VERSION 5.8 ;
BUSBITCHARS "[]" ;
DIVIDERCHAR "/" ;
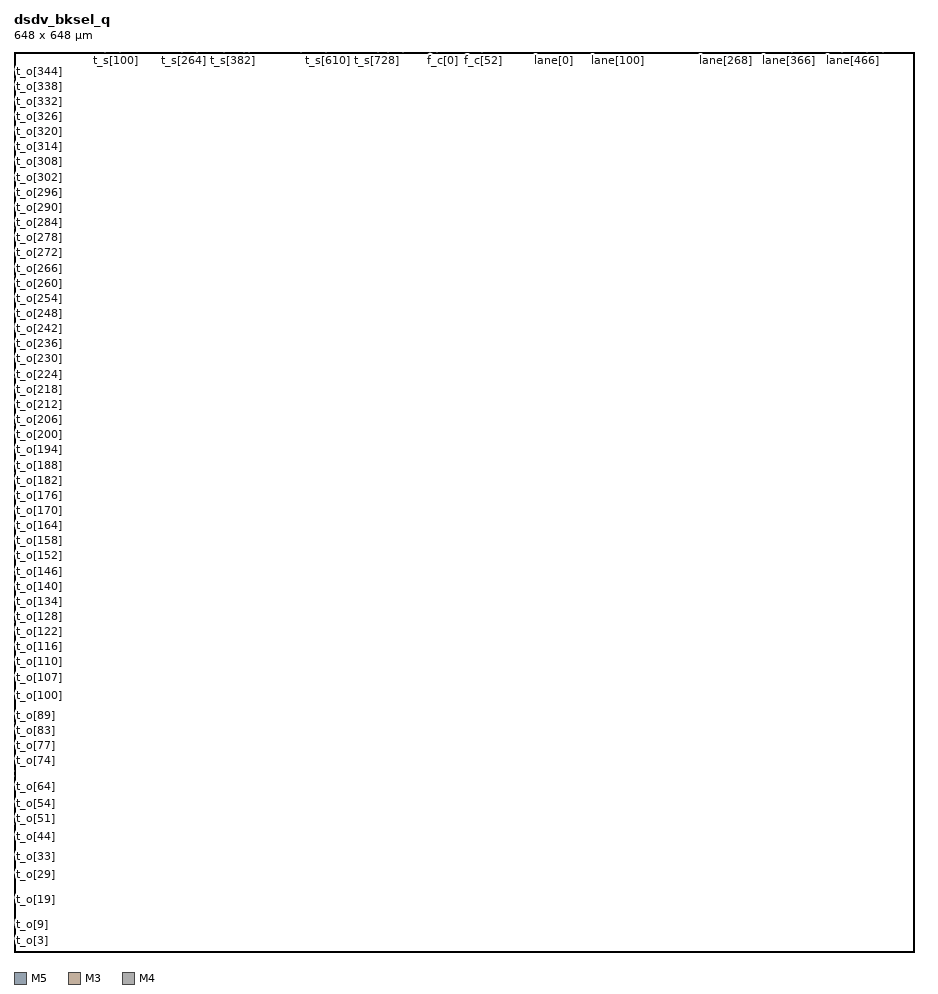
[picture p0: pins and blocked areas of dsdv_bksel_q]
MACRO dsdv_bksel_q
  CLASS BLOCK ;
  ORIGIN 0 0 ;
  FOREIGN dsdv_bksel_q 0 0 ;
  SIZE 648 BY 648 ;
  SYMMETRY X Y ;
  PIN ck
    DIRECTION INPUT ;
    USE SIGNAL ;
    PORT
      LAYER M5 ;
        RECT 304.5480 647.5200 304.5960 648.0000 ;
    END
  END ck
  PIN f_c[0]
    DIRECTION INPUT ;
    USE SIGNAL ;
    PORT
      LAYER M3 ;
        RECT 309.1320 647.9620 309.1500 648.0000 ;
    END
  END f_c[0]
  PIN f_c[10]
    DIRECTION INPUT ;
    USE SIGNAL ;
    PORT
      LAYER M3 ;
        RECT 314.7120 647.9620 314.7300 648.0000 ;
    END
  END f_c[10]
  PIN f_c[11]
    DIRECTION INPUT ;
    USE SIGNAL ;
    PORT
      LAYER M5 ;
        RECT 315.2640 647.9160 315.2880 648.0000 ;
    END
  END f_c[11]
  PIN f_c[12]
    DIRECTION INPUT ;
    USE SIGNAL ;
    PORT
      LAYER M3 ;
        RECT 315.8280 647.9620 315.8460 648.0000 ;
    END
  END f_c[12]
  PIN f_c[13]
    DIRECTION INPUT ;
    USE SIGNAL ;
    PORT
      LAYER M5 ;
        RECT 316.3680 647.9160 316.3920 648.0000 ;
    END
  END f_c[13]
  PIN f_c[14]
    DIRECTION INPUT ;
    USE SIGNAL ;
    PORT
      LAYER M3 ;
        RECT 316.9440 647.9620 316.9620 648.0000 ;
    END
  END f_c[14]
  PIN f_c[15]
    DIRECTION INPUT ;
    USE SIGNAL ;
    PORT
      LAYER M5 ;
        RECT 317.4720 647.9160 317.4960 648.0000 ;
    END
  END f_c[15]
  PIN f_c[16]
    DIRECTION INPUT ;
    USE SIGNAL ;
    PORT
      LAYER M3 ;
        RECT 318.0600 647.9620 318.0780 648.0000 ;
    END
  END f_c[16]
  PIN f_c[17]
    DIRECTION INPUT ;
    USE SIGNAL ;
    PORT
      LAYER M5 ;
        RECT 318.6240 647.9160 318.6480 648.0000 ;
    END
  END f_c[17]
  PIN f_c[18]
    DIRECTION INPUT ;
    USE SIGNAL ;
    PORT
      LAYER M3 ;
        RECT 319.1760 647.9620 319.1940 648.0000 ;
    END
  END f_c[18]
  PIN f_c[19]
    DIRECTION INPUT ;
    USE SIGNAL ;
    PORT
      LAYER M5 ;
        RECT 319.7280 647.9160 319.7520 648.0000 ;
    END
  END f_c[19]
  PIN f_c[1]
    DIRECTION INPUT ;
    USE SIGNAL ;
    PORT
      LAYER M5 ;
        RECT 309.6960 647.9160 309.7200 648.0000 ;
    END
  END f_c[1]
  PIN f_c[20]
    DIRECTION INPUT ;
    USE SIGNAL ;
    PORT
      LAYER M3 ;
        RECT 320.2920 647.9620 320.3100 648.0000 ;
    END
  END f_c[20]
  PIN f_c[21]
    DIRECTION INPUT ;
    USE SIGNAL ;
    PORT
      LAYER M5 ;
        RECT 320.8320 647.9160 320.8560 648.0000 ;
    END
  END f_c[21]
  PIN f_c[22]
    DIRECTION INPUT ;
    USE SIGNAL ;
    PORT
      LAYER M3 ;
        RECT 321.3720 647.9620 321.3900 648.0000 ;
    END
  END f_c[22]
  PIN f_c[23]
    DIRECTION INPUT ;
    USE SIGNAL ;
    PORT
      LAYER M5 ;
        RECT 321.9360 647.9160 321.9600 648.0000 ;
    END
  END f_c[23]
  PIN f_c[24]
    DIRECTION INPUT ;
    USE SIGNAL ;
    PORT
      LAYER M3 ;
        RECT 322.4880 647.9620 322.5060 648.0000 ;
    END
  END f_c[24]
  PIN f_c[25]
    DIRECTION INPUT ;
    USE SIGNAL ;
    PORT
      LAYER M5 ;
        RECT 323.0400 647.9160 323.0640 648.0000 ;
    END
  END f_c[25]
  PIN f_c[26]
    DIRECTION INPUT ;
    USE SIGNAL ;
    PORT
      LAYER M3 ;
        RECT 323.6040 647.9620 323.6220 648.0000 ;
    END
  END f_c[26]
  PIN f_c[27]
    DIRECTION INPUT ;
    USE SIGNAL ;
    PORT
      LAYER M5 ;
        RECT 324.1920 647.9160 324.2160 648.0000 ;
    END
  END f_c[27]
  PIN f_c[28]
    DIRECTION INPUT ;
    USE SIGNAL ;
    PORT
      LAYER M3 ;
        RECT 324.7200 647.9620 324.7380 648.0000 ;
    END
  END f_c[28]
  PIN f_c[29]
    DIRECTION INPUT ;
    USE SIGNAL ;
    PORT
      LAYER M5 ;
        RECT 325.2960 647.9160 325.3200 648.0000 ;
    END
  END f_c[29]
  PIN f_c[2]
    DIRECTION INPUT ;
    USE SIGNAL ;
    PORT
      LAYER M3 ;
        RECT 310.2480 647.9620 310.2660 648.0000 ;
    END
  END f_c[2]
  PIN f_c[30]
    DIRECTION INPUT ;
    USE SIGNAL ;
    PORT
      LAYER M3 ;
        RECT 325.8360 647.9620 325.8540 648.0000 ;
    END
  END f_c[30]
  PIN f_c[31]
    DIRECTION INPUT ;
    USE SIGNAL ;
    PORT
      LAYER M5 ;
        RECT 326.4000 647.9160 326.4240 648.0000 ;
    END
  END f_c[31]
  PIN f_c[32]
    DIRECTION INPUT ;
    USE SIGNAL ;
    PORT
      LAYER M3 ;
        RECT 326.9520 647.9620 326.9700 648.0000 ;
    END
  END f_c[32]
  PIN f_c[33]
    DIRECTION INPUT ;
    USE SIGNAL ;
    PORT
      LAYER M5 ;
        RECT 327.5040 647.9160 327.5280 648.0000 ;
    END
  END f_c[33]
  PIN f_c[34]
    DIRECTION INPUT ;
    USE SIGNAL ;
    PORT
      LAYER M3 ;
        RECT 328.0680 647.9620 328.0860 648.0000 ;
    END
  END f_c[34]
  PIN f_c[35]
    DIRECTION INPUT ;
    USE SIGNAL ;
    PORT
      LAYER M5 ;
        RECT 328.6080 647.9160 328.6320 648.0000 ;
    END
  END f_c[35]
  PIN f_c[36]
    DIRECTION INPUT ;
    USE SIGNAL ;
    PORT
      LAYER M3 ;
        RECT 329.1840 647.9620 329.2020 648.0000 ;
    END
  END f_c[36]
  PIN f_c[37]
    DIRECTION INPUT ;
    USE SIGNAL ;
    PORT
      LAYER M5 ;
        RECT 329.7120 647.9160 329.7360 648.0000 ;
    END
  END f_c[37]
  PIN f_c[38]
    DIRECTION INPUT ;
    USE SIGNAL ;
    PORT
      LAYER M3 ;
        RECT 330.3000 647.9620 330.3180 648.0000 ;
    END
  END f_c[38]
  PIN f_c[39]
    DIRECTION INPUT ;
    USE SIGNAL ;
    PORT
      LAYER M5 ;
        RECT 330.8640 647.9160 330.8880 648.0000 ;
    END
  END f_c[39]
  PIN f_c[3]
    DIRECTION INPUT ;
    USE SIGNAL ;
    PORT
      LAYER M5 ;
        RECT 310.8000 647.9160 310.8240 648.0000 ;
    END
  END f_c[3]
  PIN f_c[40]
    DIRECTION INPUT ;
    USE SIGNAL ;
    PORT
      LAYER M3 ;
        RECT 331.4160 647.9620 331.4340 648.0000 ;
    END
  END f_c[40]
  PIN f_c[41]
    DIRECTION INPUT ;
    USE SIGNAL ;
    PORT
      LAYER M5 ;
        RECT 331.9680 647.9160 331.9920 648.0000 ;
    END
  END f_c[41]
  PIN f_c[42]
    DIRECTION INPUT ;
    USE SIGNAL ;
    PORT
      LAYER M3 ;
        RECT 332.5320 647.9620 332.5500 648.0000 ;
    END
  END f_c[42]
  PIN f_c[43]
    DIRECTION INPUT ;
    USE SIGNAL ;
    PORT
      LAYER M5 ;
        RECT 333.0720 647.9160 333.0960 648.0000 ;
    END
  END f_c[43]
  PIN f_c[44]
    DIRECTION INPUT ;
    USE SIGNAL ;
    PORT
      LAYER M3 ;
        RECT 333.6120 647.9620 333.6300 648.0000 ;
    END
  END f_c[44]
  PIN f_c[45]
    DIRECTION INPUT ;
    USE SIGNAL ;
    PORT
      LAYER M5 ;
        RECT 334.1760 647.9160 334.2000 648.0000 ;
    END
  END f_c[45]
  PIN f_c[46]
    DIRECTION INPUT ;
    USE SIGNAL ;
    PORT
      LAYER M3 ;
        RECT 334.7280 647.9620 334.7460 648.0000 ;
    END
  END f_c[46]
  PIN f_c[47]
    DIRECTION INPUT ;
    USE SIGNAL ;
    PORT
      LAYER M5 ;
        RECT 335.2800 647.9160 335.3040 648.0000 ;
    END
  END f_c[47]
  PIN f_c[48]
    DIRECTION INPUT ;
    USE SIGNAL ;
    PORT
      LAYER M3 ;
        RECT 335.8440 647.9620 335.8620 648.0000 ;
    END
  END f_c[48]
  PIN f_c[49]
    DIRECTION INPUT ;
    USE SIGNAL ;
    PORT
      LAYER M5 ;
        RECT 336.4320 647.9160 336.4560 648.0000 ;
    END
  END f_c[49]
  PIN f_c[4]
    DIRECTION INPUT ;
    USE SIGNAL ;
    PORT
      LAYER M3 ;
        RECT 311.3640 647.9620 311.3820 648.0000 ;
    END
  END f_c[4]
  PIN f_c[50]
    DIRECTION INPUT ;
    USE SIGNAL ;
    PORT
      LAYER M3 ;
        RECT 336.9600 647.9620 336.9780 648.0000 ;
    END
  END f_c[50]
  PIN f_c[51]
    DIRECTION INPUT ;
    USE SIGNAL ;
    PORT
      LAYER M5 ;
        RECT 337.5360 647.9160 337.5600 648.0000 ;
    END
  END f_c[51]
  PIN f_c[52]
    DIRECTION INPUT ;
    USE SIGNAL ;
    PORT
      LAYER M3 ;
        RECT 338.0760 647.9620 338.0940 648.0000 ;
    END
  END f_c[52]
  PIN f_c[53]
    DIRECTION INPUT ;
    USE SIGNAL ;
    PORT
      LAYER M5 ;
        RECT 338.6400 647.9160 338.6640 648.0000 ;
    END
  END f_c[53]
  PIN f_c[54]
    DIRECTION INPUT ;
    USE SIGNAL ;
    PORT
      LAYER M3 ;
        RECT 339.1920 647.9620 339.2100 648.0000 ;
    END
  END f_c[54]
  PIN f_c[55]
    DIRECTION INPUT ;
    USE SIGNAL ;
    PORT
      LAYER M5 ;
        RECT 339.7440 647.9160 339.7680 648.0000 ;
    END
  END f_c[55]
  PIN f_c[56]
    DIRECTION INPUT ;
    USE SIGNAL ;
    PORT
      LAYER M3 ;
        RECT 340.3080 647.9620 340.3260 648.0000 ;
    END
  END f_c[56]
  PIN f_c[57]
    DIRECTION INPUT ;
    USE SIGNAL ;
    PORT
      LAYER M5 ;
        RECT 340.8480 647.9160 340.8720 648.0000 ;
    END
  END f_c[57]
  PIN f_c[58]
    DIRECTION INPUT ;
    USE SIGNAL ;
    PORT
      LAYER M3 ;
        RECT 341.4240 647.9620 341.4420 648.0000 ;
    END
  END f_c[58]
  PIN f_c[59]
    DIRECTION INPUT ;
    USE SIGNAL ;
    PORT
      LAYER M5 ;
        RECT 341.9520 647.9160 341.9760 648.0000 ;
    END
  END f_c[59]
  PIN f_c[5]
    DIRECTION INPUT ;
    USE SIGNAL ;
    PORT
      LAYER M5 ;
        RECT 311.9520 647.9160 311.9760 648.0000 ;
    END
  END f_c[5]
  PIN f_c[60]
    DIRECTION INPUT ;
    USE SIGNAL ;
    PORT
      LAYER M3 ;
        RECT 342.5400 647.9620 342.5580 648.0000 ;
    END
  END f_c[60]
  PIN f_c[61]
    DIRECTION INPUT ;
    USE SIGNAL ;
    PORT
      LAYER M5 ;
        RECT 343.1040 647.9160 343.1280 648.0000 ;
    END
  END f_c[61]
  PIN f_c[62]
    DIRECTION INPUT ;
    USE SIGNAL ;
    PORT
      LAYER M3 ;
        RECT 343.6560 647.9620 343.6740 648.0000 ;
    END
  END f_c[62]
  PIN f_c[63]
    DIRECTION INPUT ;
    USE SIGNAL ;
    PORT
      LAYER M5 ;
        RECT 344.2080 647.9160 344.2320 648.0000 ;
    END
  END f_c[63]
  PIN f_c[64]
    DIRECTION INPUT ;
    USE SIGNAL ;
    PORT
      LAYER M3 ;
        RECT 344.7720 647.9620 344.7900 648.0000 ;
    END
  END f_c[64]
  PIN f_c[65]
    DIRECTION INPUT ;
    USE SIGNAL ;
    PORT
      LAYER M5 ;
        RECT 345.3120 647.9160 345.3360 648.0000 ;
    END
  END f_c[65]
  PIN f_c[6]
    DIRECTION INPUT ;
    USE SIGNAL ;
    PORT
      LAYER M3 ;
        RECT 312.4800 647.9620 312.4980 648.0000 ;
    END
  END f_c[6]
  PIN f_c[7]
    DIRECTION INPUT ;
    USE SIGNAL ;
    PORT
      LAYER M5 ;
        RECT 313.0560 647.9160 313.0800 648.0000 ;
    END
  END f_c[7]
  PIN f_c[8]
    DIRECTION INPUT ;
    USE SIGNAL ;
    PORT
      LAYER M3 ;
        RECT 313.5960 647.9620 313.6140 648.0000 ;
    END
  END f_c[8]
  PIN f_c[9]
    DIRECTION INPUT ;
    USE SIGNAL ;
    PORT
      LAYER M5 ;
        RECT 314.1600 647.9160 314.1840 648.0000 ;
    END
  END f_c[9]
  PIN f_cr
    DIRECTION INPUT ;
    USE SIGNAL ;
    PORT
      LAYER M3 ;
        RECT 346.6800 647.9620 346.6980 648.0000 ;
    END
  END f_cr
  PIN lane[0]
    DIRECTION INPUT ;
    USE SIGNAL ;
    PORT
      LAYER M3 ;
        RECT 389.0160 647.9620 389.0340 648.0000 ;
    END
  END lane[0]
  PIN lane[100]
    DIRECTION INPUT ;
    USE SIGNAL ;
    PORT
      LAYER M3 ;
        RECT 435.1680 647.9620 435.1860 648.0000 ;
    END
  END lane[100]
  PIN lane[101]
    DIRECTION INPUT ;
    USE SIGNAL ;
    PORT
      LAYER M5 ;
        RECT 435.6000 647.9160 435.6240 648.0000 ;
    END
  END lane[101]
  PIN lane[102]
    DIRECTION INPUT ;
    USE SIGNAL ;
    PORT
      LAYER M3 ;
        RECT 436.0680 647.9620 436.0860 648.0000 ;
    END
  END lane[102]
  PIN lane[103]
    DIRECTION INPUT ;
    USE SIGNAL ;
    PORT
      LAYER M5 ;
        RECT 436.5600 647.9160 436.5840 648.0000 ;
    END
  END lane[103]
  PIN lane[104]
    DIRECTION INPUT ;
    USE SIGNAL ;
    PORT
      LAYER M3 ;
        RECT 437.0040 647.9620 437.0220 648.0000 ;
    END
  END lane[104]
  PIN lane[105]
    DIRECTION INPUT ;
    USE SIGNAL ;
    PORT
      LAYER M5 ;
        RECT 437.4720 647.9160 437.4960 648.0000 ;
    END
  END lane[105]
  PIN lane[106]
    DIRECTION INPUT ;
    USE SIGNAL ;
    PORT
      LAYER M3 ;
        RECT 437.9400 647.9620 437.9580 648.0000 ;
    END
  END lane[106]
  PIN lane[107]
    DIRECTION INPUT ;
    USE SIGNAL ;
    PORT
      LAYER M5 ;
        RECT 438.3840 647.9160 438.4080 648.0000 ;
    END
  END lane[107]
  PIN lane[108]
    DIRECTION INPUT ;
    USE SIGNAL ;
    PORT
      LAYER M3 ;
        RECT 438.8400 647.9620 438.8580 648.0000 ;
    END
  END lane[108]
  PIN lane[109]
    DIRECTION INPUT ;
    USE SIGNAL ;
    PORT
      LAYER M5 ;
        RECT 439.2960 647.9160 439.3200 648.0000 ;
    END
  END lane[109]
  PIN lane[10]
    DIRECTION INPUT ;
    USE SIGNAL ;
    PORT
      LAYER M3 ;
        RECT 393.6240 647.9620 393.6420 648.0000 ;
    END
  END lane[10]
  PIN lane[110]
    DIRECTION INPUT ;
    USE SIGNAL ;
    PORT
      LAYER M3 ;
        RECT 439.7760 647.9620 439.7940 648.0000 ;
    END
  END lane[110]
  PIN lane[111]
    DIRECTION INPUT ;
    USE SIGNAL ;
    PORT
      LAYER M5 ;
        RECT 440.2080 647.9160 440.2320 648.0000 ;
    END
  END lane[111]
  PIN lane[112]
    DIRECTION INPUT ;
    USE SIGNAL ;
    PORT
      LAYER M3 ;
        RECT 440.7120 647.9620 440.7300 648.0000 ;
    END
  END lane[112]
  PIN lane[113]
    DIRECTION INPUT ;
    USE SIGNAL ;
    PORT
      LAYER M5 ;
        RECT 441.1680 647.9160 441.1920 648.0000 ;
    END
  END lane[113]
  PIN lane[114]
    DIRECTION INPUT ;
    USE SIGNAL ;
    PORT
      LAYER M3 ;
        RECT 441.6120 647.9620 441.6300 648.0000 ;
    END
  END lane[114]
  PIN lane[115]
    DIRECTION INPUT ;
    USE SIGNAL ;
    PORT
      LAYER M5 ;
        RECT 442.0800 647.9160 442.1040 648.0000 ;
    END
  END lane[115]
  PIN lane[116]
    DIRECTION INPUT ;
    USE SIGNAL ;
    PORT
      LAYER M3 ;
        RECT 442.5480 647.9620 442.5660 648.0000 ;
    END
  END lane[116]
  PIN lane[117]
    DIRECTION INPUT ;
    USE SIGNAL ;
    PORT
      LAYER M5 ;
        RECT 442.9920 647.9160 443.0160 648.0000 ;
    END
  END lane[117]
  PIN lane[118]
    DIRECTION INPUT ;
    USE SIGNAL ;
    PORT
      LAYER M3 ;
        RECT 443.4480 647.9620 443.4660 648.0000 ;
    END
  END lane[118]
  PIN lane[119]
    DIRECTION INPUT ;
    USE SIGNAL ;
    PORT
      LAYER M5 ;
        RECT 443.9040 647.9160 443.9280 648.0000 ;
    END
  END lane[119]
  PIN lane[11]
    DIRECTION INPUT ;
    USE SIGNAL ;
    PORT
      LAYER M5 ;
        RECT 394.0800 647.9160 394.1040 648.0000 ;
    END
  END lane[11]
  PIN lane[120]
    DIRECTION INPUT ;
    USE SIGNAL ;
    PORT
      LAYER M3 ;
        RECT 444.3840 647.9620 444.4020 648.0000 ;
    END
  END lane[120]
  PIN lane[121]
    DIRECTION INPUT ;
    USE SIGNAL ;
    PORT
      LAYER M5 ;
        RECT 444.8640 647.9160 444.8880 648.0000 ;
    END
  END lane[121]
  PIN lane[122]
    DIRECTION INPUT ;
    USE SIGNAL ;
    PORT
      LAYER M3 ;
        RECT 445.3560 647.9620 445.3740 648.0000 ;
    END
  END lane[122]
  PIN lane[123]
    DIRECTION INPUT ;
    USE SIGNAL ;
    PORT
      LAYER M5 ;
        RECT 445.7760 647.9160 445.8000 648.0000 ;
    END
  END lane[123]
  PIN lane[124]
    DIRECTION INPUT ;
    USE SIGNAL ;
    PORT
      LAYER M3 ;
        RECT 446.2200 647.9620 446.2380 648.0000 ;
    END
  END lane[124]
  PIN lane[125]
    DIRECTION INPUT ;
    USE SIGNAL ;
    PORT
      LAYER M5 ;
        RECT 446.6880 647.9160 446.7120 648.0000 ;
    END
  END lane[125]
  PIN lane[126]
    DIRECTION INPUT ;
    USE SIGNAL ;
    PORT
      LAYER M3 ;
        RECT 447.1560 647.9620 447.1740 648.0000 ;
    END
  END lane[126]
  PIN lane[127]
    DIRECTION INPUT ;
    USE SIGNAL ;
    PORT
      LAYER M5 ;
        RECT 447.6000 647.9160 447.6240 648.0000 ;
    END
  END lane[127]
  PIN lane[128]
    DIRECTION INPUT ;
    USE SIGNAL ;
    PORT
      LAYER M3 ;
        RECT 448.0920 647.9620 448.1100 648.0000 ;
    END
  END lane[128]
  PIN lane[129]
    DIRECTION INPUT ;
    USE SIGNAL ;
    PORT
      LAYER M5 ;
        RECT 448.5120 647.9160 448.5360 648.0000 ;
    END
  END lane[129]
  PIN lane[12]
    DIRECTION INPUT ;
    USE SIGNAL ;
    PORT
      LAYER M3 ;
        RECT 394.5600 647.9620 394.5780 648.0000 ;
    END
  END lane[12]
  PIN lane[130]
    DIRECTION INPUT ;
    USE SIGNAL ;
    PORT
      LAYER M3 ;
        RECT 448.9920 647.9620 449.0100 648.0000 ;
    END
  END lane[130]
  PIN lane[131]
    DIRECTION INPUT ;
    USE SIGNAL ;
    PORT
      LAYER M5 ;
        RECT 449.4720 647.9160 449.4960 648.0000 ;
    END
  END lane[131]
  PIN lane[132]
    DIRECTION INPUT ;
    USE SIGNAL ;
    PORT
      LAYER M3 ;
        RECT 449.9280 647.9620 449.9460 648.0000 ;
    END
  END lane[132]
  PIN lane[133]
    DIRECTION INPUT ;
    USE SIGNAL ;
    PORT
      LAYER M5 ;
        RECT 450.3840 647.9160 450.4080 648.0000 ;
    END
  END lane[133]
  PIN lane[134]
    DIRECTION INPUT ;
    USE SIGNAL ;
    PORT
      LAYER M3 ;
        RECT 450.8280 647.9620 450.8460 648.0000 ;
    END
  END lane[134]
  PIN lane[135]
    DIRECTION INPUT ;
    USE SIGNAL ;
    PORT
      LAYER M5 ;
        RECT 451.2960 647.9160 451.3200 648.0000 ;
    END
  END lane[135]
  PIN lane[136]
    DIRECTION INPUT ;
    USE SIGNAL ;
    PORT
      LAYER M3 ;
        RECT 451.7640 647.9620 451.7820 648.0000 ;
    END
  END lane[136]
  PIN lane[137]
    DIRECTION INPUT ;
    USE SIGNAL ;
    PORT
      LAYER M5 ;
        RECT 452.2080 647.9160 452.2320 648.0000 ;
    END
  END lane[137]
  PIN lane[138]
    DIRECTION INPUT ;
    USE SIGNAL ;
    PORT
      LAYER M3 ;
        RECT 452.7000 647.9620 452.7180 648.0000 ;
    END
  END lane[138]
  PIN lane[139]
    DIRECTION INPUT ;
    USE SIGNAL ;
    PORT
      LAYER M5 ;
        RECT 453.1680 647.9160 453.1920 648.0000 ;
    END
  END lane[139]
  PIN lane[13]
    DIRECTION INPUT ;
    USE SIGNAL ;
    PORT
      LAYER M5 ;
        RECT 395.0400 647.9160 395.0640 648.0000 ;
    END
  END lane[13]
  PIN lane[140]
    DIRECTION INPUT ;
    USE SIGNAL ;
    PORT
      LAYER M3 ;
        RECT 453.6000 647.9620 453.6180 648.0000 ;
    END
  END lane[140]
  PIN lane[141]
    DIRECTION INPUT ;
    USE SIGNAL ;
    PORT
      LAYER M5 ;
        RECT 454.0800 647.9160 454.1040 648.0000 ;
    END
  END lane[141]
  PIN lane[142]
    DIRECTION INPUT ;
    USE SIGNAL ;
    PORT
      LAYER M3 ;
        RECT 454.5360 647.9620 454.5540 648.0000 ;
    END
  END lane[142]
  PIN lane[143]
    DIRECTION INPUT ;
    USE SIGNAL ;
    PORT
      LAYER M5 ;
        RECT 454.9920 647.9160 455.0160 648.0000 ;
    END
  END lane[143]
  PIN lane[144]
    DIRECTION INPUT ;
    USE SIGNAL ;
    PORT
      LAYER M3 ;
        RECT 455.4720 647.9620 455.4900 648.0000 ;
    END
  END lane[144]
  PIN lane[145]
    DIRECTION INPUT ;
    USE SIGNAL ;
    PORT
      LAYER M5 ;
        RECT 455.9040 647.9160 455.9280 648.0000 ;
    END
  END lane[145]
  PIN lane[146]
    DIRECTION INPUT ;
    USE SIGNAL ;
    PORT
      LAYER M3 ;
        RECT 456.3720 647.9620 456.3900 648.0000 ;
    END
  END lane[146]
  PIN lane[147]
    DIRECTION INPUT ;
    USE SIGNAL ;
    PORT
      LAYER M5 ;
        RECT 456.8160 647.9160 456.8400 648.0000 ;
    END
  END lane[147]
  PIN lane[148]
    DIRECTION INPUT ;
    USE SIGNAL ;
    PORT
      LAYER M3 ;
        RECT 457.3080 647.9620 457.3260 648.0000 ;
    END
  END lane[148]
  PIN lane[149]
    DIRECTION INPUT ;
    USE SIGNAL ;
    PORT
      LAYER M5 ;
        RECT 457.7760 647.9160 457.8000 648.0000 ;
    END
  END lane[149]
  PIN lane[14]
    DIRECTION INPUT ;
    USE SIGNAL ;
    PORT
      LAYER M3 ;
        RECT 395.4960 647.9620 395.5140 648.0000 ;
    END
  END lane[14]
  PIN lane[150]
    DIRECTION INPUT ;
    USE SIGNAL ;
    PORT
      LAYER M3 ;
        RECT 458.2440 647.9620 458.2620 648.0000 ;
    END
  END lane[150]
  PIN lane[151]
    DIRECTION INPUT ;
    USE SIGNAL ;
    PORT
      LAYER M5 ;
        RECT 458.6880 647.9160 458.7120 648.0000 ;
    END
  END lane[151]
  PIN lane[152]
    DIRECTION INPUT ;
    USE SIGNAL ;
    PORT
      LAYER M3 ;
        RECT 459.1440 647.9620 459.1620 648.0000 ;
    END
  END lane[152]
  PIN lane[153]
    DIRECTION INPUT ;
    USE SIGNAL ;
    PORT
      LAYER M5 ;
        RECT 459.6000 647.9160 459.6240 648.0000 ;
    END
  END lane[153]
  PIN lane[154]
    DIRECTION INPUT ;
    USE SIGNAL ;
    PORT
      LAYER M3 ;
        RECT 460.0800 647.9620 460.0980 648.0000 ;
    END
  END lane[154]
  PIN lane[155]
    DIRECTION INPUT ;
    USE SIGNAL ;
    PORT
      LAYER M5 ;
        RECT 460.5120 647.9160 460.5360 648.0000 ;
    END
  END lane[155]
  PIN lane[156]
    DIRECTION INPUT ;
    USE SIGNAL ;
    PORT
      LAYER M3 ;
        RECT 460.9800 647.9620 460.9980 648.0000 ;
    END
  END lane[156]
  PIN lane[157]
    DIRECTION INPUT ;
    USE SIGNAL ;
    PORT
      LAYER M5 ;
        RECT 461.4720 647.9160 461.4960 648.0000 ;
    END
  END lane[157]
  PIN lane[158]
    DIRECTION INPUT ;
    USE SIGNAL ;
    PORT
      LAYER M3 ;
        RECT 461.9160 647.9620 461.9340 648.0000 ;
    END
  END lane[158]
  PIN lane[159]
    DIRECTION INPUT ;
    USE SIGNAL ;
    PORT
      LAYER M5 ;
        RECT 462.3840 647.9160 462.4080 648.0000 ;
    END
  END lane[159]
  PIN lane[15]
    DIRECTION INPUT ;
    USE SIGNAL ;
    PORT
      LAYER M5 ;
        RECT 395.9520 647.9160 395.9760 648.0000 ;
    END
  END lane[15]
  PIN lane[160]
    DIRECTION INPUT ;
    USE SIGNAL ;
    PORT
      LAYER M3 ;
        RECT 462.8520 647.9620 462.8700 648.0000 ;
    END
  END lane[160]
  PIN lane[161]
    DIRECTION INPUT ;
    USE SIGNAL ;
    PORT
      LAYER M5 ;
        RECT 463.2960 647.9160 463.3200 648.0000 ;
    END
  END lane[161]
  PIN lane[162]
    DIRECTION INPUT ;
    USE SIGNAL ;
    PORT
      LAYER M3 ;
        RECT 463.7520 647.9620 463.7700 648.0000 ;
    END
  END lane[162]
  PIN lane[163]
    DIRECTION INPUT ;
    USE SIGNAL ;
    PORT
      LAYER M5 ;
        RECT 464.2080 647.9160 464.2320 648.0000 ;
    END
  END lane[163]
  PIN lane[164]
    DIRECTION INPUT ;
    USE SIGNAL ;
    PORT
      LAYER M3 ;
        RECT 464.6880 647.9620 464.7060 648.0000 ;
    END
  END lane[164]
  PIN lane[165]
    DIRECTION INPUT ;
    USE SIGNAL ;
    PORT
      LAYER M5 ;
        RECT 465.1200 647.9160 465.1440 648.0000 ;
    END
  END lane[165]
  PIN lane[166]
    DIRECTION INPUT ;
    USE SIGNAL ;
    PORT
      LAYER M3 ;
        RECT 465.6240 647.9620 465.6420 648.0000 ;
    END
  END lane[166]
  PIN lane[167]
    DIRECTION INPUT ;
    USE SIGNAL ;
    PORT
      LAYER M5 ;
        RECT 466.0800 647.9160 466.1040 648.0000 ;
    END
  END lane[167]
  PIN lane[168]
    DIRECTION INPUT ;
    USE SIGNAL ;
    PORT
      LAYER M3 ;
        RECT 466.5240 647.9620 466.5420 648.0000 ;
    END
  END lane[168]
  PIN lane[169]
    DIRECTION INPUT ;
    USE SIGNAL ;
    PORT
      LAYER M5 ;
        RECT 466.9920 647.9160 467.0160 648.0000 ;
    END
  END lane[169]
  PIN lane[16]
    DIRECTION INPUT ;
    USE SIGNAL ;
    PORT
      LAYER M3 ;
        RECT 396.3960 647.9620 396.4140 648.0000 ;
    END
  END lane[16]
  PIN lane[170]
    DIRECTION INPUT ;
    USE SIGNAL ;
    PORT
      LAYER M3 ;
        RECT 467.4600 647.9620 467.4780 648.0000 ;
    END
  END lane[170]
  PIN lane[171]
    DIRECTION INPUT ;
    USE SIGNAL ;
    PORT
      LAYER M5 ;
        RECT 467.9040 647.9160 467.9280 648.0000 ;
    END
  END lane[171]
  PIN lane[172]
    DIRECTION INPUT ;
    USE SIGNAL ;
    PORT
      LAYER M3 ;
        RECT 468.3600 647.9620 468.3780 648.0000 ;
    END
  END lane[172]
  PIN lane[173]
    DIRECTION INPUT ;
    USE SIGNAL ;
    PORT
      LAYER M5 ;
        RECT 468.8160 647.9160 468.8400 648.0000 ;
    END
  END lane[173]
  PIN lane[174]
    DIRECTION INPUT ;
    USE SIGNAL ;
    PORT
      LAYER M3 ;
        RECT 469.2960 647.9620 469.3140 648.0000 ;
    END
  END lane[174]
  PIN lane[175]
    DIRECTION INPUT ;
    USE SIGNAL ;
    PORT
      LAYER M5 ;
        RECT 469.7760 647.9160 469.8000 648.0000 ;
    END
  END lane[175]
  PIN lane[176]
    DIRECTION INPUT ;
    USE SIGNAL ;
    PORT
      LAYER M3 ;
        RECT 470.2320 647.9620 470.2500 648.0000 ;
    END
  END lane[176]
  PIN lane[177]
    DIRECTION INPUT ;
    USE SIGNAL ;
    PORT
      LAYER M5 ;
        RECT 470.6880 647.9160 470.7120 648.0000 ;
    END
  END lane[177]
  PIN lane[178]
    DIRECTION INPUT ;
    USE SIGNAL ;
    PORT
      LAYER M3 ;
        RECT 471.1320 647.9620 471.1500 648.0000 ;
    END
  END lane[178]
  PIN lane[179]
    DIRECTION INPUT ;
    USE SIGNAL ;
    PORT
      LAYER M5 ;
        RECT 471.6000 647.9160 471.6240 648.0000 ;
    END
  END lane[179]
  PIN lane[17]
    DIRECTION INPUT ;
    USE SIGNAL ;
    PORT
      LAYER M5 ;
        RECT 396.8640 647.9160 396.8880 648.0000 ;
    END
  END lane[17]
  PIN lane[180]
    DIRECTION INPUT ;
    USE SIGNAL ;
    PORT
      LAYER M3 ;
        RECT 472.0680 647.9620 472.0860 648.0000 ;
    END
  END lane[180]
  PIN lane[181]
    DIRECTION INPUT ;
    USE SIGNAL ;
    PORT
      LAYER M5 ;
        RECT 472.5120 647.9160 472.5360 648.0000 ;
    END
  END lane[181]
  PIN lane[182]
    DIRECTION INPUT ;
    USE SIGNAL ;
    PORT
      LAYER M3 ;
        RECT 473.0040 647.9620 473.0220 648.0000 ;
    END
  END lane[182]
  PIN lane[183]
    DIRECTION INPUT ;
    USE SIGNAL ;
    PORT
      LAYER M5 ;
        RECT 473.4240 647.9160 473.4480 648.0000 ;
    END
  END lane[183]
  PIN lane[184]
    DIRECTION INPUT ;
    USE SIGNAL ;
    PORT
      LAYER M3 ;
        RECT 473.9040 647.9620 473.9220 648.0000 ;
    END
  END lane[184]
  PIN lane[185]
    DIRECTION INPUT ;
    USE SIGNAL ;
    PORT
      LAYER M5 ;
        RECT 474.3840 647.9160 474.4080 648.0000 ;
    END
  END lane[185]
  PIN lane[186]
    DIRECTION INPUT ;
    USE SIGNAL ;
    PORT
      LAYER M3 ;
        RECT 474.8400 647.9620 474.8580 648.0000 ;
    END
  END lane[186]
  PIN lane[187]
    DIRECTION INPUT ;
    USE SIGNAL ;
    PORT
      LAYER M5 ;
        RECT 475.2960 647.9160 475.3200 648.0000 ;
    END
  END lane[187]
  PIN lane[188]
    DIRECTION INPUT ;
    USE SIGNAL ;
    PORT
      LAYER M3 ;
        RECT 475.7400 647.9620 475.7580 648.0000 ;
    END
  END lane[188]
  PIN lane[189]
    DIRECTION INPUT ;
    USE SIGNAL ;
    PORT
      LAYER M5 ;
        RECT 476.2080 647.9160 476.2320 648.0000 ;
    END
  END lane[189]
  PIN lane[18]
    DIRECTION INPUT ;
    USE SIGNAL ;
    PORT
      LAYER M3 ;
        RECT 397.3320 647.9620 397.3500 648.0000 ;
    END
  END lane[18]
  PIN lane[190]
    DIRECTION INPUT ;
    USE SIGNAL ;
    PORT
      LAYER M3 ;
        RECT 476.6760 647.9620 476.6940 648.0000 ;
    END
  END lane[190]
  PIN lane[191]
    DIRECTION INPUT ;
    USE SIGNAL ;
    PORT
      LAYER M5 ;
        RECT 477.1200 647.9160 477.1440 648.0000 ;
    END
  END lane[191]
  PIN lane[192]
    DIRECTION INPUT ;
    USE SIGNAL ;
    PORT
      LAYER M3 ;
        RECT 477.5760 647.9620 477.5940 648.0000 ;
    END
  END lane[192]
  PIN lane[193]
    DIRECTION INPUT ;
    USE SIGNAL ;
    PORT
      LAYER M5 ;
        RECT 478.0800 647.9160 478.1040 648.0000 ;
    END
  END lane[193]
  PIN lane[194]
    DIRECTION INPUT ;
    USE SIGNAL ;
    PORT
      LAYER M3 ;
        RECT 478.5120 647.9620 478.5300 648.0000 ;
    END
  END lane[194]
  PIN lane[195]
    DIRECTION INPUT ;
    USE SIGNAL ;
    PORT
      LAYER M5 ;
        RECT 478.9920 647.9160 479.0160 648.0000 ;
    END
  END lane[195]
  PIN lane[196]
    DIRECTION INPUT ;
    USE SIGNAL ;
    PORT
      LAYER M3 ;
        RECT 479.4480 647.9620 479.4660 648.0000 ;
    END
  END lane[196]
  PIN lane[197]
    DIRECTION INPUT ;
    USE SIGNAL ;
    PORT
      LAYER M5 ;
        RECT 479.9040 647.9160 479.9280 648.0000 ;
    END
  END lane[197]
  PIN lane[198]
    DIRECTION INPUT ;
    USE SIGNAL ;
    PORT
      LAYER M3 ;
        RECT 480.3840 647.9620 480.4020 648.0000 ;
    END
  END lane[198]
  PIN lane[199]
    DIRECTION INPUT ;
    USE SIGNAL ;
    PORT
      LAYER M5 ;
        RECT 480.8160 647.9160 480.8400 648.0000 ;
    END
  END lane[199]
  PIN lane[19]
    DIRECTION INPUT ;
    USE SIGNAL ;
    PORT
      LAYER M5 ;
        RECT 397.7760 647.9160 397.8000 648.0000 ;
    END
  END lane[19]
  PIN lane[1]
    DIRECTION INPUT ;
    USE SIGNAL ;
    PORT
      LAYER M5 ;
        RECT 389.4720 647.9160 389.4960 648.0000 ;
    END
  END lane[1]
  PIN lane[200]
    DIRECTION INPUT ;
    USE SIGNAL ;
    PORT
      LAYER M3 ;
        RECT 481.2840 647.9620 481.3020 648.0000 ;
    END
  END lane[200]
  PIN lane[201]
    DIRECTION INPUT ;
    USE SIGNAL ;
    PORT
      LAYER M5 ;
        RECT 481.7760 647.9160 481.8000 648.0000 ;
    END
  END lane[201]
  PIN lane[202]
    DIRECTION INPUT ;
    USE SIGNAL ;
    PORT
      LAYER M3 ;
        RECT 482.2200 647.9620 482.2380 648.0000 ;
    END
  END lane[202]
  PIN lane[203]
    DIRECTION INPUT ;
    USE SIGNAL ;
    PORT
      LAYER M5 ;
        RECT 482.6880 647.9160 482.7120 648.0000 ;
    END
  END lane[203]
  PIN lane[204]
    DIRECTION INPUT ;
    USE SIGNAL ;
    PORT
      LAYER M3 ;
        RECT 483.1560 647.9620 483.1740 648.0000 ;
    END
  END lane[204]
  PIN lane[205]
    DIRECTION INPUT ;
    USE SIGNAL ;
    PORT
      LAYER M5 ;
        RECT 483.6000 647.9160 483.6240 648.0000 ;
    END
  END lane[205]
  PIN lane[206]
    DIRECTION INPUT ;
    USE SIGNAL ;
    PORT
      LAYER M3 ;
        RECT 484.0560 647.9620 484.0740 648.0000 ;
    END
  END lane[206]
  PIN lane[207]
    DIRECTION INPUT ;
    USE SIGNAL ;
    PORT
      LAYER M5 ;
        RECT 484.5120 647.9160 484.5360 648.0000 ;
    END
  END lane[207]
  PIN lane[208]
    DIRECTION INPUT ;
    USE SIGNAL ;
    PORT
      LAYER M3 ;
        RECT 484.9920 647.9620 485.0100 648.0000 ;
    END
  END lane[208]
  PIN lane[209]
    DIRECTION INPUT ;
    USE SIGNAL ;
    PORT
      LAYER M5 ;
        RECT 485.4240 647.9160 485.4480 648.0000 ;
    END
  END lane[209]
  PIN lane[20]
    DIRECTION INPUT ;
    USE SIGNAL ;
    PORT
      LAYER M3 ;
        RECT 398.2320 647.9620 398.2500 648.0000 ;
    END
  END lane[20]
  PIN lane[210]
    DIRECTION INPUT ;
    USE SIGNAL ;
    PORT
      LAYER M3 ;
        RECT 485.8920 647.9620 485.9100 648.0000 ;
    END
  END lane[210]
  PIN lane[211]
    DIRECTION INPUT ;
    USE SIGNAL ;
    PORT
      LAYER M5 ;
        RECT 486.3840 647.9160 486.4080 648.0000 ;
    END
  END lane[211]
  PIN lane[212]
    DIRECTION INPUT ;
    USE SIGNAL ;
    PORT
      LAYER M3 ;
        RECT 486.8280 647.9620 486.8460 648.0000 ;
    END
  END lane[212]
  PIN lane[213]
    DIRECTION INPUT ;
    USE SIGNAL ;
    PORT
      LAYER M5 ;
        RECT 487.2960 647.9160 487.3200 648.0000 ;
    END
  END lane[213]
  PIN lane[214]
    DIRECTION INPUT ;
    USE SIGNAL ;
    PORT
      LAYER M3 ;
        RECT 487.7640 647.9620 487.7820 648.0000 ;
    END
  END lane[214]
  PIN lane[215]
    DIRECTION INPUT ;
    USE SIGNAL ;
    PORT
      LAYER M5 ;
        RECT 488.2080 647.9160 488.2320 648.0000 ;
    END
  END lane[215]
  PIN lane[216]
    DIRECTION INPUT ;
    USE SIGNAL ;
    PORT
      LAYER M3 ;
        RECT 488.6640 647.9620 488.6820 648.0000 ;
    END
  END lane[216]
  PIN lane[217]
    DIRECTION INPUT ;
    USE SIGNAL ;
    PORT
      LAYER M5 ;
        RECT 489.1200 647.9160 489.1440 648.0000 ;
    END
  END lane[217]
  PIN lane[218]
    DIRECTION INPUT ;
    USE SIGNAL ;
    PORT
      LAYER M3 ;
        RECT 489.6000 647.9620 489.6180 648.0000 ;
    END
  END lane[218]
  PIN lane[219]
    DIRECTION INPUT ;
    USE SIGNAL ;
    PORT
      LAYER M5 ;
        RECT 490.0800 647.9160 490.1040 648.0000 ;
    END
  END lane[219]
  PIN lane[21]
    DIRECTION INPUT ;
    USE SIGNAL ;
    PORT
      LAYER M5 ;
        RECT 398.6880 647.9160 398.7120 648.0000 ;
    END
  END lane[21]
  PIN lane[220]
    DIRECTION INPUT ;
    USE SIGNAL ;
    PORT
      LAYER M3 ;
        RECT 490.5360 647.9620 490.5540 648.0000 ;
    END
  END lane[220]
  PIN lane[221]
    DIRECTION INPUT ;
    USE SIGNAL ;
    PORT
      LAYER M5 ;
        RECT 490.9920 647.9160 491.0160 648.0000 ;
    END
  END lane[221]
  PIN lane[222]
    DIRECTION INPUT ;
    USE SIGNAL ;
    PORT
      LAYER M3 ;
        RECT 491.4360 647.9620 491.4540 648.0000 ;
    END
  END lane[222]
  PIN lane[223]
    DIRECTION INPUT ;
    USE SIGNAL ;
    PORT
      LAYER M5 ;
        RECT 491.9040 647.9160 491.9280 648.0000 ;
    END
  END lane[223]
  PIN lane[224]
    DIRECTION INPUT ;
    USE SIGNAL ;
    PORT
      LAYER M3 ;
        RECT 492.3720 647.9620 492.3900 648.0000 ;
    END
  END lane[224]
  PIN lane[225]
    DIRECTION INPUT ;
    USE SIGNAL ;
    PORT
      LAYER M5 ;
        RECT 492.8160 647.9160 492.8400 648.0000 ;
    END
  END lane[225]
  PIN lane[226]
    DIRECTION INPUT ;
    USE SIGNAL ;
    PORT
      LAYER M3 ;
        RECT 493.2720 647.9620 493.2900 648.0000 ;
    END
  END lane[226]
  PIN lane[227]
    DIRECTION INPUT ;
    USE SIGNAL ;
    PORT
      LAYER M5 ;
        RECT 493.7280 647.9160 493.7520 648.0000 ;
    END
  END lane[227]
  PIN lane[228]
    DIRECTION INPUT ;
    USE SIGNAL ;
    PORT
      LAYER M3 ;
        RECT 494.2080 647.9620 494.2260 648.0000 ;
    END
  END lane[228]
  PIN lane[229]
    DIRECTION INPUT ;
    USE SIGNAL ;
    PORT
      LAYER M5 ;
        RECT 494.6880 647.9160 494.7120 648.0000 ;
    END
  END lane[229]
  PIN lane[22]
    DIRECTION INPUT ;
    USE SIGNAL ;
    PORT
      LAYER M3 ;
        RECT 399.1680 647.9620 399.1860 648.0000 ;
    END
  END lane[22]
  PIN lane[230]
    DIRECTION INPUT ;
    USE SIGNAL ;
    PORT
      LAYER M3 ;
        RECT 495.1440 647.9620 495.1620 648.0000 ;
    END
  END lane[230]
  PIN lane[231]
    DIRECTION INPUT ;
    USE SIGNAL ;
    PORT
      LAYER M5 ;
        RECT 495.6000 647.9160 495.6240 648.0000 ;
    END
  END lane[231]
  PIN lane[232]
    DIRECTION INPUT ;
    USE SIGNAL ;
    PORT
      LAYER M3 ;
        RECT 496.0440 647.9620 496.0620 648.0000 ;
    END
  END lane[232]
  PIN lane[233]
    DIRECTION INPUT ;
    USE SIGNAL ;
    PORT
      LAYER M5 ;
        RECT 496.5120 647.9160 496.5360 648.0000 ;
    END
  END lane[233]
  PIN lane[234]
    DIRECTION INPUT ;
    USE SIGNAL ;
    PORT
      LAYER M3 ;
        RECT 496.9800 647.9620 496.9980 648.0000 ;
    END
  END lane[234]
  PIN lane[235]
    DIRECTION INPUT ;
    USE SIGNAL ;
    PORT
      LAYER M5 ;
        RECT 497.4240 647.9160 497.4480 648.0000 ;
    END
  END lane[235]
  PIN lane[236]
    DIRECTION INPUT ;
    USE SIGNAL ;
    PORT
      LAYER M3 ;
        RECT 497.9160 647.9620 497.9340 648.0000 ;
    END
  END lane[236]
  PIN lane[237]
    DIRECTION INPUT ;
    USE SIGNAL ;
    PORT
      LAYER M5 ;
        RECT 498.3840 647.9160 498.4080 648.0000 ;
    END
  END lane[237]
  PIN lane[238]
    DIRECTION INPUT ;
    USE SIGNAL ;
    PORT
      LAYER M3 ;
        RECT 498.8160 647.9620 498.8340 648.0000 ;
    END
  END lane[238]
  PIN lane[239]
    DIRECTION INPUT ;
    USE SIGNAL ;
    PORT
      LAYER M5 ;
        RECT 499.2960 647.9160 499.3200 648.0000 ;
    END
  END lane[239]
  PIN lane[23]
    DIRECTION INPUT ;
    USE SIGNAL ;
    PORT
      LAYER M5 ;
        RECT 399.6480 647.9160 399.6720 648.0000 ;
    END
  END lane[23]
  PIN lane[240]
    DIRECTION INPUT ;
    USE SIGNAL ;
    PORT
      LAYER M3 ;
        RECT 499.7520 647.9620 499.7700 648.0000 ;
    END
  END lane[240]
  PIN lane[241]
    DIRECTION INPUT ;
    USE SIGNAL ;
    PORT
      LAYER M5 ;
        RECT 500.2080 647.9160 500.2320 648.0000 ;
    END
  END lane[241]
  PIN lane[242]
    DIRECTION INPUT ;
    USE SIGNAL ;
    PORT
      LAYER M3 ;
        RECT 500.6880 647.9620 500.7060 648.0000 ;
    END
  END lane[242]
  PIN lane[243]
    DIRECTION INPUT ;
    USE SIGNAL ;
    PORT
      LAYER M5 ;
        RECT 501.1200 647.9160 501.1440 648.0000 ;
    END
  END lane[243]
  PIN lane[244]
    DIRECTION INPUT ;
    USE SIGNAL ;
    PORT
      LAYER M3 ;
        RECT 501.5880 647.9620 501.6060 648.0000 ;
    END
  END lane[244]
  PIN lane[245]
    DIRECTION INPUT ;
    USE SIGNAL ;
    PORT
      LAYER M5 ;
        RECT 502.0320 647.9160 502.0560 648.0000 ;
    END
  END lane[245]
  PIN lane[246]
    DIRECTION INPUT ;
    USE SIGNAL ;
    PORT
      LAYER M3 ;
        RECT 502.5240 647.9620 502.5420 648.0000 ;
    END
  END lane[246]
  PIN lane[247]
    DIRECTION INPUT ;
    USE SIGNAL ;
    PORT
      LAYER M5 ;
        RECT 502.9920 647.9160 503.0160 648.0000 ;
    END
  END lane[247]
  PIN lane[248]
    DIRECTION INPUT ;
    USE SIGNAL ;
    PORT
      LAYER M3 ;
        RECT 503.4240 647.9620 503.4420 648.0000 ;
    END
  END lane[248]
  PIN lane[249]
    DIRECTION INPUT ;
    USE SIGNAL ;
    PORT
      LAYER M5 ;
        RECT 503.9040 647.9160 503.9280 648.0000 ;
    END
  END lane[249]
  PIN lane[24]
    DIRECTION INPUT ;
    USE SIGNAL ;
    PORT
      LAYER M3 ;
        RECT 400.1040 647.9620 400.1220 648.0000 ;
    END
  END lane[24]
  PIN lane[250]
    DIRECTION INPUT ;
    USE SIGNAL ;
    PORT
      LAYER M3 ;
        RECT 504.3600 647.9620 504.3780 648.0000 ;
    END
  END lane[250]
  PIN lane[251]
    DIRECTION INPUT ;
    USE SIGNAL ;
    PORT
      LAYER M5 ;
        RECT 504.8160 647.9160 504.8400 648.0000 ;
    END
  END lane[251]
  PIN lane[252]
    DIRECTION INPUT ;
    USE SIGNAL ;
    PORT
      LAYER M3 ;
        RECT 505.2960 647.9620 505.3140 648.0000 ;
    END
  END lane[252]
  PIN lane[253]
    DIRECTION INPUT ;
    USE SIGNAL ;
    PORT
      LAYER M5 ;
        RECT 505.7280 647.9160 505.7520 648.0000 ;
    END
  END lane[253]
  PIN lane[254]
    DIRECTION INPUT ;
    USE SIGNAL ;
    PORT
      LAYER M3 ;
        RECT 506.1960 647.9620 506.2140 648.0000 ;
    END
  END lane[254]
  PIN lane[255]
    DIRECTION INPUT ;
    USE SIGNAL ;
    PORT
      LAYER M5 ;
        RECT 506.6880 647.9160 506.7120 648.0000 ;
    END
  END lane[255]
  PIN lane[256]
    DIRECTION INPUT ;
    USE SIGNAL ;
    PORT
      LAYER M3 ;
        RECT 507.1320 647.9620 507.1500 648.0000 ;
    END
  END lane[256]
  PIN lane[257]
    DIRECTION INPUT ;
    USE SIGNAL ;
    PORT
      LAYER M5 ;
        RECT 507.6000 647.9160 507.6240 648.0000 ;
    END
  END lane[257]
  PIN lane[258]
    DIRECTION INPUT ;
    USE SIGNAL ;
    PORT
      LAYER M3 ;
        RECT 508.0680 647.9620 508.0860 648.0000 ;
    END
  END lane[258]
  PIN lane[259]
    DIRECTION INPUT ;
    USE SIGNAL ;
    PORT
      LAYER M5 ;
        RECT 508.5120 647.9160 508.5360 648.0000 ;
    END
  END lane[259]
  PIN lane[25]
    DIRECTION INPUT ;
    USE SIGNAL ;
    PORT
      LAYER M5 ;
        RECT 400.5600 647.9160 400.5840 648.0000 ;
    END
  END lane[25]
  PIN lane[260]
    DIRECTION INPUT ;
    USE SIGNAL ;
    PORT
      LAYER M3 ;
        RECT 508.9680 647.9620 508.9860 648.0000 ;
    END
  END lane[260]
  PIN lane[261]
    DIRECTION INPUT ;
    USE SIGNAL ;
    PORT
      LAYER M5 ;
        RECT 509.4240 647.9160 509.4480 648.0000 ;
    END
  END lane[261]
  PIN lane[262]
    DIRECTION INPUT ;
    USE SIGNAL ;
    PORT
      LAYER M3 ;
        RECT 509.9040 647.9620 509.9220 648.0000 ;
    END
  END lane[262]
  PIN lane[263]
    DIRECTION INPUT ;
    USE SIGNAL ;
    PORT
      LAYER M5 ;
        RECT 510.3360 647.9160 510.3600 648.0000 ;
    END
  END lane[263]
  PIN lane[264]
    DIRECTION INPUT ;
    USE SIGNAL ;
    PORT
      LAYER M3 ;
        RECT 510.8040 647.9620 510.8220 648.0000 ;
    END
  END lane[264]
  PIN lane[265]
    DIRECTION INPUT ;
    USE SIGNAL ;
    PORT
      LAYER M5 ;
        RECT 511.2960 647.9160 511.3200 648.0000 ;
    END
  END lane[265]
  PIN lane[266]
    DIRECTION INPUT ;
    USE SIGNAL ;
    PORT
      LAYER M3 ;
        RECT 511.7400 647.9620 511.7580 648.0000 ;
    END
  END lane[266]
  PIN lane[267]
    DIRECTION INPUT ;
    USE SIGNAL ;
    PORT
      LAYER M5 ;
        RECT 512.2080 647.9160 512.2320 648.0000 ;
    END
  END lane[267]
  PIN lane[268]
    DIRECTION INPUT ;
    USE SIGNAL ;
    PORT
      LAYER M3 ;
        RECT 512.6760 647.9620 512.6940 648.0000 ;
    END
  END lane[268]
  PIN lane[269]
    DIRECTION INPUT ;
    USE SIGNAL ;
    PORT
      LAYER M5 ;
        RECT 513.1200 647.9160 513.1440 648.0000 ;
    END
  END lane[269]
  PIN lane[26]
    DIRECTION INPUT ;
    USE SIGNAL ;
    PORT
      LAYER M3 ;
        RECT 401.0040 647.9620 401.0220 648.0000 ;
    END
  END lane[26]
  PIN lane[270]
    DIRECTION INPUT ;
    USE SIGNAL ;
    PORT
      LAYER M3 ;
        RECT 513.5760 647.9620 513.5940 648.0000 ;
    END
  END lane[270]
  PIN lane[271]
    DIRECTION INPUT ;
    USE SIGNAL ;
    PORT
      LAYER M5 ;
        RECT 514.0320 647.9160 514.0560 648.0000 ;
    END
  END lane[271]
  PIN lane[272]
    DIRECTION INPUT ;
    USE SIGNAL ;
    PORT
      LAYER M3 ;
        RECT 514.5120 647.9620 514.5300 648.0000 ;
    END
  END lane[272]
  PIN lane[273]
    DIRECTION INPUT ;
    USE SIGNAL ;
    PORT
      LAYER M5 ;
        RECT 514.9920 647.9160 515.0160 648.0000 ;
    END
  END lane[273]
  PIN lane[274]
    DIRECTION INPUT ;
    USE SIGNAL ;
    PORT
      LAYER M3 ;
        RECT 515.4480 647.9620 515.4660 648.0000 ;
    END
  END lane[274]
  PIN lane[275]
    DIRECTION INPUT ;
    USE SIGNAL ;
    PORT
      LAYER M5 ;
        RECT 515.9040 647.9160 515.9280 648.0000 ;
    END
  END lane[275]
  PIN lane[276]
    DIRECTION INPUT ;
    USE SIGNAL ;
    PORT
      LAYER M3 ;
        RECT 516.3480 647.9620 516.3660 648.0000 ;
    END
  END lane[276]
  PIN lane[277]
    DIRECTION INPUT ;
    USE SIGNAL ;
    PORT
      LAYER M5 ;
        RECT 516.8160 647.9160 516.8400 648.0000 ;
    END
  END lane[277]
  PIN lane[278]
    DIRECTION INPUT ;
    USE SIGNAL ;
    PORT
      LAYER M3 ;
        RECT 517.2840 647.9620 517.3020 648.0000 ;
    END
  END lane[278]
  PIN lane[279]
    DIRECTION INPUT ;
    USE SIGNAL ;
    PORT
      LAYER M5 ;
        RECT 517.7280 647.9160 517.7520 648.0000 ;
    END
  END lane[279]
  PIN lane[27]
    DIRECTION INPUT ;
    USE SIGNAL ;
    PORT
      LAYER M5 ;
        RECT 401.4720 647.9160 401.4960 648.0000 ;
    END
  END lane[27]
  PIN lane[280]
    DIRECTION INPUT ;
    USE SIGNAL ;
    PORT
      LAYER M3 ;
        RECT 518.2200 647.9620 518.2380 648.0000 ;
    END
  END lane[280]
  PIN lane[281]
    DIRECTION INPUT ;
    USE SIGNAL ;
    PORT
      LAYER M5 ;
        RECT 518.6400 647.9160 518.6640 648.0000 ;
    END
  END lane[281]
  PIN lane[282]
    DIRECTION INPUT ;
    USE SIGNAL ;
    PORT
      LAYER M3 ;
        RECT 519.1200 647.9620 519.1380 648.0000 ;
    END
  END lane[282]
  PIN lane[283]
    DIRECTION INPUT ;
    USE SIGNAL ;
    PORT
      LAYER M5 ;
        RECT 519.6000 647.9160 519.6240 648.0000 ;
    END
  END lane[283]
  PIN lane[284]
    DIRECTION INPUT ;
    USE SIGNAL ;
    PORT
      LAYER M3 ;
        RECT 520.0560 647.9620 520.0740 648.0000 ;
    END
  END lane[284]
  PIN lane[285]
    DIRECTION INPUT ;
    USE SIGNAL ;
    PORT
      LAYER M5 ;
        RECT 520.5120 647.9160 520.5360 648.0000 ;
    END
  END lane[285]
  PIN lane[286]
    DIRECTION INPUT ;
    USE SIGNAL ;
    PORT
      LAYER M3 ;
        RECT 520.9560 647.9620 520.9740 648.0000 ;
    END
  END lane[286]
  PIN lane[287]
    DIRECTION INPUT ;
    USE SIGNAL ;
    PORT
      LAYER M5 ;
        RECT 521.4240 647.9160 521.4480 648.0000 ;
    END
  END lane[287]
  PIN lane[288]
    DIRECTION INPUT ;
    USE SIGNAL ;
    PORT
      LAYER M3 ;
        RECT 521.8920 647.9620 521.9100 648.0000 ;
    END
  END lane[288]
  PIN lane[289]
    DIRECTION INPUT ;
    USE SIGNAL ;
    PORT
      LAYER M5 ;
        RECT 522.3360 647.9160 522.3600 648.0000 ;
    END
  END lane[289]
  PIN lane[28]
    DIRECTION INPUT ;
    USE SIGNAL ;
    PORT
      LAYER M3 ;
        RECT 401.9400 647.9620 401.9580 648.0000 ;
    END
  END lane[28]
  PIN lane[290]
    DIRECTION INPUT ;
    USE SIGNAL ;
    PORT
      LAYER M3 ;
        RECT 522.8280 647.9620 522.8460 648.0000 ;
    END
  END lane[290]
  PIN lane[291]
    DIRECTION INPUT ;
    USE SIGNAL ;
    PORT
      LAYER M5 ;
        RECT 523.2960 647.9160 523.3200 648.0000 ;
    END
  END lane[291]
  PIN lane[292]
    DIRECTION INPUT ;
    USE SIGNAL ;
    PORT
      LAYER M3 ;
        RECT 523.7280 647.9620 523.7460 648.0000 ;
    END
  END lane[292]
  PIN lane[293]
    DIRECTION INPUT ;
    USE SIGNAL ;
    PORT
      LAYER M5 ;
        RECT 524.2080 647.9160 524.2320 648.0000 ;
    END
  END lane[293]
  PIN lane[294]
    DIRECTION INPUT ;
    USE SIGNAL ;
    PORT
      LAYER M3 ;
        RECT 524.6640 647.9620 524.6820 648.0000 ;
    END
  END lane[294]
  PIN lane[295]
    DIRECTION INPUT ;
    USE SIGNAL ;
    PORT
      LAYER M5 ;
        RECT 525.1200 647.9160 525.1440 648.0000 ;
    END
  END lane[295]
  PIN lane[296]
    DIRECTION INPUT ;
    USE SIGNAL ;
    PORT
      LAYER M3 ;
        RECT 525.6000 647.9620 525.6180 648.0000 ;
    END
  END lane[296]
  PIN lane[297]
    DIRECTION INPUT ;
    USE SIGNAL ;
    PORT
      LAYER M5 ;
        RECT 526.0320 647.9160 526.0560 648.0000 ;
    END
  END lane[297]
  PIN lane[298]
    DIRECTION INPUT ;
    USE SIGNAL ;
    PORT
      LAYER M3 ;
        RECT 526.5000 647.9620 526.5180 648.0000 ;
    END
  END lane[298]
  PIN lane[299]
    DIRECTION INPUT ;
    USE SIGNAL ;
    PORT
      LAYER M5 ;
        RECT 526.9440 647.9160 526.9680 648.0000 ;
    END
  END lane[299]
  PIN lane[29]
    DIRECTION INPUT ;
    USE SIGNAL ;
    PORT
      LAYER M5 ;
        RECT 402.3840 647.9160 402.4080 648.0000 ;
    END
  END lane[29]
  PIN lane[2]
    DIRECTION INPUT ;
    USE SIGNAL ;
    PORT
      LAYER M3 ;
        RECT 389.9520 647.9620 389.9700 648.0000 ;
    END
  END lane[2]
  PIN lane[300]
    DIRECTION INPUT ;
    USE SIGNAL ;
    PORT
      LAYER M3 ;
        RECT 527.4360 647.9620 527.4540 648.0000 ;
    END
  END lane[300]
  PIN lane[301]
    DIRECTION INPUT ;
    USE SIGNAL ;
    PORT
      LAYER M5 ;
        RECT 527.9040 647.9160 527.9280 648.0000 ;
    END
  END lane[301]
  PIN lane[302]
    DIRECTION INPUT ;
    USE SIGNAL ;
    PORT
      LAYER M3 ;
        RECT 528.3360 647.9620 528.3540 648.0000 ;
    END
  END lane[302]
  PIN lane[303]
    DIRECTION INPUT ;
    USE SIGNAL ;
    PORT
      LAYER M5 ;
        RECT 528.8160 647.9160 528.8400 648.0000 ;
    END
  END lane[303]
  PIN lane[304]
    DIRECTION INPUT ;
    USE SIGNAL ;
    PORT
      LAYER M3 ;
        RECT 529.2720 647.9620 529.2900 648.0000 ;
    END
  END lane[304]
  PIN lane[305]
    DIRECTION INPUT ;
    USE SIGNAL ;
    PORT
      LAYER M5 ;
        RECT 529.7280 647.9160 529.7520 648.0000 ;
    END
  END lane[305]
  PIN lane[306]
    DIRECTION INPUT ;
    USE SIGNAL ;
    PORT
      LAYER M3 ;
        RECT 530.2080 647.9620 530.2260 648.0000 ;
    END
  END lane[306]
  PIN lane[307]
    DIRECTION INPUT ;
    USE SIGNAL ;
    PORT
      LAYER M5 ;
        RECT 530.6400 647.9160 530.6640 648.0000 ;
    END
  END lane[307]
  PIN lane[308]
    DIRECTION INPUT ;
    USE SIGNAL ;
    PORT
      LAYER M3 ;
        RECT 531.1080 647.9620 531.1260 648.0000 ;
    END
  END lane[308]
  PIN lane[309]
    DIRECTION INPUT ;
    USE SIGNAL ;
    PORT
      LAYER M5 ;
        RECT 531.6000 647.9160 531.6240 648.0000 ;
    END
  END lane[309]
  PIN lane[30]
    DIRECTION INPUT ;
    USE SIGNAL ;
    PORT
      LAYER M3 ;
        RECT 402.8760 647.9620 402.8940 648.0000 ;
    END
  END lane[30]
  PIN lane[310]
    DIRECTION INPUT ;
    USE SIGNAL ;
    PORT
      LAYER M3 ;
        RECT 532.0440 647.9620 532.0620 648.0000 ;
    END
  END lane[310]
  PIN lane[311]
    DIRECTION INPUT ;
    USE SIGNAL ;
    PORT
      LAYER M5 ;
        RECT 532.5120 647.9160 532.5360 648.0000 ;
    END
  END lane[311]
  PIN lane[312]
    DIRECTION INPUT ;
    USE SIGNAL ;
    PORT
      LAYER M3 ;
        RECT 532.9800 647.9620 532.9980 648.0000 ;
    END
  END lane[312]
  PIN lane[313]
    DIRECTION INPUT ;
    USE SIGNAL ;
    PORT
      LAYER M5 ;
        RECT 533.4240 647.9160 533.4480 648.0000 ;
    END
  END lane[313]
  PIN lane[314]
    DIRECTION INPUT ;
    USE SIGNAL ;
    PORT
      LAYER M3 ;
        RECT 533.8800 647.9620 533.8980 648.0000 ;
    END
  END lane[314]
  PIN lane[315]
    DIRECTION INPUT ;
    USE SIGNAL ;
    PORT
      LAYER M5 ;
        RECT 534.3360 647.9160 534.3600 648.0000 ;
    END
  END lane[315]
  PIN lane[316]
    DIRECTION INPUT ;
    USE SIGNAL ;
    PORT
      LAYER M3 ;
        RECT 534.8160 647.9620 534.8340 648.0000 ;
    END
  END lane[316]
  PIN lane[317]
    DIRECTION INPUT ;
    USE SIGNAL ;
    PORT
      LAYER M5 ;
        RECT 535.2480 647.9160 535.2720 648.0000 ;
    END
  END lane[317]
  PIN lane[318]
    DIRECTION INPUT ;
    USE SIGNAL ;
    PORT
      LAYER M3 ;
        RECT 535.7520 647.9620 535.7700 648.0000 ;
    END
  END lane[318]
  PIN lane[319]
    DIRECTION INPUT ;
    USE SIGNAL ;
    PORT
      LAYER M5 ;
        RECT 536.2080 647.9160 536.2320 648.0000 ;
    END
  END lane[319]
  PIN lane[31]
    DIRECTION INPUT ;
    USE SIGNAL ;
    PORT
      LAYER M5 ;
        RECT 403.3440 647.9160 403.3680 648.0000 ;
    END
  END lane[31]
  PIN lane[320]
    DIRECTION INPUT ;
    USE SIGNAL ;
    PORT
      LAYER M3 ;
        RECT 536.6520 647.9620 536.6700 648.0000 ;
    END
  END lane[320]
  PIN lane[321]
    DIRECTION INPUT ;
    USE SIGNAL ;
    PORT
      LAYER M5 ;
        RECT 537.1200 647.9160 537.1440 648.0000 ;
    END
  END lane[321]
  PIN lane[322]
    DIRECTION INPUT ;
    USE SIGNAL ;
    PORT
      LAYER M3 ;
        RECT 537.5880 647.9620 537.6060 648.0000 ;
    END
  END lane[322]
  PIN lane[323]
    DIRECTION INPUT ;
    USE SIGNAL ;
    PORT
      LAYER M5 ;
        RECT 538.0320 647.9160 538.0560 648.0000 ;
    END
  END lane[323]
  PIN lane[324]
    DIRECTION INPUT ;
    USE SIGNAL ;
    PORT
      LAYER M3 ;
        RECT 538.4880 647.9620 538.5060 648.0000 ;
    END
  END lane[324]
  PIN lane[325]
    DIRECTION INPUT ;
    USE SIGNAL ;
    PORT
      LAYER M5 ;
        RECT 538.9440 647.9160 538.9680 648.0000 ;
    END
  END lane[325]
  PIN lane[326]
    DIRECTION INPUT ;
    USE SIGNAL ;
    PORT
      LAYER M3 ;
        RECT 539.4240 647.9620 539.4420 648.0000 ;
    END
  END lane[326]
  PIN lane[327]
    DIRECTION INPUT ;
    USE SIGNAL ;
    PORT
      LAYER M5 ;
        RECT 539.9040 647.9160 539.9280 648.0000 ;
    END
  END lane[327]
  PIN lane[328]
    DIRECTION INPUT ;
    USE SIGNAL ;
    PORT
      LAYER M3 ;
        RECT 540.3600 647.9620 540.3780 648.0000 ;
    END
  END lane[328]
  PIN lane[329]
    DIRECTION INPUT ;
    USE SIGNAL ;
    PORT
      LAYER M5 ;
        RECT 540.8160 647.9160 540.8400 648.0000 ;
    END
  END lane[329]
  PIN lane[32]
    DIRECTION INPUT ;
    USE SIGNAL ;
    PORT
      LAYER M3 ;
        RECT 403.7760 647.9620 403.7940 648.0000 ;
    END
  END lane[32]
  PIN lane[330]
    DIRECTION INPUT ;
    USE SIGNAL ;
    PORT
      LAYER M3 ;
        RECT 541.2600 647.9620 541.2780 648.0000 ;
    END
  END lane[330]
  PIN lane[331]
    DIRECTION INPUT ;
    USE SIGNAL ;
    PORT
      LAYER M5 ;
        RECT 541.7280 647.9160 541.7520 648.0000 ;
    END
  END lane[331]
  PIN lane[332]
    DIRECTION INPUT ;
    USE SIGNAL ;
    PORT
      LAYER M3 ;
        RECT 542.1960 647.9620 542.2140 648.0000 ;
    END
  END lane[332]
  PIN lane[333]
    DIRECTION INPUT ;
    USE SIGNAL ;
    PORT
      LAYER M5 ;
        RECT 542.6400 647.9160 542.6640 648.0000 ;
    END
  END lane[333]
  PIN lane[334]
    DIRECTION INPUT ;
    USE SIGNAL ;
    PORT
      LAYER M3 ;
        RECT 543.1320 647.9620 543.1500 648.0000 ;
    END
  END lane[334]
  PIN lane[335]
    DIRECTION INPUT ;
    USE SIGNAL ;
    PORT
      LAYER M5 ;
        RECT 543.5520 647.9160 543.5760 648.0000 ;
    END
  END lane[335]
  PIN lane[336]
    DIRECTION INPUT ;
    USE SIGNAL ;
    PORT
      LAYER M3 ;
        RECT 544.0320 647.9620 544.0500 648.0000 ;
    END
  END lane[336]
  PIN lane[337]
    DIRECTION INPUT ;
    USE SIGNAL ;
    PORT
      LAYER M5 ;
        RECT 544.5120 647.9160 544.5360 648.0000 ;
    END
  END lane[337]
  PIN lane[338]
    DIRECTION INPUT ;
    USE SIGNAL ;
    PORT
      LAYER M3 ;
        RECT 544.9680 647.9620 544.9860 648.0000 ;
    END
  END lane[338]
  PIN lane[339]
    DIRECTION INPUT ;
    USE SIGNAL ;
    PORT
      LAYER M5 ;
        RECT 545.4240 647.9160 545.4480 648.0000 ;
    END
  END lane[339]
  PIN lane[33]
    DIRECTION INPUT ;
    USE SIGNAL ;
    PORT
      LAYER M5 ;
        RECT 404.2560 647.9160 404.2800 648.0000 ;
    END
  END lane[33]
  PIN lane[340]
    DIRECTION INPUT ;
    USE SIGNAL ;
    PORT
      LAYER M3 ;
        RECT 545.8680 647.9620 545.8860 648.0000 ;
    END
  END lane[340]
  PIN lane[341]
    DIRECTION INPUT ;
    USE SIGNAL ;
    PORT
      LAYER M5 ;
        RECT 546.3360 647.9160 546.3600 648.0000 ;
    END
  END lane[341]
  PIN lane[342]
    DIRECTION INPUT ;
    USE SIGNAL ;
    PORT
      LAYER M3 ;
        RECT 546.8040 647.9620 546.8220 648.0000 ;
    END
  END lane[342]
  PIN lane[343]
    DIRECTION INPUT ;
    USE SIGNAL ;
    PORT
      LAYER M5 ;
        RECT 547.2480 647.9160 547.2720 648.0000 ;
    END
  END lane[343]
  PIN lane[344]
    DIRECTION INPUT ;
    USE SIGNAL ;
    PORT
      LAYER M3 ;
        RECT 547.7400 647.9620 547.7580 648.0000 ;
    END
  END lane[344]
  PIN lane[345]
    DIRECTION INPUT ;
    USE SIGNAL ;
    PORT
      LAYER M5 ;
        RECT 548.2080 647.9160 548.2320 648.0000 ;
    END
  END lane[345]
  PIN lane[346]
    DIRECTION INPUT ;
    USE SIGNAL ;
    PORT
      LAYER M3 ;
        RECT 548.6400 647.9620 548.6580 648.0000 ;
    END
  END lane[346]
  PIN lane[347]
    DIRECTION INPUT ;
    USE SIGNAL ;
    PORT
      LAYER M5 ;
        RECT 549.1200 647.9160 549.1440 648.0000 ;
    END
  END lane[347]
  PIN lane[348]
    DIRECTION INPUT ;
    USE SIGNAL ;
    PORT
      LAYER M3 ;
        RECT 549.5760 647.9620 549.5940 648.0000 ;
    END
  END lane[348]
  PIN lane[349]
    DIRECTION INPUT ;
    USE SIGNAL ;
    PORT
      LAYER M5 ;
        RECT 550.0320 647.9160 550.0560 648.0000 ;
    END
  END lane[349]
  PIN lane[34]
    DIRECTION INPUT ;
    USE SIGNAL ;
    PORT
      LAYER M3 ;
        RECT 404.7120 647.9620 404.7300 648.0000 ;
    END
  END lane[34]
  PIN lane[350]
    DIRECTION INPUT ;
    USE SIGNAL ;
    PORT
      LAYER M3 ;
        RECT 550.5120 647.9620 550.5300 648.0000 ;
    END
  END lane[350]
  PIN lane[351]
    DIRECTION INPUT ;
    USE SIGNAL ;
    PORT
      LAYER M5 ;
        RECT 550.9440 647.9160 550.9680 648.0000 ;
    END
  END lane[351]
  PIN lane[352]
    DIRECTION INPUT ;
    USE SIGNAL ;
    PORT
      LAYER M3 ;
        RECT 551.4120 647.9620 551.4300 648.0000 ;
    END
  END lane[352]
  PIN lane[353]
    DIRECTION INPUT ;
    USE SIGNAL ;
    PORT
      LAYER M5 ;
        RECT 551.8560 647.9160 551.8800 648.0000 ;
    END
  END lane[353]
  PIN lane[354]
    DIRECTION INPUT ;
    USE SIGNAL ;
    PORT
      LAYER M3 ;
        RECT 552.3480 647.9620 552.3660 648.0000 ;
    END
  END lane[354]
  PIN lane[355]
    DIRECTION INPUT ;
    USE SIGNAL ;
    PORT
      LAYER M5 ;
        RECT 552.8160 647.9160 552.8400 648.0000 ;
    END
  END lane[355]
  PIN lane[356]
    DIRECTION INPUT ;
    USE SIGNAL ;
    PORT
      LAYER M3 ;
        RECT 553.2840 647.9620 553.3020 648.0000 ;
    END
  END lane[356]
  PIN lane[357]
    DIRECTION INPUT ;
    USE SIGNAL ;
    PORT
      LAYER M5 ;
        RECT 553.7280 647.9160 553.7520 648.0000 ;
    END
  END lane[357]
  PIN lane[358]
    DIRECTION INPUT ;
    USE SIGNAL ;
    PORT
      LAYER M3 ;
        RECT 554.1840 647.9620 554.2020 648.0000 ;
    END
  END lane[358]
  PIN lane[359]
    DIRECTION INPUT ;
    USE SIGNAL ;
    PORT
      LAYER M5 ;
        RECT 554.6400 647.9160 554.6640 648.0000 ;
    END
  END lane[359]
  PIN lane[35]
    DIRECTION INPUT ;
    USE SIGNAL ;
    PORT
      LAYER M5 ;
        RECT 405.1680 647.9160 405.1920 648.0000 ;
    END
  END lane[35]
  PIN lane[360]
    DIRECTION INPUT ;
    USE SIGNAL ;
    PORT
      LAYER M3 ;
        RECT 555.1200 647.9620 555.1380 648.0000 ;
    END
  END lane[360]
  PIN lane[361]
    DIRECTION INPUT ;
    USE SIGNAL ;
    PORT
      LAYER M5 ;
        RECT 555.5520 647.9160 555.5760 648.0000 ;
    END
  END lane[361]
  PIN lane[362]
    DIRECTION INPUT ;
    USE SIGNAL ;
    PORT
      LAYER M3 ;
        RECT 556.0200 647.9620 556.0380 648.0000 ;
    END
  END lane[362]
  PIN lane[363]
    DIRECTION INPUT ;
    USE SIGNAL ;
    PORT
      LAYER M5 ;
        RECT 556.5120 647.9160 556.5360 648.0000 ;
    END
  END lane[363]
  PIN lane[364]
    DIRECTION INPUT ;
    USE SIGNAL ;
    PORT
      LAYER M3 ;
        RECT 556.9560 647.9620 556.9740 648.0000 ;
    END
  END lane[364]
  PIN lane[365]
    DIRECTION INPUT ;
    USE SIGNAL ;
    PORT
      LAYER M5 ;
        RECT 557.4240 647.9160 557.4480 648.0000 ;
    END
  END lane[365]
  PIN lane[366]
    DIRECTION INPUT ;
    USE SIGNAL ;
    PORT
      LAYER M3 ;
        RECT 557.8920 647.9620 557.9100 648.0000 ;
    END
  END lane[366]
  PIN lane[367]
    DIRECTION INPUT ;
    USE SIGNAL ;
    PORT
      LAYER M5 ;
        RECT 558.3360 647.9160 558.3600 648.0000 ;
    END
  END lane[367]
  PIN lane[368]
    DIRECTION INPUT ;
    USE SIGNAL ;
    PORT
      LAYER M3 ;
        RECT 558.7920 647.9620 558.8100 648.0000 ;
    END
  END lane[368]
  PIN lane[369]
    DIRECTION INPUT ;
    USE SIGNAL ;
    PORT
      LAYER M5 ;
        RECT 559.2480 647.9160 559.2720 648.0000 ;
    END
  END lane[369]
  PIN lane[36]
    DIRECTION INPUT ;
    USE SIGNAL ;
    PORT
      LAYER M3 ;
        RECT 405.6480 647.9620 405.6660 648.0000 ;
    END
  END lane[36]
  PIN lane[370]
    DIRECTION INPUT ;
    USE SIGNAL ;
    PORT
      LAYER M3 ;
        RECT 559.7280 647.9620 559.7460 648.0000 ;
    END
  END lane[370]
  PIN lane[371]
    DIRECTION INPUT ;
    USE SIGNAL ;
    PORT
      LAYER M5 ;
        RECT 560.1600 647.9160 560.1840 648.0000 ;
    END
  END lane[371]
  PIN lane[372]
    DIRECTION INPUT ;
    USE SIGNAL ;
    PORT
      LAYER M3 ;
        RECT 560.6640 647.9620 560.6820 648.0000 ;
    END
  END lane[372]
  PIN lane[373]
    DIRECTION INPUT ;
    USE SIGNAL ;
    PORT
      LAYER M5 ;
        RECT 561.1200 647.9160 561.1440 648.0000 ;
    END
  END lane[373]
  PIN lane[374]
    DIRECTION INPUT ;
    USE SIGNAL ;
    PORT
      LAYER M3 ;
        RECT 561.5640 647.9620 561.5820 648.0000 ;
    END
  END lane[374]
  PIN lane[375]
    DIRECTION INPUT ;
    USE SIGNAL ;
    PORT
      LAYER M5 ;
        RECT 562.0320 647.9160 562.0560 648.0000 ;
    END
  END lane[375]
  PIN lane[376]
    DIRECTION INPUT ;
    USE SIGNAL ;
    PORT
      LAYER M3 ;
        RECT 562.5000 647.9620 562.5180 648.0000 ;
    END
  END lane[376]
  PIN lane[377]
    DIRECTION INPUT ;
    USE SIGNAL ;
    PORT
      LAYER M5 ;
        RECT 562.9440 647.9160 562.9680 648.0000 ;
    END
  END lane[377]
  PIN lane[378]
    DIRECTION INPUT ;
    USE SIGNAL ;
    PORT
      LAYER M3 ;
        RECT 563.4000 647.9620 563.4180 648.0000 ;
    END
  END lane[378]
  PIN lane[379]
    DIRECTION INPUT ;
    USE SIGNAL ;
    PORT
      LAYER M5 ;
        RECT 563.8560 647.9160 563.8800 648.0000 ;
    END
  END lane[379]
  PIN lane[37]
    DIRECTION INPUT ;
    USE SIGNAL ;
    PORT
      LAYER M5 ;
        RECT 406.0800 647.9160 406.1040 648.0000 ;
    END
  END lane[37]
  PIN lane[380]
    DIRECTION INPUT ;
    USE SIGNAL ;
    PORT
      LAYER M3 ;
        RECT 564.3360 647.9620 564.3540 648.0000 ;
    END
  END lane[380]
  PIN lane[381]
    DIRECTION INPUT ;
    USE SIGNAL ;
    PORT
      LAYER M5 ;
        RECT 564.8160 647.9160 564.8400 648.0000 ;
    END
  END lane[381]
  PIN lane[382]
    DIRECTION INPUT ;
    USE SIGNAL ;
    PORT
      LAYER M3 ;
        RECT 565.2720 647.9620 565.2900 648.0000 ;
    END
  END lane[382]
  PIN lane[383]
    DIRECTION INPUT ;
    USE SIGNAL ;
    PORT
      LAYER M5 ;
        RECT 565.7280 647.9160 565.7520 648.0000 ;
    END
  END lane[383]
  PIN lane[384]
    DIRECTION INPUT ;
    USE SIGNAL ;
    PORT
      LAYER M3 ;
        RECT 566.1720 647.9620 566.1900 648.0000 ;
    END
  END lane[384]
  PIN lane[385]
    DIRECTION INPUT ;
    USE SIGNAL ;
    PORT
      LAYER M5 ;
        RECT 566.6400 647.9160 566.6640 648.0000 ;
    END
  END lane[385]
  PIN lane[386]
    DIRECTION INPUT ;
    USE SIGNAL ;
    PORT
      LAYER M3 ;
        RECT 567.1080 647.9620 567.1260 648.0000 ;
    END
  END lane[386]
  PIN lane[387]
    DIRECTION INPUT ;
    USE SIGNAL ;
    PORT
      LAYER M5 ;
        RECT 567.5520 647.9160 567.5760 648.0000 ;
    END
  END lane[387]
  PIN lane[388]
    DIRECTION INPUT ;
    USE SIGNAL ;
    PORT
      LAYER M3 ;
        RECT 568.0440 647.9620 568.0620 648.0000 ;
    END
  END lane[388]
  PIN lane[389]
    DIRECTION INPUT ;
    USE SIGNAL ;
    PORT
      LAYER M5 ;
        RECT 568.4640 647.9160 568.4880 648.0000 ;
    END
  END lane[389]
  PIN lane[38]
    DIRECTION INPUT ;
    USE SIGNAL ;
    PORT
      LAYER M3 ;
        RECT 406.5480 647.9620 406.5660 648.0000 ;
    END
  END lane[38]
  PIN lane[390]
    DIRECTION INPUT ;
    USE SIGNAL ;
    PORT
      LAYER M3 ;
        RECT 568.9440 647.9620 568.9620 648.0000 ;
    END
  END lane[390]
  PIN lane[391]
    DIRECTION INPUT ;
    USE SIGNAL ;
    PORT
      LAYER M5 ;
        RECT 569.4240 647.9160 569.4480 648.0000 ;
    END
  END lane[391]
  PIN lane[392]
    DIRECTION INPUT ;
    USE SIGNAL ;
    PORT
      LAYER M3 ;
        RECT 569.8800 647.9620 569.8980 648.0000 ;
    END
  END lane[392]
  PIN lane[393]
    DIRECTION INPUT ;
    USE SIGNAL ;
    PORT
      LAYER M5 ;
        RECT 570.3360 647.9160 570.3600 648.0000 ;
    END
  END lane[393]
  PIN lane[394]
    DIRECTION INPUT ;
    USE SIGNAL ;
    PORT
      LAYER M3 ;
        RECT 570.7800 647.9620 570.7980 648.0000 ;
    END
  END lane[394]
  PIN lane[395]
    DIRECTION INPUT ;
    USE SIGNAL ;
    PORT
      LAYER M5 ;
        RECT 571.2480 647.9160 571.2720 648.0000 ;
    END
  END lane[395]
  PIN lane[396]
    DIRECTION INPUT ;
    USE SIGNAL ;
    PORT
      LAYER M3 ;
        RECT 571.7160 647.9620 571.7340 648.0000 ;
    END
  END lane[396]
  PIN lane[397]
    DIRECTION INPUT ;
    USE SIGNAL ;
    PORT
      LAYER M5 ;
        RECT 572.1600 647.9160 572.1840 648.0000 ;
    END
  END lane[397]
  PIN lane[398]
    DIRECTION INPUT ;
    USE SIGNAL ;
    PORT
      LAYER M3 ;
        RECT 572.6520 647.9620 572.6700 648.0000 ;
    END
  END lane[398]
  PIN lane[399]
    DIRECTION INPUT ;
    USE SIGNAL ;
    PORT
      LAYER M5 ;
        RECT 573.1200 647.9160 573.1440 648.0000 ;
    END
  END lane[399]
  PIN lane[39]
    DIRECTION INPUT ;
    USE SIGNAL ;
    PORT
      LAYER M5 ;
        RECT 406.9920 647.9160 407.0160 648.0000 ;
    END
  END lane[39]
  PIN lane[3]
    DIRECTION INPUT ;
    USE SIGNAL ;
    PORT
      LAYER M5 ;
        RECT 390.3840 647.9160 390.4080 648.0000 ;
    END
  END lane[3]
  PIN lane[400]
    DIRECTION INPUT ;
    USE SIGNAL ;
    PORT
      LAYER M3 ;
        RECT 573.5520 647.9620 573.5700 648.0000 ;
    END
  END lane[400]
  PIN lane[401]
    DIRECTION INPUT ;
    USE SIGNAL ;
    PORT
      LAYER M5 ;
        RECT 574.0320 647.9160 574.0560 648.0000 ;
    END
  END lane[401]
  PIN lane[402]
    DIRECTION INPUT ;
    USE SIGNAL ;
    PORT
      LAYER M3 ;
        RECT 574.4880 647.9620 574.5060 648.0000 ;
    END
  END lane[402]
  PIN lane[403]
    DIRECTION INPUT ;
    USE SIGNAL ;
    PORT
      LAYER M5 ;
        RECT 574.9440 647.9160 574.9680 648.0000 ;
    END
  END lane[403]
  PIN lane[404]
    DIRECTION INPUT ;
    USE SIGNAL ;
    PORT
      LAYER M3 ;
        RECT 575.4240 647.9620 575.4420 648.0000 ;
    END
  END lane[404]
  PIN lane[405]
    DIRECTION INPUT ;
    USE SIGNAL ;
    PORT
      LAYER M5 ;
        RECT 575.8560 647.9160 575.8800 648.0000 ;
    END
  END lane[405]
  PIN lane[406]
    DIRECTION INPUT ;
    USE SIGNAL ;
    PORT
      LAYER M3 ;
        RECT 576.3240 647.9620 576.3420 648.0000 ;
    END
  END lane[406]
  PIN lane[407]
    DIRECTION INPUT ;
    USE SIGNAL ;
    PORT
      LAYER M5 ;
        RECT 576.8160 647.9160 576.8400 648.0000 ;
    END
  END lane[407]
  PIN lane[408]
    DIRECTION INPUT ;
    USE SIGNAL ;
    PORT
      LAYER M3 ;
        RECT 577.2600 647.9620 577.2780 648.0000 ;
    END
  END lane[408]
  PIN lane[409]
    DIRECTION INPUT ;
    USE SIGNAL ;
    PORT
      LAYER M5 ;
        RECT 577.7280 647.9160 577.7520 648.0000 ;
    END
  END lane[409]
  PIN lane[40]
    DIRECTION INPUT ;
    USE SIGNAL ;
    PORT
      LAYER M3 ;
        RECT 407.4840 647.9620 407.5020 648.0000 ;
    END
  END lane[40]
  PIN lane[410]
    DIRECTION INPUT ;
    USE SIGNAL ;
    PORT
      LAYER M3 ;
        RECT 578.1960 647.9620 578.2140 648.0000 ;
    END
  END lane[410]
  PIN lane[411]
    DIRECTION INPUT ;
    USE SIGNAL ;
    PORT
      LAYER M5 ;
        RECT 578.6400 647.9160 578.6640 648.0000 ;
    END
  END lane[411]
  PIN lane[412]
    DIRECTION INPUT ;
    USE SIGNAL ;
    PORT
      LAYER M3 ;
        RECT 579.0960 647.9620 579.1140 648.0000 ;
    END
  END lane[412]
  PIN lane[413]
    DIRECTION INPUT ;
    USE SIGNAL ;
    PORT
      LAYER M5 ;
        RECT 579.5520 647.9160 579.5760 648.0000 ;
    END
  END lane[413]
  PIN lane[414]
    DIRECTION INPUT ;
    USE SIGNAL ;
    PORT
      LAYER M3 ;
        RECT 580.0320 647.9620 580.0500 648.0000 ;
    END
  END lane[414]
  PIN lane[415]
    DIRECTION INPUT ;
    USE SIGNAL ;
    PORT
      LAYER M5 ;
        RECT 580.4640 647.9160 580.4880 648.0000 ;
    END
  END lane[415]
  PIN lane[416]
    DIRECTION INPUT ;
    USE SIGNAL ;
    PORT
      LAYER M3 ;
        RECT 580.9320 647.9620 580.9500 648.0000 ;
    END
  END lane[416]
  PIN lane[417]
    DIRECTION INPUT ;
    USE SIGNAL ;
    PORT
      LAYER M5 ;
        RECT 581.4240 647.9160 581.4480 648.0000 ;
    END
  END lane[417]
  PIN lane[418]
    DIRECTION INPUT ;
    USE SIGNAL ;
    PORT
      LAYER M3 ;
        RECT 581.8680 647.9620 581.8860 648.0000 ;
    END
  END lane[418]
  PIN lane[419]
    DIRECTION INPUT ;
    USE SIGNAL ;
    PORT
      LAYER M5 ;
        RECT 582.3360 647.9160 582.3600 648.0000 ;
    END
  END lane[419]
  PIN lane[41]
    DIRECTION INPUT ;
    USE SIGNAL ;
    PORT
      LAYER M5 ;
        RECT 407.9520 647.9160 407.9760 648.0000 ;
    END
  END lane[41]
  PIN lane[420]
    DIRECTION INPUT ;
    USE SIGNAL ;
    PORT
      LAYER M3 ;
        RECT 582.8040 647.9620 582.8220 648.0000 ;
    END
  END lane[420]
  PIN lane[421]
    DIRECTION INPUT ;
    USE SIGNAL ;
    PORT
      LAYER M5 ;
        RECT 583.2480 647.9160 583.2720 648.0000 ;
    END
  END lane[421]
  PIN lane[422]
    DIRECTION INPUT ;
    USE SIGNAL ;
    PORT
      LAYER M3 ;
        RECT 583.7040 647.9620 583.7220 648.0000 ;
    END
  END lane[422]
  PIN lane[423]
    DIRECTION INPUT ;
    USE SIGNAL ;
    PORT
      LAYER M5 ;
        RECT 584.1600 647.9160 584.1840 648.0000 ;
    END
  END lane[423]
  PIN lane[424]
    DIRECTION INPUT ;
    USE SIGNAL ;
    PORT
      LAYER M3 ;
        RECT 584.6400 647.9620 584.6580 648.0000 ;
    END
  END lane[424]
  PIN lane[425]
    DIRECTION INPUT ;
    USE SIGNAL ;
    PORT
      LAYER M5 ;
        RECT 585.1200 647.9160 585.1440 648.0000 ;
    END
  END lane[425]
  PIN lane[426]
    DIRECTION INPUT ;
    USE SIGNAL ;
    PORT
      LAYER M3 ;
        RECT 585.5760 647.9620 585.5940 648.0000 ;
    END
  END lane[426]
  PIN lane[427]
    DIRECTION INPUT ;
    USE SIGNAL ;
    PORT
      LAYER M5 ;
        RECT 586.0320 647.9160 586.0560 648.0000 ;
    END
  END lane[427]
  PIN lane[428]
    DIRECTION INPUT ;
    USE SIGNAL ;
    PORT
      LAYER M3 ;
        RECT 586.4760 647.9620 586.4940 648.0000 ;
    END
  END lane[428]
  PIN lane[429]
    DIRECTION INPUT ;
    USE SIGNAL ;
    PORT
      LAYER M5 ;
        RECT 586.9440 647.9160 586.9680 648.0000 ;
    END
  END lane[429]
  PIN lane[42]
    DIRECTION INPUT ;
    USE SIGNAL ;
    PORT
      LAYER M3 ;
        RECT 408.3840 647.9620 408.4020 648.0000 ;
    END
  END lane[42]
  PIN lane[430]
    DIRECTION INPUT ;
    USE SIGNAL ;
    PORT
      LAYER M3 ;
        RECT 587.4120 647.9620 587.4300 648.0000 ;
    END
  END lane[430]
  PIN lane[431]
    DIRECTION INPUT ;
    USE SIGNAL ;
    PORT
      LAYER M5 ;
        RECT 587.8560 647.9160 587.8800 648.0000 ;
    END
  END lane[431]
  PIN lane[432]
    DIRECTION INPUT ;
    USE SIGNAL ;
    PORT
      LAYER M3 ;
        RECT 588.3120 647.9620 588.3300 648.0000 ;
    END
  END lane[432]
  PIN lane[433]
    DIRECTION INPUT ;
    USE SIGNAL ;
    PORT
      LAYER M5 ;
        RECT 588.7680 647.9160 588.7920 648.0000 ;
    END
  END lane[433]
  PIN lane[434]
    DIRECTION INPUT ;
    USE SIGNAL ;
    PORT
      LAYER M3 ;
        RECT 589.2480 647.9620 589.2660 648.0000 ;
    END
  END lane[434]
  PIN lane[435]
    DIRECTION INPUT ;
    USE SIGNAL ;
    PORT
      LAYER M5 ;
        RECT 589.7280 647.9160 589.7520 648.0000 ;
    END
  END lane[435]
  PIN lane[436]
    DIRECTION INPUT ;
    USE SIGNAL ;
    PORT
      LAYER M3 ;
        RECT 590.1840 647.9620 590.2020 648.0000 ;
    END
  END lane[436]
  PIN lane[437]
    DIRECTION INPUT ;
    USE SIGNAL ;
    PORT
      LAYER M5 ;
        RECT 590.6400 647.9160 590.6640 648.0000 ;
    END
  END lane[437]
  PIN lane[438]
    DIRECTION INPUT ;
    USE SIGNAL ;
    PORT
      LAYER M3 ;
        RECT 591.1200 647.9620 591.1380 648.0000 ;
    END
  END lane[438]
  PIN lane[439]
    DIRECTION INPUT ;
    USE SIGNAL ;
    PORT
      LAYER M5 ;
        RECT 591.5520 647.9160 591.5760 648.0000 ;
    END
  END lane[439]
  PIN lane[43]
    DIRECTION INPUT ;
    USE SIGNAL ;
    PORT
      LAYER M5 ;
        RECT 408.8640 647.9160 408.8880 648.0000 ;
    END
  END lane[43]
  PIN lane[440]
    DIRECTION INPUT ;
    USE SIGNAL ;
    PORT
      LAYER M3 ;
        RECT 592.0200 647.9620 592.0380 648.0000 ;
    END
  END lane[440]
  PIN lane[441]
    DIRECTION INPUT ;
    USE SIGNAL ;
    PORT
      LAYER M5 ;
        RECT 592.4640 647.9160 592.4880 648.0000 ;
    END
  END lane[441]
  PIN lane[442]
    DIRECTION INPUT ;
    USE SIGNAL ;
    PORT
      LAYER M3 ;
        RECT 592.9560 647.9620 592.9740 648.0000 ;
    END
  END lane[442]
  PIN lane[443]
    DIRECTION INPUT ;
    USE SIGNAL ;
    PORT
      LAYER M5 ;
        RECT 593.4240 647.9160 593.4480 648.0000 ;
    END
  END lane[443]
  PIN lane[444]
    DIRECTION INPUT ;
    USE SIGNAL ;
    PORT
      LAYER M3 ;
        RECT 593.8560 647.9620 593.8740 648.0000 ;
    END
  END lane[444]
  PIN lane[445]
    DIRECTION INPUT ;
    USE SIGNAL ;
    PORT
      LAYER M5 ;
        RECT 594.3360 647.9160 594.3600 648.0000 ;
    END
  END lane[445]
  PIN lane[446]
    DIRECTION INPUT ;
    USE SIGNAL ;
    PORT
      LAYER M3 ;
        RECT 594.7920 647.9620 594.8100 648.0000 ;
    END
  END lane[446]
  PIN lane[447]
    DIRECTION INPUT ;
    USE SIGNAL ;
    PORT
      LAYER M5 ;
        RECT 595.2480 647.9160 595.2720 648.0000 ;
    END
  END lane[447]
  PIN lane[448]
    DIRECTION INPUT ;
    USE SIGNAL ;
    PORT
      LAYER M3 ;
        RECT 595.7280 647.9620 595.7460 648.0000 ;
    END
  END lane[448]
  PIN lane[449]
    DIRECTION INPUT ;
    USE SIGNAL ;
    PORT
      LAYER M5 ;
        RECT 596.1600 647.9160 596.1840 648.0000 ;
    END
  END lane[449]
  PIN lane[44]
    DIRECTION INPUT ;
    USE SIGNAL ;
    PORT
      LAYER M3 ;
        RECT 409.3200 647.9620 409.3380 648.0000 ;
    END
  END lane[44]
  PIN lane[450]
    DIRECTION INPUT ;
    USE SIGNAL ;
    PORT
      LAYER M3 ;
        RECT 596.6280 647.9620 596.6460 648.0000 ;
    END
  END lane[450]
  PIN lane[451]
    DIRECTION INPUT ;
    USE SIGNAL ;
    PORT
      LAYER M5 ;
        RECT 597.0720 647.9160 597.0960 648.0000 ;
    END
  END lane[451]
  PIN lane[452]
    DIRECTION INPUT ;
    USE SIGNAL ;
    PORT
      LAYER M3 ;
        RECT 597.5640 647.9620 597.5820 648.0000 ;
    END
  END lane[452]
  PIN lane[453]
    DIRECTION INPUT ;
    USE SIGNAL ;
    PORT
      LAYER M5 ;
        RECT 598.0320 647.9160 598.0560 648.0000 ;
    END
  END lane[453]
  PIN lane[454]
    DIRECTION INPUT ;
    USE SIGNAL ;
    PORT
      LAYER M3 ;
        RECT 598.4640 647.9620 598.4820 648.0000 ;
    END
  END lane[454]
  PIN lane[455]
    DIRECTION INPUT ;
    USE SIGNAL ;
    PORT
      LAYER M5 ;
        RECT 598.9440 647.9160 598.9680 648.0000 ;
    END
  END lane[455]
  PIN lane[456]
    DIRECTION INPUT ;
    USE SIGNAL ;
    PORT
      LAYER M3 ;
        RECT 599.4000 647.9620 599.4180 648.0000 ;
    END
  END lane[456]
  PIN lane[457]
    DIRECTION INPUT ;
    USE SIGNAL ;
    PORT
      LAYER M5 ;
        RECT 599.8560 647.9160 599.8800 648.0000 ;
    END
  END lane[457]
  PIN lane[458]
    DIRECTION INPUT ;
    USE SIGNAL ;
    PORT
      LAYER M3 ;
        RECT 600.3360 647.9620 600.3540 648.0000 ;
    END
  END lane[458]
  PIN lane[459]
    DIRECTION INPUT ;
    USE SIGNAL ;
    PORT
      LAYER M5 ;
        RECT 600.7680 647.9160 600.7920 648.0000 ;
    END
  END lane[459]
  PIN lane[45]
    DIRECTION INPUT ;
    USE SIGNAL ;
    PORT
      LAYER M5 ;
        RECT 409.7760 647.9160 409.8000 648.0000 ;
    END
  END lane[45]
  PIN lane[460]
    DIRECTION INPUT ;
    USE SIGNAL ;
    PORT
      LAYER M3 ;
        RECT 601.2360 647.9620 601.2540 648.0000 ;
    END
  END lane[460]
  PIN lane[461]
    DIRECTION INPUT ;
    USE SIGNAL ;
    PORT
      LAYER M5 ;
        RECT 601.7280 647.9160 601.7520 648.0000 ;
    END
  END lane[461]
  PIN lane[462]
    DIRECTION INPUT ;
    USE SIGNAL ;
    PORT
      LAYER M3 ;
        RECT 602.1720 647.9620 602.1900 648.0000 ;
    END
  END lane[462]
  PIN lane[463]
    DIRECTION INPUT ;
    USE SIGNAL ;
    PORT
      LAYER M5 ;
        RECT 602.6400 647.9160 602.6640 648.0000 ;
    END
  END lane[463]
  PIN lane[464]
    DIRECTION INPUT ;
    USE SIGNAL ;
    PORT
      LAYER M3 ;
        RECT 603.1080 647.9620 603.1260 648.0000 ;
    END
  END lane[464]
  PIN lane[465]
    DIRECTION INPUT ;
    USE SIGNAL ;
    PORT
      LAYER M5 ;
        RECT 603.5520 647.9160 603.5760 648.0000 ;
    END
  END lane[465]
  PIN lane[466]
    DIRECTION INPUT ;
    USE SIGNAL ;
    PORT
      LAYER M3 ;
        RECT 604.0080 647.9620 604.0260 648.0000 ;
    END
  END lane[466]
  PIN lane[467]
    DIRECTION INPUT ;
    USE SIGNAL ;
    PORT
      LAYER M5 ;
        RECT 604.4640 647.9160 604.4880 648.0000 ;
    END
  END lane[467]
  PIN lane[468]
    DIRECTION INPUT ;
    USE SIGNAL ;
    PORT
      LAYER M3 ;
        RECT 604.9440 647.9620 604.9620 648.0000 ;
    END
  END lane[468]
  PIN lane[469]
    DIRECTION INPUT ;
    USE SIGNAL ;
    PORT
      LAYER M5 ;
        RECT 605.3760 647.9160 605.4000 648.0000 ;
    END
  END lane[469]
  PIN lane[46]
    DIRECTION INPUT ;
    USE SIGNAL ;
    PORT
      LAYER M3 ;
        RECT 410.2560 647.9620 410.2740 648.0000 ;
    END
  END lane[46]
  PIN lane[470]
    DIRECTION INPUT ;
    USE SIGNAL ;
    PORT
      LAYER M3 ;
        RECT 605.8440 647.9620 605.8620 648.0000 ;
    END
  END lane[470]
  PIN lane[471]
    DIRECTION INPUT ;
    USE SIGNAL ;
    PORT
      LAYER M5 ;
        RECT 606.3360 647.9160 606.3600 648.0000 ;
    END
  END lane[471]
  PIN lane[472]
    DIRECTION INPUT ;
    USE SIGNAL ;
    PORT
      LAYER M3 ;
        RECT 606.7800 647.9620 606.7980 648.0000 ;
    END
  END lane[472]
  PIN lane[473]
    DIRECTION INPUT ;
    USE SIGNAL ;
    PORT
      LAYER M5 ;
        RECT 607.2480 647.9160 607.2720 648.0000 ;
    END
  END lane[473]
  PIN lane[474]
    DIRECTION INPUT ;
    USE SIGNAL ;
    PORT
      LAYER M3 ;
        RECT 607.7160 647.9620 607.7340 648.0000 ;
    END
  END lane[474]
  PIN lane[475]
    DIRECTION INPUT ;
    USE SIGNAL ;
    PORT
      LAYER M5 ;
        RECT 608.1600 647.9160 608.1840 648.0000 ;
    END
  END lane[475]
  PIN lane[476]
    DIRECTION INPUT ;
    USE SIGNAL ;
    PORT
      LAYER M3 ;
        RECT 608.6160 647.9620 608.6340 648.0000 ;
    END
  END lane[476]
  PIN lane[477]
    DIRECTION INPUT ;
    USE SIGNAL ;
    PORT
      LAYER M5 ;
        RECT 609.0720 647.9160 609.0960 648.0000 ;
    END
  END lane[477]
  PIN lane[478]
    DIRECTION INPUT ;
    USE SIGNAL ;
    PORT
      LAYER M3 ;
        RECT 609.5520 647.9620 609.5700 648.0000 ;
    END
  END lane[478]
  PIN lane[479]
    DIRECTION INPUT ;
    USE SIGNAL ;
    PORT
      LAYER M5 ;
        RECT 610.0320 647.9160 610.0560 648.0000 ;
    END
  END lane[479]
  PIN lane[47]
    DIRECTION INPUT ;
    USE SIGNAL ;
    PORT
      LAYER M5 ;
        RECT 410.6880 647.9160 410.7120 648.0000 ;
    END
  END lane[47]
  PIN lane[480]
    DIRECTION INPUT ;
    USE SIGNAL ;
    PORT
      LAYER M3 ;
        RECT 610.4880 647.9620 610.5060 648.0000 ;
    END
  END lane[480]
  PIN lane[481]
    DIRECTION INPUT ;
    USE SIGNAL ;
    PORT
      LAYER M5 ;
        RECT 610.9440 647.9160 610.9680 648.0000 ;
    END
  END lane[481]
  PIN lane[482]
    DIRECTION INPUT ;
    USE SIGNAL ;
    PORT
      LAYER M3 ;
        RECT 611.3880 647.9620 611.4060 648.0000 ;
    END
  END lane[482]
  PIN lane[483]
    DIRECTION INPUT ;
    USE SIGNAL ;
    PORT
      LAYER M5 ;
        RECT 611.8560 647.9160 611.8800 648.0000 ;
    END
  END lane[483]
  PIN lane[484]
    DIRECTION INPUT ;
    USE SIGNAL ;
    PORT
      LAYER M3 ;
        RECT 612.3240 647.9620 612.3420 648.0000 ;
    END
  END lane[484]
  PIN lane[485]
    DIRECTION INPUT ;
    USE SIGNAL ;
    PORT
      LAYER M5 ;
        RECT 612.7680 647.9160 612.7920 648.0000 ;
    END
  END lane[485]
  PIN lane[486]
    DIRECTION INPUT ;
    USE SIGNAL ;
    PORT
      LAYER M3 ;
        RECT 613.2600 647.9620 613.2780 648.0000 ;
    END
  END lane[486]
  PIN lane[487]
    DIRECTION INPUT ;
    USE SIGNAL ;
    PORT
      LAYER M5 ;
        RECT 613.6800 647.9160 613.7040 648.0000 ;
    END
  END lane[487]
  PIN lane[488]
    DIRECTION INPUT ;
    USE SIGNAL ;
    PORT
      LAYER M3 ;
        RECT 614.1600 647.9620 614.1780 648.0000 ;
    END
  END lane[488]
  PIN lane[489]
    DIRECTION INPUT ;
    USE SIGNAL ;
    PORT
      LAYER M5 ;
        RECT 614.6400 647.9160 614.6640 648.0000 ;
    END
  END lane[489]
  PIN lane[48]
    DIRECTION INPUT ;
    USE SIGNAL ;
    PORT
      LAYER M3 ;
        RECT 411.1560 647.9620 411.1740 648.0000 ;
    END
  END lane[48]
  PIN lane[490]
    DIRECTION INPUT ;
    USE SIGNAL ;
    PORT
      LAYER M3 ;
        RECT 615.0960 647.9620 615.1140 648.0000 ;
    END
  END lane[490]
  PIN lane[491]
    DIRECTION INPUT ;
    USE SIGNAL ;
    PORT
      LAYER M5 ;
        RECT 615.5520 647.9160 615.5760 648.0000 ;
    END
  END lane[491]
  PIN lane[492]
    DIRECTION INPUT ;
    USE SIGNAL ;
    PORT
      LAYER M3 ;
        RECT 615.9960 647.9620 616.0140 648.0000 ;
    END
  END lane[492]
  PIN lane[493]
    DIRECTION INPUT ;
    USE SIGNAL ;
    PORT
      LAYER M5 ;
        RECT 616.4640 647.9160 616.4880 648.0000 ;
    END
  END lane[493]
  PIN lane[494]
    DIRECTION INPUT ;
    USE SIGNAL ;
    PORT
      LAYER M3 ;
        RECT 616.9320 647.9620 616.9500 648.0000 ;
    END
  END lane[494]
  PIN lane[495]
    DIRECTION INPUT ;
    USE SIGNAL ;
    PORT
      LAYER M5 ;
        RECT 617.3760 647.9160 617.4000 648.0000 ;
    END
  END lane[495]
  PIN lane[496]
    DIRECTION INPUT ;
    USE SIGNAL ;
    PORT
      LAYER M3 ;
        RECT 617.8680 647.9620 617.8860 648.0000 ;
    END
  END lane[496]
  PIN lane[497]
    DIRECTION INPUT ;
    USE SIGNAL ;
    PORT
      LAYER M5 ;
        RECT 618.3360 647.9160 618.3600 648.0000 ;
    END
  END lane[497]
  PIN lane[498]
    DIRECTION INPUT ;
    USE SIGNAL ;
    PORT
      LAYER M3 ;
        RECT 618.7680 647.9620 618.7860 648.0000 ;
    END
  END lane[498]
  PIN lane[499]
    DIRECTION INPUT ;
    USE SIGNAL ;
    PORT
      LAYER M5 ;
        RECT 619.2480 647.9160 619.2720 648.0000 ;
    END
  END lane[499]
  PIN lane[49]
    DIRECTION INPUT ;
    USE SIGNAL ;
    PORT
      LAYER M5 ;
        RECT 411.6480 647.9160 411.6720 648.0000 ;
    END
  END lane[49]
  PIN lane[4]
    DIRECTION INPUT ;
    USE SIGNAL ;
    PORT
      LAYER M3 ;
        RECT 390.8520 647.9620 390.8700 648.0000 ;
    END
  END lane[4]
  PIN lane[500]
    DIRECTION INPUT ;
    USE SIGNAL ;
    PORT
      LAYER M3 ;
        RECT 619.7040 647.9620 619.7220 648.0000 ;
    END
  END lane[500]
  PIN lane[501]
    DIRECTION INPUT ;
    USE SIGNAL ;
    PORT
      LAYER M5 ;
        RECT 620.1600 647.9160 620.1840 648.0000 ;
    END
  END lane[501]
  PIN lane[502]
    DIRECTION INPUT ;
    USE SIGNAL ;
    PORT
      LAYER M3 ;
        RECT 620.6400 647.9620 620.6580 648.0000 ;
    END
  END lane[502]
  PIN lane[503]
    DIRECTION INPUT ;
    USE SIGNAL ;
    PORT
      LAYER M5 ;
        RECT 621.0720 647.9160 621.0960 648.0000 ;
    END
  END lane[503]
  PIN lane[504]
    DIRECTION INPUT ;
    USE SIGNAL ;
    PORT
      LAYER M3 ;
        RECT 621.5400 647.9620 621.5580 648.0000 ;
    END
  END lane[504]
  PIN lane[505]
    DIRECTION INPUT ;
    USE SIGNAL ;
    PORT
      LAYER M5 ;
        RECT 621.9840 647.9160 622.0080 648.0000 ;
    END
  END lane[505]
  PIN lane[506]
    DIRECTION INPUT ;
    USE SIGNAL ;
    PORT
      LAYER M3 ;
        RECT 622.4760 647.9620 622.4940 648.0000 ;
    END
  END lane[506]
  PIN lane[507]
    DIRECTION INPUT ;
    USE SIGNAL ;
    PORT
      LAYER M5 ;
        RECT 622.9440 647.9160 622.9680 648.0000 ;
    END
  END lane[507]
  PIN lane[508]
    DIRECTION INPUT ;
    USE SIGNAL ;
    PORT
      LAYER M3 ;
        RECT 623.3760 647.9620 623.3940 648.0000 ;
    END
  END lane[508]
  PIN lane[509]
    DIRECTION INPUT ;
    USE SIGNAL ;
    PORT
      LAYER M5 ;
        RECT 623.8560 647.9160 623.8800 648.0000 ;
    END
  END lane[509]
  PIN lane[50]
    DIRECTION INPUT ;
    USE SIGNAL ;
    PORT
      LAYER M3 ;
        RECT 412.0920 647.9620 412.1100 648.0000 ;
    END
  END lane[50]
  PIN lane[510]
    DIRECTION INPUT ;
    USE SIGNAL ;
    PORT
      LAYER M3 ;
        RECT 624.3120 647.9620 624.3300 648.0000 ;
    END
  END lane[510]
  PIN lane[511]
    DIRECTION INPUT ;
    USE SIGNAL ;
    PORT
      LAYER M5 ;
        RECT 624.7680 647.9160 624.7920 648.0000 ;
    END
  END lane[511]
  PIN lane[512]
    DIRECTION INPUT ;
    USE SIGNAL ;
    PORT
      LAYER M3 ;
        RECT 625.2480 647.9620 625.2660 648.0000 ;
    END
  END lane[512]
  PIN lane[513]
    DIRECTION INPUT ;
    USE SIGNAL ;
    PORT
      LAYER M5 ;
        RECT 625.6800 647.9160 625.7040 648.0000 ;
    END
  END lane[513]
  PIN lane[514]
    DIRECTION INPUT ;
    USE SIGNAL ;
    PORT
      LAYER M3 ;
        RECT 626.1480 647.9620 626.1660 648.0000 ;
    END
  END lane[514]
  PIN lane[51]
    DIRECTION INPUT ;
    USE SIGNAL ;
    PORT
      LAYER M5 ;
        RECT 412.5600 647.9160 412.5840 648.0000 ;
    END
  END lane[51]
  PIN lane[52]
    DIRECTION INPUT ;
    USE SIGNAL ;
    PORT
      LAYER M3 ;
        RECT 413.0280 647.9620 413.0460 648.0000 ;
    END
  END lane[52]
  PIN lane[53]
    DIRECTION INPUT ;
    USE SIGNAL ;
    PORT
      LAYER M5 ;
        RECT 413.4720 647.9160 413.4960 648.0000 ;
    END
  END lane[53]
  PIN lane[54]
    DIRECTION INPUT ;
    USE SIGNAL ;
    PORT
      LAYER M3 ;
        RECT 413.9280 647.9620 413.9460 648.0000 ;
    END
  END lane[54]
  PIN lane[55]
    DIRECTION INPUT ;
    USE SIGNAL ;
    PORT
      LAYER M5 ;
        RECT 414.3840 647.9160 414.4080 648.0000 ;
    END
  END lane[55]
  PIN lane[56]
    DIRECTION INPUT ;
    USE SIGNAL ;
    PORT
      LAYER M3 ;
        RECT 414.8640 647.9620 414.8820 648.0000 ;
    END
  END lane[56]
  PIN lane[57]
    DIRECTION INPUT ;
    USE SIGNAL ;
    PORT
      LAYER M5 ;
        RECT 415.2960 647.9160 415.3200 648.0000 ;
    END
  END lane[57]
  PIN lane[58]
    DIRECTION INPUT ;
    USE SIGNAL ;
    PORT
      LAYER M3 ;
        RECT 415.7640 647.9620 415.7820 648.0000 ;
    END
  END lane[58]
  PIN lane[59]
    DIRECTION INPUT ;
    USE SIGNAL ;
    PORT
      LAYER M5 ;
        RECT 416.2560 647.9160 416.2800 648.0000 ;
    END
  END lane[59]
  PIN lane[5]
    DIRECTION INPUT ;
    USE SIGNAL ;
    PORT
      LAYER M5 ;
        RECT 391.3440 647.9160 391.3680 648.0000 ;
    END
  END lane[5]
  PIN lane[60]
    DIRECTION INPUT ;
    USE SIGNAL ;
    PORT
      LAYER M3 ;
        RECT 416.7000 647.9620 416.7180 648.0000 ;
    END
  END lane[60]
  PIN lane[61]
    DIRECTION INPUT ;
    USE SIGNAL ;
    PORT
      LAYER M5 ;
        RECT 417.1680 647.9160 417.1920 648.0000 ;
    END
  END lane[61]
  PIN lane[62]
    DIRECTION INPUT ;
    USE SIGNAL ;
    PORT
      LAYER M3 ;
        RECT 417.6360 647.9620 417.6540 648.0000 ;
    END
  END lane[62]
  PIN lane[63]
    DIRECTION INPUT ;
    USE SIGNAL ;
    PORT
      LAYER M5 ;
        RECT 418.0800 647.9160 418.1040 648.0000 ;
    END
  END lane[63]
  PIN lane[64]
    DIRECTION INPUT ;
    USE SIGNAL ;
    PORT
      LAYER M3 ;
        RECT 418.5360 647.9620 418.5540 648.0000 ;
    END
  END lane[64]
  PIN lane[65]
    DIRECTION INPUT ;
    USE SIGNAL ;
    PORT
      LAYER M5 ;
        RECT 418.9920 647.9160 419.0160 648.0000 ;
    END
  END lane[65]
  PIN lane[66]
    DIRECTION INPUT ;
    USE SIGNAL ;
    PORT
      LAYER M3 ;
        RECT 419.4720 647.9620 419.4900 648.0000 ;
    END
  END lane[66]
  PIN lane[67]
    DIRECTION INPUT ;
    USE SIGNAL ;
    PORT
      LAYER M5 ;
        RECT 419.9520 647.9160 419.9760 648.0000 ;
    END
  END lane[67]
  PIN lane[68]
    DIRECTION INPUT ;
    USE SIGNAL ;
    PORT
      LAYER M3 ;
        RECT 420.4080 647.9620 420.4260 648.0000 ;
    END
  END lane[68]
  PIN lane[69]
    DIRECTION INPUT ;
    USE SIGNAL ;
    PORT
      LAYER M5 ;
        RECT 420.8640 647.9160 420.8880 648.0000 ;
    END
  END lane[69]
  PIN lane[6]
    DIRECTION INPUT ;
    USE SIGNAL ;
    PORT
      LAYER M3 ;
        RECT 391.7880 647.9620 391.8060 648.0000 ;
    END
  END lane[6]
  PIN lane[70]
    DIRECTION INPUT ;
    USE SIGNAL ;
    PORT
      LAYER M3 ;
        RECT 421.3080 647.9620 421.3260 648.0000 ;
    END
  END lane[70]
  PIN lane[71]
    DIRECTION INPUT ;
    USE SIGNAL ;
    PORT
      LAYER M5 ;
        RECT 421.7760 647.9160 421.8000 648.0000 ;
    END
  END lane[71]
  PIN lane[72]
    DIRECTION INPUT ;
    USE SIGNAL ;
    PORT
      LAYER M3 ;
        RECT 422.2440 647.9620 422.2620 648.0000 ;
    END
  END lane[72]
  PIN lane[73]
    DIRECTION INPUT ;
    USE SIGNAL ;
    PORT
      LAYER M5 ;
        RECT 422.6880 647.9160 422.7120 648.0000 ;
    END
  END lane[73]
  PIN lane[74]
    DIRECTION INPUT ;
    USE SIGNAL ;
    PORT
      LAYER M3 ;
        RECT 423.1800 647.9620 423.1980 648.0000 ;
    END
  END lane[74]
  PIN lane[75]
    DIRECTION INPUT ;
    USE SIGNAL ;
    PORT
      LAYER M5 ;
        RECT 423.6000 647.9160 423.6240 648.0000 ;
    END
  END lane[75]
  PIN lane[76]
    DIRECTION INPUT ;
    USE SIGNAL ;
    PORT
      LAYER M3 ;
        RECT 424.0800 647.9620 424.0980 648.0000 ;
    END
  END lane[76]
  PIN lane[77]
    DIRECTION INPUT ;
    USE SIGNAL ;
    PORT
      LAYER M5 ;
        RECT 424.5600 647.9160 424.5840 648.0000 ;
    END
  END lane[77]
  PIN lane[78]
    DIRECTION INPUT ;
    USE SIGNAL ;
    PORT
      LAYER M3 ;
        RECT 425.0160 647.9620 425.0340 648.0000 ;
    END
  END lane[78]
  PIN lane[79]
    DIRECTION INPUT ;
    USE SIGNAL ;
    PORT
      LAYER M5 ;
        RECT 425.4720 647.9160 425.4960 648.0000 ;
    END
  END lane[79]
  PIN lane[7]
    DIRECTION INPUT ;
    USE SIGNAL ;
    PORT
      LAYER M5 ;
        RECT 392.2560 647.9160 392.2800 648.0000 ;
    END
  END lane[7]
  PIN lane[80]
    DIRECTION INPUT ;
    USE SIGNAL ;
    PORT
      LAYER M3 ;
        RECT 425.9160 647.9620 425.9340 648.0000 ;
    END
  END lane[80]
  PIN lane[81]
    DIRECTION INPUT ;
    USE SIGNAL ;
    PORT
      LAYER M5 ;
        RECT 426.3840 647.9160 426.4080 648.0000 ;
    END
  END lane[81]
  PIN lane[82]
    DIRECTION INPUT ;
    USE SIGNAL ;
    PORT
      LAYER M3 ;
        RECT 426.8520 647.9620 426.8700 648.0000 ;
    END
  END lane[82]
  PIN lane[83]
    DIRECTION INPUT ;
    USE SIGNAL ;
    PORT
      LAYER M5 ;
        RECT 427.2960 647.9160 427.3200 648.0000 ;
    END
  END lane[83]
  PIN lane[84]
    DIRECTION INPUT ;
    USE SIGNAL ;
    PORT
      LAYER M3 ;
        RECT 427.7880 647.9620 427.8060 648.0000 ;
    END
  END lane[84]
  PIN lane[85]
    DIRECTION INPUT ;
    USE SIGNAL ;
    PORT
      LAYER M5 ;
        RECT 428.2560 647.9160 428.2800 648.0000 ;
    END
  END lane[85]
  PIN lane[86]
    DIRECTION INPUT ;
    USE SIGNAL ;
    PORT
      LAYER M3 ;
        RECT 428.6880 647.9620 428.7060 648.0000 ;
    END
  END lane[86]
  PIN lane[87]
    DIRECTION INPUT ;
    USE SIGNAL ;
    PORT
      LAYER M5 ;
        RECT 429.1680 647.9160 429.1920 648.0000 ;
    END
  END lane[87]
  PIN lane[88]
    DIRECTION INPUT ;
    USE SIGNAL ;
    PORT
      LAYER M3 ;
        RECT 429.6240 647.9620 429.6420 648.0000 ;
    END
  END lane[88]
  PIN lane[89]
    DIRECTION INPUT ;
    USE SIGNAL ;
    PORT
      LAYER M5 ;
        RECT 430.0800 647.9160 430.1040 648.0000 ;
    END
  END lane[89]
  PIN lane[8]
    DIRECTION INPUT ;
    USE SIGNAL ;
    PORT
      LAYER M3 ;
        RECT 392.7240 647.9620 392.7420 648.0000 ;
    END
  END lane[8]
  PIN lane[90]
    DIRECTION INPUT ;
    USE SIGNAL ;
    PORT
      LAYER M3 ;
        RECT 430.5600 647.9620 430.5780 648.0000 ;
    END
  END lane[90]
  PIN lane[91]
    DIRECTION INPUT ;
    USE SIGNAL ;
    PORT
      LAYER M5 ;
        RECT 430.9920 647.9160 431.0160 648.0000 ;
    END
  END lane[91]
  PIN lane[92]
    DIRECTION INPUT ;
    USE SIGNAL ;
    PORT
      LAYER M3 ;
        RECT 431.4600 647.9620 431.4780 648.0000 ;
    END
  END lane[92]
  PIN lane[93]
    DIRECTION INPUT ;
    USE SIGNAL ;
    PORT
      LAYER M5 ;
        RECT 431.9040 647.9160 431.9280 648.0000 ;
    END
  END lane[93]
  PIN lane[94]
    DIRECTION INPUT ;
    USE SIGNAL ;
    PORT
      LAYER M3 ;
        RECT 432.3960 647.9620 432.4140 648.0000 ;
    END
  END lane[94]
  PIN lane[95]
    DIRECTION INPUT ;
    USE SIGNAL ;
    PORT
      LAYER M5 ;
        RECT 432.8640 647.9160 432.8880 648.0000 ;
    END
  END lane[95]
  PIN lane[96]
    DIRECTION INPUT ;
    USE SIGNAL ;
    PORT
      LAYER M3 ;
        RECT 433.2960 647.9620 433.3140 648.0000 ;
    END
  END lane[96]
  PIN lane[97]
    DIRECTION INPUT ;
    USE SIGNAL ;
    PORT
      LAYER M5 ;
        RECT 433.7760 647.9160 433.8000 648.0000 ;
    END
  END lane[97]
  PIN lane[98]
    DIRECTION INPUT ;
    USE SIGNAL ;
    PORT
      LAYER M3 ;
        RECT 434.2320 647.9620 434.2500 648.0000 ;
    END
  END lane[98]
  PIN lane[99]
    DIRECTION INPUT ;
    USE SIGNAL ;
    PORT
      LAYER M5 ;
        RECT 434.6880 647.9160 434.7120 648.0000 ;
    END
  END lane[99]
  PIN lane[9]
    DIRECTION INPUT ;
    USE SIGNAL ;
    PORT
      LAYER M5 ;
        RECT 393.1680 647.9160 393.1920 648.0000 ;
    END
  END lane[9]
  PIN rst
    DIRECTION INPUT ;
    USE SIGNAL ;
    PORT
      LAYER M3 ;
        RECT 307.8360 647.9620 307.8540 648.0000 ;
    END
  END rst
  PIN t_o[0]
    DIRECTION OUTPUT ;
    USE SIGNAL ;
    PORT
      LAYER M4 ;
        RECT 0.0000 3.0720 0.0840 3.0960 ;
    END
  END t_o[0]
  PIN t_o[100]
    DIRECTION OUTPUT ;
    USE SIGNAL ;
    PORT
      LAYER M4 ;
        RECT 0.0000 184.8960 0.0840 184.9200 ;
    END
  END t_o[100]
  PIN t_o[101]
    DIRECTION OUTPUT ;
    USE SIGNAL ;
    PORT
      LAYER M4 ;
        RECT 0.0000 186.7200 0.0840 186.7440 ;
    END
  END t_o[101]
  PIN t_o[102]
    DIRECTION OUTPUT ;
    USE SIGNAL ;
    PORT
      LAYER M4 ;
        RECT 0.0000 188.5440 0.0840 188.5680 ;
    END
  END t_o[102]
  PIN t_o[103]
    DIRECTION OUTPUT ;
    USE SIGNAL ;
    PORT
      LAYER M4 ;
        RECT 0.0000 190.3200 0.0840 190.3440 ;
    END
  END t_o[103]
  PIN t_o[104]
    DIRECTION OUTPUT ;
    USE SIGNAL ;
    PORT
      LAYER M4 ;
        RECT 0.0000 192.1440 0.0840 192.1680 ;
    END
  END t_o[104]
  PIN t_o[105]
    DIRECTION OUTPUT ;
    USE SIGNAL ;
    PORT
      LAYER M4 ;
        RECT 0.0000 193.9680 0.0840 193.9920 ;
    END
  END t_o[105]
  PIN t_o[106]
    DIRECTION OUTPUT ;
    USE SIGNAL ;
    PORT
      LAYER M4 ;
        RECT 0.0000 195.7920 0.0840 195.8160 ;
    END
  END t_o[106]
  PIN t_o[107]
    DIRECTION OUTPUT ;
    USE SIGNAL ;
    PORT
      LAYER M4 ;
        RECT 0.0000 197.6160 0.0840 197.6400 ;
    END
  END t_o[107]
  PIN t_o[108]
    DIRECTION OUTPUT ;
    USE SIGNAL ;
    PORT
      LAYER M4 ;
        RECT 0.0000 199.4400 0.0840 199.4640 ;
    END
  END t_o[108]
  PIN t_o[109]
    DIRECTION OUTPUT ;
    USE SIGNAL ;
    PORT
      LAYER M4 ;
        RECT 0.0000 201.2640 0.0840 201.2880 ;
    END
  END t_o[109]
  PIN t_o[10]
    DIRECTION OUTPUT ;
    USE SIGNAL ;
    PORT
      LAYER M4 ;
        RECT 0.0000 21.2640 0.0840 21.2880 ;
    END
  END t_o[10]
  PIN t_o[110]
    DIRECTION OUTPUT ;
    USE SIGNAL ;
    PORT
      LAYER M4 ;
        RECT 0.0000 203.0880 0.0840 203.1120 ;
    END
  END t_o[110]
  PIN t_o[111]
    DIRECTION OUTPUT ;
    USE SIGNAL ;
    PORT
      LAYER M4 ;
        RECT 0.0000 204.9120 0.0840 204.9360 ;
    END
  END t_o[111]
  PIN t_o[112]
    DIRECTION OUTPUT ;
    USE SIGNAL ;
    PORT
      LAYER M4 ;
        RECT 0.0000 206.6880 0.0840 206.7120 ;
    END
  END t_o[112]
  PIN t_o[113]
    DIRECTION OUTPUT ;
    USE SIGNAL ;
    PORT
      LAYER M4 ;
        RECT 0.0000 208.5120 0.0840 208.5360 ;
    END
  END t_o[113]
  PIN t_o[114]
    DIRECTION OUTPUT ;
    USE SIGNAL ;
    PORT
      LAYER M4 ;
        RECT 0.0000 210.3360 0.0840 210.3600 ;
    END
  END t_o[114]
  PIN t_o[115]
    DIRECTION OUTPUT ;
    USE SIGNAL ;
    PORT
      LAYER M4 ;
        RECT 0.0000 212.1600 0.0840 212.1840 ;
    END
  END t_o[115]
  PIN t_o[116]
    DIRECTION OUTPUT ;
    USE SIGNAL ;
    PORT
      LAYER M4 ;
        RECT 0.0000 213.9840 0.0840 214.0080 ;
    END
  END t_o[116]
  PIN t_o[117]
    DIRECTION OUTPUT ;
    USE SIGNAL ;
    PORT
      LAYER M4 ;
        RECT 0.0000 215.8080 0.0840 215.8320 ;
    END
  END t_o[117]
  PIN t_o[118]
    DIRECTION OUTPUT ;
    USE SIGNAL ;
    PORT
      LAYER M4 ;
        RECT 0.0000 217.6320 0.0840 217.6560 ;
    END
  END t_o[118]
  PIN t_o[119]
    DIRECTION OUTPUT ;
    USE SIGNAL ;
    PORT
      LAYER M4 ;
        RECT 0.0000 219.4560 0.0840 219.4800 ;
    END
  END t_o[119]
  PIN t_o[11]
    DIRECTION OUTPUT ;
    USE SIGNAL ;
    PORT
      LAYER M4 ;
        RECT 0.0000 23.0400 0.0840 23.0640 ;
    END
  END t_o[11]
  PIN t_o[120]
    DIRECTION OUTPUT ;
    USE SIGNAL ;
    PORT
      LAYER M4 ;
        RECT 0.0000 221.2320 0.0840 221.2560 ;
    END
  END t_o[120]
  PIN t_o[121]
    DIRECTION OUTPUT ;
    USE SIGNAL ;
    PORT
      LAYER M4 ;
        RECT 0.0000 223.0560 0.0840 223.0800 ;
    END
  END t_o[121]
  PIN t_o[122]
    DIRECTION OUTPUT ;
    USE SIGNAL ;
    PORT
      LAYER M4 ;
        RECT 0.0000 224.8800 0.0840 224.9040 ;
    END
  END t_o[122]
  PIN t_o[123]
    DIRECTION OUTPUT ;
    USE SIGNAL ;
    PORT
      LAYER M4 ;
        RECT 0.0000 226.7040 0.0840 226.7280 ;
    END
  END t_o[123]
  PIN t_o[124]
    DIRECTION OUTPUT ;
    USE SIGNAL ;
    PORT
      LAYER M4 ;
        RECT 0.0000 228.5280 0.0840 228.5520 ;
    END
  END t_o[124]
  PIN t_o[125]
    DIRECTION OUTPUT ;
    USE SIGNAL ;
    PORT
      LAYER M4 ;
        RECT 0.0000 230.3520 0.0840 230.3760 ;
    END
  END t_o[125]
  PIN t_o[126]
    DIRECTION OUTPUT ;
    USE SIGNAL ;
    PORT
      LAYER M4 ;
        RECT 0.0000 232.1760 0.0840 232.2000 ;
    END
  END t_o[126]
  PIN t_o[127]
    DIRECTION OUTPUT ;
    USE SIGNAL ;
    PORT
      LAYER M4 ;
        RECT 0.0000 234.0000 0.0840 234.0240 ;
    END
  END t_o[127]
  PIN t_o[128]
    DIRECTION OUTPUT ;
    USE SIGNAL ;
    PORT
      LAYER M4 ;
        RECT 0.0000 235.8240 0.0840 235.8480 ;
    END
  END t_o[128]
  PIN t_o[129]
    DIRECTION OUTPUT ;
    USE SIGNAL ;
    PORT
      LAYER M4 ;
        RECT 0.0000 237.6000 0.0840 237.6240 ;
    END
  END t_o[129]
  PIN t_o[12]
    DIRECTION OUTPUT ;
    USE SIGNAL ;
    PORT
      LAYER M4 ;
        RECT 0.0000 24.8640 0.0840 24.8880 ;
    END
  END t_o[12]
  PIN t_o[130]
    DIRECTION OUTPUT ;
    USE SIGNAL ;
    PORT
      LAYER M4 ;
        RECT 0.0000 239.4240 0.0840 239.4480 ;
    END
  END t_o[130]
  PIN t_o[131]
    DIRECTION OUTPUT ;
    USE SIGNAL ;
    PORT
      LAYER M4 ;
        RECT 0.0000 241.2480 0.0840 241.2720 ;
    END
  END t_o[131]
  PIN t_o[132]
    DIRECTION OUTPUT ;
    USE SIGNAL ;
    PORT
      LAYER M4 ;
        RECT 0.0000 243.0720 0.0840 243.0960 ;
    END
  END t_o[132]
  PIN t_o[133]
    DIRECTION OUTPUT ;
    USE SIGNAL ;
    PORT
      LAYER M4 ;
        RECT 0.0000 244.8960 0.0840 244.9200 ;
    END
  END t_o[133]
  PIN t_o[134]
    DIRECTION OUTPUT ;
    USE SIGNAL ;
    PORT
      LAYER M4 ;
        RECT 0.0000 246.7200 0.0840 246.7440 ;
    END
  END t_o[134]
  PIN t_o[135]
    DIRECTION OUTPUT ;
    USE SIGNAL ;
    PORT
      LAYER M4 ;
        RECT 0.0000 248.5440 0.0840 248.5680 ;
    END
  END t_o[135]
  PIN t_o[136]
    DIRECTION OUTPUT ;
    USE SIGNAL ;
    PORT
      LAYER M4 ;
        RECT 0.0000 250.3680 0.0840 250.3920 ;
    END
  END t_o[136]
  PIN t_o[137]
    DIRECTION OUTPUT ;
    USE SIGNAL ;
    PORT
      LAYER M4 ;
        RECT 0.0000 252.1440 0.0840 252.1680 ;
    END
  END t_o[137]
  PIN t_o[138]
    DIRECTION OUTPUT ;
    USE SIGNAL ;
    PORT
      LAYER M4 ;
        RECT 0.0000 253.9680 0.0840 253.9920 ;
    END
  END t_o[138]
  PIN t_o[139]
    DIRECTION OUTPUT ;
    USE SIGNAL ;
    PORT
      LAYER M4 ;
        RECT 0.0000 255.7920 0.0840 255.8160 ;
    END
  END t_o[139]
  PIN t_o[13]
    DIRECTION OUTPUT ;
    USE SIGNAL ;
    PORT
      LAYER M4 ;
        RECT 0.0000 26.6880 0.0840 26.7120 ;
    END
  END t_o[13]
  PIN t_o[140]
    DIRECTION OUTPUT ;
    USE SIGNAL ;
    PORT
      LAYER M4 ;
        RECT 0.0000 257.6160 0.0840 257.6400 ;
    END
  END t_o[140]
  PIN t_o[141]
    DIRECTION OUTPUT ;
    USE SIGNAL ;
    PORT
      LAYER M4 ;
        RECT 0.0000 259.4400 0.0840 259.4640 ;
    END
  END t_o[141]
  PIN t_o[142]
    DIRECTION OUTPUT ;
    USE SIGNAL ;
    PORT
      LAYER M4 ;
        RECT 0.0000 261.2640 0.0840 261.2880 ;
    END
  END t_o[142]
  PIN t_o[143]
    DIRECTION OUTPUT ;
    USE SIGNAL ;
    PORT
      LAYER M4 ;
        RECT 0.0000 263.0880 0.0840 263.1120 ;
    END
  END t_o[143]
  PIN t_o[144]
    DIRECTION OUTPUT ;
    USE SIGNAL ;
    PORT
      LAYER M4 ;
        RECT 0.0000 264.9120 0.0840 264.9360 ;
    END
  END t_o[144]
  PIN t_o[145]
    DIRECTION OUTPUT ;
    USE SIGNAL ;
    PORT
      LAYER M4 ;
        RECT 0.0000 266.6880 0.0840 266.7120 ;
    END
  END t_o[145]
  PIN t_o[146]
    DIRECTION OUTPUT ;
    USE SIGNAL ;
    PORT
      LAYER M4 ;
        RECT 0.0000 268.5120 0.0840 268.5360 ;
    END
  END t_o[146]
  PIN t_o[147]
    DIRECTION OUTPUT ;
    USE SIGNAL ;
    PORT
      LAYER M4 ;
        RECT 0.0000 270.3360 0.0840 270.3600 ;
    END
  END t_o[147]
  PIN t_o[148]
    DIRECTION OUTPUT ;
    USE SIGNAL ;
    PORT
      LAYER M4 ;
        RECT 0.0000 272.1600 0.0840 272.1840 ;
    END
  END t_o[148]
  PIN t_o[149]
    DIRECTION OUTPUT ;
    USE SIGNAL ;
    PORT
      LAYER M4 ;
        RECT 0.0000 273.9840 0.0840 274.0080 ;
    END
  END t_o[149]
  PIN t_o[14]
    DIRECTION OUTPUT ;
    USE SIGNAL ;
    PORT
      LAYER M4 ;
        RECT 0.0000 28.5120 0.0840 28.5360 ;
    END
  END t_o[14]
  PIN t_o[150]
    DIRECTION OUTPUT ;
    USE SIGNAL ;
    PORT
      LAYER M4 ;
        RECT 0.0000 275.8080 0.0840 275.8320 ;
    END
  END t_o[150]
  PIN t_o[151]
    DIRECTION OUTPUT ;
    USE SIGNAL ;
    PORT
      LAYER M4 ;
        RECT 0.0000 277.6320 0.0840 277.6560 ;
    END
  END t_o[151]
  PIN t_o[152]
    DIRECTION OUTPUT ;
    USE SIGNAL ;
    PORT
      LAYER M4 ;
        RECT 0.0000 279.4560 0.0840 279.4800 ;
    END
  END t_o[152]
  PIN t_o[153]
    DIRECTION OUTPUT ;
    USE SIGNAL ;
    PORT
      LAYER M4 ;
        RECT 0.0000 281.2800 0.0840 281.3040 ;
    END
  END t_o[153]
  PIN t_o[154]
    DIRECTION OUTPUT ;
    USE SIGNAL ;
    PORT
      LAYER M4 ;
        RECT 0.0000 283.0560 0.0840 283.0800 ;
    END
  END t_o[154]
  PIN t_o[155]
    DIRECTION OUTPUT ;
    USE SIGNAL ;
    PORT
      LAYER M4 ;
        RECT 0.0000 284.8800 0.0840 284.9040 ;
    END
  END t_o[155]
  PIN t_o[156]
    DIRECTION OUTPUT ;
    USE SIGNAL ;
    PORT
      LAYER M4 ;
        RECT 0.0000 286.7040 0.0840 286.7280 ;
    END
  END t_o[156]
  PIN t_o[157]
    DIRECTION OUTPUT ;
    USE SIGNAL ;
    PORT
      LAYER M4 ;
        RECT 0.0000 288.5280 0.0840 288.5520 ;
    END
  END t_o[157]
  PIN t_o[158]
    DIRECTION OUTPUT ;
    USE SIGNAL ;
    PORT
      LAYER M4 ;
        RECT 0.0000 290.3520 0.0840 290.3760 ;
    END
  END t_o[158]
  PIN t_o[159]
    DIRECTION OUTPUT ;
    USE SIGNAL ;
    PORT
      LAYER M4 ;
        RECT 0.0000 292.1760 0.0840 292.2000 ;
    END
  END t_o[159]
  PIN t_o[15]
    DIRECTION OUTPUT ;
    USE SIGNAL ;
    PORT
      LAYER M4 ;
        RECT 0.0000 30.3360 0.0840 30.3600 ;
    END
  END t_o[15]
  PIN t_o[160]
    DIRECTION OUTPUT ;
    USE SIGNAL ;
    PORT
      LAYER M4 ;
        RECT 0.0000 294.0000 0.0840 294.0240 ;
    END
  END t_o[160]
  PIN t_o[161]
    DIRECTION OUTPUT ;
    USE SIGNAL ;
    PORT
      LAYER M4 ;
        RECT 0.0000 295.8240 0.0840 295.8480 ;
    END
  END t_o[161]
  PIN t_o[162]
    DIRECTION OUTPUT ;
    USE SIGNAL ;
    PORT
      LAYER M4 ;
        RECT 0.0000 297.6000 0.0840 297.6240 ;
    END
  END t_o[162]
  PIN t_o[163]
    DIRECTION OUTPUT ;
    USE SIGNAL ;
    PORT
      LAYER M4 ;
        RECT 0.0000 299.4240 0.0840 299.4480 ;
    END
  END t_o[163]
  PIN t_o[164]
    DIRECTION OUTPUT ;
    USE SIGNAL ;
    PORT
      LAYER M4 ;
        RECT 0.0000 301.2480 0.0840 301.2720 ;
    END
  END t_o[164]
  PIN t_o[165]
    DIRECTION OUTPUT ;
    USE SIGNAL ;
    PORT
      LAYER M4 ;
        RECT 0.0000 303.0720 0.0840 303.0960 ;
    END
  END t_o[165]
  PIN t_o[166]
    DIRECTION OUTPUT ;
    USE SIGNAL ;
    PORT
      LAYER M4 ;
        RECT 0.0000 304.8960 0.0840 304.9200 ;
    END
  END t_o[166]
  PIN t_o[167]
    DIRECTION OUTPUT ;
    USE SIGNAL ;
    PORT
      LAYER M4 ;
        RECT 0.0000 306.7200 0.0840 306.7440 ;
    END
  END t_o[167]
  PIN t_o[168]
    DIRECTION OUTPUT ;
    USE SIGNAL ;
    PORT
      LAYER M4 ;
        RECT 0.0000 308.5440 0.0840 308.5680 ;
    END
  END t_o[168]
  PIN t_o[169]
    DIRECTION OUTPUT ;
    USE SIGNAL ;
    PORT
      LAYER M4 ;
        RECT 0.0000 310.3680 0.0840 310.3920 ;
    END
  END t_o[169]
  PIN t_o[16]
    DIRECTION OUTPUT ;
    USE SIGNAL ;
    PORT
      LAYER M4 ;
        RECT 0.0000 32.1600 0.0840 32.1840 ;
    END
  END t_o[16]
  PIN t_o[170]
    DIRECTION OUTPUT ;
    USE SIGNAL ;
    PORT
      LAYER M4 ;
        RECT 0.0000 312.1920 0.0840 312.2160 ;
    END
  END t_o[170]
  PIN t_o[171]
    DIRECTION OUTPUT ;
    USE SIGNAL ;
    PORT
      LAYER M4 ;
        RECT 0.0000 313.9680 0.0840 313.9920 ;
    END
  END t_o[171]
  PIN t_o[172]
    DIRECTION OUTPUT ;
    USE SIGNAL ;
    PORT
      LAYER M4 ;
        RECT 0.0000 315.7920 0.0840 315.8160 ;
    END
  END t_o[172]
  PIN t_o[173]
    DIRECTION OUTPUT ;
    USE SIGNAL ;
    PORT
      LAYER M4 ;
        RECT 0.0000 317.6160 0.0840 317.6400 ;
    END
  END t_o[173]
  PIN t_o[174]
    DIRECTION OUTPUT ;
    USE SIGNAL ;
    PORT
      LAYER M4 ;
        RECT 0.0000 319.4400 0.0840 319.4640 ;
    END
  END t_o[174]
  PIN t_o[175]
    DIRECTION OUTPUT ;
    USE SIGNAL ;
    PORT
      LAYER M4 ;
        RECT 0.0000 321.2640 0.0840 321.2880 ;
    END
  END t_o[175]
  PIN t_o[176]
    DIRECTION OUTPUT ;
    USE SIGNAL ;
    PORT
      LAYER M4 ;
        RECT 0.0000 323.0880 0.0840 323.1120 ;
    END
  END t_o[176]
  PIN t_o[177]
    DIRECTION OUTPUT ;
    USE SIGNAL ;
    PORT
      LAYER M4 ;
        RECT 0.0000 324.9120 0.0840 324.9360 ;
    END
  END t_o[177]
  PIN t_o[178]
    DIRECTION OUTPUT ;
    USE SIGNAL ;
    PORT
      LAYER M4 ;
        RECT 0.0000 326.7360 0.0840 326.7600 ;
    END
  END t_o[178]
  PIN t_o[179]
    DIRECTION OUTPUT ;
    USE SIGNAL ;
    PORT
      LAYER M4 ;
        RECT 0.0000 328.5120 0.0840 328.5360 ;
    END
  END t_o[179]
  PIN t_o[17]
    DIRECTION OUTPUT ;
    USE SIGNAL ;
    PORT
      LAYER M4 ;
        RECT 0.0000 33.9840 0.0840 34.0080 ;
    END
  END t_o[17]
  PIN t_o[180]
    DIRECTION OUTPUT ;
    USE SIGNAL ;
    PORT
      LAYER M4 ;
        RECT 0.0000 330.3360 0.0840 330.3600 ;
    END
  END t_o[180]
  PIN t_o[181]
    DIRECTION OUTPUT ;
    USE SIGNAL ;
    PORT
      LAYER M4 ;
        RECT 0.0000 332.1600 0.0840 332.1840 ;
    END
  END t_o[181]
  PIN t_o[182]
    DIRECTION OUTPUT ;
    USE SIGNAL ;
    PORT
      LAYER M4 ;
        RECT 0.0000 333.9840 0.0840 334.0080 ;
    END
  END t_o[182]
  PIN t_o[183]
    DIRECTION OUTPUT ;
    USE SIGNAL ;
    PORT
      LAYER M4 ;
        RECT 0.0000 335.8080 0.0840 335.8320 ;
    END
  END t_o[183]
  PIN t_o[184]
    DIRECTION OUTPUT ;
    USE SIGNAL ;
    PORT
      LAYER M4 ;
        RECT 0.0000 337.6320 0.0840 337.6560 ;
    END
  END t_o[184]
  PIN t_o[185]
    DIRECTION OUTPUT ;
    USE SIGNAL ;
    PORT
      LAYER M4 ;
        RECT 0.0000 339.4560 0.0840 339.4800 ;
    END
  END t_o[185]
  PIN t_o[186]
    DIRECTION OUTPUT ;
    USE SIGNAL ;
    PORT
      LAYER M4 ;
        RECT 0.0000 341.2800 0.0840 341.3040 ;
    END
  END t_o[186]
  PIN t_o[187]
    DIRECTION OUTPUT ;
    USE SIGNAL ;
    PORT
      LAYER M4 ;
        RECT 0.0000 343.1040 0.0840 343.1280 ;
    END
  END t_o[187]
  PIN t_o[188]
    DIRECTION OUTPUT ;
    USE SIGNAL ;
    PORT
      LAYER M4 ;
        RECT 0.0000 344.8800 0.0840 344.9040 ;
    END
  END t_o[188]
  PIN t_o[189]
    DIRECTION OUTPUT ;
    USE SIGNAL ;
    PORT
      LAYER M4 ;
        RECT 0.0000 346.7040 0.0840 346.7280 ;
    END
  END t_o[189]
  PIN t_o[18]
    DIRECTION OUTPUT ;
    USE SIGNAL ;
    PORT
      LAYER M4 ;
        RECT 0.0000 35.8080 0.0840 35.8320 ;
    END
  END t_o[18]
  PIN t_o[190]
    DIRECTION OUTPUT ;
    USE SIGNAL ;
    PORT
      LAYER M4 ;
        RECT 0.0000 348.5280 0.0840 348.5520 ;
    END
  END t_o[190]
  PIN t_o[191]
    DIRECTION OUTPUT ;
    USE SIGNAL ;
    PORT
      LAYER M4 ;
        RECT 0.0000 350.3520 0.0840 350.3760 ;
    END
  END t_o[191]
  PIN t_o[192]
    DIRECTION OUTPUT ;
    USE SIGNAL ;
    PORT
      LAYER M4 ;
        RECT 0.0000 352.1760 0.0840 352.2000 ;
    END
  END t_o[192]
  PIN t_o[193]
    DIRECTION OUTPUT ;
    USE SIGNAL ;
    PORT
      LAYER M4 ;
        RECT 0.0000 354.0000 0.0840 354.0240 ;
    END
  END t_o[193]
  PIN t_o[194]
    DIRECTION OUTPUT ;
    USE SIGNAL ;
    PORT
      LAYER M4 ;
        RECT 0.0000 355.8240 0.0840 355.8480 ;
    END
  END t_o[194]
  PIN t_o[195]
    DIRECTION OUTPUT ;
    USE SIGNAL ;
    PORT
      LAYER M4 ;
        RECT 0.0000 357.6480 0.0840 357.6720 ;
    END
  END t_o[195]
  PIN t_o[196]
    DIRECTION OUTPUT ;
    USE SIGNAL ;
    PORT
      LAYER M4 ;
        RECT 0.0000 359.4240 0.0840 359.4480 ;
    END
  END t_o[196]
  PIN t_o[197]
    DIRECTION OUTPUT ;
    USE SIGNAL ;
    PORT
      LAYER M4 ;
        RECT 0.0000 361.2480 0.0840 361.2720 ;
    END
  END t_o[197]
  PIN t_o[198]
    DIRECTION OUTPUT ;
    USE SIGNAL ;
    PORT
      LAYER M4 ;
        RECT 0.0000 363.0720 0.0840 363.0960 ;
    END
  END t_o[198]
  PIN t_o[199]
    DIRECTION OUTPUT ;
    USE SIGNAL ;
    PORT
      LAYER M4 ;
        RECT 0.0000 364.8960 0.0840 364.9200 ;
    END
  END t_o[199]
  PIN t_o[19]
    DIRECTION OUTPUT ;
    USE SIGNAL ;
    PORT
      LAYER M4 ;
        RECT 0.0000 37.5840 0.0840 37.6080 ;
    END
  END t_o[19]
  PIN t_o[1]
    DIRECTION OUTPUT ;
    USE SIGNAL ;
    PORT
      LAYER M4 ;
        RECT 0.0000 4.8960 0.0840 4.9200 ;
    END
  END t_o[1]
  PIN t_o[200]
    DIRECTION OUTPUT ;
    USE SIGNAL ;
    PORT
      LAYER M4 ;
        RECT 0.0000 366.7200 0.0840 366.7440 ;
    END
  END t_o[200]
  PIN t_o[201]
    DIRECTION OUTPUT ;
    USE SIGNAL ;
    PORT
      LAYER M4 ;
        RECT 0.0000 368.5440 0.0840 368.5680 ;
    END
  END t_o[201]
  PIN t_o[202]
    DIRECTION OUTPUT ;
    USE SIGNAL ;
    PORT
      LAYER M4 ;
        RECT 0.0000 370.3680 0.0840 370.3920 ;
    END
  END t_o[202]
  PIN t_o[203]
    DIRECTION OUTPUT ;
    USE SIGNAL ;
    PORT
      LAYER M4 ;
        RECT 0.0000 372.1920 0.0840 372.2160 ;
    END
  END t_o[203]
  PIN t_o[204]
    DIRECTION OUTPUT ;
    USE SIGNAL ;
    PORT
      LAYER M4 ;
        RECT 0.0000 373.9680 0.0840 373.9920 ;
    END
  END t_o[204]
  PIN t_o[205]
    DIRECTION OUTPUT ;
    USE SIGNAL ;
    PORT
      LAYER M4 ;
        RECT 0.0000 375.7920 0.0840 375.8160 ;
    END
  END t_o[205]
  PIN t_o[206]
    DIRECTION OUTPUT ;
    USE SIGNAL ;
    PORT
      LAYER M4 ;
        RECT 0.0000 377.6160 0.0840 377.6400 ;
    END
  END t_o[206]
  PIN t_o[207]
    DIRECTION OUTPUT ;
    USE SIGNAL ;
    PORT
      LAYER M4 ;
        RECT 0.0000 379.4400 0.0840 379.4640 ;
    END
  END t_o[207]
  PIN t_o[208]
    DIRECTION OUTPUT ;
    USE SIGNAL ;
    PORT
      LAYER M4 ;
        RECT 0.0000 381.2640 0.0840 381.2880 ;
    END
  END t_o[208]
  PIN t_o[209]
    DIRECTION OUTPUT ;
    USE SIGNAL ;
    PORT
      LAYER M4 ;
        RECT 0.0000 383.0880 0.0840 383.1120 ;
    END
  END t_o[209]
  PIN t_o[20]
    DIRECTION OUTPUT ;
    USE SIGNAL ;
    PORT
      LAYER M4 ;
        RECT 0.0000 39.4080 0.0840 39.4320 ;
    END
  END t_o[20]
  PIN t_o[210]
    DIRECTION OUTPUT ;
    USE SIGNAL ;
    PORT
      LAYER M4 ;
        RECT 0.0000 384.9120 0.0840 384.9360 ;
    END
  END t_o[210]
  PIN t_o[211]
    DIRECTION OUTPUT ;
    USE SIGNAL ;
    PORT
      LAYER M4 ;
        RECT 0.0000 386.7360 0.0840 386.7600 ;
    END
  END t_o[211]
  PIN t_o[212]
    DIRECTION OUTPUT ;
    USE SIGNAL ;
    PORT
      LAYER M4 ;
        RECT 0.0000 388.5600 0.0840 388.5840 ;
    END
  END t_o[212]
  PIN t_o[213]
    DIRECTION OUTPUT ;
    USE SIGNAL ;
    PORT
      LAYER M4 ;
        RECT 0.0000 390.3360 0.0840 390.3600 ;
    END
  END t_o[213]
  PIN t_o[214]
    DIRECTION OUTPUT ;
    USE SIGNAL ;
    PORT
      LAYER M4 ;
        RECT 0.0000 392.1600 0.0840 392.1840 ;
    END
  END t_o[214]
  PIN t_o[215]
    DIRECTION OUTPUT ;
    USE SIGNAL ;
    PORT
      LAYER M4 ;
        RECT 0.0000 393.9840 0.0840 394.0080 ;
    END
  END t_o[215]
  PIN t_o[216]
    DIRECTION OUTPUT ;
    USE SIGNAL ;
    PORT
      LAYER M4 ;
        RECT 0.0000 395.8080 0.0840 395.8320 ;
    END
  END t_o[216]
  PIN t_o[217]
    DIRECTION OUTPUT ;
    USE SIGNAL ;
    PORT
      LAYER M4 ;
        RECT 0.0000 397.6320 0.0840 397.6560 ;
    END
  END t_o[217]
  PIN t_o[218]
    DIRECTION OUTPUT ;
    USE SIGNAL ;
    PORT
      LAYER M4 ;
        RECT 0.0000 399.4560 0.0840 399.4800 ;
    END
  END t_o[218]
  PIN t_o[219]
    DIRECTION OUTPUT ;
    USE SIGNAL ;
    PORT
      LAYER M4 ;
        RECT 0.0000 401.2800 0.0840 401.3040 ;
    END
  END t_o[219]
  PIN t_o[21]
    DIRECTION OUTPUT ;
    USE SIGNAL ;
    PORT
      LAYER M4 ;
        RECT 0.0000 41.2320 0.0840 41.2560 ;
    END
  END t_o[21]
  PIN t_o[220]
    DIRECTION OUTPUT ;
    USE SIGNAL ;
    PORT
      LAYER M4 ;
        RECT 0.0000 403.1040 0.0840 403.1280 ;
    END
  END t_o[220]
  PIN t_o[221]
    DIRECTION OUTPUT ;
    USE SIGNAL ;
    PORT
      LAYER M4 ;
        RECT 0.0000 404.8800 0.0840 404.9040 ;
    END
  END t_o[221]
  PIN t_o[222]
    DIRECTION OUTPUT ;
    USE SIGNAL ;
    PORT
      LAYER M4 ;
        RECT 0.0000 406.7040 0.0840 406.7280 ;
    END
  END t_o[222]
  PIN t_o[223]
    DIRECTION OUTPUT ;
    USE SIGNAL ;
    PORT
      LAYER M4 ;
        RECT 0.0000 408.5280 0.0840 408.5520 ;
    END
  END t_o[223]
  PIN t_o[224]
    DIRECTION OUTPUT ;
    USE SIGNAL ;
    PORT
      LAYER M4 ;
        RECT 0.0000 410.3520 0.0840 410.3760 ;
    END
  END t_o[224]
  PIN t_o[225]
    DIRECTION OUTPUT ;
    USE SIGNAL ;
    PORT
      LAYER M4 ;
        RECT 0.0000 412.1760 0.0840 412.2000 ;
    END
  END t_o[225]
  PIN t_o[226]
    DIRECTION OUTPUT ;
    USE SIGNAL ;
    PORT
      LAYER M4 ;
        RECT 0.0000 414.0000 0.0840 414.0240 ;
    END
  END t_o[226]
  PIN t_o[227]
    DIRECTION OUTPUT ;
    USE SIGNAL ;
    PORT
      LAYER M4 ;
        RECT 0.0000 415.8240 0.0840 415.8480 ;
    END
  END t_o[227]
  PIN t_o[228]
    DIRECTION OUTPUT ;
    USE SIGNAL ;
    PORT
      LAYER M4 ;
        RECT 0.0000 417.6480 0.0840 417.6720 ;
    END
  END t_o[228]
  PIN t_o[229]
    DIRECTION OUTPUT ;
    USE SIGNAL ;
    PORT
      LAYER M4 ;
        RECT 0.0000 419.4720 0.0840 419.4960 ;
    END
  END t_o[229]
  PIN t_o[22]
    DIRECTION OUTPUT ;
    USE SIGNAL ;
    PORT
      LAYER M4 ;
        RECT 0.0000 43.0560 0.0840 43.0800 ;
    END
  END t_o[22]
  PIN t_o[230]
    DIRECTION OUTPUT ;
    USE SIGNAL ;
    PORT
      LAYER M4 ;
        RECT 0.0000 421.2480 0.0840 421.2720 ;
    END
  END t_o[230]
  PIN t_o[231]
    DIRECTION OUTPUT ;
    USE SIGNAL ;
    PORT
      LAYER M4 ;
        RECT 0.0000 423.0720 0.0840 423.0960 ;
    END
  END t_o[231]
  PIN t_o[232]
    DIRECTION OUTPUT ;
    USE SIGNAL ;
    PORT
      LAYER M4 ;
        RECT 0.0000 424.8960 0.0840 424.9200 ;
    END
  END t_o[232]
  PIN t_o[233]
    DIRECTION OUTPUT ;
    USE SIGNAL ;
    PORT
      LAYER M4 ;
        RECT 0.0000 426.7200 0.0840 426.7440 ;
    END
  END t_o[233]
  PIN t_o[234]
    DIRECTION OUTPUT ;
    USE SIGNAL ;
    PORT
      LAYER M4 ;
        RECT 0.0000 428.5440 0.0840 428.5680 ;
    END
  END t_o[234]
  PIN t_o[235]
    DIRECTION OUTPUT ;
    USE SIGNAL ;
    PORT
      LAYER M4 ;
        RECT 0.0000 430.3680 0.0840 430.3920 ;
    END
  END t_o[235]
  PIN t_o[236]
    DIRECTION OUTPUT ;
    USE SIGNAL ;
    PORT
      LAYER M4 ;
        RECT 0.0000 432.1920 0.0840 432.2160 ;
    END
  END t_o[236]
  PIN t_o[237]
    DIRECTION OUTPUT ;
    USE SIGNAL ;
    PORT
      LAYER M4 ;
        RECT 0.0000 434.0160 0.0840 434.0400 ;
    END
  END t_o[237]
  PIN t_o[238]
    DIRECTION OUTPUT ;
    USE SIGNAL ;
    PORT
      LAYER M4 ;
        RECT 0.0000 435.7920 0.0840 435.8160 ;
    END
  END t_o[238]
  PIN t_o[239]
    DIRECTION OUTPUT ;
    USE SIGNAL ;
    PORT
      LAYER M4 ;
        RECT 0.0000 437.6160 0.0840 437.6400 ;
    END
  END t_o[239]
  PIN t_o[23]
    DIRECTION OUTPUT ;
    USE SIGNAL ;
    PORT
      LAYER M4 ;
        RECT 0.0000 44.8800 0.0840 44.9040 ;
    END
  END t_o[23]
  PIN t_o[240]
    DIRECTION OUTPUT ;
    USE SIGNAL ;
    PORT
      LAYER M4 ;
        RECT 0.0000 439.4400 0.0840 439.4640 ;
    END
  END t_o[240]
  PIN t_o[241]
    DIRECTION OUTPUT ;
    USE SIGNAL ;
    PORT
      LAYER M4 ;
        RECT 0.0000 441.2640 0.0840 441.2880 ;
    END
  END t_o[241]
  PIN t_o[242]
    DIRECTION OUTPUT ;
    USE SIGNAL ;
    PORT
      LAYER M4 ;
        RECT 0.0000 443.0880 0.0840 443.1120 ;
    END
  END t_o[242]
  PIN t_o[243]
    DIRECTION OUTPUT ;
    USE SIGNAL ;
    PORT
      LAYER M4 ;
        RECT 0.0000 444.9120 0.0840 444.9360 ;
    END
  END t_o[243]
  PIN t_o[244]
    DIRECTION OUTPUT ;
    USE SIGNAL ;
    PORT
      LAYER M4 ;
        RECT 0.0000 446.7360 0.0840 446.7600 ;
    END
  END t_o[244]
  PIN t_o[245]
    DIRECTION OUTPUT ;
    USE SIGNAL ;
    PORT
      LAYER M4 ;
        RECT 0.0000 448.5600 0.0840 448.5840 ;
    END
  END t_o[245]
  PIN t_o[246]
    DIRECTION OUTPUT ;
    USE SIGNAL ;
    PORT
      LAYER M4 ;
        RECT 0.0000 450.3840 0.0840 450.4080 ;
    END
  END t_o[246]
  PIN t_o[247]
    DIRECTION OUTPUT ;
    USE SIGNAL ;
    PORT
      LAYER M4 ;
        RECT 0.0000 452.1600 0.0840 452.1840 ;
    END
  END t_o[247]
  PIN t_o[248]
    DIRECTION OUTPUT ;
    USE SIGNAL ;
    PORT
      LAYER M4 ;
        RECT 0.0000 453.9840 0.0840 454.0080 ;
    END
  END t_o[248]
  PIN t_o[249]
    DIRECTION OUTPUT ;
    USE SIGNAL ;
    PORT
      LAYER M4 ;
        RECT 0.0000 455.8080 0.0840 455.8320 ;
    END
  END t_o[249]
  PIN t_o[24]
    DIRECTION OUTPUT ;
    USE SIGNAL ;
    PORT
      LAYER M4 ;
        RECT 0.0000 46.7040 0.0840 46.7280 ;
    END
  END t_o[24]
  PIN t_o[250]
    DIRECTION OUTPUT ;
    USE SIGNAL ;
    PORT
      LAYER M4 ;
        RECT 0.0000 457.6320 0.0840 457.6560 ;
    END
  END t_o[250]
  PIN t_o[251]
    DIRECTION OUTPUT ;
    USE SIGNAL ;
    PORT
      LAYER M4 ;
        RECT 0.0000 459.4560 0.0840 459.4800 ;
    END
  END t_o[251]
  PIN t_o[252]
    DIRECTION OUTPUT ;
    USE SIGNAL ;
    PORT
      LAYER M4 ;
        RECT 0.0000 461.2800 0.0840 461.3040 ;
    END
  END t_o[252]
  PIN t_o[253]
    DIRECTION OUTPUT ;
    USE SIGNAL ;
    PORT
      LAYER M4 ;
        RECT 0.0000 463.1040 0.0840 463.1280 ;
    END
  END t_o[253]
  PIN t_o[254]
    DIRECTION OUTPUT ;
    USE SIGNAL ;
    PORT
      LAYER M4 ;
        RECT 0.0000 464.9280 0.0840 464.9520 ;
    END
  END t_o[254]
  PIN t_o[255]
    DIRECTION OUTPUT ;
    USE SIGNAL ;
    PORT
      LAYER M4 ;
        RECT 0.0000 466.7040 0.0840 466.7280 ;
    END
  END t_o[255]
  PIN t_o[256]
    DIRECTION OUTPUT ;
    USE SIGNAL ;
    PORT
      LAYER M4 ;
        RECT 0.0000 468.5280 0.0840 468.5520 ;
    END
  END t_o[256]
  PIN t_o[257]
    DIRECTION OUTPUT ;
    USE SIGNAL ;
    PORT
      LAYER M4 ;
        RECT 0.0000 470.3520 0.0840 470.3760 ;
    END
  END t_o[257]
  PIN t_o[258]
    DIRECTION OUTPUT ;
    USE SIGNAL ;
    PORT
      LAYER M4 ;
        RECT 0.0000 472.1760 0.0840 472.2000 ;
    END
  END t_o[258]
  PIN t_o[259]
    DIRECTION OUTPUT ;
    USE SIGNAL ;
    PORT
      LAYER M4 ;
        RECT 0.0000 474.0000 0.0840 474.0240 ;
    END
  END t_o[259]
  PIN t_o[25]
    DIRECTION OUTPUT ;
    USE SIGNAL ;
    PORT
      LAYER M4 ;
        RECT 0.0000 48.5280 0.0840 48.5520 ;
    END
  END t_o[25]
  PIN t_o[260]
    DIRECTION OUTPUT ;
    USE SIGNAL ;
    PORT
      LAYER M4 ;
        RECT 0.0000 475.8240 0.0840 475.8480 ;
    END
  END t_o[260]
  PIN t_o[261]
    DIRECTION OUTPUT ;
    USE SIGNAL ;
    PORT
      LAYER M4 ;
        RECT 0.0000 477.6480 0.0840 477.6720 ;
    END
  END t_o[261]
  PIN t_o[262]
    DIRECTION OUTPUT ;
    USE SIGNAL ;
    PORT
      LAYER M4 ;
        RECT 0.0000 479.4720 0.0840 479.4960 ;
    END
  END t_o[262]
  PIN t_o[263]
    DIRECTION OUTPUT ;
    USE SIGNAL ;
    PORT
      LAYER M4 ;
        RECT 0.0000 481.2480 0.0840 481.2720 ;
    END
  END t_o[263]
  PIN t_o[264]
    DIRECTION OUTPUT ;
    USE SIGNAL ;
    PORT
      LAYER M4 ;
        RECT 0.0000 483.0720 0.0840 483.0960 ;
    END
  END t_o[264]
  PIN t_o[265]
    DIRECTION OUTPUT ;
    USE SIGNAL ;
    PORT
      LAYER M4 ;
        RECT 0.0000 484.8960 0.0840 484.9200 ;
    END
  END t_o[265]
  PIN t_o[266]
    DIRECTION OUTPUT ;
    USE SIGNAL ;
    PORT
      LAYER M4 ;
        RECT 0.0000 486.7200 0.0840 486.7440 ;
    END
  END t_o[266]
  PIN t_o[267]
    DIRECTION OUTPUT ;
    USE SIGNAL ;
    PORT
      LAYER M4 ;
        RECT 0.0000 488.5440 0.0840 488.5680 ;
    END
  END t_o[267]
  PIN t_o[268]
    DIRECTION OUTPUT ;
    USE SIGNAL ;
    PORT
      LAYER M4 ;
        RECT 0.0000 490.3680 0.0840 490.3920 ;
    END
  END t_o[268]
  PIN t_o[269]
    DIRECTION OUTPUT ;
    USE SIGNAL ;
    PORT
      LAYER M4 ;
        RECT 0.0000 492.1920 0.0840 492.2160 ;
    END
  END t_o[269]
  PIN t_o[26]
    DIRECTION OUTPUT ;
    USE SIGNAL ;
    PORT
      LAYER M4 ;
        RECT 0.0000 50.3520 0.0840 50.3760 ;
    END
  END t_o[26]
  PIN t_o[270]
    DIRECTION OUTPUT ;
    USE SIGNAL ;
    PORT
      LAYER M4 ;
        RECT 0.0000 494.0160 0.0840 494.0400 ;
    END
  END t_o[270]
  PIN t_o[271]
    DIRECTION OUTPUT ;
    USE SIGNAL ;
    PORT
      LAYER M4 ;
        RECT 0.0000 495.8400 0.0840 495.8640 ;
    END
  END t_o[271]
  PIN t_o[272]
    DIRECTION OUTPUT ;
    USE SIGNAL ;
    PORT
      LAYER M4 ;
        RECT 0.0000 497.6160 0.0840 497.6400 ;
    END
  END t_o[272]
  PIN t_o[273]
    DIRECTION OUTPUT ;
    USE SIGNAL ;
    PORT
      LAYER M4 ;
        RECT 0.0000 499.4400 0.0840 499.4640 ;
    END
  END t_o[273]
  PIN t_o[274]
    DIRECTION OUTPUT ;
    USE SIGNAL ;
    PORT
      LAYER M4 ;
        RECT 0.0000 501.2640 0.0840 501.2880 ;
    END
  END t_o[274]
  PIN t_o[275]
    DIRECTION OUTPUT ;
    USE SIGNAL ;
    PORT
      LAYER M4 ;
        RECT 0.0000 503.0880 0.0840 503.1120 ;
    END
  END t_o[275]
  PIN t_o[276]
    DIRECTION OUTPUT ;
    USE SIGNAL ;
    PORT
      LAYER M4 ;
        RECT 0.0000 504.9120 0.0840 504.9360 ;
    END
  END t_o[276]
  PIN t_o[277]
    DIRECTION OUTPUT ;
    USE SIGNAL ;
    PORT
      LAYER M4 ;
        RECT 0.0000 506.7360 0.0840 506.7600 ;
    END
  END t_o[277]
  PIN t_o[278]
    DIRECTION OUTPUT ;
    USE SIGNAL ;
    PORT
      LAYER M4 ;
        RECT 0.0000 508.5600 0.0840 508.5840 ;
    END
  END t_o[278]
  PIN t_o[279]
    DIRECTION OUTPUT ;
    USE SIGNAL ;
    PORT
      LAYER M4 ;
        RECT 0.0000 510.3840 0.0840 510.4080 ;
    END
  END t_o[279]
  PIN t_o[27]
    DIRECTION OUTPUT ;
    USE SIGNAL ;
    PORT
      LAYER M4 ;
        RECT 0.0000 52.1280 0.0840 52.1520 ;
    END
  END t_o[27]
  PIN t_o[280]
    DIRECTION OUTPUT ;
    USE SIGNAL ;
    PORT
      LAYER M4 ;
        RECT 0.0000 512.1600 0.0840 512.1840 ;
    END
  END t_o[280]
  PIN t_o[281]
    DIRECTION OUTPUT ;
    USE SIGNAL ;
    PORT
      LAYER M4 ;
        RECT 0.0000 513.9840 0.0840 514.0080 ;
    END
  END t_o[281]
  PIN t_o[282]
    DIRECTION OUTPUT ;
    USE SIGNAL ;
    PORT
      LAYER M4 ;
        RECT 0.0000 515.8080 0.0840 515.8320 ;
    END
  END t_o[282]
  PIN t_o[283]
    DIRECTION OUTPUT ;
    USE SIGNAL ;
    PORT
      LAYER M4 ;
        RECT 0.0000 517.6320 0.0840 517.6560 ;
    END
  END t_o[283]
  PIN t_o[284]
    DIRECTION OUTPUT ;
    USE SIGNAL ;
    PORT
      LAYER M4 ;
        RECT 0.0000 519.4560 0.0840 519.4800 ;
    END
  END t_o[284]
  PIN t_o[285]
    DIRECTION OUTPUT ;
    USE SIGNAL ;
    PORT
      LAYER M4 ;
        RECT 0.0000 521.2800 0.0840 521.3040 ;
    END
  END t_o[285]
  PIN t_o[286]
    DIRECTION OUTPUT ;
    USE SIGNAL ;
    PORT
      LAYER M4 ;
        RECT 0.0000 523.1040 0.0840 523.1280 ;
    END
  END t_o[286]
  PIN t_o[287]
    DIRECTION OUTPUT ;
    USE SIGNAL ;
    PORT
      LAYER M4 ;
        RECT 0.0000 524.9280 0.0840 524.9520 ;
    END
  END t_o[287]
  PIN t_o[288]
    DIRECTION OUTPUT ;
    USE SIGNAL ;
    PORT
      LAYER M4 ;
        RECT 0.0000 526.7520 0.0840 526.7760 ;
    END
  END t_o[288]
  PIN t_o[289]
    DIRECTION OUTPUT ;
    USE SIGNAL ;
    PORT
      LAYER M4 ;
        RECT 0.0000 528.5280 0.0840 528.5520 ;
    END
  END t_o[289]
  PIN t_o[28]
    DIRECTION OUTPUT ;
    USE SIGNAL ;
    PORT
      LAYER M4 ;
        RECT 0.0000 53.9520 0.0840 53.9760 ;
    END
  END t_o[28]
  PIN t_o[290]
    DIRECTION OUTPUT ;
    USE SIGNAL ;
    PORT
      LAYER M4 ;
        RECT 0.0000 530.3520 0.0840 530.3760 ;
    END
  END t_o[290]
  PIN t_o[291]
    DIRECTION OUTPUT ;
    USE SIGNAL ;
    PORT
      LAYER M4 ;
        RECT 0.0000 532.1760 0.0840 532.2000 ;
    END
  END t_o[291]
  PIN t_o[292]
    DIRECTION OUTPUT ;
    USE SIGNAL ;
    PORT
      LAYER M4 ;
        RECT 0.0000 534.0000 0.0840 534.0240 ;
    END
  END t_o[292]
  PIN t_o[293]
    DIRECTION OUTPUT ;
    USE SIGNAL ;
    PORT
      LAYER M4 ;
        RECT 0.0000 535.8240 0.0840 535.8480 ;
    END
  END t_o[293]
  PIN t_o[294]
    DIRECTION OUTPUT ;
    USE SIGNAL ;
    PORT
      LAYER M4 ;
        RECT 0.0000 537.6480 0.0840 537.6720 ;
    END
  END t_o[294]
  PIN t_o[295]
    DIRECTION OUTPUT ;
    USE SIGNAL ;
    PORT
      LAYER M4 ;
        RECT 0.0000 539.4720 0.0840 539.4960 ;
    END
  END t_o[295]
  PIN t_o[296]
    DIRECTION OUTPUT ;
    USE SIGNAL ;
    PORT
      LAYER M4 ;
        RECT 0.0000 541.2960 0.0840 541.3200 ;
    END
  END t_o[296]
  PIN t_o[297]
    DIRECTION OUTPUT ;
    USE SIGNAL ;
    PORT
      LAYER M4 ;
        RECT 0.0000 543.0720 0.0840 543.0960 ;
    END
  END t_o[297]
  PIN t_o[298]
    DIRECTION OUTPUT ;
    USE SIGNAL ;
    PORT
      LAYER M4 ;
        RECT 0.0000 544.8960 0.0840 544.9200 ;
    END
  END t_o[298]
  PIN t_o[299]
    DIRECTION OUTPUT ;
    USE SIGNAL ;
    PORT
      LAYER M4 ;
        RECT 0.0000 546.7200 0.0840 546.7440 ;
    END
  END t_o[299]
  PIN t_o[29]
    DIRECTION OUTPUT ;
    USE SIGNAL ;
    PORT
      LAYER M4 ;
        RECT 0.0000 55.7760 0.0840 55.8000 ;
    END
  END t_o[29]
  PIN t_o[2]
    DIRECTION OUTPUT ;
    USE SIGNAL ;
    PORT
      LAYER M4 ;
        RECT 0.0000 6.6720 0.0840 6.6960 ;
    END
  END t_o[2]
  PIN t_o[300]
    DIRECTION OUTPUT ;
    USE SIGNAL ;
    PORT
      LAYER M4 ;
        RECT 0.0000 548.5440 0.0840 548.5680 ;
    END
  END t_o[300]
  PIN t_o[301]
    DIRECTION OUTPUT ;
    USE SIGNAL ;
    PORT
      LAYER M4 ;
        RECT 0.0000 550.3680 0.0840 550.3920 ;
    END
  END t_o[301]
  PIN t_o[302]
    DIRECTION OUTPUT ;
    USE SIGNAL ;
    PORT
      LAYER M4 ;
        RECT 0.0000 552.1920 0.0840 552.2160 ;
    END
  END t_o[302]
  PIN t_o[303]
    DIRECTION OUTPUT ;
    USE SIGNAL ;
    PORT
      LAYER M4 ;
        RECT 0.0000 554.0160 0.0840 554.0400 ;
    END
  END t_o[303]
  PIN t_o[304]
    DIRECTION OUTPUT ;
    USE SIGNAL ;
    PORT
      LAYER M4 ;
        RECT 0.0000 555.8400 0.0840 555.8640 ;
    END
  END t_o[304]
  PIN t_o[305]
    DIRECTION OUTPUT ;
    USE SIGNAL ;
    PORT
      LAYER M4 ;
        RECT 0.0000 557.6640 0.0840 557.6880 ;
    END
  END t_o[305]
  PIN t_o[306]
    DIRECTION OUTPUT ;
    USE SIGNAL ;
    PORT
      LAYER M4 ;
        RECT 0.0000 559.4400 0.0840 559.4640 ;
    END
  END t_o[306]
  PIN t_o[307]
    DIRECTION OUTPUT ;
    USE SIGNAL ;
    PORT
      LAYER M4 ;
        RECT 0.0000 561.2640 0.0840 561.2880 ;
    END
  END t_o[307]
  PIN t_o[308]
    DIRECTION OUTPUT ;
    USE SIGNAL ;
    PORT
      LAYER M4 ;
        RECT 0.0000 563.0880 0.0840 563.1120 ;
    END
  END t_o[308]
  PIN t_o[309]
    DIRECTION OUTPUT ;
    USE SIGNAL ;
    PORT
      LAYER M4 ;
        RECT 0.0000 564.9120 0.0840 564.9360 ;
    END
  END t_o[309]
  PIN t_o[30]
    DIRECTION OUTPUT ;
    USE SIGNAL ;
    PORT
      LAYER M4 ;
        RECT 0.0000 57.6000 0.0840 57.6240 ;
    END
  END t_o[30]
  PIN t_o[310]
    DIRECTION OUTPUT ;
    USE SIGNAL ;
    PORT
      LAYER M4 ;
        RECT 0.0000 566.7360 0.0840 566.7600 ;
    END
  END t_o[310]
  PIN t_o[311]
    DIRECTION OUTPUT ;
    USE SIGNAL ;
    PORT
      LAYER M4 ;
        RECT 0.0000 568.5600 0.0840 568.5840 ;
    END
  END t_o[311]
  PIN t_o[312]
    DIRECTION OUTPUT ;
    USE SIGNAL ;
    PORT
      LAYER M4 ;
        RECT 0.0000 570.3840 0.0840 570.4080 ;
    END
  END t_o[312]
  PIN t_o[313]
    DIRECTION OUTPUT ;
    USE SIGNAL ;
    PORT
      LAYER M4 ;
        RECT 0.0000 572.2080 0.0840 572.2320 ;
    END
  END t_o[313]
  PIN t_o[314]
    DIRECTION OUTPUT ;
    USE SIGNAL ;
    PORT
      LAYER M4 ;
        RECT 0.0000 573.9840 0.0840 574.0080 ;
    END
  END t_o[314]
  PIN t_o[315]
    DIRECTION OUTPUT ;
    USE SIGNAL ;
    PORT
      LAYER M4 ;
        RECT 0.0000 575.8080 0.0840 575.8320 ;
    END
  END t_o[315]
  PIN t_o[316]
    DIRECTION OUTPUT ;
    USE SIGNAL ;
    PORT
      LAYER M4 ;
        RECT 0.0000 577.6320 0.0840 577.6560 ;
    END
  END t_o[316]
  PIN t_o[317]
    DIRECTION OUTPUT ;
    USE SIGNAL ;
    PORT
      LAYER M4 ;
        RECT 0.0000 579.4560 0.0840 579.4800 ;
    END
  END t_o[317]
  PIN t_o[318]
    DIRECTION OUTPUT ;
    USE SIGNAL ;
    PORT
      LAYER M4 ;
        RECT 0.0000 581.2800 0.0840 581.3040 ;
    END
  END t_o[318]
  PIN t_o[319]
    DIRECTION OUTPUT ;
    USE SIGNAL ;
    PORT
      LAYER M4 ;
        RECT 0.0000 583.1040 0.0840 583.1280 ;
    END
  END t_o[319]
  PIN t_o[31]
    DIRECTION OUTPUT ;
    USE SIGNAL ;
    PORT
      LAYER M4 ;
        RECT 0.0000 59.4240 0.0840 59.4480 ;
    END
  END t_o[31]
  PIN t_o[320]
    DIRECTION OUTPUT ;
    USE SIGNAL ;
    PORT
      LAYER M4 ;
        RECT 0.0000 584.9280 0.0840 584.9520 ;
    END
  END t_o[320]
  PIN t_o[321]
    DIRECTION OUTPUT ;
    USE SIGNAL ;
    PORT
      LAYER M4 ;
        RECT 0.0000 586.7520 0.0840 586.7760 ;
    END
  END t_o[321]
  PIN t_o[322]
    DIRECTION OUTPUT ;
    USE SIGNAL ;
    PORT
      LAYER M4 ;
        RECT 0.0000 588.5280 0.0840 588.5520 ;
    END
  END t_o[322]
  PIN t_o[323]
    DIRECTION OUTPUT ;
    USE SIGNAL ;
    PORT
      LAYER M4 ;
        RECT 0.0000 590.3520 0.0840 590.3760 ;
    END
  END t_o[323]
  PIN t_o[324]
    DIRECTION OUTPUT ;
    USE SIGNAL ;
    PORT
      LAYER M4 ;
        RECT 0.0000 592.1760 0.0840 592.2000 ;
    END
  END t_o[324]
  PIN t_o[325]
    DIRECTION OUTPUT ;
    USE SIGNAL ;
    PORT
      LAYER M4 ;
        RECT 0.0000 594.0000 0.0840 594.0240 ;
    END
  END t_o[325]
  PIN t_o[326]
    DIRECTION OUTPUT ;
    USE SIGNAL ;
    PORT
      LAYER M4 ;
        RECT 0.0000 595.8240 0.0840 595.8480 ;
    END
  END t_o[326]
  PIN t_o[327]
    DIRECTION OUTPUT ;
    USE SIGNAL ;
    PORT
      LAYER M4 ;
        RECT 0.0000 597.6480 0.0840 597.6720 ;
    END
  END t_o[327]
  PIN t_o[328]
    DIRECTION OUTPUT ;
    USE SIGNAL ;
    PORT
      LAYER M4 ;
        RECT 0.0000 599.4720 0.0840 599.4960 ;
    END
  END t_o[328]
  PIN t_o[329]
    DIRECTION OUTPUT ;
    USE SIGNAL ;
    PORT
      LAYER M4 ;
        RECT 0.0000 601.2960 0.0840 601.3200 ;
    END
  END t_o[329]
  PIN t_o[32]
    DIRECTION OUTPUT ;
    USE SIGNAL ;
    PORT
      LAYER M4 ;
        RECT 0.0000 61.2480 0.0840 61.2720 ;
    END
  END t_o[32]
  PIN t_o[330]
    DIRECTION OUTPUT ;
    USE SIGNAL ;
    PORT
      LAYER M4 ;
        RECT 0.0000 603.1200 0.0840 603.1440 ;
    END
  END t_o[330]
  PIN t_o[331]
    DIRECTION OUTPUT ;
    USE SIGNAL ;
    PORT
      LAYER M4 ;
        RECT 0.0000 604.8960 0.0840 604.9200 ;
    END
  END t_o[331]
  PIN t_o[332]
    DIRECTION OUTPUT ;
    USE SIGNAL ;
    PORT
      LAYER M4 ;
        RECT 0.0000 606.7200 0.0840 606.7440 ;
    END
  END t_o[332]
  PIN t_o[333]
    DIRECTION OUTPUT ;
    USE SIGNAL ;
    PORT
      LAYER M4 ;
        RECT 0.0000 608.5440 0.0840 608.5680 ;
    END
  END t_o[333]
  PIN t_o[334]
    DIRECTION OUTPUT ;
    USE SIGNAL ;
    PORT
      LAYER M4 ;
        RECT 0.0000 610.3680 0.0840 610.3920 ;
    END
  END t_o[334]
  PIN t_o[335]
    DIRECTION OUTPUT ;
    USE SIGNAL ;
    PORT
      LAYER M4 ;
        RECT 0.0000 612.1920 0.0840 612.2160 ;
    END
  END t_o[335]
  PIN t_o[336]
    DIRECTION OUTPUT ;
    USE SIGNAL ;
    PORT
      LAYER M4 ;
        RECT 0.0000 614.0160 0.0840 614.0400 ;
    END
  END t_o[336]
  PIN t_o[337]
    DIRECTION OUTPUT ;
    USE SIGNAL ;
    PORT
      LAYER M4 ;
        RECT 0.0000 615.8400 0.0840 615.8640 ;
    END
  END t_o[337]
  PIN t_o[338]
    DIRECTION OUTPUT ;
    USE SIGNAL ;
    PORT
      LAYER M4 ;
        RECT 0.0000 617.6640 0.0840 617.6880 ;
    END
  END t_o[338]
  PIN t_o[339]
    DIRECTION OUTPUT ;
    USE SIGNAL ;
    PORT
      LAYER M4 ;
        RECT 0.0000 619.4400 0.0840 619.4640 ;
    END
  END t_o[339]
  PIN t_o[33]
    DIRECTION OUTPUT ;
    USE SIGNAL ;
    PORT
      LAYER M4 ;
        RECT 0.0000 63.0720 0.0840 63.0960 ;
    END
  END t_o[33]
  PIN t_o[340]
    DIRECTION OUTPUT ;
    USE SIGNAL ;
    PORT
      LAYER M4 ;
        RECT 0.0000 621.2640 0.0840 621.2880 ;
    END
  END t_o[340]
  PIN t_o[341]
    DIRECTION OUTPUT ;
    USE SIGNAL ;
    PORT
      LAYER M4 ;
        RECT 0.0000 623.0880 0.0840 623.1120 ;
    END
  END t_o[341]
  PIN t_o[342]
    DIRECTION OUTPUT ;
    USE SIGNAL ;
    PORT
      LAYER M4 ;
        RECT 0.0000 624.9120 0.0840 624.9360 ;
    END
  END t_o[342]
  PIN t_o[343]
    DIRECTION OUTPUT ;
    USE SIGNAL ;
    PORT
      LAYER M4 ;
        RECT 0.0000 626.7360 0.0840 626.7600 ;
    END
  END t_o[343]
  PIN t_o[344]
    DIRECTION OUTPUT ;
    USE SIGNAL ;
    PORT
      LAYER M4 ;
        RECT 0.0000 628.5600 0.0840 628.5840 ;
    END
  END t_o[344]
  PIN t_o[345]
    DIRECTION OUTPUT ;
    USE SIGNAL ;
    PORT
      LAYER M4 ;
        RECT 0.0000 630.3840 0.0840 630.4080 ;
    END
  END t_o[345]
  PIN t_o[346]
    DIRECTION OUTPUT ;
    USE SIGNAL ;
    PORT
      LAYER M4 ;
        RECT 0.0000 632.2080 0.0840 632.2320 ;
    END
  END t_o[346]
  PIN t_o[347]
    DIRECTION OUTPUT ;
    USE SIGNAL ;
    PORT
      LAYER M4 ;
        RECT 0.0000 634.0320 0.0840 634.0560 ;
    END
  END t_o[347]
  PIN t_o[348]
    DIRECTION OUTPUT ;
    USE SIGNAL ;
    PORT
      LAYER M4 ;
        RECT 0.0000 635.8080 0.0840 635.8320 ;
    END
  END t_o[348]
  PIN t_o[349]
    DIRECTION OUTPUT ;
    USE SIGNAL ;
    PORT
      LAYER M4 ;
        RECT 0.0000 637.6320 0.0840 637.6560 ;
    END
  END t_o[349]
  PIN t_o[34]
    DIRECTION OUTPUT ;
    USE SIGNAL ;
    PORT
      LAYER M4 ;
        RECT 0.0000 64.8960 0.0840 64.9200 ;
    END
  END t_o[34]
  PIN t_o[350]
    DIRECTION OUTPUT ;
    USE SIGNAL ;
    PORT
      LAYER M4 ;
        RECT 0.0000 639.4560 0.0840 639.4800 ;
    END
  END t_o[350]
  PIN t_o[351]
    DIRECTION OUTPUT ;
    USE SIGNAL ;
    PORT
      LAYER M4 ;
        RECT 0.0000 641.2800 0.0840 641.3040 ;
    END
  END t_o[351]
  PIN t_o[352]
    DIRECTION OUTPUT ;
    USE SIGNAL ;
    PORT
      LAYER M4 ;
        RECT 0.0000 643.1040 0.0840 643.1280 ;
    END
  END t_o[352]
  PIN t_o[353]
    DIRECTION OUTPUT ;
    USE SIGNAL ;
    PORT
      LAYER M4 ;
        RECT 0.0000 644.9280 0.0840 644.9520 ;
    END
  END t_o[353]
  PIN t_o[35]
    DIRECTION OUTPUT ;
    USE SIGNAL ;
    PORT
      LAYER M4 ;
        RECT 0.0000 66.7200 0.0840 66.7440 ;
    END
  END t_o[35]
  PIN t_o[36]
    DIRECTION OUTPUT ;
    USE SIGNAL ;
    PORT
      LAYER M4 ;
        RECT 0.0000 68.4960 0.0840 68.5200 ;
    END
  END t_o[36]
  PIN t_o[37]
    DIRECTION OUTPUT ;
    USE SIGNAL ;
    PORT
      LAYER M4 ;
        RECT 0.0000 70.3200 0.0840 70.3440 ;
    END
  END t_o[37]
  PIN t_o[38]
    DIRECTION OUTPUT ;
    USE SIGNAL ;
    PORT
      LAYER M4 ;
        RECT 0.0000 72.1440 0.0840 72.1680 ;
    END
  END t_o[38]
  PIN t_o[39]
    DIRECTION OUTPUT ;
    USE SIGNAL ;
    PORT
      LAYER M4 ;
        RECT 0.0000 73.9680 0.0840 73.9920 ;
    END
  END t_o[39]
  PIN t_o[3]
    DIRECTION OUTPUT ;
    USE SIGNAL ;
    PORT
      LAYER M4 ;
        RECT 0.0000 8.4960 0.0840 8.5200 ;
    END
  END t_o[3]
  PIN t_o[40]
    DIRECTION OUTPUT ;
    USE SIGNAL ;
    PORT
      LAYER M4 ;
        RECT 0.0000 75.7920 0.0840 75.8160 ;
    END
  END t_o[40]
  PIN t_o[41]
    DIRECTION OUTPUT ;
    USE SIGNAL ;
    PORT
      LAYER M4 ;
        RECT 0.0000 77.6160 0.0840 77.6400 ;
    END
  END t_o[41]
  PIN t_o[42]
    DIRECTION OUTPUT ;
    USE SIGNAL ;
    PORT
      LAYER M4 ;
        RECT 0.0000 79.4400 0.0840 79.4640 ;
    END
  END t_o[42]
  PIN t_o[43]
    DIRECTION OUTPUT ;
    USE SIGNAL ;
    PORT
      LAYER M4 ;
        RECT 0.0000 81.2640 0.0840 81.2880 ;
    END
  END t_o[43]
  PIN t_o[44]
    DIRECTION OUTPUT ;
    USE SIGNAL ;
    PORT
      LAYER M4 ;
        RECT 0.0000 83.0400 0.0840 83.0640 ;
    END
  END t_o[44]
  PIN t_o[45]
    DIRECTION OUTPUT ;
    USE SIGNAL ;
    PORT
      LAYER M4 ;
        RECT 0.0000 84.8640 0.0840 84.8880 ;
    END
  END t_o[45]
  PIN t_o[46]
    DIRECTION OUTPUT ;
    USE SIGNAL ;
    PORT
      LAYER M4 ;
        RECT 0.0000 86.6880 0.0840 86.7120 ;
    END
  END t_o[46]
  PIN t_o[47]
    DIRECTION OUTPUT ;
    USE SIGNAL ;
    PORT
      LAYER M4 ;
        RECT 0.0000 88.5120 0.0840 88.5360 ;
    END
  END t_o[47]
  PIN t_o[48]
    DIRECTION OUTPUT ;
    USE SIGNAL ;
    PORT
      LAYER M4 ;
        RECT 0.0000 90.3360 0.0840 90.3600 ;
    END
  END t_o[48]
  PIN t_o[49]
    DIRECTION OUTPUT ;
    USE SIGNAL ;
    PORT
      LAYER M4 ;
        RECT 0.0000 92.1600 0.0840 92.1840 ;
    END
  END t_o[49]
  PIN t_o[4]
    DIRECTION OUTPUT ;
    USE SIGNAL ;
    PORT
      LAYER M4 ;
        RECT 0.0000 10.3200 0.0840 10.3440 ;
    END
  END t_o[4]
  PIN t_o[50]
    DIRECTION OUTPUT ;
    USE SIGNAL ;
    PORT
      LAYER M4 ;
        RECT 0.0000 93.9840 0.0840 94.0080 ;
    END
  END t_o[50]
  PIN t_o[51]
    DIRECTION OUTPUT ;
    USE SIGNAL ;
    PORT
      LAYER M4 ;
        RECT 0.0000 95.8080 0.0840 95.8320 ;
    END
  END t_o[51]
  PIN t_o[52]
    DIRECTION OUTPUT ;
    USE SIGNAL ;
    PORT
      LAYER M4 ;
        RECT 0.0000 97.6320 0.0840 97.6560 ;
    END
  END t_o[52]
  PIN t_o[53]
    DIRECTION OUTPUT ;
    USE SIGNAL ;
    PORT
      LAYER M4 ;
        RECT 0.0000 99.4080 0.0840 99.4320 ;
    END
  END t_o[53]
  PIN t_o[54]
    DIRECTION OUTPUT ;
    USE SIGNAL ;
    PORT
      LAYER M4 ;
        RECT 0.0000 101.2320 0.0840 101.2560 ;
    END
  END t_o[54]
  PIN t_o[55]
    DIRECTION OUTPUT ;
    USE SIGNAL ;
    PORT
      LAYER M4 ;
        RECT 0.0000 103.0560 0.0840 103.0800 ;
    END
  END t_o[55]
  PIN t_o[56]
    DIRECTION OUTPUT ;
    USE SIGNAL ;
    PORT
      LAYER M4 ;
        RECT 0.0000 104.8800 0.0840 104.9040 ;
    END
  END t_o[56]
  PIN t_o[57]
    DIRECTION OUTPUT ;
    USE SIGNAL ;
    PORT
      LAYER M4 ;
        RECT 0.0000 106.7040 0.0840 106.7280 ;
    END
  END t_o[57]
  PIN t_o[58]
    DIRECTION OUTPUT ;
    USE SIGNAL ;
    PORT
      LAYER M4 ;
        RECT 0.0000 108.5280 0.0840 108.5520 ;
    END
  END t_o[58]
  PIN t_o[59]
    DIRECTION OUTPUT ;
    USE SIGNAL ;
    PORT
      LAYER M4 ;
        RECT 0.0000 110.3520 0.0840 110.3760 ;
    END
  END t_o[59]
  PIN t_o[5]
    DIRECTION OUTPUT ;
    USE SIGNAL ;
    PORT
      LAYER M4 ;
        RECT 0.0000 12.1440 0.0840 12.1680 ;
    END
  END t_o[5]
  PIN t_o[60]
    DIRECTION OUTPUT ;
    USE SIGNAL ;
    PORT
      LAYER M4 ;
        RECT 0.0000 112.1760 0.0840 112.2000 ;
    END
  END t_o[60]
  PIN t_o[61]
    DIRECTION OUTPUT ;
    USE SIGNAL ;
    PORT
      LAYER M4 ;
        RECT 0.0000 113.9520 0.0840 113.9760 ;
    END
  END t_o[61]
  PIN t_o[62]
    DIRECTION OUTPUT ;
    USE SIGNAL ;
    PORT
      LAYER M4 ;
        RECT 0.0000 115.7760 0.0840 115.8000 ;
    END
  END t_o[62]
  PIN t_o[63]
    DIRECTION OUTPUT ;
    USE SIGNAL ;
    PORT
      LAYER M4 ;
        RECT 0.0000 117.6000 0.0840 117.6240 ;
    END
  END t_o[63]
  PIN t_o[64]
    DIRECTION OUTPUT ;
    USE SIGNAL ;
    PORT
      LAYER M4 ;
        RECT 0.0000 119.4240 0.0840 119.4480 ;
    END
  END t_o[64]
  PIN t_o[65]
    DIRECTION OUTPUT ;
    USE SIGNAL ;
    PORT
      LAYER M4 ;
        RECT 0.0000 121.2480 0.0840 121.2720 ;
    END
  END t_o[65]
  PIN t_o[66]
    DIRECTION OUTPUT ;
    USE SIGNAL ;
    PORT
      LAYER M4 ;
        RECT 0.0000 123.0720 0.0840 123.0960 ;
    END
  END t_o[66]
  PIN t_o[67]
    DIRECTION OUTPUT ;
    USE SIGNAL ;
    PORT
      LAYER M4 ;
        RECT 0.0000 124.8960 0.0840 124.9200 ;
    END
  END t_o[67]
  PIN t_o[68]
    DIRECTION OUTPUT ;
    USE SIGNAL ;
    PORT
      LAYER M4 ;
        RECT 0.0000 126.7200 0.0840 126.7440 ;
    END
  END t_o[68]
  PIN t_o[69]
    DIRECTION OUTPUT ;
    USE SIGNAL ;
    PORT
      LAYER M4 ;
        RECT 0.0000 128.5440 0.0840 128.5680 ;
    END
  END t_o[69]
  PIN t_o[6]
    DIRECTION OUTPUT ;
    USE SIGNAL ;
    PORT
      LAYER M4 ;
        RECT 0.0000 13.9680 0.0840 13.9920 ;
    END
  END t_o[6]
  PIN t_o[70]
    DIRECTION OUTPUT ;
    USE SIGNAL ;
    PORT
      LAYER M4 ;
        RECT 0.0000 130.3200 0.0840 130.3440 ;
    END
  END t_o[70]
  PIN t_o[71]
    DIRECTION OUTPUT ;
    USE SIGNAL ;
    PORT
      LAYER M4 ;
        RECT 0.0000 132.1440 0.0840 132.1680 ;
    END
  END t_o[71]
  PIN t_o[72]
    DIRECTION OUTPUT ;
    USE SIGNAL ;
    PORT
      LAYER M4 ;
        RECT 0.0000 133.9680 0.0840 133.9920 ;
    END
  END t_o[72]
  PIN t_o[73]
    DIRECTION OUTPUT ;
    USE SIGNAL ;
    PORT
      LAYER M4 ;
        RECT 0.0000 135.7920 0.0840 135.8160 ;
    END
  END t_o[73]
  PIN t_o[74]
    DIRECTION OUTPUT ;
    USE SIGNAL ;
    PORT
      LAYER M4 ;
        RECT 0.0000 137.6160 0.0840 137.6400 ;
    END
  END t_o[74]
  PIN t_o[75]
    DIRECTION OUTPUT ;
    USE SIGNAL ;
    PORT
      LAYER M4 ;
        RECT 0.0000 139.4400 0.0840 139.4640 ;
    END
  END t_o[75]
  PIN t_o[76]
    DIRECTION OUTPUT ;
    USE SIGNAL ;
    PORT
      LAYER M4 ;
        RECT 0.0000 141.2640 0.0840 141.2880 ;
    END
  END t_o[76]
  PIN t_o[77]
    DIRECTION OUTPUT ;
    USE SIGNAL ;
    PORT
      LAYER M4 ;
        RECT 0.0000 143.0880 0.0840 143.1120 ;
    END
  END t_o[77]
  PIN t_o[78]
    DIRECTION OUTPUT ;
    USE SIGNAL ;
    PORT
      LAYER M4 ;
        RECT 0.0000 144.8640 0.0840 144.8880 ;
    END
  END t_o[78]
  PIN t_o[79]
    DIRECTION OUTPUT ;
    USE SIGNAL ;
    PORT
      LAYER M4 ;
        RECT 0.0000 146.6880 0.0840 146.7120 ;
    END
  END t_o[79]
  PIN t_o[7]
    DIRECTION OUTPUT ;
    USE SIGNAL ;
    PORT
      LAYER M4 ;
        RECT 0.0000 15.7920 0.0840 15.8160 ;
    END
  END t_o[7]
  PIN t_o[80]
    DIRECTION OUTPUT ;
    USE SIGNAL ;
    PORT
      LAYER M4 ;
        RECT 0.0000 148.5120 0.0840 148.5360 ;
    END
  END t_o[80]
  PIN t_o[81]
    DIRECTION OUTPUT ;
    USE SIGNAL ;
    PORT
      LAYER M4 ;
        RECT 0.0000 150.3360 0.0840 150.3600 ;
    END
  END t_o[81]
  PIN t_o[82]
    DIRECTION OUTPUT ;
    USE SIGNAL ;
    PORT
      LAYER M4 ;
        RECT 0.0000 152.1600 0.0840 152.1840 ;
    END
  END t_o[82]
  PIN t_o[83]
    DIRECTION OUTPUT ;
    USE SIGNAL ;
    PORT
      LAYER M4 ;
        RECT 0.0000 153.9840 0.0840 154.0080 ;
    END
  END t_o[83]
  PIN t_o[84]
    DIRECTION OUTPUT ;
    USE SIGNAL ;
    PORT
      LAYER M4 ;
        RECT 0.0000 155.8080 0.0840 155.8320 ;
    END
  END t_o[84]
  PIN t_o[85]
    DIRECTION OUTPUT ;
    USE SIGNAL ;
    PORT
      LAYER M4 ;
        RECT 0.0000 157.6320 0.0840 157.6560 ;
    END
  END t_o[85]
  PIN t_o[86]
    DIRECTION OUTPUT ;
    USE SIGNAL ;
    PORT
      LAYER M4 ;
        RECT 0.0000 159.4080 0.0840 159.4320 ;
    END
  END t_o[86]
  PIN t_o[87]
    DIRECTION OUTPUT ;
    USE SIGNAL ;
    PORT
      LAYER M4 ;
        RECT 0.0000 161.2320 0.0840 161.2560 ;
    END
  END t_o[87]
  PIN t_o[88]
    DIRECTION OUTPUT ;
    USE SIGNAL ;
    PORT
      LAYER M4 ;
        RECT 0.0000 163.0560 0.0840 163.0800 ;
    END
  END t_o[88]
  PIN t_o[89]
    DIRECTION OUTPUT ;
    USE SIGNAL ;
    PORT
      LAYER M4 ;
        RECT 0.0000 164.8800 0.0840 164.9040 ;
    END
  END t_o[89]
  PIN t_o[8]
    DIRECTION OUTPUT ;
    USE SIGNAL ;
    PORT
      LAYER M4 ;
        RECT 0.0000 17.6160 0.0840 17.6400 ;
    END
  END t_o[8]
  PIN t_o[90]
    DIRECTION OUTPUT ;
    USE SIGNAL ;
    PORT
      LAYER M4 ;
        RECT 0.0000 166.7040 0.0840 166.7280 ;
    END
  END t_o[90]
  PIN t_o[91]
    DIRECTION OUTPUT ;
    USE SIGNAL ;
    PORT
      LAYER M4 ;
        RECT 0.0000 168.5280 0.0840 168.5520 ;
    END
  END t_o[91]
  PIN t_o[92]
    DIRECTION OUTPUT ;
    USE SIGNAL ;
    PORT
      LAYER M4 ;
        RECT 0.0000 170.3520 0.0840 170.3760 ;
    END
  END t_o[92]
  PIN t_o[93]
    DIRECTION OUTPUT ;
    USE SIGNAL ;
    PORT
      LAYER M4 ;
        RECT 0.0000 172.1760 0.0840 172.2000 ;
    END
  END t_o[93]
  PIN t_o[94]
    DIRECTION OUTPUT ;
    USE SIGNAL ;
    PORT
      LAYER M4 ;
        RECT 0.0000 174.0000 0.0840 174.0240 ;
    END
  END t_o[94]
  PIN t_o[95]
    DIRECTION OUTPUT ;
    USE SIGNAL ;
    PORT
      LAYER M4 ;
        RECT 0.0000 175.7760 0.0840 175.8000 ;
    END
  END t_o[95]
  PIN t_o[96]
    DIRECTION OUTPUT ;
    USE SIGNAL ;
    PORT
      LAYER M4 ;
        RECT 0.0000 177.6000 0.0840 177.6240 ;
    END
  END t_o[96]
  PIN t_o[97]
    DIRECTION OUTPUT ;
    USE SIGNAL ;
    PORT
      LAYER M4 ;
        RECT 0.0000 179.4240 0.0840 179.4480 ;
    END
  END t_o[97]
  PIN t_o[98]
    DIRECTION OUTPUT ;
    USE SIGNAL ;
    PORT
      LAYER M4 ;
        RECT 0.0000 181.2480 0.0840 181.2720 ;
    END
  END t_o[98]
  PIN t_o[99]
    DIRECTION OUTPUT ;
    USE SIGNAL ;
    PORT
      LAYER M4 ;
        RECT 0.0000 183.0720 0.0840 183.0960 ;
    END
  END t_o[99]
  PIN t_o[9]
    DIRECTION OUTPUT ;
    USE SIGNAL ;
    PORT
      LAYER M4 ;
        RECT 0.0000 19.4400 0.0840 19.4640 ;
    END
  END t_o[9]
  PIN t_s[0]
    DIRECTION OUTPUT ;
    USE SIGNAL ;
    PORT
      LAYER M3 ;
        RECT 43.3440 647.9620 43.3620 648.0000 ;
    END
  END t_s[0]
  PIN t_s[100]
    DIRECTION OUTPUT ;
    USE SIGNAL ;
    PORT
      LAYER M3 ;
        RECT 73.2960 647.9620 73.3140 648.0000 ;
    END
  END t_s[100]
  PIN t_s[101]
    DIRECTION OUTPUT ;
    USE SIGNAL ;
    PORT
      LAYER M5 ;
        RECT 73.5840 647.9160 73.6080 648.0000 ;
    END
  END t_s[101]
  PIN t_s[102]
    DIRECTION OUTPUT ;
    USE SIGNAL ;
    PORT
      LAYER M3 ;
        RECT 73.9080 647.9620 73.9260 648.0000 ;
    END
  END t_s[102]
  PIN t_s[103]
    DIRECTION OUTPUT ;
    USE SIGNAL ;
    PORT
      LAYER M5 ;
        RECT 74.2080 647.9160 74.2320 648.0000 ;
    END
  END t_s[103]
  PIN t_s[104]
    DIRECTION OUTPUT ;
    USE SIGNAL ;
    PORT
      LAYER M3 ;
        RECT 74.5200 647.9620 74.5380 648.0000 ;
    END
  END t_s[104]
  PIN t_s[105]
    DIRECTION OUTPUT ;
    USE SIGNAL ;
    PORT
      LAYER M5 ;
        RECT 74.7840 647.9160 74.8080 648.0000 ;
    END
  END t_s[105]
  PIN t_s[106]
    DIRECTION OUTPUT ;
    USE SIGNAL ;
    PORT
      LAYER M3 ;
        RECT 75.0960 647.9620 75.1140 648.0000 ;
    END
  END t_s[106]
  PIN t_s[107]
    DIRECTION OUTPUT ;
    USE SIGNAL ;
    PORT
      LAYER M5 ;
        RECT 75.4080 647.9160 75.4320 648.0000 ;
    END
  END t_s[107]
  PIN t_s[108]
    DIRECTION OUTPUT ;
    USE SIGNAL ;
    PORT
      LAYER M3 ;
        RECT 75.7080 647.9620 75.7260 648.0000 ;
    END
  END t_s[108]
  PIN t_s[109]
    DIRECTION OUTPUT ;
    USE SIGNAL ;
    PORT
      LAYER M5 ;
        RECT 75.9840 647.9160 76.0080 648.0000 ;
    END
  END t_s[109]
  PIN t_s[10]
    DIRECTION OUTPUT ;
    USE SIGNAL ;
    PORT
      LAYER M3 ;
        RECT 46.3320 647.9620 46.3500 648.0000 ;
    END
  END t_s[10]
  PIN t_s[110]
    DIRECTION OUTPUT ;
    USE SIGNAL ;
    PORT
      LAYER M3 ;
        RECT 76.3200 647.9620 76.3380 648.0000 ;
    END
  END t_s[110]
  PIN t_s[111]
    DIRECTION OUTPUT ;
    USE SIGNAL ;
    PORT
      LAYER M5 ;
        RECT 76.6080 647.9160 76.6320 648.0000 ;
    END
  END t_s[111]
  PIN t_s[112]
    DIRECTION OUTPUT ;
    USE SIGNAL ;
    PORT
      LAYER M3 ;
        RECT 76.8960 647.9620 76.9140 648.0000 ;
    END
  END t_s[112]
  PIN t_s[113]
    DIRECTION OUTPUT ;
    USE SIGNAL ;
    PORT
      LAYER M5 ;
        RECT 77.1840 647.9160 77.2080 648.0000 ;
    END
  END t_s[113]
  PIN t_s[114]
    DIRECTION OUTPUT ;
    USE SIGNAL ;
    PORT
      LAYER M3 ;
        RECT 77.5080 647.9620 77.5260 648.0000 ;
    END
  END t_s[114]
  PIN t_s[115]
    DIRECTION OUTPUT ;
    USE SIGNAL ;
    PORT
      LAYER M5 ;
        RECT 77.8080 647.9160 77.8320 648.0000 ;
    END
  END t_s[115]
  PIN t_s[116]
    DIRECTION OUTPUT ;
    USE SIGNAL ;
    PORT
      LAYER M3 ;
        RECT 78.0840 647.9620 78.1020 648.0000 ;
    END
  END t_s[116]
  PIN t_s[117]
    DIRECTION OUTPUT ;
    USE SIGNAL ;
    PORT
      LAYER M5 ;
        RECT 78.3840 647.9160 78.4080 648.0000 ;
    END
  END t_s[117]
  PIN t_s[118]
    DIRECTION OUTPUT ;
    USE SIGNAL ;
    PORT
      LAYER M3 ;
        RECT 78.6960 647.9620 78.7140 648.0000 ;
    END
  END t_s[118]
  PIN t_s[119]
    DIRECTION OUTPUT ;
    USE SIGNAL ;
    PORT
      LAYER M5 ;
        RECT 79.0080 647.9160 79.0320 648.0000 ;
    END
  END t_s[119]
  PIN t_s[11]
    DIRECTION OUTPUT ;
    USE SIGNAL ;
    PORT
      LAYER M5 ;
        RECT 46.6560 647.9160 46.6800 648.0000 ;
    END
  END t_s[11]
  PIN t_s[120]
    DIRECTION OUTPUT ;
    USE SIGNAL ;
    PORT
      LAYER M3 ;
        RECT 79.3080 647.9620 79.3260 648.0000 ;
    END
  END t_s[120]
  PIN t_s[121]
    DIRECTION OUTPUT ;
    USE SIGNAL ;
    PORT
      LAYER M5 ;
        RECT 79.5840 647.9160 79.6080 648.0000 ;
    END
  END t_s[121]
  PIN t_s[122]
    DIRECTION OUTPUT ;
    USE SIGNAL ;
    PORT
      LAYER M3 ;
        RECT 79.8840 647.9620 79.9020 648.0000 ;
    END
  END t_s[122]
  PIN t_s[123]
    DIRECTION OUTPUT ;
    USE SIGNAL ;
    PORT
      LAYER M5 ;
        RECT 80.2080 647.9160 80.2320 648.0000 ;
    END
  END t_s[123]
  PIN t_s[124]
    DIRECTION OUTPUT ;
    USE SIGNAL ;
    PORT
      LAYER M3 ;
        RECT 80.4960 647.9620 80.5140 648.0000 ;
    END
  END t_s[124]
  PIN t_s[125]
    DIRECTION OUTPUT ;
    USE SIGNAL ;
    PORT
      LAYER M5 ;
        RECT 80.7840 647.9160 80.8080 648.0000 ;
    END
  END t_s[125]
  PIN t_s[126]
    DIRECTION OUTPUT ;
    USE SIGNAL ;
    PORT
      LAYER M3 ;
        RECT 81.1080 647.9620 81.1260 648.0000 ;
    END
  END t_s[126]
  PIN t_s[127]
    DIRECTION OUTPUT ;
    USE SIGNAL ;
    PORT
      LAYER M5 ;
        RECT 81.4080 647.9160 81.4320 648.0000 ;
    END
  END t_s[127]
  PIN t_s[128]
    DIRECTION OUTPUT ;
    USE SIGNAL ;
    PORT
      LAYER M3 ;
        RECT 81.6840 647.9620 81.7020 648.0000 ;
    END
  END t_s[128]
  PIN t_s[129]
    DIRECTION OUTPUT ;
    USE SIGNAL ;
    PORT
      LAYER M5 ;
        RECT 81.9840 647.9160 82.0080 648.0000 ;
    END
  END t_s[129]
  PIN t_s[12]
    DIRECTION OUTPUT ;
    USE SIGNAL ;
    PORT
      LAYER M3 ;
        RECT 46.9440 647.9620 46.9620 648.0000 ;
    END
  END t_s[12]
  PIN t_s[130]
    DIRECTION OUTPUT ;
    USE SIGNAL ;
    PORT
      LAYER M3 ;
        RECT 82.2960 647.9620 82.3140 648.0000 ;
    END
  END t_s[130]
  PIN t_s[131]
    DIRECTION OUTPUT ;
    USE SIGNAL ;
    PORT
      LAYER M5 ;
        RECT 82.6080 647.9160 82.6320 648.0000 ;
    END
  END t_s[131]
  PIN t_s[132]
    DIRECTION OUTPUT ;
    USE SIGNAL ;
    PORT
      LAYER M3 ;
        RECT 82.9080 647.9620 82.9260 648.0000 ;
    END
  END t_s[132]
  PIN t_s[133]
    DIRECTION OUTPUT ;
    USE SIGNAL ;
    PORT
      LAYER M5 ;
        RECT 83.1840 647.9160 83.2080 648.0000 ;
    END
  END t_s[133]
  PIN t_s[134]
    DIRECTION OUTPUT ;
    USE SIGNAL ;
    PORT
      LAYER M3 ;
        RECT 83.4840 647.9620 83.5020 648.0000 ;
    END
  END t_s[134]
  PIN t_s[135]
    DIRECTION OUTPUT ;
    USE SIGNAL ;
    PORT
      LAYER M5 ;
        RECT 83.8080 647.9160 83.8320 648.0000 ;
    END
  END t_s[135]
  PIN t_s[136]
    DIRECTION OUTPUT ;
    USE SIGNAL ;
    PORT
      LAYER M3 ;
        RECT 84.0960 647.9620 84.1140 648.0000 ;
    END
  END t_s[136]
  PIN t_s[137]
    DIRECTION OUTPUT ;
    USE SIGNAL ;
    PORT
      LAYER M5 ;
        RECT 84.3840 647.9160 84.4080 648.0000 ;
    END
  END t_s[137]
  PIN t_s[138]
    DIRECTION OUTPUT ;
    USE SIGNAL ;
    PORT
      LAYER M3 ;
        RECT 84.7080 647.9620 84.7260 648.0000 ;
    END
  END t_s[138]
  PIN t_s[139]
    DIRECTION OUTPUT ;
    USE SIGNAL ;
    PORT
      LAYER M5 ;
        RECT 85.0080 647.9160 85.0320 648.0000 ;
    END
  END t_s[139]
  PIN t_s[13]
    DIRECTION OUTPUT ;
    USE SIGNAL ;
    PORT
      LAYER M5 ;
        RECT 47.2320 647.9160 47.2560 648.0000 ;
    END
  END t_s[13]
  PIN t_s[140]
    DIRECTION OUTPUT ;
    USE SIGNAL ;
    PORT
      LAYER M3 ;
        RECT 85.2840 647.9620 85.3020 648.0000 ;
    END
  END t_s[140]
  PIN t_s[141]
    DIRECTION OUTPUT ;
    USE SIGNAL ;
    PORT
      LAYER M5 ;
        RECT 85.5840 647.9160 85.6080 648.0000 ;
    END
  END t_s[141]
  PIN t_s[142]
    DIRECTION OUTPUT ;
    USE SIGNAL ;
    PORT
      LAYER M3 ;
        RECT 85.8960 647.9620 85.9140 648.0000 ;
    END
  END t_s[142]
  PIN t_s[143]
    DIRECTION OUTPUT ;
    USE SIGNAL ;
    PORT
      LAYER M5 ;
        RECT 86.2080 647.9160 86.2320 648.0000 ;
    END
  END t_s[143]
  PIN t_s[144]
    DIRECTION OUTPUT ;
    USE SIGNAL ;
    PORT
      LAYER M3 ;
        RECT 86.5080 647.9620 86.5260 648.0000 ;
    END
  END t_s[144]
  PIN t_s[145]
    DIRECTION OUTPUT ;
    USE SIGNAL ;
    PORT
      LAYER M5 ;
        RECT 86.7840 647.9160 86.8080 648.0000 ;
    END
  END t_s[145]
  PIN t_s[146]
    DIRECTION OUTPUT ;
    USE SIGNAL ;
    PORT
      LAYER M3 ;
        RECT 87.0840 647.9620 87.1020 648.0000 ;
    END
  END t_s[146]
  PIN t_s[147]
    DIRECTION OUTPUT ;
    USE SIGNAL ;
    PORT
      LAYER M5 ;
        RECT 87.4080 647.9160 87.4320 648.0000 ;
    END
  END t_s[147]
  PIN t_s[148]
    DIRECTION OUTPUT ;
    USE SIGNAL ;
    PORT
      LAYER M3 ;
        RECT 87.6960 647.9620 87.7140 648.0000 ;
    END
  END t_s[148]
  PIN t_s[149]
    DIRECTION OUTPUT ;
    USE SIGNAL ;
    PORT
      LAYER M5 ;
        RECT 87.9840 647.9160 88.0080 648.0000 ;
    END
  END t_s[149]
  PIN t_s[14]
    DIRECTION OUTPUT ;
    USE SIGNAL ;
    PORT
      LAYER M3 ;
        RECT 47.5200 647.9620 47.5380 648.0000 ;
    END
  END t_s[14]
  PIN t_s[150]
    DIRECTION OUTPUT ;
    USE SIGNAL ;
    PORT
      LAYER M3 ;
        RECT 88.2720 647.9620 88.2900 648.0000 ;
    END
  END t_s[150]
  PIN t_s[151]
    DIRECTION OUTPUT ;
    USE SIGNAL ;
    PORT
      LAYER M5 ;
        RECT 88.6080 647.9160 88.6320 648.0000 ;
    END
  END t_s[151]
  PIN t_s[152]
    DIRECTION OUTPUT ;
    USE SIGNAL ;
    PORT
      LAYER M3 ;
        RECT 88.8840 647.9620 88.9020 648.0000 ;
    END
  END t_s[152]
  PIN t_s[153]
    DIRECTION OUTPUT ;
    USE SIGNAL ;
    PORT
      LAYER M5 ;
        RECT 89.1840 647.9160 89.2080 648.0000 ;
    END
  END t_s[153]
  PIN t_s[154]
    DIRECTION OUTPUT ;
    USE SIGNAL ;
    PORT
      LAYER M3 ;
        RECT 89.4960 647.9620 89.5140 648.0000 ;
    END
  END t_s[154]
  PIN t_s[155]
    DIRECTION OUTPUT ;
    USE SIGNAL ;
    PORT
      LAYER M5 ;
        RECT 89.8080 647.9160 89.8320 648.0000 ;
    END
  END t_s[155]
  PIN t_s[156]
    DIRECTION OUTPUT ;
    USE SIGNAL ;
    PORT
      LAYER M3 ;
        RECT 90.0720 647.9620 90.0900 648.0000 ;
    END
  END t_s[156]
  PIN t_s[157]
    DIRECTION OUTPUT ;
    USE SIGNAL ;
    PORT
      LAYER M5 ;
        RECT 90.3840 647.9160 90.4080 648.0000 ;
    END
  END t_s[157]
  PIN t_s[158]
    DIRECTION OUTPUT ;
    USE SIGNAL ;
    PORT
      LAYER M3 ;
        RECT 90.6840 647.9620 90.7020 648.0000 ;
    END
  END t_s[158]
  PIN t_s[159]
    DIRECTION OUTPUT ;
    USE SIGNAL ;
    PORT
      LAYER M5 ;
        RECT 90.9600 647.9160 90.9840 648.0000 ;
    END
  END t_s[159]
  PIN t_s[15]
    DIRECTION OUTPUT ;
    USE SIGNAL ;
    PORT
      LAYER M5 ;
        RECT 47.8560 647.9160 47.8800 648.0000 ;
    END
  END t_s[15]
  PIN t_s[160]
    DIRECTION OUTPUT ;
    USE SIGNAL ;
    PORT
      LAYER M3 ;
        RECT 91.2960 647.9620 91.3140 648.0000 ;
    END
  END t_s[160]
  PIN t_s[161]
    DIRECTION OUTPUT ;
    USE SIGNAL ;
    PORT
      LAYER M5 ;
        RECT 91.5840 647.9160 91.6080 648.0000 ;
    END
  END t_s[161]
  PIN t_s[162]
    DIRECTION OUTPUT ;
    USE SIGNAL ;
    PORT
      LAYER M3 ;
        RECT 91.8720 647.9620 91.8900 648.0000 ;
    END
  END t_s[162]
  PIN t_s[163]
    DIRECTION OUTPUT ;
    USE SIGNAL ;
    PORT
      LAYER M5 ;
        RECT 92.1600 647.9160 92.1840 648.0000 ;
    END
  END t_s[163]
  PIN t_s[164]
    DIRECTION OUTPUT ;
    USE SIGNAL ;
    PORT
      LAYER M3 ;
        RECT 92.4840 647.9620 92.5020 648.0000 ;
    END
  END t_s[164]
  PIN t_s[165]
    DIRECTION OUTPUT ;
    USE SIGNAL ;
    PORT
      LAYER M5 ;
        RECT 92.7840 647.9160 92.8080 648.0000 ;
    END
  END t_s[165]
  PIN t_s[166]
    DIRECTION OUTPUT ;
    USE SIGNAL ;
    PORT
      LAYER M3 ;
        RECT 93.0960 647.9620 93.1140 648.0000 ;
    END
  END t_s[166]
  PIN t_s[167]
    DIRECTION OUTPUT ;
    USE SIGNAL ;
    PORT
      LAYER M5 ;
        RECT 93.3600 647.9160 93.3840 648.0000 ;
    END
  END t_s[167]
  PIN t_s[168]
    DIRECTION OUTPUT ;
    USE SIGNAL ;
    PORT
      LAYER M3 ;
        RECT 93.6720 647.9620 93.6900 648.0000 ;
    END
  END t_s[168]
  PIN t_s[169]
    DIRECTION OUTPUT ;
    USE SIGNAL ;
    PORT
      LAYER M5 ;
        RECT 93.9840 647.9160 94.0080 648.0000 ;
    END
  END t_s[169]
  PIN t_s[16]
    DIRECTION OUTPUT ;
    USE SIGNAL ;
    PORT
      LAYER M3 ;
        RECT 48.1320 647.9620 48.1500 648.0000 ;
    END
  END t_s[16]
  PIN t_s[170]
    DIRECTION OUTPUT ;
    USE SIGNAL ;
    PORT
      LAYER M3 ;
        RECT 94.2840 647.9620 94.3020 648.0000 ;
    END
  END t_s[170]
  PIN t_s[171]
    DIRECTION OUTPUT ;
    USE SIGNAL ;
    PORT
      LAYER M5 ;
        RECT 94.5600 647.9160 94.5840 648.0000 ;
    END
  END t_s[171]
  PIN t_s[172]
    DIRECTION OUTPUT ;
    USE SIGNAL ;
    PORT
      LAYER M3 ;
        RECT 94.8960 647.9620 94.9140 648.0000 ;
    END
  END t_s[172]
  PIN t_s[173]
    DIRECTION OUTPUT ;
    USE SIGNAL ;
    PORT
      LAYER M5 ;
        RECT 95.1840 647.9160 95.2080 648.0000 ;
    END
  END t_s[173]
  PIN t_s[174]
    DIRECTION OUTPUT ;
    USE SIGNAL ;
    PORT
      LAYER M3 ;
        RECT 95.4720 647.9620 95.4900 648.0000 ;
    END
  END t_s[174]
  PIN t_s[175]
    DIRECTION OUTPUT ;
    USE SIGNAL ;
    PORT
      LAYER M5 ;
        RECT 95.7600 647.9160 95.7840 648.0000 ;
    END
  END t_s[175]
  PIN t_s[176]
    DIRECTION OUTPUT ;
    USE SIGNAL ;
    PORT
      LAYER M3 ;
        RECT 96.0840 647.9620 96.1020 648.0000 ;
    END
  END t_s[176]
  PIN t_s[177]
    DIRECTION OUTPUT ;
    USE SIGNAL ;
    PORT
      LAYER M5 ;
        RECT 96.3840 647.9160 96.4080 648.0000 ;
    END
  END t_s[177]
  PIN t_s[178]
    DIRECTION OUTPUT ;
    USE SIGNAL ;
    PORT
      LAYER M3 ;
        RECT 96.6960 647.9620 96.7140 648.0000 ;
    END
  END t_s[178]
  PIN t_s[179]
    DIRECTION OUTPUT ;
    USE SIGNAL ;
    PORT
      LAYER M5 ;
        RECT 96.9600 647.9160 96.9840 648.0000 ;
    END
  END t_s[179]
  PIN t_s[17]
    DIRECTION OUTPUT ;
    USE SIGNAL ;
    PORT
      LAYER M5 ;
        RECT 48.4320 647.9160 48.4560 648.0000 ;
    END
  END t_s[17]
  PIN t_s[180]
    DIRECTION OUTPUT ;
    USE SIGNAL ;
    PORT
      LAYER M3 ;
        RECT 97.2720 647.9620 97.2900 648.0000 ;
    END
  END t_s[180]
  PIN t_s[181]
    DIRECTION OUTPUT ;
    USE SIGNAL ;
    PORT
      LAYER M5 ;
        RECT 97.5840 647.9160 97.6080 648.0000 ;
    END
  END t_s[181]
  PIN t_s[182]
    DIRECTION OUTPUT ;
    USE SIGNAL ;
    PORT
      LAYER M3 ;
        RECT 97.8840 647.9620 97.9020 648.0000 ;
    END
  END t_s[182]
  PIN t_s[183]
    DIRECTION OUTPUT ;
    USE SIGNAL ;
    PORT
      LAYER M5 ;
        RECT 98.1600 647.9160 98.1840 648.0000 ;
    END
  END t_s[183]
  PIN t_s[184]
    DIRECTION OUTPUT ;
    USE SIGNAL ;
    PORT
      LAYER M3 ;
        RECT 98.4600 647.9620 98.4780 648.0000 ;
    END
  END t_s[184]
  PIN t_s[185]
    DIRECTION OUTPUT ;
    USE SIGNAL ;
    PORT
      LAYER M5 ;
        RECT 98.7840 647.9160 98.8080 648.0000 ;
    END
  END t_s[185]
  PIN t_s[186]
    DIRECTION OUTPUT ;
    USE SIGNAL ;
    PORT
      LAYER M3 ;
        RECT 99.0720 647.9620 99.0900 648.0000 ;
    END
  END t_s[186]
  PIN t_s[187]
    DIRECTION OUTPUT ;
    USE SIGNAL ;
    PORT
      LAYER M5 ;
        RECT 99.3600 647.9160 99.3840 648.0000 ;
    END
  END t_s[187]
  PIN t_s[188]
    DIRECTION OUTPUT ;
    USE SIGNAL ;
    PORT
      LAYER M3 ;
        RECT 99.6840 647.9620 99.7020 648.0000 ;
    END
  END t_s[188]
  PIN t_s[189]
    DIRECTION OUTPUT ;
    USE SIGNAL ;
    PORT
      LAYER M5 ;
        RECT 99.9840 647.9160 100.0080 648.0000 ;
    END
  END t_s[189]
  PIN t_s[18]
    DIRECTION OUTPUT ;
    USE SIGNAL ;
    PORT
      LAYER M3 ;
        RECT 48.7440 647.9620 48.7620 648.0000 ;
    END
  END t_s[18]
  PIN t_s[190]
    DIRECTION OUTPUT ;
    USE SIGNAL ;
    PORT
      LAYER M3 ;
        RECT 100.2600 647.9620 100.2780 648.0000 ;
    END
  END t_s[190]
  PIN t_s[191]
    DIRECTION OUTPUT ;
    USE SIGNAL ;
    PORT
      LAYER M5 ;
        RECT 100.5600 647.9160 100.5840 648.0000 ;
    END
  END t_s[191]
  PIN t_s[192]
    DIRECTION OUTPUT ;
    USE SIGNAL ;
    PORT
      LAYER M3 ;
        RECT 100.8720 647.9620 100.8900 648.0000 ;
    END
  END t_s[192]
  PIN t_s[193]
    DIRECTION OUTPUT ;
    USE SIGNAL ;
    PORT
      LAYER M5 ;
        RECT 101.1840 647.9160 101.2080 648.0000 ;
    END
  END t_s[193]
  PIN t_s[194]
    DIRECTION OUTPUT ;
    USE SIGNAL ;
    PORT
      LAYER M3 ;
        RECT 101.4840 647.9620 101.5020 648.0000 ;
    END
  END t_s[194]
  PIN t_s[195]
    DIRECTION OUTPUT ;
    USE SIGNAL ;
    PORT
      LAYER M5 ;
        RECT 101.7600 647.9160 101.7840 648.0000 ;
    END
  END t_s[195]
  PIN t_s[196]
    DIRECTION OUTPUT ;
    USE SIGNAL ;
    PORT
      LAYER M3 ;
        RECT 102.0600 647.9620 102.0780 648.0000 ;
    END
  END t_s[196]
  PIN t_s[197]
    DIRECTION OUTPUT ;
    USE SIGNAL ;
    PORT
      LAYER M5 ;
        RECT 102.3840 647.9160 102.4080 648.0000 ;
    END
  END t_s[197]
  PIN t_s[198]
    DIRECTION OUTPUT ;
    USE SIGNAL ;
    PORT
      LAYER M3 ;
        RECT 102.6720 647.9620 102.6900 648.0000 ;
    END
  END t_s[198]
  PIN t_s[199]
    DIRECTION OUTPUT ;
    USE SIGNAL ;
    PORT
      LAYER M5 ;
        RECT 102.9600 647.9160 102.9840 648.0000 ;
    END
  END t_s[199]
  PIN t_s[19]
    DIRECTION OUTPUT ;
    USE SIGNAL ;
    PORT
      LAYER M5 ;
        RECT 49.0080 647.9160 49.0320 648.0000 ;
    END
  END t_s[19]
  PIN t_s[1]
    DIRECTION OUTPUT ;
    USE SIGNAL ;
    PORT
      LAYER M5 ;
        RECT 43.6320 647.9160 43.6560 648.0000 ;
    END
  END t_s[1]
  PIN t_s[200]
    DIRECTION OUTPUT ;
    USE SIGNAL ;
    PORT
      LAYER M3 ;
        RECT 103.2840 647.9620 103.3020 648.0000 ;
    END
  END t_s[200]
  PIN t_s[201]
    DIRECTION OUTPUT ;
    USE SIGNAL ;
    PORT
      LAYER M5 ;
        RECT 103.5840 647.9160 103.6080 648.0000 ;
    END
  END t_s[201]
  PIN t_s[202]
    DIRECTION OUTPUT ;
    USE SIGNAL ;
    PORT
      LAYER M3 ;
        RECT 103.8600 647.9620 103.8780 648.0000 ;
    END
  END t_s[202]
  PIN t_s[203]
    DIRECTION OUTPUT ;
    USE SIGNAL ;
    PORT
      LAYER M5 ;
        RECT 104.1600 647.9160 104.1840 648.0000 ;
    END
  END t_s[203]
  PIN t_s[204]
    DIRECTION OUTPUT ;
    USE SIGNAL ;
    PORT
      LAYER M3 ;
        RECT 104.4720 647.9620 104.4900 648.0000 ;
    END
  END t_s[204]
  PIN t_s[205]
    DIRECTION OUTPUT ;
    USE SIGNAL ;
    PORT
      LAYER M5 ;
        RECT 104.7840 647.9160 104.8080 648.0000 ;
    END
  END t_s[205]
  PIN t_s[206]
    DIRECTION OUTPUT ;
    USE SIGNAL ;
    PORT
      LAYER M3 ;
        RECT 105.0840 647.9620 105.1020 648.0000 ;
    END
  END t_s[206]
  PIN t_s[207]
    DIRECTION OUTPUT ;
    USE SIGNAL ;
    PORT
      LAYER M5 ;
        RECT 105.3600 647.9160 105.3840 648.0000 ;
    END
  END t_s[207]
  PIN t_s[208]
    DIRECTION OUTPUT ;
    USE SIGNAL ;
    PORT
      LAYER M3 ;
        RECT 105.6600 647.9620 105.6780 648.0000 ;
    END
  END t_s[208]
  PIN t_s[209]
    DIRECTION OUTPUT ;
    USE SIGNAL ;
    PORT
      LAYER M5 ;
        RECT 105.9840 647.9160 106.0080 648.0000 ;
    END
  END t_s[209]
  PIN t_s[20]
    DIRECTION OUTPUT ;
    USE SIGNAL ;
    PORT
      LAYER M3 ;
        RECT 49.3200 647.9620 49.3380 648.0000 ;
    END
  END t_s[20]
  PIN t_s[210]
    DIRECTION OUTPUT ;
    USE SIGNAL ;
    PORT
      LAYER M3 ;
        RECT 106.2720 647.9620 106.2900 648.0000 ;
    END
  END t_s[210]
  PIN t_s[211]
    DIRECTION OUTPUT ;
    USE SIGNAL ;
    PORT
      LAYER M5 ;
        RECT 106.5600 647.9160 106.5840 648.0000 ;
    END
  END t_s[211]
  PIN t_s[212]
    DIRECTION OUTPUT ;
    USE SIGNAL ;
    PORT
      LAYER M3 ;
        RECT 106.8840 647.9620 106.9020 648.0000 ;
    END
  END t_s[212]
  PIN t_s[213]
    DIRECTION OUTPUT ;
    USE SIGNAL ;
    PORT
      LAYER M5 ;
        RECT 107.1840 647.9160 107.2080 648.0000 ;
    END
  END t_s[213]
  PIN t_s[214]
    DIRECTION OUTPUT ;
    USE SIGNAL ;
    PORT
      LAYER M3 ;
        RECT 107.4600 647.9620 107.4780 648.0000 ;
    END
  END t_s[214]
  PIN t_s[215]
    DIRECTION OUTPUT ;
    USE SIGNAL ;
    PORT
      LAYER M5 ;
        RECT 107.7600 647.9160 107.7840 648.0000 ;
    END
  END t_s[215]
  PIN t_s[216]
    DIRECTION OUTPUT ;
    USE SIGNAL ;
    PORT
      LAYER M3 ;
        RECT 108.0720 647.9620 108.0900 648.0000 ;
    END
  END t_s[216]
  PIN t_s[217]
    DIRECTION OUTPUT ;
    USE SIGNAL ;
    PORT
      LAYER M5 ;
        RECT 108.3840 647.9160 108.4080 648.0000 ;
    END
  END t_s[217]
  PIN t_s[218]
    DIRECTION OUTPUT ;
    USE SIGNAL ;
    PORT
      LAYER M3 ;
        RECT 108.6480 647.9620 108.6660 648.0000 ;
    END
  END t_s[218]
  PIN t_s[219]
    DIRECTION OUTPUT ;
    USE SIGNAL ;
    PORT
      LAYER M5 ;
        RECT 108.9600 647.9160 108.9840 648.0000 ;
    END
  END t_s[219]
  PIN t_s[21]
    DIRECTION OUTPUT ;
    USE SIGNAL ;
    PORT
      LAYER M5 ;
        RECT 49.6320 647.9160 49.6560 648.0000 ;
    END
  END t_s[21]
  PIN t_s[220]
    DIRECTION OUTPUT ;
    USE SIGNAL ;
    PORT
      LAYER M3 ;
        RECT 109.2600 647.9620 109.2780 648.0000 ;
    END
  END t_s[220]
  PIN t_s[221]
    DIRECTION OUTPUT ;
    USE SIGNAL ;
    PORT
      LAYER M5 ;
        RECT 109.5840 647.9160 109.6080 648.0000 ;
    END
  END t_s[221]
  PIN t_s[222]
    DIRECTION OUTPUT ;
    USE SIGNAL ;
    PORT
      LAYER M3 ;
        RECT 109.8720 647.9620 109.8900 648.0000 ;
    END
  END t_s[222]
  PIN t_s[223]
    DIRECTION OUTPUT ;
    USE SIGNAL ;
    PORT
      LAYER M5 ;
        RECT 110.1600 647.9160 110.1840 648.0000 ;
    END
  END t_s[223]
  PIN t_s[224]
    DIRECTION OUTPUT ;
    USE SIGNAL ;
    PORT
      LAYER M3 ;
        RECT 110.4480 647.9620 110.4660 648.0000 ;
    END
  END t_s[224]
  PIN t_s[225]
    DIRECTION OUTPUT ;
    USE SIGNAL ;
    PORT
      LAYER M5 ;
        RECT 110.7840 647.9160 110.8080 648.0000 ;
    END
  END t_s[225]
  PIN t_s[226]
    DIRECTION OUTPUT ;
    USE SIGNAL ;
    PORT
      LAYER M3 ;
        RECT 111.0600 647.9620 111.0780 648.0000 ;
    END
  END t_s[226]
  PIN t_s[227]
    DIRECTION OUTPUT ;
    USE SIGNAL ;
    PORT
      LAYER M5 ;
        RECT 111.3600 647.9160 111.3840 648.0000 ;
    END
  END t_s[227]
  PIN t_s[228]
    DIRECTION OUTPUT ;
    USE SIGNAL ;
    PORT
      LAYER M3 ;
        RECT 111.6720 647.9620 111.6900 648.0000 ;
    END
  END t_s[228]
  PIN t_s[229]
    DIRECTION OUTPUT ;
    USE SIGNAL ;
    PORT
      LAYER M5 ;
        RECT 111.9360 647.9160 111.9600 648.0000 ;
    END
  END t_s[229]
  PIN t_s[22]
    DIRECTION OUTPUT ;
    USE SIGNAL ;
    PORT
      LAYER M3 ;
        RECT 49.9320 647.9620 49.9500 648.0000 ;
    END
  END t_s[22]
  PIN t_s[230]
    DIRECTION OUTPUT ;
    USE SIGNAL ;
    PORT
      LAYER M3 ;
        RECT 112.2480 647.9620 112.2660 648.0000 ;
    END
  END t_s[230]
  PIN t_s[231]
    DIRECTION OUTPUT ;
    USE SIGNAL ;
    PORT
      LAYER M5 ;
        RECT 112.5600 647.9160 112.5840 648.0000 ;
    END
  END t_s[231]
  PIN t_s[232]
    DIRECTION OUTPUT ;
    USE SIGNAL ;
    PORT
      LAYER M3 ;
        RECT 112.8600 647.9620 112.8780 648.0000 ;
    END
  END t_s[232]
  PIN t_s[233]
    DIRECTION OUTPUT ;
    USE SIGNAL ;
    PORT
      LAYER M5 ;
        RECT 113.1360 647.9160 113.1600 648.0000 ;
    END
  END t_s[233]
  PIN t_s[234]
    DIRECTION OUTPUT ;
    USE SIGNAL ;
    PORT
      LAYER M3 ;
        RECT 113.4720 647.9620 113.4900 648.0000 ;
    END
  END t_s[234]
  PIN t_s[235]
    DIRECTION OUTPUT ;
    USE SIGNAL ;
    PORT
      LAYER M5 ;
        RECT 113.7600 647.9160 113.7840 648.0000 ;
    END
  END t_s[235]
  PIN t_s[236]
    DIRECTION OUTPUT ;
    USE SIGNAL ;
    PORT
      LAYER M3 ;
        RECT 114.0480 647.9620 114.0660 648.0000 ;
    END
  END t_s[236]
  PIN t_s[237]
    DIRECTION OUTPUT ;
    USE SIGNAL ;
    PORT
      LAYER M5 ;
        RECT 114.3360 647.9160 114.3600 648.0000 ;
    END
  END t_s[237]
  PIN t_s[238]
    DIRECTION OUTPUT ;
    USE SIGNAL ;
    PORT
      LAYER M3 ;
        RECT 114.6600 647.9620 114.6780 648.0000 ;
    END
  END t_s[238]
  PIN t_s[239]
    DIRECTION OUTPUT ;
    USE SIGNAL ;
    PORT
      LAYER M5 ;
        RECT 114.9600 647.9160 114.9840 648.0000 ;
    END
  END t_s[239]
  PIN t_s[23]
    DIRECTION OUTPUT ;
    USE SIGNAL ;
    PORT
      LAYER M5 ;
        RECT 50.2080 647.9160 50.2320 648.0000 ;
    END
  END t_s[23]
  PIN t_s[240]
    DIRECTION OUTPUT ;
    USE SIGNAL ;
    PORT
      LAYER M3 ;
        RECT 115.2720 647.9620 115.2900 648.0000 ;
    END
  END t_s[240]
  PIN t_s[241]
    DIRECTION OUTPUT ;
    USE SIGNAL ;
    PORT
      LAYER M5 ;
        RECT 115.5360 647.9160 115.5600 648.0000 ;
    END
  END t_s[241]
  PIN t_s[242]
    DIRECTION OUTPUT ;
    USE SIGNAL ;
    PORT
      LAYER M3 ;
        RECT 115.8480 647.9620 115.8660 648.0000 ;
    END
  END t_s[242]
  PIN t_s[243]
    DIRECTION OUTPUT ;
    USE SIGNAL ;
    PORT
      LAYER M5 ;
        RECT 116.1600 647.9160 116.1840 648.0000 ;
    END
  END t_s[243]
  PIN t_s[244]
    DIRECTION OUTPUT ;
    USE SIGNAL ;
    PORT
      LAYER M3 ;
        RECT 116.4600 647.9620 116.4780 648.0000 ;
    END
  END t_s[244]
  PIN t_s[245]
    DIRECTION OUTPUT ;
    USE SIGNAL ;
    PORT
      LAYER M5 ;
        RECT 116.7360 647.9160 116.7600 648.0000 ;
    END
  END t_s[245]
  PIN t_s[246]
    DIRECTION OUTPUT ;
    USE SIGNAL ;
    PORT
      LAYER M3 ;
        RECT 117.0720 647.9620 117.0900 648.0000 ;
    END
  END t_s[246]
  PIN t_s[247]
    DIRECTION OUTPUT ;
    USE SIGNAL ;
    PORT
      LAYER M5 ;
        RECT 117.3600 647.9160 117.3840 648.0000 ;
    END
  END t_s[247]
  PIN t_s[248]
    DIRECTION OUTPUT ;
    USE SIGNAL ;
    PORT
      LAYER M3 ;
        RECT 117.6480 647.9620 117.6660 648.0000 ;
    END
  END t_s[248]
  PIN t_s[249]
    DIRECTION OUTPUT ;
    USE SIGNAL ;
    PORT
      LAYER M5 ;
        RECT 117.9360 647.9160 117.9600 648.0000 ;
    END
  END t_s[249]
  PIN t_s[24]
    DIRECTION OUTPUT ;
    USE SIGNAL ;
    PORT
      LAYER M3 ;
        RECT 50.5440 647.9620 50.5620 648.0000 ;
    END
  END t_s[24]
  PIN t_s[250]
    DIRECTION OUTPUT ;
    USE SIGNAL ;
    PORT
      LAYER M3 ;
        RECT 118.2600 647.9620 118.2780 648.0000 ;
    END
  END t_s[250]
  PIN t_s[251]
    DIRECTION OUTPUT ;
    USE SIGNAL ;
    PORT
      LAYER M5 ;
        RECT 118.5600 647.9160 118.5840 648.0000 ;
    END
  END t_s[251]
  PIN t_s[252]
    DIRECTION OUTPUT ;
    USE SIGNAL ;
    PORT
      LAYER M3 ;
        RECT 118.8360 647.9620 118.8540 648.0000 ;
    END
  END t_s[252]
  PIN t_s[253]
    DIRECTION OUTPUT ;
    USE SIGNAL ;
    PORT
      LAYER M5 ;
        RECT 119.1360 647.9160 119.1600 648.0000 ;
    END
  END t_s[253]
  PIN t_s[254]
    DIRECTION OUTPUT ;
    USE SIGNAL ;
    PORT
      LAYER M3 ;
        RECT 119.4480 647.9620 119.4660 648.0000 ;
    END
  END t_s[254]
  PIN t_s[255]
    DIRECTION OUTPUT ;
    USE SIGNAL ;
    PORT
      LAYER M5 ;
        RECT 119.7600 647.9160 119.7840 648.0000 ;
    END
  END t_s[255]
  PIN t_s[256]
    DIRECTION OUTPUT ;
    USE SIGNAL ;
    PORT
      LAYER M3 ;
        RECT 120.0600 647.9620 120.0780 648.0000 ;
    END
  END t_s[256]
  PIN t_s[257]
    DIRECTION OUTPUT ;
    USE SIGNAL ;
    PORT
      LAYER M5 ;
        RECT 120.3360 647.9160 120.3600 648.0000 ;
    END
  END t_s[257]
  PIN t_s[258]
    DIRECTION OUTPUT ;
    USE SIGNAL ;
    PORT
      LAYER M3 ;
        RECT 120.6360 647.9620 120.6540 648.0000 ;
    END
  END t_s[258]
  PIN t_s[259]
    DIRECTION OUTPUT ;
    USE SIGNAL ;
    PORT
      LAYER M5 ;
        RECT 120.9600 647.9160 120.9840 648.0000 ;
    END
  END t_s[259]
  PIN t_s[25]
    DIRECTION OUTPUT ;
    USE SIGNAL ;
    PORT
      LAYER M5 ;
        RECT 50.8320 647.9160 50.8560 648.0000 ;
    END
  END t_s[25]
  PIN t_s[260]
    DIRECTION OUTPUT ;
    USE SIGNAL ;
    PORT
      LAYER M3 ;
        RECT 121.2480 647.9620 121.2660 648.0000 ;
    END
  END t_s[260]
  PIN t_s[261]
    DIRECTION OUTPUT ;
    USE SIGNAL ;
    PORT
      LAYER M5 ;
        RECT 121.5360 647.9160 121.5600 648.0000 ;
    END
  END t_s[261]
  PIN t_s[262]
    DIRECTION OUTPUT ;
    USE SIGNAL ;
    PORT
      LAYER M3 ;
        RECT 121.8600 647.9620 121.8780 648.0000 ;
    END
  END t_s[262]
  PIN t_s[263]
    DIRECTION OUTPUT ;
    USE SIGNAL ;
    PORT
      LAYER M5 ;
        RECT 122.1600 647.9160 122.1840 648.0000 ;
    END
  END t_s[263]
  PIN t_s[264]
    DIRECTION OUTPUT ;
    USE SIGNAL ;
    PORT
      LAYER M3 ;
        RECT 122.4360 647.9620 122.4540 648.0000 ;
    END
  END t_s[264]
  PIN t_s[265]
    DIRECTION OUTPUT ;
    USE SIGNAL ;
    PORT
      LAYER M5 ;
        RECT 122.7360 647.9160 122.7600 648.0000 ;
    END
  END t_s[265]
  PIN t_s[266]
    DIRECTION OUTPUT ;
    USE SIGNAL ;
    PORT
      LAYER M3 ;
        RECT 123.0480 647.9620 123.0660 648.0000 ;
    END
  END t_s[266]
  PIN t_s[267]
    DIRECTION OUTPUT ;
    USE SIGNAL ;
    PORT
      LAYER M5 ;
        RECT 123.3600 647.9160 123.3840 648.0000 ;
    END
  END t_s[267]
  PIN t_s[268]
    DIRECTION OUTPUT ;
    USE SIGNAL ;
    PORT
      LAYER M3 ;
        RECT 123.6600 647.9620 123.6780 648.0000 ;
    END
  END t_s[268]
  PIN t_s[269]
    DIRECTION OUTPUT ;
    USE SIGNAL ;
    PORT
      LAYER M5 ;
        RECT 123.9360 647.9160 123.9600 648.0000 ;
    END
  END t_s[269]
  PIN t_s[26]
    DIRECTION OUTPUT ;
    USE SIGNAL ;
    PORT
      LAYER M3 ;
        RECT 51.1200 647.9620 51.1380 648.0000 ;
    END
  END t_s[26]
  PIN t_s[270]
    DIRECTION OUTPUT ;
    USE SIGNAL ;
    PORT
      LAYER M3 ;
        RECT 124.2360 647.9620 124.2540 648.0000 ;
    END
  END t_s[270]
  PIN t_s[271]
    DIRECTION OUTPUT ;
    USE SIGNAL ;
    PORT
      LAYER M5 ;
        RECT 124.5600 647.9160 124.5840 648.0000 ;
    END
  END t_s[271]
  PIN t_s[272]
    DIRECTION OUTPUT ;
    USE SIGNAL ;
    PORT
      LAYER M3 ;
        RECT 124.8480 647.9620 124.8660 648.0000 ;
    END
  END t_s[272]
  PIN t_s[273]
    DIRECTION OUTPUT ;
    USE SIGNAL ;
    PORT
      LAYER M5 ;
        RECT 125.1360 647.9160 125.1600 648.0000 ;
    END
  END t_s[273]
  PIN t_s[274]
    DIRECTION OUTPUT ;
    USE SIGNAL ;
    PORT
      LAYER M3 ;
        RECT 125.4600 647.9620 125.4780 648.0000 ;
    END
  END t_s[274]
  PIN t_s[275]
    DIRECTION OUTPUT ;
    USE SIGNAL ;
    PORT
      LAYER M5 ;
        RECT 125.7600 647.9160 125.7840 648.0000 ;
    END
  END t_s[275]
  PIN t_s[276]
    DIRECTION OUTPUT ;
    USE SIGNAL ;
    PORT
      LAYER M3 ;
        RECT 126.0360 647.9620 126.0540 648.0000 ;
    END
  END t_s[276]
  PIN t_s[277]
    DIRECTION OUTPUT ;
    USE SIGNAL ;
    PORT
      LAYER M5 ;
        RECT 126.3360 647.9160 126.3600 648.0000 ;
    END
  END t_s[277]
  PIN t_s[278]
    DIRECTION OUTPUT ;
    USE SIGNAL ;
    PORT
      LAYER M3 ;
        RECT 126.6480 647.9620 126.6660 648.0000 ;
    END
  END t_s[278]
  PIN t_s[279]
    DIRECTION OUTPUT ;
    USE SIGNAL ;
    PORT
      LAYER M5 ;
        RECT 126.9600 647.9160 126.9840 648.0000 ;
    END
  END t_s[279]
  PIN t_s[27]
    DIRECTION OUTPUT ;
    USE SIGNAL ;
    PORT
      LAYER M5 ;
        RECT 51.4080 647.9160 51.4320 648.0000 ;
    END
  END t_s[27]
  PIN t_s[280]
    DIRECTION OUTPUT ;
    USE SIGNAL ;
    PORT
      LAYER M3 ;
        RECT 127.2600 647.9620 127.2780 648.0000 ;
    END
  END t_s[280]
  PIN t_s[281]
    DIRECTION OUTPUT ;
    USE SIGNAL ;
    PORT
      LAYER M5 ;
        RECT 127.5360 647.9160 127.5600 648.0000 ;
    END
  END t_s[281]
  PIN t_s[282]
    DIRECTION OUTPUT ;
    USE SIGNAL ;
    PORT
      LAYER M3 ;
        RECT 127.8360 647.9620 127.8540 648.0000 ;
    END
  END t_s[282]
  PIN t_s[283]
    DIRECTION OUTPUT ;
    USE SIGNAL ;
    PORT
      LAYER M5 ;
        RECT 128.1600 647.9160 128.1840 648.0000 ;
    END
  END t_s[283]
  PIN t_s[284]
    DIRECTION OUTPUT ;
    USE SIGNAL ;
    PORT
      LAYER M3 ;
        RECT 128.4480 647.9620 128.4660 648.0000 ;
    END
  END t_s[284]
  PIN t_s[285]
    DIRECTION OUTPUT ;
    USE SIGNAL ;
    PORT
      LAYER M5 ;
        RECT 128.7360 647.9160 128.7600 648.0000 ;
    END
  END t_s[285]
  PIN t_s[286]
    DIRECTION OUTPUT ;
    USE SIGNAL ;
    PORT
      LAYER M3 ;
        RECT 129.0600 647.9620 129.0780 648.0000 ;
    END
  END t_s[286]
  PIN t_s[287]
    DIRECTION OUTPUT ;
    USE SIGNAL ;
    PORT
      LAYER M5 ;
        RECT 129.3600 647.9160 129.3840 648.0000 ;
    END
  END t_s[287]
  PIN t_s[288]
    DIRECTION OUTPUT ;
    USE SIGNAL ;
    PORT
      LAYER M3 ;
        RECT 129.6360 647.9620 129.6540 648.0000 ;
    END
  END t_s[288]
  PIN t_s[289]
    DIRECTION OUTPUT ;
    USE SIGNAL ;
    PORT
      LAYER M5 ;
        RECT 129.9360 647.9160 129.9600 648.0000 ;
    END
  END t_s[289]
  PIN t_s[28]
    DIRECTION OUTPUT ;
    USE SIGNAL ;
    PORT
      LAYER M3 ;
        RECT 51.7320 647.9620 51.7500 648.0000 ;
    END
  END t_s[28]
  PIN t_s[290]
    DIRECTION OUTPUT ;
    USE SIGNAL ;
    PORT
      LAYER M3 ;
        RECT 130.2480 647.9620 130.2660 648.0000 ;
    END
  END t_s[290]
  PIN t_s[291]
    DIRECTION OUTPUT ;
    USE SIGNAL ;
    PORT
      LAYER M5 ;
        RECT 130.5600 647.9160 130.5840 648.0000 ;
    END
  END t_s[291]
  PIN t_s[292]
    DIRECTION OUTPUT ;
    USE SIGNAL ;
    PORT
      LAYER M3 ;
        RECT 130.8240 647.9620 130.8420 648.0000 ;
    END
  END t_s[292]
  PIN t_s[293]
    DIRECTION OUTPUT ;
    USE SIGNAL ;
    PORT
      LAYER M5 ;
        RECT 131.1360 647.9160 131.1600 648.0000 ;
    END
  END t_s[293]
  PIN t_s[294]
    DIRECTION OUTPUT ;
    USE SIGNAL ;
    PORT
      LAYER M3 ;
        RECT 131.4360 647.9620 131.4540 648.0000 ;
    END
  END t_s[294]
  PIN t_s[295]
    DIRECTION OUTPUT ;
    USE SIGNAL ;
    PORT
      LAYER M5 ;
        RECT 131.7600 647.9160 131.7840 648.0000 ;
    END
  END t_s[295]
  PIN t_s[296]
    DIRECTION OUTPUT ;
    USE SIGNAL ;
    PORT
      LAYER M3 ;
        RECT 132.0480 647.9620 132.0660 648.0000 ;
    END
  END t_s[296]
  PIN t_s[297]
    DIRECTION OUTPUT ;
    USE SIGNAL ;
    PORT
      LAYER M5 ;
        RECT 132.3360 647.9160 132.3600 648.0000 ;
    END
  END t_s[297]
  PIN t_s[298]
    DIRECTION OUTPUT ;
    USE SIGNAL ;
    PORT
      LAYER M3 ;
        RECT 132.6240 647.9620 132.6420 648.0000 ;
    END
  END t_s[298]
  PIN t_s[299]
    DIRECTION OUTPUT ;
    USE SIGNAL ;
    PORT
      LAYER M5 ;
        RECT 132.9120 647.9160 132.9360 648.0000 ;
    END
  END t_s[299]
  PIN t_s[29]
    DIRECTION OUTPUT ;
    USE SIGNAL ;
    PORT
      LAYER M5 ;
        RECT 52.0320 647.9160 52.0560 648.0000 ;
    END
  END t_s[29]
  PIN t_s[2]
    DIRECTION OUTPUT ;
    USE SIGNAL ;
    PORT
      LAYER M3 ;
        RECT 43.9560 647.9620 43.9740 648.0000 ;
    END
  END t_s[2]
  PIN t_s[300]
    DIRECTION OUTPUT ;
    USE SIGNAL ;
    PORT
      LAYER M3 ;
        RECT 133.2360 647.9620 133.2540 648.0000 ;
    END
  END t_s[300]
  PIN t_s[301]
    DIRECTION OUTPUT ;
    USE SIGNAL ;
    PORT
      LAYER M5 ;
        RECT 133.5360 647.9160 133.5600 648.0000 ;
    END
  END t_s[301]
  PIN t_s[302]
    DIRECTION OUTPUT ;
    USE SIGNAL ;
    PORT
      LAYER M3 ;
        RECT 133.8480 647.9620 133.8660 648.0000 ;
    END
  END t_s[302]
  PIN t_s[303]
    DIRECTION OUTPUT ;
    USE SIGNAL ;
    PORT
      LAYER M5 ;
        RECT 134.1120 647.9160 134.1360 648.0000 ;
    END
  END t_s[303]
  PIN t_s[304]
    DIRECTION OUTPUT ;
    USE SIGNAL ;
    PORT
      LAYER M3 ;
        RECT 134.4240 647.9620 134.4420 648.0000 ;
    END
  END t_s[304]
  PIN t_s[305]
    DIRECTION OUTPUT ;
    USE SIGNAL ;
    PORT
      LAYER M5 ;
        RECT 134.7360 647.9160 134.7600 648.0000 ;
    END
  END t_s[305]
  PIN t_s[306]
    DIRECTION OUTPUT ;
    USE SIGNAL ;
    PORT
      LAYER M3 ;
        RECT 135.0360 647.9620 135.0540 648.0000 ;
    END
  END t_s[306]
  PIN t_s[307]
    DIRECTION OUTPUT ;
    USE SIGNAL ;
    PORT
      LAYER M5 ;
        RECT 135.3120 647.9160 135.3360 648.0000 ;
    END
  END t_s[307]
  PIN t_s[308]
    DIRECTION OUTPUT ;
    USE SIGNAL ;
    PORT
      LAYER M3 ;
        RECT 135.6480 647.9620 135.6660 648.0000 ;
    END
  END t_s[308]
  PIN t_s[309]
    DIRECTION OUTPUT ;
    USE SIGNAL ;
    PORT
      LAYER M5 ;
        RECT 135.9360 647.9160 135.9600 648.0000 ;
    END
  END t_s[309]
  PIN t_s[30]
    DIRECTION OUTPUT ;
    USE SIGNAL ;
    PORT
      LAYER M3 ;
        RECT 52.3440 647.9620 52.3620 648.0000 ;
    END
  END t_s[30]
  PIN t_s[310]
    DIRECTION OUTPUT ;
    USE SIGNAL ;
    PORT
      LAYER M3 ;
        RECT 136.2240 647.9620 136.2420 648.0000 ;
    END
  END t_s[310]
  PIN t_s[311]
    DIRECTION OUTPUT ;
    USE SIGNAL ;
    PORT
      LAYER M5 ;
        RECT 136.5120 647.9160 136.5360 648.0000 ;
    END
  END t_s[311]
  PIN t_s[312]
    DIRECTION OUTPUT ;
    USE SIGNAL ;
    PORT
      LAYER M3 ;
        RECT 136.8360 647.9620 136.8540 648.0000 ;
    END
  END t_s[312]
  PIN t_s[313]
    DIRECTION OUTPUT ;
    USE SIGNAL ;
    PORT
      LAYER M5 ;
        RECT 137.1360 647.9160 137.1600 648.0000 ;
    END
  END t_s[313]
  PIN t_s[314]
    DIRECTION OUTPUT ;
    USE SIGNAL ;
    PORT
      LAYER M3 ;
        RECT 137.4480 647.9620 137.4660 648.0000 ;
    END
  END t_s[314]
  PIN t_s[315]
    DIRECTION OUTPUT ;
    USE SIGNAL ;
    PORT
      LAYER M5 ;
        RECT 137.7120 647.9160 137.7360 648.0000 ;
    END
  END t_s[315]
  PIN t_s[316]
    DIRECTION OUTPUT ;
    USE SIGNAL ;
    PORT
      LAYER M3 ;
        RECT 138.0240 647.9620 138.0420 648.0000 ;
    END
  END t_s[316]
  PIN t_s[317]
    DIRECTION OUTPUT ;
    USE SIGNAL ;
    PORT
      LAYER M5 ;
        RECT 138.3360 647.9160 138.3600 648.0000 ;
    END
  END t_s[317]
  PIN t_s[318]
    DIRECTION OUTPUT ;
    USE SIGNAL ;
    PORT
      LAYER M3 ;
        RECT 138.6360 647.9620 138.6540 648.0000 ;
    END
  END t_s[318]
  PIN t_s[319]
    DIRECTION OUTPUT ;
    USE SIGNAL ;
    PORT
      LAYER M5 ;
        RECT 138.9120 647.9160 138.9360 648.0000 ;
    END
  END t_s[319]
  PIN t_s[31]
    DIRECTION OUTPUT ;
    USE SIGNAL ;
    PORT
      LAYER M5 ;
        RECT 52.6080 647.9160 52.6320 648.0000 ;
    END
  END t_s[31]
  PIN t_s[320]
    DIRECTION OUTPUT ;
    USE SIGNAL ;
    PORT
      LAYER M3 ;
        RECT 139.2480 647.9620 139.2660 648.0000 ;
    END
  END t_s[320]
  PIN t_s[321]
    DIRECTION OUTPUT ;
    USE SIGNAL ;
    PORT
      LAYER M5 ;
        RECT 139.5360 647.9160 139.5600 648.0000 ;
    END
  END t_s[321]
  PIN t_s[322]
    DIRECTION OUTPUT ;
    USE SIGNAL ;
    PORT
      LAYER M3 ;
        RECT 139.8240 647.9620 139.8420 648.0000 ;
    END
  END t_s[322]
  PIN t_s[323]
    DIRECTION OUTPUT ;
    USE SIGNAL ;
    PORT
      LAYER M5 ;
        RECT 140.1120 647.9160 140.1360 648.0000 ;
    END
  END t_s[323]
  PIN t_s[324]
    DIRECTION OUTPUT ;
    USE SIGNAL ;
    PORT
      LAYER M3 ;
        RECT 140.4360 647.9620 140.4540 648.0000 ;
    END
  END t_s[324]
  PIN t_s[325]
    DIRECTION OUTPUT ;
    USE SIGNAL ;
    PORT
      LAYER M5 ;
        RECT 140.7360 647.9160 140.7600 648.0000 ;
    END
  END t_s[325]
  PIN t_s[326]
    DIRECTION OUTPUT ;
    USE SIGNAL ;
    PORT
      LAYER M3 ;
        RECT 141.0120 647.9620 141.0300 648.0000 ;
    END
  END t_s[326]
  PIN t_s[327]
    DIRECTION OUTPUT ;
    USE SIGNAL ;
    PORT
      LAYER M5 ;
        RECT 141.3120 647.9160 141.3360 648.0000 ;
    END
  END t_s[327]
  PIN t_s[328]
    DIRECTION OUTPUT ;
    USE SIGNAL ;
    PORT
      LAYER M3 ;
        RECT 141.6240 647.9620 141.6420 648.0000 ;
    END
  END t_s[328]
  PIN t_s[329]
    DIRECTION OUTPUT ;
    USE SIGNAL ;
    PORT
      LAYER M5 ;
        RECT 141.9360 647.9160 141.9600 648.0000 ;
    END
  END t_s[329]
  PIN t_s[32]
    DIRECTION OUTPUT ;
    USE SIGNAL ;
    PORT
      LAYER M3 ;
        RECT 52.9200 647.9620 52.9380 648.0000 ;
    END
  END t_s[32]
  PIN t_s[330]
    DIRECTION OUTPUT ;
    USE SIGNAL ;
    PORT
      LAYER M3 ;
        RECT 142.2360 647.9620 142.2540 648.0000 ;
    END
  END t_s[330]
  PIN t_s[331]
    DIRECTION OUTPUT ;
    USE SIGNAL ;
    PORT
      LAYER M5 ;
        RECT 142.5120 647.9160 142.5360 648.0000 ;
    END
  END t_s[331]
  PIN t_s[332]
    DIRECTION OUTPUT ;
    USE SIGNAL ;
    PORT
      LAYER M3 ;
        RECT 142.8120 647.9620 142.8300 648.0000 ;
    END
  END t_s[332]
  PIN t_s[333]
    DIRECTION OUTPUT ;
    USE SIGNAL ;
    PORT
      LAYER M5 ;
        RECT 143.1360 647.9160 143.1600 648.0000 ;
    END
  END t_s[333]
  PIN t_s[334]
    DIRECTION OUTPUT ;
    USE SIGNAL ;
    PORT
      LAYER M3 ;
        RECT 143.4240 647.9620 143.4420 648.0000 ;
    END
  END t_s[334]
  PIN t_s[335]
    DIRECTION OUTPUT ;
    USE SIGNAL ;
    PORT
      LAYER M5 ;
        RECT 143.7120 647.9160 143.7360 648.0000 ;
    END
  END t_s[335]
  PIN t_s[336]
    DIRECTION OUTPUT ;
    USE SIGNAL ;
    PORT
      LAYER M3 ;
        RECT 144.0360 647.9620 144.0540 648.0000 ;
    END
  END t_s[336]
  PIN t_s[337]
    DIRECTION OUTPUT ;
    USE SIGNAL ;
    PORT
      LAYER M5 ;
        RECT 144.3360 647.9160 144.3600 648.0000 ;
    END
  END t_s[337]
  PIN t_s[338]
    DIRECTION OUTPUT ;
    USE SIGNAL ;
    PORT
      LAYER M3 ;
        RECT 144.6120 647.9620 144.6300 648.0000 ;
    END
  END t_s[338]
  PIN t_s[339]
    DIRECTION OUTPUT ;
    USE SIGNAL ;
    PORT
      LAYER M5 ;
        RECT 144.9120 647.9160 144.9360 648.0000 ;
    END
  END t_s[339]
  PIN t_s[33]
    DIRECTION OUTPUT ;
    USE SIGNAL ;
    PORT
      LAYER M5 ;
        RECT 53.2320 647.9160 53.2560 648.0000 ;
    END
  END t_s[33]
  PIN t_s[340]
    DIRECTION OUTPUT ;
    USE SIGNAL ;
    PORT
      LAYER M3 ;
        RECT 145.2240 647.9620 145.2420 648.0000 ;
    END
  END t_s[340]
  PIN t_s[341]
    DIRECTION OUTPUT ;
    USE SIGNAL ;
    PORT
      LAYER M5 ;
        RECT 145.5360 647.9160 145.5600 648.0000 ;
    END
  END t_s[341]
  PIN t_s[342]
    DIRECTION OUTPUT ;
    USE SIGNAL ;
    PORT
      LAYER M3 ;
        RECT 145.8360 647.9620 145.8540 648.0000 ;
    END
  END t_s[342]
  PIN t_s[343]
    DIRECTION OUTPUT ;
    USE SIGNAL ;
    PORT
      LAYER M5 ;
        RECT 146.1120 647.9160 146.1360 648.0000 ;
    END
  END t_s[343]
  PIN t_s[344]
    DIRECTION OUTPUT ;
    USE SIGNAL ;
    PORT
      LAYER M3 ;
        RECT 146.4120 647.9620 146.4300 648.0000 ;
    END
  END t_s[344]
  PIN t_s[345]
    DIRECTION OUTPUT ;
    USE SIGNAL ;
    PORT
      LAYER M5 ;
        RECT 146.7360 647.9160 146.7600 648.0000 ;
    END
  END t_s[345]
  PIN t_s[346]
    DIRECTION OUTPUT ;
    USE SIGNAL ;
    PORT
      LAYER M3 ;
        RECT 147.0240 647.9620 147.0420 648.0000 ;
    END
  END t_s[346]
  PIN t_s[347]
    DIRECTION OUTPUT ;
    USE SIGNAL ;
    PORT
      LAYER M5 ;
        RECT 147.3120 647.9160 147.3360 648.0000 ;
    END
  END t_s[347]
  PIN t_s[348]
    DIRECTION OUTPUT ;
    USE SIGNAL ;
    PORT
      LAYER M3 ;
        RECT 147.6360 647.9620 147.6540 648.0000 ;
    END
  END t_s[348]
  PIN t_s[349]
    DIRECTION OUTPUT ;
    USE SIGNAL ;
    PORT
      LAYER M5 ;
        RECT 147.9360 647.9160 147.9600 648.0000 ;
    END
  END t_s[349]
  PIN t_s[34]
    DIRECTION OUTPUT ;
    USE SIGNAL ;
    PORT
      LAYER M3 ;
        RECT 53.5320 647.9620 53.5500 648.0000 ;
    END
  END t_s[34]
  PIN t_s[350]
    DIRECTION OUTPUT ;
    USE SIGNAL ;
    PORT
      LAYER M3 ;
        RECT 148.2120 647.9620 148.2300 648.0000 ;
    END
  END t_s[350]
  PIN t_s[351]
    DIRECTION OUTPUT ;
    USE SIGNAL ;
    PORT
      LAYER M5 ;
        RECT 148.5120 647.9160 148.5360 648.0000 ;
    END
  END t_s[351]
  PIN t_s[352]
    DIRECTION OUTPUT ;
    USE SIGNAL ;
    PORT
      LAYER M3 ;
        RECT 148.8240 647.9620 148.8420 648.0000 ;
    END
  END t_s[352]
  PIN t_s[353]
    DIRECTION OUTPUT ;
    USE SIGNAL ;
    PORT
      LAYER M5 ;
        RECT 149.1360 647.9160 149.1600 648.0000 ;
    END
  END t_s[353]
  PIN t_s[354]
    DIRECTION OUTPUT ;
    USE SIGNAL ;
    PORT
      LAYER M3 ;
        RECT 149.4360 647.9620 149.4540 648.0000 ;
    END
  END t_s[354]
  PIN t_s[355]
    DIRECTION OUTPUT ;
    USE SIGNAL ;
    PORT
      LAYER M5 ;
        RECT 149.7120 647.9160 149.7360 648.0000 ;
    END
  END t_s[355]
  PIN t_s[356]
    DIRECTION OUTPUT ;
    USE SIGNAL ;
    PORT
      LAYER M3 ;
        RECT 150.0120 647.9620 150.0300 648.0000 ;
    END
  END t_s[356]
  PIN t_s[357]
    DIRECTION OUTPUT ;
    USE SIGNAL ;
    PORT
      LAYER M5 ;
        RECT 150.3360 647.9160 150.3600 648.0000 ;
    END
  END t_s[357]
  PIN t_s[358]
    DIRECTION OUTPUT ;
    USE SIGNAL ;
    PORT
      LAYER M3 ;
        RECT 150.6240 647.9620 150.6420 648.0000 ;
    END
  END t_s[358]
  PIN t_s[359]
    DIRECTION OUTPUT ;
    USE SIGNAL ;
    PORT
      LAYER M5 ;
        RECT 150.9120 647.9160 150.9360 648.0000 ;
    END
  END t_s[359]
  PIN t_s[35]
    DIRECTION OUTPUT ;
    USE SIGNAL ;
    PORT
      LAYER M5 ;
        RECT 53.8080 647.9160 53.8320 648.0000 ;
    END
  END t_s[35]
  PIN t_s[360]
    DIRECTION OUTPUT ;
    USE SIGNAL ;
    PORT
      LAYER M3 ;
        RECT 151.2000 647.9620 151.2180 648.0000 ;
    END
  END t_s[360]
  PIN t_s[361]
    DIRECTION OUTPUT ;
    USE SIGNAL ;
    PORT
      LAYER M5 ;
        RECT 151.5360 647.9160 151.5600 648.0000 ;
    END
  END t_s[361]
  PIN t_s[362]
    DIRECTION OUTPUT ;
    USE SIGNAL ;
    PORT
      LAYER M3 ;
        RECT 151.8120 647.9620 151.8300 648.0000 ;
    END
  END t_s[362]
  PIN t_s[363]
    DIRECTION OUTPUT ;
    USE SIGNAL ;
    PORT
      LAYER M5 ;
        RECT 152.1120 647.9160 152.1360 648.0000 ;
    END
  END t_s[363]
  PIN t_s[364]
    DIRECTION OUTPUT ;
    USE SIGNAL ;
    PORT
      LAYER M3 ;
        RECT 152.4240 647.9620 152.4420 648.0000 ;
    END
  END t_s[364]
  PIN t_s[365]
    DIRECTION OUTPUT ;
    USE SIGNAL ;
    PORT
      LAYER M5 ;
        RECT 152.6880 647.9160 152.7120 648.0000 ;
    END
  END t_s[365]
  PIN t_s[366]
    DIRECTION OUTPUT ;
    USE SIGNAL ;
    PORT
      LAYER M3 ;
        RECT 153.0000 647.9620 153.0180 648.0000 ;
    END
  END t_s[366]
  PIN t_s[367]
    DIRECTION OUTPUT ;
    USE SIGNAL ;
    PORT
      LAYER M5 ;
        RECT 153.3120 647.9160 153.3360 648.0000 ;
    END
  END t_s[367]
  PIN t_s[368]
    DIRECTION OUTPUT ;
    USE SIGNAL ;
    PORT
      LAYER M3 ;
        RECT 153.6120 647.9620 153.6300 648.0000 ;
    END
  END t_s[368]
  PIN t_s[369]
    DIRECTION OUTPUT ;
    USE SIGNAL ;
    PORT
      LAYER M5 ;
        RECT 153.8880 647.9160 153.9120 648.0000 ;
    END
  END t_s[369]
  PIN t_s[36]
    DIRECTION OUTPUT ;
    USE SIGNAL ;
    PORT
      LAYER M3 ;
        RECT 54.1440 647.9620 54.1620 648.0000 ;
    END
  END t_s[36]
  PIN t_s[370]
    DIRECTION OUTPUT ;
    USE SIGNAL ;
    PORT
      LAYER M3 ;
        RECT 154.2240 647.9620 154.2420 648.0000 ;
    END
  END t_s[370]
  PIN t_s[371]
    DIRECTION OUTPUT ;
    USE SIGNAL ;
    PORT
      LAYER M5 ;
        RECT 154.5120 647.9160 154.5360 648.0000 ;
    END
  END t_s[371]
  PIN t_s[372]
    DIRECTION OUTPUT ;
    USE SIGNAL ;
    PORT
      LAYER M3 ;
        RECT 154.8000 647.9620 154.8180 648.0000 ;
    END
  END t_s[372]
  PIN t_s[373]
    DIRECTION OUTPUT ;
    USE SIGNAL ;
    PORT
      LAYER M5 ;
        RECT 155.0880 647.9160 155.1120 648.0000 ;
    END
  END t_s[373]
  PIN t_s[374]
    DIRECTION OUTPUT ;
    USE SIGNAL ;
    PORT
      LAYER M3 ;
        RECT 155.4120 647.9620 155.4300 648.0000 ;
    END
  END t_s[374]
  PIN t_s[375]
    DIRECTION OUTPUT ;
    USE SIGNAL ;
    PORT
      LAYER M5 ;
        RECT 155.7120 647.9160 155.7360 648.0000 ;
    END
  END t_s[375]
  PIN t_s[376]
    DIRECTION OUTPUT ;
    USE SIGNAL ;
    PORT
      LAYER M3 ;
        RECT 156.0240 647.9620 156.0420 648.0000 ;
    END
  END t_s[376]
  PIN t_s[377]
    DIRECTION OUTPUT ;
    USE SIGNAL ;
    PORT
      LAYER M5 ;
        RECT 156.2880 647.9160 156.3120 648.0000 ;
    END
  END t_s[377]
  PIN t_s[378]
    DIRECTION OUTPUT ;
    USE SIGNAL ;
    PORT
      LAYER M3 ;
        RECT 156.6000 647.9620 156.6180 648.0000 ;
    END
  END t_s[378]
  PIN t_s[379]
    DIRECTION OUTPUT ;
    USE SIGNAL ;
    PORT
      LAYER M5 ;
        RECT 156.9120 647.9160 156.9360 648.0000 ;
    END
  END t_s[379]
  PIN t_s[37]
    DIRECTION OUTPUT ;
    USE SIGNAL ;
    PORT
      LAYER M5 ;
        RECT 54.4320 647.9160 54.4560 648.0000 ;
    END
  END t_s[37]
  PIN t_s[380]
    DIRECTION OUTPUT ;
    USE SIGNAL ;
    PORT
      LAYER M3 ;
        RECT 157.2120 647.9620 157.2300 648.0000 ;
    END
  END t_s[380]
  PIN t_s[381]
    DIRECTION OUTPUT ;
    USE SIGNAL ;
    PORT
      LAYER M5 ;
        RECT 157.4880 647.9160 157.5120 648.0000 ;
    END
  END t_s[381]
  PIN t_s[382]
    DIRECTION OUTPUT ;
    USE SIGNAL ;
    PORT
      LAYER M3 ;
        RECT 157.8240 647.9620 157.8420 648.0000 ;
    END
  END t_s[382]
  PIN t_s[383]
    DIRECTION OUTPUT ;
    USE SIGNAL ;
    PORT
      LAYER M5 ;
        RECT 158.1120 647.9160 158.1360 648.0000 ;
    END
  END t_s[383]
  PIN t_s[384]
    DIRECTION OUTPUT ;
    USE SIGNAL ;
    PORT
      LAYER M3 ;
        RECT 158.4000 647.9620 158.4180 648.0000 ;
    END
  END t_s[384]
  PIN t_s[385]
    DIRECTION OUTPUT ;
    USE SIGNAL ;
    PORT
      LAYER M5 ;
        RECT 158.6880 647.9160 158.7120 648.0000 ;
    END
  END t_s[385]
  PIN t_s[386]
    DIRECTION OUTPUT ;
    USE SIGNAL ;
    PORT
      LAYER M3 ;
        RECT 159.0120 647.9620 159.0300 648.0000 ;
    END
  END t_s[386]
  PIN t_s[387]
    DIRECTION OUTPUT ;
    USE SIGNAL ;
    PORT
      LAYER M5 ;
        RECT 159.3120 647.9160 159.3360 648.0000 ;
    END
  END t_s[387]
  PIN t_s[388]
    DIRECTION OUTPUT ;
    USE SIGNAL ;
    PORT
      LAYER M3 ;
        RECT 159.6240 647.9620 159.6420 648.0000 ;
    END
  END t_s[388]
  PIN t_s[389]
    DIRECTION OUTPUT ;
    USE SIGNAL ;
    PORT
      LAYER M5 ;
        RECT 159.8880 647.9160 159.9120 648.0000 ;
    END
  END t_s[389]
  PIN t_s[38]
    DIRECTION OUTPUT ;
    USE SIGNAL ;
    PORT
      LAYER M3 ;
        RECT 54.7200 647.9620 54.7380 648.0000 ;
    END
  END t_s[38]
  PIN t_s[390]
    DIRECTION OUTPUT ;
    USE SIGNAL ;
    PORT
      LAYER M3 ;
        RECT 160.2000 647.9620 160.2180 648.0000 ;
    END
  END t_s[390]
  PIN t_s[391]
    DIRECTION OUTPUT ;
    USE SIGNAL ;
    PORT
      LAYER M5 ;
        RECT 160.5120 647.9160 160.5360 648.0000 ;
    END
  END t_s[391]
  PIN t_s[392]
    DIRECTION OUTPUT ;
    USE SIGNAL ;
    PORT
      LAYER M3 ;
        RECT 160.8120 647.9620 160.8300 648.0000 ;
    END
  END t_s[392]
  PIN t_s[393]
    DIRECTION OUTPUT ;
    USE SIGNAL ;
    PORT
      LAYER M5 ;
        RECT 161.0880 647.9160 161.1120 648.0000 ;
    END
  END t_s[393]
  PIN t_s[394]
    DIRECTION OUTPUT ;
    USE SIGNAL ;
    PORT
      LAYER M3 ;
        RECT 161.3880 647.9620 161.4060 648.0000 ;
    END
  END t_s[394]
  PIN t_s[395]
    DIRECTION OUTPUT ;
    USE SIGNAL ;
    PORT
      LAYER M5 ;
        RECT 161.7120 647.9160 161.7360 648.0000 ;
    END
  END t_s[395]
  PIN t_s[396]
    DIRECTION OUTPUT ;
    USE SIGNAL ;
    PORT
      LAYER M3 ;
        RECT 162.0000 647.9620 162.0180 648.0000 ;
    END
  END t_s[396]
  PIN t_s[397]
    DIRECTION OUTPUT ;
    USE SIGNAL ;
    PORT
      LAYER M5 ;
        RECT 162.2880 647.9160 162.3120 648.0000 ;
    END
  END t_s[397]
  PIN t_s[398]
    DIRECTION OUTPUT ;
    USE SIGNAL ;
    PORT
      LAYER M3 ;
        RECT 162.6120 647.9620 162.6300 648.0000 ;
    END
  END t_s[398]
  PIN t_s[399]
    DIRECTION OUTPUT ;
    USE SIGNAL ;
    PORT
      LAYER M5 ;
        RECT 162.9120 647.9160 162.9360 648.0000 ;
    END
  END t_s[399]
  PIN t_s[39]
    DIRECTION OUTPUT ;
    USE SIGNAL ;
    PORT
      LAYER M5 ;
        RECT 55.0080 647.9160 55.0320 648.0000 ;
    END
  END t_s[39]
  PIN t_s[3]
    DIRECTION OUTPUT ;
    USE SIGNAL ;
    PORT
      LAYER M5 ;
        RECT 44.2560 647.9160 44.2800 648.0000 ;
    END
  END t_s[3]
  PIN t_s[400]
    DIRECTION OUTPUT ;
    USE SIGNAL ;
    PORT
      LAYER M3 ;
        RECT 163.1880 647.9620 163.2060 648.0000 ;
    END
  END t_s[400]
  PIN t_s[401]
    DIRECTION OUTPUT ;
    USE SIGNAL ;
    PORT
      LAYER M5 ;
        RECT 163.4880 647.9160 163.5120 648.0000 ;
    END
  END t_s[401]
  PIN t_s[402]
    DIRECTION OUTPUT ;
    USE SIGNAL ;
    PORT
      LAYER M3 ;
        RECT 163.8000 647.9620 163.8180 648.0000 ;
    END
  END t_s[402]
  PIN t_s[403]
    DIRECTION OUTPUT ;
    USE SIGNAL ;
    PORT
      LAYER M5 ;
        RECT 164.1120 647.9160 164.1360 648.0000 ;
    END
  END t_s[403]
  PIN t_s[404]
    DIRECTION OUTPUT ;
    USE SIGNAL ;
    PORT
      LAYER M3 ;
        RECT 164.4120 647.9620 164.4300 648.0000 ;
    END
  END t_s[404]
  PIN t_s[405]
    DIRECTION OUTPUT ;
    USE SIGNAL ;
    PORT
      LAYER M5 ;
        RECT 164.6880 647.9160 164.7120 648.0000 ;
    END
  END t_s[405]
  PIN t_s[406]
    DIRECTION OUTPUT ;
    USE SIGNAL ;
    PORT
      LAYER M3 ;
        RECT 164.9880 647.9620 165.0060 648.0000 ;
    END
  END t_s[406]
  PIN t_s[407]
    DIRECTION OUTPUT ;
    USE SIGNAL ;
    PORT
      LAYER M5 ;
        RECT 165.3120 647.9160 165.3360 648.0000 ;
    END
  END t_s[407]
  PIN t_s[408]
    DIRECTION OUTPUT ;
    USE SIGNAL ;
    PORT
      LAYER M3 ;
        RECT 165.6000 647.9620 165.6180 648.0000 ;
    END
  END t_s[408]
  PIN t_s[409]
    DIRECTION OUTPUT ;
    USE SIGNAL ;
    PORT
      LAYER M5 ;
        RECT 165.8880 647.9160 165.9120 648.0000 ;
    END
  END t_s[409]
  PIN t_s[40]
    DIRECTION OUTPUT ;
    USE SIGNAL ;
    PORT
      LAYER M3 ;
        RECT 55.3320 647.9620 55.3500 648.0000 ;
    END
  END t_s[40]
  PIN t_s[410]
    DIRECTION OUTPUT ;
    USE SIGNAL ;
    PORT
      LAYER M3 ;
        RECT 166.2120 647.9620 166.2300 648.0000 ;
    END
  END t_s[410]
  PIN t_s[411]
    DIRECTION OUTPUT ;
    USE SIGNAL ;
    PORT
      LAYER M5 ;
        RECT 166.5120 647.9160 166.5360 648.0000 ;
    END
  END t_s[411]
  PIN t_s[412]
    DIRECTION OUTPUT ;
    USE SIGNAL ;
    PORT
      LAYER M3 ;
        RECT 166.7880 647.9620 166.8060 648.0000 ;
    END
  END t_s[412]
  PIN t_s[413]
    DIRECTION OUTPUT ;
    USE SIGNAL ;
    PORT
      LAYER M5 ;
        RECT 167.0880 647.9160 167.1120 648.0000 ;
    END
  END t_s[413]
  PIN t_s[414]
    DIRECTION OUTPUT ;
    USE SIGNAL ;
    PORT
      LAYER M3 ;
        RECT 167.4000 647.9620 167.4180 648.0000 ;
    END
  END t_s[414]
  PIN t_s[415]
    DIRECTION OUTPUT ;
    USE SIGNAL ;
    PORT
      LAYER M5 ;
        RECT 167.7120 647.9160 167.7360 648.0000 ;
    END
  END t_s[415]
  PIN t_s[416]
    DIRECTION OUTPUT ;
    USE SIGNAL ;
    PORT
      LAYER M3 ;
        RECT 168.0120 647.9620 168.0300 648.0000 ;
    END
  END t_s[416]
  PIN t_s[417]
    DIRECTION OUTPUT ;
    USE SIGNAL ;
    PORT
      LAYER M5 ;
        RECT 168.2880 647.9160 168.3120 648.0000 ;
    END
  END t_s[417]
  PIN t_s[418]
    DIRECTION OUTPUT ;
    USE SIGNAL ;
    PORT
      LAYER M3 ;
        RECT 168.5880 647.9620 168.6060 648.0000 ;
    END
  END t_s[418]
  PIN t_s[419]
    DIRECTION OUTPUT ;
    USE SIGNAL ;
    PORT
      LAYER M5 ;
        RECT 168.9120 647.9160 168.9360 648.0000 ;
    END
  END t_s[419]
  PIN t_s[41]
    DIRECTION OUTPUT ;
    USE SIGNAL ;
    PORT
      LAYER M5 ;
        RECT 55.6320 647.9160 55.6560 648.0000 ;
    END
  END t_s[41]
  PIN t_s[420]
    DIRECTION OUTPUT ;
    USE SIGNAL ;
    PORT
      LAYER M3 ;
        RECT 169.2000 647.9620 169.2180 648.0000 ;
    END
  END t_s[420]
  PIN t_s[421]
    DIRECTION OUTPUT ;
    USE SIGNAL ;
    PORT
      LAYER M5 ;
        RECT 169.4880 647.9160 169.5120 648.0000 ;
    END
  END t_s[421]
  PIN t_s[422]
    DIRECTION OUTPUT ;
    USE SIGNAL ;
    PORT
      LAYER M3 ;
        RECT 169.8120 647.9620 169.8300 648.0000 ;
    END
  END t_s[422]
  PIN t_s[423]
    DIRECTION OUTPUT ;
    USE SIGNAL ;
    PORT
      LAYER M5 ;
        RECT 170.1120 647.9160 170.1360 648.0000 ;
    END
  END t_s[423]
  PIN t_s[424]
    DIRECTION OUTPUT ;
    USE SIGNAL ;
    PORT
      LAYER M3 ;
        RECT 170.3880 647.9620 170.4060 648.0000 ;
    END
  END t_s[424]
  PIN t_s[425]
    DIRECTION OUTPUT ;
    USE SIGNAL ;
    PORT
      LAYER M5 ;
        RECT 170.6880 647.9160 170.7120 648.0000 ;
    END
  END t_s[425]
  PIN t_s[426]
    DIRECTION OUTPUT ;
    USE SIGNAL ;
    PORT
      LAYER M3 ;
        RECT 171.0000 647.9620 171.0180 648.0000 ;
    END
  END t_s[426]
  PIN t_s[427]
    DIRECTION OUTPUT ;
    USE SIGNAL ;
    PORT
      LAYER M5 ;
        RECT 171.3120 647.9160 171.3360 648.0000 ;
    END
  END t_s[427]
  PIN t_s[428]
    DIRECTION OUTPUT ;
    USE SIGNAL ;
    PORT
      LAYER M3 ;
        RECT 171.5760 647.9620 171.5940 648.0000 ;
    END
  END t_s[428]
  PIN t_s[429]
    DIRECTION OUTPUT ;
    USE SIGNAL ;
    PORT
      LAYER M5 ;
        RECT 171.8880 647.9160 171.9120 648.0000 ;
    END
  END t_s[429]
  PIN t_s[42]
    DIRECTION OUTPUT ;
    USE SIGNAL ;
    PORT
      LAYER M3 ;
        RECT 55.9440 647.9620 55.9620 648.0000 ;
    END
  END t_s[42]
  PIN t_s[430]
    DIRECTION OUTPUT ;
    USE SIGNAL ;
    PORT
      LAYER M3 ;
        RECT 172.1880 647.9620 172.2060 648.0000 ;
    END
  END t_s[430]
  PIN t_s[431]
    DIRECTION OUTPUT ;
    USE SIGNAL ;
    PORT
      LAYER M5 ;
        RECT 172.5120 647.9160 172.5360 648.0000 ;
    END
  END t_s[431]
  PIN t_s[432]
    DIRECTION OUTPUT ;
    USE SIGNAL ;
    PORT
      LAYER M3 ;
        RECT 172.8000 647.9620 172.8180 648.0000 ;
    END
  END t_s[432]
  PIN t_s[433]
    DIRECTION OUTPUT ;
    USE SIGNAL ;
    PORT
      LAYER M5 ;
        RECT 173.0880 647.9160 173.1120 648.0000 ;
    END
  END t_s[433]
  PIN t_s[434]
    DIRECTION OUTPUT ;
    USE SIGNAL ;
    PORT
      LAYER M3 ;
        RECT 173.3760 647.9620 173.3940 648.0000 ;
    END
  END t_s[434]
  PIN t_s[435]
    DIRECTION OUTPUT ;
    USE SIGNAL ;
    PORT
      LAYER M5 ;
        RECT 173.6640 647.9160 173.6880 648.0000 ;
    END
  END t_s[435]
  PIN t_s[436]
    DIRECTION OUTPUT ;
    USE SIGNAL ;
    PORT
      LAYER M3 ;
        RECT 173.9880 647.9620 174.0060 648.0000 ;
    END
  END t_s[436]
  PIN t_s[437]
    DIRECTION OUTPUT ;
    USE SIGNAL ;
    PORT
      LAYER M5 ;
        RECT 174.2880 647.9160 174.3120 648.0000 ;
    END
  END t_s[437]
  PIN t_s[438]
    DIRECTION OUTPUT ;
    USE SIGNAL ;
    PORT
      LAYER M3 ;
        RECT 174.6000 647.9620 174.6180 648.0000 ;
    END
  END t_s[438]
  PIN t_s[439]
    DIRECTION OUTPUT ;
    USE SIGNAL ;
    PORT
      LAYER M5 ;
        RECT 174.8640 647.9160 174.8880 648.0000 ;
    END
  END t_s[439]
  PIN t_s[43]
    DIRECTION OUTPUT ;
    USE SIGNAL ;
    PORT
      LAYER M5 ;
        RECT 56.2080 647.9160 56.2320 648.0000 ;
    END
  END t_s[43]
  PIN t_s[440]
    DIRECTION OUTPUT ;
    USE SIGNAL ;
    PORT
      LAYER M3 ;
        RECT 175.1760 647.9620 175.1940 648.0000 ;
    END
  END t_s[440]
  PIN t_s[441]
    DIRECTION OUTPUT ;
    USE SIGNAL ;
    PORT
      LAYER M5 ;
        RECT 175.4880 647.9160 175.5120 648.0000 ;
    END
  END t_s[441]
  PIN t_s[442]
    DIRECTION OUTPUT ;
    USE SIGNAL ;
    PORT
      LAYER M3 ;
        RECT 175.7880 647.9620 175.8060 648.0000 ;
    END
  END t_s[442]
  PIN t_s[443]
    DIRECTION OUTPUT ;
    USE SIGNAL ;
    PORT
      LAYER M5 ;
        RECT 176.0640 647.9160 176.0880 648.0000 ;
    END
  END t_s[443]
  PIN t_s[444]
    DIRECTION OUTPUT ;
    USE SIGNAL ;
    PORT
      LAYER M3 ;
        RECT 176.4000 647.9620 176.4180 648.0000 ;
    END
  END t_s[444]
  PIN t_s[445]
    DIRECTION OUTPUT ;
    USE SIGNAL ;
    PORT
      LAYER M5 ;
        RECT 176.6880 647.9160 176.7120 648.0000 ;
    END
  END t_s[445]
  PIN t_s[446]
    DIRECTION OUTPUT ;
    USE SIGNAL ;
    PORT
      LAYER M3 ;
        RECT 176.9760 647.9620 176.9940 648.0000 ;
    END
  END t_s[446]
  PIN t_s[447]
    DIRECTION OUTPUT ;
    USE SIGNAL ;
    PORT
      LAYER M5 ;
        RECT 177.2640 647.9160 177.2880 648.0000 ;
    END
  END t_s[447]
  PIN t_s[448]
    DIRECTION OUTPUT ;
    USE SIGNAL ;
    PORT
      LAYER M3 ;
        RECT 177.5880 647.9620 177.6060 648.0000 ;
    END
  END t_s[448]
  PIN t_s[449]
    DIRECTION OUTPUT ;
    USE SIGNAL ;
    PORT
      LAYER M5 ;
        RECT 177.8880 647.9160 177.9120 648.0000 ;
    END
  END t_s[449]
  PIN t_s[44]
    DIRECTION OUTPUT ;
    USE SIGNAL ;
    PORT
      LAYER M3 ;
        RECT 56.5200 647.9620 56.5380 648.0000 ;
    END
  END t_s[44]
  PIN t_s[450]
    DIRECTION OUTPUT ;
    USE SIGNAL ;
    PORT
      LAYER M3 ;
        RECT 178.2000 647.9620 178.2180 648.0000 ;
    END
  END t_s[450]
  PIN t_s[451]
    DIRECTION OUTPUT ;
    USE SIGNAL ;
    PORT
      LAYER M5 ;
        RECT 178.4640 647.9160 178.4880 648.0000 ;
    END
  END t_s[451]
  PIN t_s[452]
    DIRECTION OUTPUT ;
    USE SIGNAL ;
    PORT
      LAYER M3 ;
        RECT 178.7760 647.9620 178.7940 648.0000 ;
    END
  END t_s[452]
  PIN t_s[453]
    DIRECTION OUTPUT ;
    USE SIGNAL ;
    PORT
      LAYER M5 ;
        RECT 179.0880 647.9160 179.1120 648.0000 ;
    END
  END t_s[453]
  PIN t_s[454]
    DIRECTION OUTPUT ;
    USE SIGNAL ;
    PORT
      LAYER M3 ;
        RECT 179.3880 647.9620 179.4060 648.0000 ;
    END
  END t_s[454]
  PIN t_s[455]
    DIRECTION OUTPUT ;
    USE SIGNAL ;
    PORT
      LAYER M5 ;
        RECT 179.6640 647.9160 179.6880 648.0000 ;
    END
  END t_s[455]
  PIN t_s[456]
    DIRECTION OUTPUT ;
    USE SIGNAL ;
    PORT
      LAYER M3 ;
        RECT 180.0000 647.9620 180.0180 648.0000 ;
    END
  END t_s[456]
  PIN t_s[457]
    DIRECTION OUTPUT ;
    USE SIGNAL ;
    PORT
      LAYER M5 ;
        RECT 180.2880 647.9160 180.3120 648.0000 ;
    END
  END t_s[457]
  PIN t_s[458]
    DIRECTION OUTPUT ;
    USE SIGNAL ;
    PORT
      LAYER M3 ;
        RECT 180.5760 647.9620 180.5940 648.0000 ;
    END
  END t_s[458]
  PIN t_s[459]
    DIRECTION OUTPUT ;
    USE SIGNAL ;
    PORT
      LAYER M5 ;
        RECT 180.8640 647.9160 180.8880 648.0000 ;
    END
  END t_s[459]
  PIN t_s[45]
    DIRECTION OUTPUT ;
    USE SIGNAL ;
    PORT
      LAYER M5 ;
        RECT 56.8320 647.9160 56.8560 648.0000 ;
    END
  END t_s[45]
  PIN t_s[460]
    DIRECTION OUTPUT ;
    USE SIGNAL ;
    PORT
      LAYER M3 ;
        RECT 181.1880 647.9620 181.2060 648.0000 ;
    END
  END t_s[460]
  PIN t_s[461]
    DIRECTION OUTPUT ;
    USE SIGNAL ;
    PORT
      LAYER M5 ;
        RECT 181.4880 647.9160 181.5120 648.0000 ;
    END
  END t_s[461]
  PIN t_s[462]
    DIRECTION OUTPUT ;
    USE SIGNAL ;
    PORT
      LAYER M3 ;
        RECT 181.7640 647.9620 181.7820 648.0000 ;
    END
  END t_s[462]
  PIN t_s[463]
    DIRECTION OUTPUT ;
    USE SIGNAL ;
    PORT
      LAYER M5 ;
        RECT 182.0640 647.9160 182.0880 648.0000 ;
    END
  END t_s[463]
  PIN t_s[464]
    DIRECTION OUTPUT ;
    USE SIGNAL ;
    PORT
      LAYER M3 ;
        RECT 182.3760 647.9620 182.3940 648.0000 ;
    END
  END t_s[464]
  PIN t_s[465]
    DIRECTION OUTPUT ;
    USE SIGNAL ;
    PORT
      LAYER M5 ;
        RECT 182.6880 647.9160 182.7120 648.0000 ;
    END
  END t_s[465]
  PIN t_s[466]
    DIRECTION OUTPUT ;
    USE SIGNAL ;
    PORT
      LAYER M3 ;
        RECT 182.9880 647.9620 183.0060 648.0000 ;
    END
  END t_s[466]
  PIN t_s[467]
    DIRECTION OUTPUT ;
    USE SIGNAL ;
    PORT
      LAYER M5 ;
        RECT 183.2640 647.9160 183.2880 648.0000 ;
    END
  END t_s[467]
  PIN t_s[468]
    DIRECTION OUTPUT ;
    USE SIGNAL ;
    PORT
      LAYER M3 ;
        RECT 183.5640 647.9620 183.5820 648.0000 ;
    END
  END t_s[468]
  PIN t_s[469]
    DIRECTION OUTPUT ;
    USE SIGNAL ;
    PORT
      LAYER M5 ;
        RECT 183.8880 647.9160 183.9120 648.0000 ;
    END
  END t_s[469]
  PIN t_s[46]
    DIRECTION OUTPUT ;
    USE SIGNAL ;
    PORT
      LAYER M3 ;
        RECT 57.1320 647.9620 57.1500 648.0000 ;
    END
  END t_s[46]
  PIN t_s[470]
    DIRECTION OUTPUT ;
    USE SIGNAL ;
    PORT
      LAYER M3 ;
        RECT 184.1760 647.9620 184.1940 648.0000 ;
    END
  END t_s[470]
  PIN t_s[471]
    DIRECTION OUTPUT ;
    USE SIGNAL ;
    PORT
      LAYER M5 ;
        RECT 184.4640 647.9160 184.4880 648.0000 ;
    END
  END t_s[471]
  PIN t_s[472]
    DIRECTION OUTPUT ;
    USE SIGNAL ;
    PORT
      LAYER M3 ;
        RECT 184.7880 647.9620 184.8060 648.0000 ;
    END
  END t_s[472]
  PIN t_s[473]
    DIRECTION OUTPUT ;
    USE SIGNAL ;
    PORT
      LAYER M5 ;
        RECT 185.0880 647.9160 185.1120 648.0000 ;
    END
  END t_s[473]
  PIN t_s[474]
    DIRECTION OUTPUT ;
    USE SIGNAL ;
    PORT
      LAYER M3 ;
        RECT 185.3640 647.9620 185.3820 648.0000 ;
    END
  END t_s[474]
  PIN t_s[475]
    DIRECTION OUTPUT ;
    USE SIGNAL ;
    PORT
      LAYER M5 ;
        RECT 185.6640 647.9160 185.6880 648.0000 ;
    END
  END t_s[475]
  PIN t_s[476]
    DIRECTION OUTPUT ;
    USE SIGNAL ;
    PORT
      LAYER M3 ;
        RECT 185.9760 647.9620 185.9940 648.0000 ;
    END
  END t_s[476]
  PIN t_s[477]
    DIRECTION OUTPUT ;
    USE SIGNAL ;
    PORT
      LAYER M5 ;
        RECT 186.2880 647.9160 186.3120 648.0000 ;
    END
  END t_s[477]
  PIN t_s[478]
    DIRECTION OUTPUT ;
    USE SIGNAL ;
    PORT
      LAYER M3 ;
        RECT 186.5880 647.9620 186.6060 648.0000 ;
    END
  END t_s[478]
  PIN t_s[479]
    DIRECTION OUTPUT ;
    USE SIGNAL ;
    PORT
      LAYER M5 ;
        RECT 186.8640 647.9160 186.8880 648.0000 ;
    END
  END t_s[479]
  PIN t_s[47]
    DIRECTION OUTPUT ;
    USE SIGNAL ;
    PORT
      LAYER M5 ;
        RECT 57.4080 647.9160 57.4320 648.0000 ;
    END
  END t_s[47]
  PIN t_s[480]
    DIRECTION OUTPUT ;
    USE SIGNAL ;
    PORT
      LAYER M3 ;
        RECT 187.1640 647.9620 187.1820 648.0000 ;
    END
  END t_s[480]
  PIN t_s[481]
    DIRECTION OUTPUT ;
    USE SIGNAL ;
    PORT
      LAYER M5 ;
        RECT 187.4880 647.9160 187.5120 648.0000 ;
    END
  END t_s[481]
  PIN t_s[482]
    DIRECTION OUTPUT ;
    USE SIGNAL ;
    PORT
      LAYER M3 ;
        RECT 187.7760 647.9620 187.7940 648.0000 ;
    END
  END t_s[482]
  PIN t_s[483]
    DIRECTION OUTPUT ;
    USE SIGNAL ;
    PORT
      LAYER M5 ;
        RECT 188.0640 647.9160 188.0880 648.0000 ;
    END
  END t_s[483]
  PIN t_s[484]
    DIRECTION OUTPUT ;
    USE SIGNAL ;
    PORT
      LAYER M3 ;
        RECT 188.3880 647.9620 188.4060 648.0000 ;
    END
  END t_s[484]
  PIN t_s[485]
    DIRECTION OUTPUT ;
    USE SIGNAL ;
    PORT
      LAYER M5 ;
        RECT 188.6880 647.9160 188.7120 648.0000 ;
    END
  END t_s[485]
  PIN t_s[486]
    DIRECTION OUTPUT ;
    USE SIGNAL ;
    PORT
      LAYER M3 ;
        RECT 188.9640 647.9620 188.9820 648.0000 ;
    END
  END t_s[486]
  PIN t_s[487]
    DIRECTION OUTPUT ;
    USE SIGNAL ;
    PORT
      LAYER M5 ;
        RECT 189.2640 647.9160 189.2880 648.0000 ;
    END
  END t_s[487]
  PIN t_s[488]
    DIRECTION OUTPUT ;
    USE SIGNAL ;
    PORT
      LAYER M3 ;
        RECT 189.5760 647.9620 189.5940 648.0000 ;
    END
  END t_s[488]
  PIN t_s[489]
    DIRECTION OUTPUT ;
    USE SIGNAL ;
    PORT
      LAYER M5 ;
        RECT 189.8880 647.9160 189.9120 648.0000 ;
    END
  END t_s[489]
  PIN t_s[48]
    DIRECTION OUTPUT ;
    USE SIGNAL ;
    PORT
      LAYER M3 ;
        RECT 57.7080 647.9620 57.7260 648.0000 ;
    END
  END t_s[48]
  PIN t_s[490]
    DIRECTION OUTPUT ;
    USE SIGNAL ;
    PORT
      LAYER M3 ;
        RECT 190.1880 647.9620 190.2060 648.0000 ;
    END
  END t_s[490]
  PIN t_s[491]
    DIRECTION OUTPUT ;
    USE SIGNAL ;
    PORT
      LAYER M5 ;
        RECT 190.4640 647.9160 190.4880 648.0000 ;
    END
  END t_s[491]
  PIN t_s[492]
    DIRECTION OUTPUT ;
    USE SIGNAL ;
    PORT
      LAYER M3 ;
        RECT 190.7640 647.9620 190.7820 648.0000 ;
    END
  END t_s[492]
  PIN t_s[493]
    DIRECTION OUTPUT ;
    USE SIGNAL ;
    PORT
      LAYER M5 ;
        RECT 191.0880 647.9160 191.1120 648.0000 ;
    END
  END t_s[493]
  PIN t_s[494]
    DIRECTION OUTPUT ;
    USE SIGNAL ;
    PORT
      LAYER M3 ;
        RECT 191.3760 647.9620 191.3940 648.0000 ;
    END
  END t_s[494]
  PIN t_s[495]
    DIRECTION OUTPUT ;
    USE SIGNAL ;
    PORT
      LAYER M5 ;
        RECT 191.6640 647.9160 191.6880 648.0000 ;
    END
  END t_s[495]
  PIN t_s[496]
    DIRECTION OUTPUT ;
    USE SIGNAL ;
    PORT
      LAYER M3 ;
        RECT 191.9520 647.9620 191.9700 648.0000 ;
    END
  END t_s[496]
  PIN t_s[497]
    DIRECTION OUTPUT ;
    USE SIGNAL ;
    PORT
      LAYER M5 ;
        RECT 192.2880 647.9160 192.3120 648.0000 ;
    END
  END t_s[497]
  PIN t_s[498]
    DIRECTION OUTPUT ;
    USE SIGNAL ;
    PORT
      LAYER M3 ;
        RECT 192.5640 647.9620 192.5820 648.0000 ;
    END
  END t_s[498]
  PIN t_s[499]
    DIRECTION OUTPUT ;
    USE SIGNAL ;
    PORT
      LAYER M5 ;
        RECT 192.8640 647.9160 192.8880 648.0000 ;
    END
  END t_s[499]
  PIN t_s[49]
    DIRECTION OUTPUT ;
    USE SIGNAL ;
    PORT
      LAYER M5 ;
        RECT 58.0320 647.9160 58.0560 648.0000 ;
    END
  END t_s[49]
  PIN t_s[4]
    DIRECTION OUTPUT ;
    USE SIGNAL ;
    PORT
      LAYER M3 ;
        RECT 44.5320 647.9620 44.5500 648.0000 ;
    END
  END t_s[4]
  PIN t_s[500]
    DIRECTION OUTPUT ;
    USE SIGNAL ;
    PORT
      LAYER M3 ;
        RECT 193.1760 647.9620 193.1940 648.0000 ;
    END
  END t_s[500]
  PIN t_s[501]
    DIRECTION OUTPUT ;
    USE SIGNAL ;
    PORT
      LAYER M5 ;
        RECT 193.4880 647.9160 193.5120 648.0000 ;
    END
  END t_s[501]
  PIN t_s[502]
    DIRECTION OUTPUT ;
    USE SIGNAL ;
    PORT
      LAYER M3 ;
        RECT 193.7520 647.9620 193.7700 648.0000 ;
    END
  END t_s[502]
  PIN t_s[503]
    DIRECTION OUTPUT ;
    USE SIGNAL ;
    PORT
      LAYER M5 ;
        RECT 194.0640 647.9160 194.0880 648.0000 ;
    END
  END t_s[503]
  PIN t_s[504]
    DIRECTION OUTPUT ;
    USE SIGNAL ;
    PORT
      LAYER M3 ;
        RECT 194.3640 647.9620 194.3820 648.0000 ;
    END
  END t_s[504]
  PIN t_s[505]
    DIRECTION OUTPUT ;
    USE SIGNAL ;
    PORT
      LAYER M5 ;
        RECT 194.6400 647.9160 194.6640 648.0000 ;
    END
  END t_s[505]
  PIN t_s[506]
    DIRECTION OUTPUT ;
    USE SIGNAL ;
    PORT
      LAYER M3 ;
        RECT 194.9760 647.9620 194.9940 648.0000 ;
    END
  END t_s[506]
  PIN t_s[507]
    DIRECTION OUTPUT ;
    USE SIGNAL ;
    PORT
      LAYER M5 ;
        RECT 195.2640 647.9160 195.2880 648.0000 ;
    END
  END t_s[507]
  PIN t_s[508]
    DIRECTION OUTPUT ;
    USE SIGNAL ;
    PORT
      LAYER M3 ;
        RECT 195.5520 647.9620 195.5700 648.0000 ;
    END
  END t_s[508]
  PIN t_s[509]
    DIRECTION OUTPUT ;
    USE SIGNAL ;
    PORT
      LAYER M5 ;
        RECT 195.8400 647.9160 195.8640 648.0000 ;
    END
  END t_s[509]
  PIN t_s[50]
    DIRECTION OUTPUT ;
    USE SIGNAL ;
    PORT
      LAYER M3 ;
        RECT 58.3200 647.9620 58.3380 648.0000 ;
    END
  END t_s[50]
  PIN t_s[510]
    DIRECTION OUTPUT ;
    USE SIGNAL ;
    PORT
      LAYER M3 ;
        RECT 196.1640 647.9620 196.1820 648.0000 ;
    END
  END t_s[510]
  PIN t_s[511]
    DIRECTION OUTPUT ;
    USE SIGNAL ;
    PORT
      LAYER M5 ;
        RECT 196.4640 647.9160 196.4880 648.0000 ;
    END
  END t_s[511]
  PIN t_s[512]
    DIRECTION OUTPUT ;
    USE SIGNAL ;
    PORT
      LAYER M3 ;
        RECT 196.7760 647.9620 196.7940 648.0000 ;
    END
  END t_s[512]
  PIN t_s[513]
    DIRECTION OUTPUT ;
    USE SIGNAL ;
    PORT
      LAYER M5 ;
        RECT 197.0400 647.9160 197.0640 648.0000 ;
    END
  END t_s[513]
  PIN t_s[514]
    DIRECTION OUTPUT ;
    USE SIGNAL ;
    PORT
      LAYER M3 ;
        RECT 197.3520 647.9620 197.3700 648.0000 ;
    END
  END t_s[514]
  PIN t_s[515]
    DIRECTION OUTPUT ;
    USE SIGNAL ;
    PORT
      LAYER M5 ;
        RECT 197.6640 647.9160 197.6880 648.0000 ;
    END
  END t_s[515]
  PIN t_s[516]
    DIRECTION OUTPUT ;
    USE SIGNAL ;
    PORT
      LAYER M3 ;
        RECT 197.9640 647.9620 197.9820 648.0000 ;
    END
  END t_s[516]
  PIN t_s[517]
    DIRECTION OUTPUT ;
    USE SIGNAL ;
    PORT
      LAYER M5 ;
        RECT 198.2400 647.9160 198.2640 648.0000 ;
    END
  END t_s[517]
  PIN t_s[518]
    DIRECTION OUTPUT ;
    USE SIGNAL ;
    PORT
      LAYER M3 ;
        RECT 198.5760 647.9620 198.5940 648.0000 ;
    END
  END t_s[518]
  PIN t_s[519]
    DIRECTION OUTPUT ;
    USE SIGNAL ;
    PORT
      LAYER M5 ;
        RECT 198.8640 647.9160 198.8880 648.0000 ;
    END
  END t_s[519]
  PIN t_s[51]
    DIRECTION OUTPUT ;
    USE SIGNAL ;
    PORT
      LAYER M5 ;
        RECT 58.6080 647.9160 58.6320 648.0000 ;
    END
  END t_s[51]
  PIN t_s[520]
    DIRECTION OUTPUT ;
    USE SIGNAL ;
    PORT
      LAYER M3 ;
        RECT 199.1520 647.9620 199.1700 648.0000 ;
    END
  END t_s[520]
  PIN t_s[521]
    DIRECTION OUTPUT ;
    USE SIGNAL ;
    PORT
      LAYER M5 ;
        RECT 199.4400 647.9160 199.4640 648.0000 ;
    END
  END t_s[521]
  PIN t_s[522]
    DIRECTION OUTPUT ;
    USE SIGNAL ;
    PORT
      LAYER M3 ;
        RECT 199.7640 647.9620 199.7820 648.0000 ;
    END
  END t_s[522]
  PIN t_s[523]
    DIRECTION OUTPUT ;
    USE SIGNAL ;
    PORT
      LAYER M5 ;
        RECT 200.0640 647.9160 200.0880 648.0000 ;
    END
  END t_s[523]
  PIN t_s[524]
    DIRECTION OUTPUT ;
    USE SIGNAL ;
    PORT
      LAYER M3 ;
        RECT 200.3760 647.9620 200.3940 648.0000 ;
    END
  END t_s[524]
  PIN t_s[525]
    DIRECTION OUTPUT ;
    USE SIGNAL ;
    PORT
      LAYER M5 ;
        RECT 200.6400 647.9160 200.6640 648.0000 ;
    END
  END t_s[525]
  PIN t_s[526]
    DIRECTION OUTPUT ;
    USE SIGNAL ;
    PORT
      LAYER M3 ;
        RECT 200.9520 647.9620 200.9700 648.0000 ;
    END
  END t_s[526]
  PIN t_s[527]
    DIRECTION OUTPUT ;
    USE SIGNAL ;
    PORT
      LAYER M5 ;
        RECT 201.2640 647.9160 201.2880 648.0000 ;
    END
  END t_s[527]
  PIN t_s[528]
    DIRECTION OUTPUT ;
    USE SIGNAL ;
    PORT
      LAYER M3 ;
        RECT 201.5640 647.9620 201.5820 648.0000 ;
    END
  END t_s[528]
  PIN t_s[529]
    DIRECTION OUTPUT ;
    USE SIGNAL ;
    PORT
      LAYER M5 ;
        RECT 201.8400 647.9160 201.8640 648.0000 ;
    END
  END t_s[529]
  PIN t_s[52]
    DIRECTION OUTPUT ;
    USE SIGNAL ;
    PORT
      LAYER M3 ;
        RECT 58.9320 647.9620 58.9500 648.0000 ;
    END
  END t_s[52]
  PIN t_s[530]
    DIRECTION OUTPUT ;
    USE SIGNAL ;
    PORT
      LAYER M3 ;
        RECT 202.1400 647.9620 202.1580 648.0000 ;
    END
  END t_s[530]
  PIN t_s[531]
    DIRECTION OUTPUT ;
    USE SIGNAL ;
    PORT
      LAYER M5 ;
        RECT 202.4640 647.9160 202.4880 648.0000 ;
    END
  END t_s[531]
  PIN t_s[532]
    DIRECTION OUTPUT ;
    USE SIGNAL ;
    PORT
      LAYER M3 ;
        RECT 202.7520 647.9620 202.7700 648.0000 ;
    END
  END t_s[532]
  PIN t_s[533]
    DIRECTION OUTPUT ;
    USE SIGNAL ;
    PORT
      LAYER M5 ;
        RECT 203.0400 647.9160 203.0640 648.0000 ;
    END
  END t_s[533]
  PIN t_s[534]
    DIRECTION OUTPUT ;
    USE SIGNAL ;
    PORT
      LAYER M3 ;
        RECT 203.3640 647.9620 203.3820 648.0000 ;
    END
  END t_s[534]
  PIN t_s[535]
    DIRECTION OUTPUT ;
    USE SIGNAL ;
    PORT
      LAYER M5 ;
        RECT 203.6640 647.9160 203.6880 648.0000 ;
    END
  END t_s[535]
  PIN t_s[536]
    DIRECTION OUTPUT ;
    USE SIGNAL ;
    PORT
      LAYER M3 ;
        RECT 203.9400 647.9620 203.9580 648.0000 ;
    END
  END t_s[536]
  PIN t_s[537]
    DIRECTION OUTPUT ;
    USE SIGNAL ;
    PORT
      LAYER M5 ;
        RECT 204.2400 647.9160 204.2640 648.0000 ;
    END
  END t_s[537]
  PIN t_s[538]
    DIRECTION OUTPUT ;
    USE SIGNAL ;
    PORT
      LAYER M3 ;
        RECT 204.5520 647.9620 204.5700 648.0000 ;
    END
  END t_s[538]
  PIN t_s[539]
    DIRECTION OUTPUT ;
    USE SIGNAL ;
    PORT
      LAYER M5 ;
        RECT 204.8640 647.9160 204.8880 648.0000 ;
    END
  END t_s[539]
  PIN t_s[53]
    DIRECTION OUTPUT ;
    USE SIGNAL ;
    PORT
      LAYER M5 ;
        RECT 59.2320 647.9160 59.2560 648.0000 ;
    END
  END t_s[53]
  PIN t_s[540]
    DIRECTION OUTPUT ;
    USE SIGNAL ;
    PORT
      LAYER M3 ;
        RECT 205.1640 647.9620 205.1820 648.0000 ;
    END
  END t_s[540]
  PIN t_s[541]
    DIRECTION OUTPUT ;
    USE SIGNAL ;
    PORT
      LAYER M5 ;
        RECT 205.4400 647.9160 205.4640 648.0000 ;
    END
  END t_s[541]
  PIN t_s[542]
    DIRECTION OUTPUT ;
    USE SIGNAL ;
    PORT
      LAYER M3 ;
        RECT 205.7400 647.9620 205.7580 648.0000 ;
    END
  END t_s[542]
  PIN t_s[543]
    DIRECTION OUTPUT ;
    USE SIGNAL ;
    PORT
      LAYER M5 ;
        RECT 206.0640 647.9160 206.0880 648.0000 ;
    END
  END t_s[543]
  PIN t_s[544]
    DIRECTION OUTPUT ;
    USE SIGNAL ;
    PORT
      LAYER M3 ;
        RECT 206.3520 647.9620 206.3700 648.0000 ;
    END
  END t_s[544]
  PIN t_s[545]
    DIRECTION OUTPUT ;
    USE SIGNAL ;
    PORT
      LAYER M5 ;
        RECT 206.6400 647.9160 206.6640 648.0000 ;
    END
  END t_s[545]
  PIN t_s[546]
    DIRECTION OUTPUT ;
    USE SIGNAL ;
    PORT
      LAYER M3 ;
        RECT 206.9640 647.9620 206.9820 648.0000 ;
    END
  END t_s[546]
  PIN t_s[547]
    DIRECTION OUTPUT ;
    USE SIGNAL ;
    PORT
      LAYER M5 ;
        RECT 207.2640 647.9160 207.2880 648.0000 ;
    END
  END t_s[547]
  PIN t_s[548]
    DIRECTION OUTPUT ;
    USE SIGNAL ;
    PORT
      LAYER M3 ;
        RECT 207.5400 647.9620 207.5580 648.0000 ;
    END
  END t_s[548]
  PIN t_s[549]
    DIRECTION OUTPUT ;
    USE SIGNAL ;
    PORT
      LAYER M5 ;
        RECT 207.8400 647.9160 207.8640 648.0000 ;
    END
  END t_s[549]
  PIN t_s[54]
    DIRECTION OUTPUT ;
    USE SIGNAL ;
    PORT
      LAYER M3 ;
        RECT 59.5080 647.9620 59.5260 648.0000 ;
    END
  END t_s[54]
  PIN t_s[550]
    DIRECTION OUTPUT ;
    USE SIGNAL ;
    PORT
      LAYER M3 ;
        RECT 208.1520 647.9620 208.1700 648.0000 ;
    END
  END t_s[550]
  PIN t_s[551]
    DIRECTION OUTPUT ;
    USE SIGNAL ;
    PORT
      LAYER M5 ;
        RECT 208.4640 647.9160 208.4880 648.0000 ;
    END
  END t_s[551]
  PIN t_s[552]
    DIRECTION OUTPUT ;
    USE SIGNAL ;
    PORT
      LAYER M3 ;
        RECT 208.7640 647.9620 208.7820 648.0000 ;
    END
  END t_s[552]
  PIN t_s[553]
    DIRECTION OUTPUT ;
    USE SIGNAL ;
    PORT
      LAYER M5 ;
        RECT 209.0400 647.9160 209.0640 648.0000 ;
    END
  END t_s[553]
  PIN t_s[554]
    DIRECTION OUTPUT ;
    USE SIGNAL ;
    PORT
      LAYER M3 ;
        RECT 209.3400 647.9620 209.3580 648.0000 ;
    END
  END t_s[554]
  PIN t_s[555]
    DIRECTION OUTPUT ;
    USE SIGNAL ;
    PORT
      LAYER M5 ;
        RECT 209.6640 647.9160 209.6880 648.0000 ;
    END
  END t_s[555]
  PIN t_s[556]
    DIRECTION OUTPUT ;
    USE SIGNAL ;
    PORT
      LAYER M3 ;
        RECT 209.9520 647.9620 209.9700 648.0000 ;
    END
  END t_s[556]
  PIN t_s[557]
    DIRECTION OUTPUT ;
    USE SIGNAL ;
    PORT
      LAYER M5 ;
        RECT 210.2400 647.9160 210.2640 648.0000 ;
    END
  END t_s[557]
  PIN t_s[558]
    DIRECTION OUTPUT ;
    USE SIGNAL ;
    PORT
      LAYER M3 ;
        RECT 210.5640 647.9620 210.5820 648.0000 ;
    END
  END t_s[558]
  PIN t_s[559]
    DIRECTION OUTPUT ;
    USE SIGNAL ;
    PORT
      LAYER M5 ;
        RECT 210.8640 647.9160 210.8880 648.0000 ;
    END
  END t_s[559]
  PIN t_s[55]
    DIRECTION OUTPUT ;
    USE SIGNAL ;
    PORT
      LAYER M5 ;
        RECT 59.8080 647.9160 59.8320 648.0000 ;
    END
  END t_s[55]
  PIN t_s[560]
    DIRECTION OUTPUT ;
    USE SIGNAL ;
    PORT
      LAYER M3 ;
        RECT 211.1400 647.9620 211.1580 648.0000 ;
    END
  END t_s[560]
  PIN t_s[561]
    DIRECTION OUTPUT ;
    USE SIGNAL ;
    PORT
      LAYER M5 ;
        RECT 211.4400 647.9160 211.4640 648.0000 ;
    END
  END t_s[561]
  PIN t_s[562]
    DIRECTION OUTPUT ;
    USE SIGNAL ;
    PORT
      LAYER M3 ;
        RECT 211.7520 647.9620 211.7700 648.0000 ;
    END
  END t_s[562]
  PIN t_s[563]
    DIRECTION OUTPUT ;
    USE SIGNAL ;
    PORT
      LAYER M5 ;
        RECT 212.0640 647.9160 212.0880 648.0000 ;
    END
  END t_s[563]
  PIN t_s[564]
    DIRECTION OUTPUT ;
    USE SIGNAL ;
    PORT
      LAYER M3 ;
        RECT 212.3280 647.9620 212.3460 648.0000 ;
    END
  END t_s[564]
  PIN t_s[565]
    DIRECTION OUTPUT ;
    USE SIGNAL ;
    PORT
      LAYER M5 ;
        RECT 212.6400 647.9160 212.6640 648.0000 ;
    END
  END t_s[565]
  PIN t_s[566]
    DIRECTION OUTPUT ;
    USE SIGNAL ;
    PORT
      LAYER M3 ;
        RECT 212.9400 647.9620 212.9580 648.0000 ;
    END
  END t_s[566]
  PIN t_s[567]
    DIRECTION OUTPUT ;
    USE SIGNAL ;
    PORT
      LAYER M5 ;
        RECT 213.2640 647.9160 213.2880 648.0000 ;
    END
  END t_s[567]
  PIN t_s[568]
    DIRECTION OUTPUT ;
    USE SIGNAL ;
    PORT
      LAYER M3 ;
        RECT 213.5520 647.9620 213.5700 648.0000 ;
    END
  END t_s[568]
  PIN t_s[569]
    DIRECTION OUTPUT ;
    USE SIGNAL ;
    PORT
      LAYER M5 ;
        RECT 213.8400 647.9160 213.8640 648.0000 ;
    END
  END t_s[569]
  PIN t_s[56]
    DIRECTION OUTPUT ;
    USE SIGNAL ;
    PORT
      LAYER M3 ;
        RECT 60.1200 647.9620 60.1380 648.0000 ;
    END
  END t_s[56]
  PIN t_s[570]
    DIRECTION OUTPUT ;
    USE SIGNAL ;
    PORT
      LAYER M3 ;
        RECT 214.1280 647.9620 214.1460 648.0000 ;
    END
  END t_s[570]
  PIN t_s[571]
    DIRECTION OUTPUT ;
    USE SIGNAL ;
    PORT
      LAYER M5 ;
        RECT 214.4640 647.9160 214.4880 648.0000 ;
    END
  END t_s[571]
  PIN t_s[572]
    DIRECTION OUTPUT ;
    USE SIGNAL ;
    PORT
      LAYER M3 ;
        RECT 214.7400 647.9620 214.7580 648.0000 ;
    END
  END t_s[572]
  PIN t_s[573]
    DIRECTION OUTPUT ;
    USE SIGNAL ;
    PORT
      LAYER M5 ;
        RECT 215.0400 647.9160 215.0640 648.0000 ;
    END
  END t_s[573]
  PIN t_s[574]
    DIRECTION OUTPUT ;
    USE SIGNAL ;
    PORT
      LAYER M3 ;
        RECT 215.3520 647.9620 215.3700 648.0000 ;
    END
  END t_s[574]
  PIN t_s[575]
    DIRECTION OUTPUT ;
    USE SIGNAL ;
    PORT
      LAYER M5 ;
        RECT 215.6160 647.9160 215.6400 648.0000 ;
    END
  END t_s[575]
  PIN t_s[576]
    DIRECTION OUTPUT ;
    USE SIGNAL ;
    PORT
      LAYER M3 ;
        RECT 215.9280 647.9620 215.9460 648.0000 ;
    END
  END t_s[576]
  PIN t_s[577]
    DIRECTION OUTPUT ;
    USE SIGNAL ;
    PORT
      LAYER M5 ;
        RECT 216.2400 647.9160 216.2640 648.0000 ;
    END
  END t_s[577]
  PIN t_s[578]
    DIRECTION OUTPUT ;
    USE SIGNAL ;
    PORT
      LAYER M3 ;
        RECT 216.5400 647.9620 216.5580 648.0000 ;
    END
  END t_s[578]
  PIN t_s[579]
    DIRECTION OUTPUT ;
    USE SIGNAL ;
    PORT
      LAYER M5 ;
        RECT 216.8160 647.9160 216.8400 648.0000 ;
    END
  END t_s[579]
  PIN t_s[57]
    DIRECTION OUTPUT ;
    USE SIGNAL ;
    PORT
      LAYER M5 ;
        RECT 60.4320 647.9160 60.4560 648.0000 ;
    END
  END t_s[57]
  PIN t_s[580]
    DIRECTION OUTPUT ;
    USE SIGNAL ;
    PORT
      LAYER M3 ;
        RECT 217.1520 647.9620 217.1700 648.0000 ;
    END
  END t_s[580]
  PIN t_s[581]
    DIRECTION OUTPUT ;
    USE SIGNAL ;
    PORT
      LAYER M5 ;
        RECT 217.4400 647.9160 217.4640 648.0000 ;
    END
  END t_s[581]
  PIN t_s[582]
    DIRECTION OUTPUT ;
    USE SIGNAL ;
    PORT
      LAYER M3 ;
        RECT 217.7280 647.9620 217.7460 648.0000 ;
    END
  END t_s[582]
  PIN t_s[583]
    DIRECTION OUTPUT ;
    USE SIGNAL ;
    PORT
      LAYER M5 ;
        RECT 218.0160 647.9160 218.0400 648.0000 ;
    END
  END t_s[583]
  PIN t_s[584]
    DIRECTION OUTPUT ;
    USE SIGNAL ;
    PORT
      LAYER M3 ;
        RECT 218.3400 647.9620 218.3580 648.0000 ;
    END
  END t_s[584]
  PIN t_s[585]
    DIRECTION OUTPUT ;
    USE SIGNAL ;
    PORT
      LAYER M5 ;
        RECT 218.6400 647.9160 218.6640 648.0000 ;
    END
  END t_s[585]
  PIN t_s[586]
    DIRECTION OUTPUT ;
    USE SIGNAL ;
    PORT
      LAYER M3 ;
        RECT 218.9520 647.9620 218.9700 648.0000 ;
    END
  END t_s[586]
  PIN t_s[587]
    DIRECTION OUTPUT ;
    USE SIGNAL ;
    PORT
      LAYER M5 ;
        RECT 219.2160 647.9160 219.2400 648.0000 ;
    END
  END t_s[587]
  PIN t_s[588]
    DIRECTION OUTPUT ;
    USE SIGNAL ;
    PORT
      LAYER M3 ;
        RECT 219.5280 647.9620 219.5460 648.0000 ;
    END
  END t_s[588]
  PIN t_s[589]
    DIRECTION OUTPUT ;
    USE SIGNAL ;
    PORT
      LAYER M5 ;
        RECT 219.8400 647.9160 219.8640 648.0000 ;
    END
  END t_s[589]
  PIN t_s[58]
    DIRECTION OUTPUT ;
    USE SIGNAL ;
    PORT
      LAYER M3 ;
        RECT 60.7320 647.9620 60.7500 648.0000 ;
    END
  END t_s[58]
  PIN t_s[590]
    DIRECTION OUTPUT ;
    USE SIGNAL ;
    PORT
      LAYER M3 ;
        RECT 220.1400 647.9620 220.1580 648.0000 ;
    END
  END t_s[590]
  PIN t_s[591]
    DIRECTION OUTPUT ;
    USE SIGNAL ;
    PORT
      LAYER M5 ;
        RECT 220.4160 647.9160 220.4400 648.0000 ;
    END
  END t_s[591]
  PIN t_s[592]
    DIRECTION OUTPUT ;
    USE SIGNAL ;
    PORT
      LAYER M3 ;
        RECT 220.7520 647.9620 220.7700 648.0000 ;
    END
  END t_s[592]
  PIN t_s[593]
    DIRECTION OUTPUT ;
    USE SIGNAL ;
    PORT
      LAYER M5 ;
        RECT 221.0400 647.9160 221.0640 648.0000 ;
    END
  END t_s[593]
  PIN t_s[594]
    DIRECTION OUTPUT ;
    USE SIGNAL ;
    PORT
      LAYER M3 ;
        RECT 221.3280 647.9620 221.3460 648.0000 ;
    END
  END t_s[594]
  PIN t_s[595]
    DIRECTION OUTPUT ;
    USE SIGNAL ;
    PORT
      LAYER M5 ;
        RECT 221.6160 647.9160 221.6400 648.0000 ;
    END
  END t_s[595]
  PIN t_s[596]
    DIRECTION OUTPUT ;
    USE SIGNAL ;
    PORT
      LAYER M3 ;
        RECT 221.9400 647.9620 221.9580 648.0000 ;
    END
  END t_s[596]
  PIN t_s[597]
    DIRECTION OUTPUT ;
    USE SIGNAL ;
    PORT
      LAYER M5 ;
        RECT 222.2400 647.9160 222.2640 648.0000 ;
    END
  END t_s[597]
  PIN t_s[598]
    DIRECTION OUTPUT ;
    USE SIGNAL ;
    PORT
      LAYER M3 ;
        RECT 222.5160 647.9620 222.5340 648.0000 ;
    END
  END t_s[598]
  PIN t_s[599]
    DIRECTION OUTPUT ;
    USE SIGNAL ;
    PORT
      LAYER M5 ;
        RECT 222.8160 647.9160 222.8400 648.0000 ;
    END
  END t_s[599]
  PIN t_s[59]
    DIRECTION OUTPUT ;
    USE SIGNAL ;
    PORT
      LAYER M5 ;
        RECT 61.0080 647.9160 61.0320 648.0000 ;
    END
  END t_s[59]
  PIN t_s[5]
    DIRECTION OUTPUT ;
    USE SIGNAL ;
    PORT
      LAYER M5 ;
        RECT 44.8320 647.9160 44.8560 648.0000 ;
    END
  END t_s[5]
  PIN t_s[600]
    DIRECTION OUTPUT ;
    USE SIGNAL ;
    PORT
      LAYER M3 ;
        RECT 223.1280 647.9620 223.1460 648.0000 ;
    END
  END t_s[600]
  PIN t_s[601]
    DIRECTION OUTPUT ;
    USE SIGNAL ;
    PORT
      LAYER M5 ;
        RECT 223.4400 647.9160 223.4640 648.0000 ;
    END
  END t_s[601]
  PIN t_s[602]
    DIRECTION OUTPUT ;
    USE SIGNAL ;
    PORT
      LAYER M3 ;
        RECT 223.7400 647.9620 223.7580 648.0000 ;
    END
  END t_s[602]
  PIN t_s[603]
    DIRECTION OUTPUT ;
    USE SIGNAL ;
    PORT
      LAYER M5 ;
        RECT 224.0160 647.9160 224.0400 648.0000 ;
    END
  END t_s[603]
  PIN t_s[604]
    DIRECTION OUTPUT ;
    USE SIGNAL ;
    PORT
      LAYER M3 ;
        RECT 224.3160 647.9620 224.3340 648.0000 ;
    END
  END t_s[604]
  PIN t_s[605]
    DIRECTION OUTPUT ;
    USE SIGNAL ;
    PORT
      LAYER M5 ;
        RECT 224.6400 647.9160 224.6640 648.0000 ;
    END
  END t_s[605]
  PIN t_s[606]
    DIRECTION OUTPUT ;
    USE SIGNAL ;
    PORT
      LAYER M3 ;
        RECT 224.9280 647.9620 224.9460 648.0000 ;
    END
  END t_s[606]
  PIN t_s[607]
    DIRECTION OUTPUT ;
    USE SIGNAL ;
    PORT
      LAYER M5 ;
        RECT 225.2160 647.9160 225.2400 648.0000 ;
    END
  END t_s[607]
  PIN t_s[608]
    DIRECTION OUTPUT ;
    USE SIGNAL ;
    PORT
      LAYER M3 ;
        RECT 225.5400 647.9620 225.5580 648.0000 ;
    END
  END t_s[608]
  PIN t_s[609]
    DIRECTION OUTPUT ;
    USE SIGNAL ;
    PORT
      LAYER M5 ;
        RECT 225.8400 647.9160 225.8640 648.0000 ;
    END
  END t_s[609]
  PIN t_s[60]
    DIRECTION OUTPUT ;
    USE SIGNAL ;
    PORT
      LAYER M3 ;
        RECT 61.3080 647.9620 61.3260 648.0000 ;
    END
  END t_s[60]
  PIN t_s[610]
    DIRECTION OUTPUT ;
    USE SIGNAL ;
    PORT
      LAYER M3 ;
        RECT 226.1160 647.9620 226.1340 648.0000 ;
    END
  END t_s[610]
  PIN t_s[611]
    DIRECTION OUTPUT ;
    USE SIGNAL ;
    PORT
      LAYER M5 ;
        RECT 226.4160 647.9160 226.4400 648.0000 ;
    END
  END t_s[611]
  PIN t_s[612]
    DIRECTION OUTPUT ;
    USE SIGNAL ;
    PORT
      LAYER M3 ;
        RECT 226.7280 647.9620 226.7460 648.0000 ;
    END
  END t_s[612]
  PIN t_s[613]
    DIRECTION OUTPUT ;
    USE SIGNAL ;
    PORT
      LAYER M5 ;
        RECT 227.0400 647.9160 227.0640 648.0000 ;
    END
  END t_s[613]
  PIN t_s[614]
    DIRECTION OUTPUT ;
    USE SIGNAL ;
    PORT
      LAYER M3 ;
        RECT 227.3400 647.9620 227.3580 648.0000 ;
    END
  END t_s[614]
  PIN t_s[615]
    DIRECTION OUTPUT ;
    USE SIGNAL ;
    PORT
      LAYER M5 ;
        RECT 227.6160 647.9160 227.6400 648.0000 ;
    END
  END t_s[615]
  PIN t_s[616]
    DIRECTION OUTPUT ;
    USE SIGNAL ;
    PORT
      LAYER M3 ;
        RECT 227.9160 647.9620 227.9340 648.0000 ;
    END
  END t_s[616]
  PIN t_s[617]
    DIRECTION OUTPUT ;
    USE SIGNAL ;
    PORT
      LAYER M5 ;
        RECT 228.2400 647.9160 228.2640 648.0000 ;
    END
  END t_s[617]
  PIN t_s[618]
    DIRECTION OUTPUT ;
    USE SIGNAL ;
    PORT
      LAYER M3 ;
        RECT 228.5280 647.9620 228.5460 648.0000 ;
    END
  END t_s[618]
  PIN t_s[619]
    DIRECTION OUTPUT ;
    USE SIGNAL ;
    PORT
      LAYER M5 ;
        RECT 228.8160 647.9160 228.8400 648.0000 ;
    END
  END t_s[619]
  PIN t_s[61]
    DIRECTION OUTPUT ;
    USE SIGNAL ;
    PORT
      LAYER M5 ;
        RECT 61.6320 647.9160 61.6560 648.0000 ;
    END
  END t_s[61]
  PIN t_s[620]
    DIRECTION OUTPUT ;
    USE SIGNAL ;
    PORT
      LAYER M3 ;
        RECT 229.1400 647.9620 229.1580 648.0000 ;
    END
  END t_s[620]
  PIN t_s[621]
    DIRECTION OUTPUT ;
    USE SIGNAL ;
    PORT
      LAYER M5 ;
        RECT 229.4400 647.9160 229.4640 648.0000 ;
    END
  END t_s[621]
  PIN t_s[622]
    DIRECTION OUTPUT ;
    USE SIGNAL ;
    PORT
      LAYER M3 ;
        RECT 229.7160 647.9620 229.7340 648.0000 ;
    END
  END t_s[622]
  PIN t_s[623]
    DIRECTION OUTPUT ;
    USE SIGNAL ;
    PORT
      LAYER M5 ;
        RECT 230.0160 647.9160 230.0400 648.0000 ;
    END
  END t_s[623]
  PIN t_s[624]
    DIRECTION OUTPUT ;
    USE SIGNAL ;
    PORT
      LAYER M3 ;
        RECT 230.3280 647.9620 230.3460 648.0000 ;
    END
  END t_s[624]
  PIN t_s[625]
    DIRECTION OUTPUT ;
    USE SIGNAL ;
    PORT
      LAYER M5 ;
        RECT 230.6400 647.9160 230.6640 648.0000 ;
    END
  END t_s[625]
  PIN t_s[626]
    DIRECTION OUTPUT ;
    USE SIGNAL ;
    PORT
      LAYER M3 ;
        RECT 230.9400 647.9620 230.9580 648.0000 ;
    END
  END t_s[626]
  PIN t_s[627]
    DIRECTION OUTPUT ;
    USE SIGNAL ;
    PORT
      LAYER M5 ;
        RECT 231.2160 647.9160 231.2400 648.0000 ;
    END
  END t_s[627]
  PIN t_s[628]
    DIRECTION OUTPUT ;
    USE SIGNAL ;
    PORT
      LAYER M3 ;
        RECT 231.5160 647.9620 231.5340 648.0000 ;
    END
  END t_s[628]
  PIN t_s[629]
    DIRECTION OUTPUT ;
    USE SIGNAL ;
    PORT
      LAYER M5 ;
        RECT 231.8400 647.9160 231.8640 648.0000 ;
    END
  END t_s[629]
  PIN t_s[62]
    DIRECTION OUTPUT ;
    USE SIGNAL ;
    PORT
      LAYER M3 ;
        RECT 61.9200 647.9620 61.9380 648.0000 ;
    END
  END t_s[62]
  PIN t_s[630]
    DIRECTION OUTPUT ;
    USE SIGNAL ;
    PORT
      LAYER M3 ;
        RECT 232.1280 647.9620 232.1460 648.0000 ;
    END
  END t_s[630]
  PIN t_s[631]
    DIRECTION OUTPUT ;
    USE SIGNAL ;
    PORT
      LAYER M5 ;
        RECT 232.4160 647.9160 232.4400 648.0000 ;
    END
  END t_s[631]
  PIN t_s[632]
    DIRECTION OUTPUT ;
    USE SIGNAL ;
    PORT
      LAYER M3 ;
        RECT 232.7400 647.9620 232.7580 648.0000 ;
    END
  END t_s[632]
  PIN t_s[633]
    DIRECTION OUTPUT ;
    USE SIGNAL ;
    PORT
      LAYER M5 ;
        RECT 233.0400 647.9160 233.0640 648.0000 ;
    END
  END t_s[633]
  PIN t_s[634]
    DIRECTION OUTPUT ;
    USE SIGNAL ;
    PORT
      LAYER M3 ;
        RECT 233.3160 647.9620 233.3340 648.0000 ;
    END
  END t_s[634]
  PIN t_s[635]
    DIRECTION OUTPUT ;
    USE SIGNAL ;
    PORT
      LAYER M5 ;
        RECT 233.6160 647.9160 233.6400 648.0000 ;
    END
  END t_s[635]
  PIN t_s[636]
    DIRECTION OUTPUT ;
    USE SIGNAL ;
    PORT
      LAYER M3 ;
        RECT 233.9280 647.9620 233.9460 648.0000 ;
    END
  END t_s[636]
  PIN t_s[637]
    DIRECTION OUTPUT ;
    USE SIGNAL ;
    PORT
      LAYER M5 ;
        RECT 234.2400 647.9160 234.2640 648.0000 ;
    END
  END t_s[637]
  PIN t_s[638]
    DIRECTION OUTPUT ;
    USE SIGNAL ;
    PORT
      LAYER M3 ;
        RECT 234.5040 647.9620 234.5220 648.0000 ;
    END
  END t_s[638]
  PIN t_s[639]
    DIRECTION OUTPUT ;
    USE SIGNAL ;
    PORT
      LAYER M5 ;
        RECT 234.8160 647.9160 234.8400 648.0000 ;
    END
  END t_s[639]
  PIN t_s[63]
    DIRECTION OUTPUT ;
    USE SIGNAL ;
    PORT
      LAYER M5 ;
        RECT 62.2080 647.9160 62.2320 648.0000 ;
    END
  END t_s[63]
  PIN t_s[640]
    DIRECTION OUTPUT ;
    USE SIGNAL ;
    PORT
      LAYER M3 ;
        RECT 235.1160 647.9620 235.1340 648.0000 ;
    END
  END t_s[640]
  PIN t_s[641]
    DIRECTION OUTPUT ;
    USE SIGNAL ;
    PORT
      LAYER M5 ;
        RECT 235.4400 647.9160 235.4640 648.0000 ;
    END
  END t_s[641]
  PIN t_s[642]
    DIRECTION OUTPUT ;
    USE SIGNAL ;
    PORT
      LAYER M3 ;
        RECT 235.7280 647.9620 235.7460 648.0000 ;
    END
  END t_s[642]
  PIN t_s[643]
    DIRECTION OUTPUT ;
    USE SIGNAL ;
    PORT
      LAYER M5 ;
        RECT 236.0160 647.9160 236.0400 648.0000 ;
    END
  END t_s[643]
  PIN t_s[644]
    DIRECTION OUTPUT ;
    USE SIGNAL ;
    PORT
      LAYER M3 ;
        RECT 236.3040 647.9620 236.3220 648.0000 ;
    END
  END t_s[644]
  PIN t_s[645]
    DIRECTION OUTPUT ;
    USE SIGNAL ;
    PORT
      LAYER M5 ;
        RECT 236.5920 647.9160 236.6160 648.0000 ;
    END
  END t_s[645]
  PIN t_s[646]
    DIRECTION OUTPUT ;
    USE SIGNAL ;
    PORT
      LAYER M3 ;
        RECT 236.9160 647.9620 236.9340 648.0000 ;
    END
  END t_s[646]
  PIN t_s[647]
    DIRECTION OUTPUT ;
    USE SIGNAL ;
    PORT
      LAYER M5 ;
        RECT 237.2160 647.9160 237.2400 648.0000 ;
    END
  END t_s[647]
  PIN t_s[648]
    DIRECTION OUTPUT ;
    USE SIGNAL ;
    PORT
      LAYER M3 ;
        RECT 237.5280 647.9620 237.5460 648.0000 ;
    END
  END t_s[648]
  PIN t_s[649]
    DIRECTION OUTPUT ;
    USE SIGNAL ;
    PORT
      LAYER M5 ;
        RECT 237.7920 647.9160 237.8160 648.0000 ;
    END
  END t_s[649]
  PIN t_s[64]
    DIRECTION OUTPUT ;
    USE SIGNAL ;
    PORT
      LAYER M3 ;
        RECT 62.5320 647.9620 62.5500 648.0000 ;
    END
  END t_s[64]
  PIN t_s[650]
    DIRECTION OUTPUT ;
    USE SIGNAL ;
    PORT
      LAYER M3 ;
        RECT 238.1040 647.9620 238.1220 648.0000 ;
    END
  END t_s[650]
  PIN t_s[651]
    DIRECTION OUTPUT ;
    USE SIGNAL ;
    PORT
      LAYER M5 ;
        RECT 238.4160 647.9160 238.4400 648.0000 ;
    END
  END t_s[651]
  PIN t_s[652]
    DIRECTION OUTPUT ;
    USE SIGNAL ;
    PORT
      LAYER M3 ;
        RECT 238.7160 647.9620 238.7340 648.0000 ;
    END
  END t_s[652]
  PIN t_s[653]
    DIRECTION OUTPUT ;
    USE SIGNAL ;
    PORT
      LAYER M5 ;
        RECT 238.9920 647.9160 239.0160 648.0000 ;
    END
  END t_s[653]
  PIN t_s[654]
    DIRECTION OUTPUT ;
    USE SIGNAL ;
    PORT
      LAYER M3 ;
        RECT 239.3280 647.9620 239.3460 648.0000 ;
    END
  END t_s[654]
  PIN t_s[655]
    DIRECTION OUTPUT ;
    USE SIGNAL ;
    PORT
      LAYER M5 ;
        RECT 239.6160 647.9160 239.6400 648.0000 ;
    END
  END t_s[655]
  PIN t_s[656]
    DIRECTION OUTPUT ;
    USE SIGNAL ;
    PORT
      LAYER M3 ;
        RECT 239.9040 647.9620 239.9220 648.0000 ;
    END
  END t_s[656]
  PIN t_s[657]
    DIRECTION OUTPUT ;
    USE SIGNAL ;
    PORT
      LAYER M5 ;
        RECT 240.1920 647.9160 240.2160 648.0000 ;
    END
  END t_s[657]
  PIN t_s[658]
    DIRECTION OUTPUT ;
    USE SIGNAL ;
    PORT
      LAYER M3 ;
        RECT 240.5160 647.9620 240.5340 648.0000 ;
    END
  END t_s[658]
  PIN t_s[659]
    DIRECTION OUTPUT ;
    USE SIGNAL ;
    PORT
      LAYER M5 ;
        RECT 240.8160 647.9160 240.8400 648.0000 ;
    END
  END t_s[659]
  PIN t_s[65]
    DIRECTION OUTPUT ;
    USE SIGNAL ;
    PORT
      LAYER M5 ;
        RECT 62.8320 647.9160 62.8560 648.0000 ;
    END
  END t_s[65]
  PIN t_s[660]
    DIRECTION OUTPUT ;
    USE SIGNAL ;
    PORT
      LAYER M3 ;
        RECT 241.1280 647.9620 241.1460 648.0000 ;
    END
  END t_s[660]
  PIN t_s[661]
    DIRECTION OUTPUT ;
    USE SIGNAL ;
    PORT
      LAYER M5 ;
        RECT 241.3920 647.9160 241.4160 648.0000 ;
    END
  END t_s[661]
  PIN t_s[662]
    DIRECTION OUTPUT ;
    USE SIGNAL ;
    PORT
      LAYER M3 ;
        RECT 241.7040 647.9620 241.7220 648.0000 ;
    END
  END t_s[662]
  PIN t_s[663]
    DIRECTION OUTPUT ;
    USE SIGNAL ;
    PORT
      LAYER M5 ;
        RECT 242.0160 647.9160 242.0400 648.0000 ;
    END
  END t_s[663]
  PIN t_s[664]
    DIRECTION OUTPUT ;
    USE SIGNAL ;
    PORT
      LAYER M3 ;
        RECT 242.3160 647.9620 242.3340 648.0000 ;
    END
  END t_s[664]
  PIN t_s[665]
    DIRECTION OUTPUT ;
    USE SIGNAL ;
    PORT
      LAYER M5 ;
        RECT 242.5920 647.9160 242.6160 648.0000 ;
    END
  END t_s[665]
  PIN t_s[666]
    DIRECTION OUTPUT ;
    USE SIGNAL ;
    PORT
      LAYER M3 ;
        RECT 242.9280 647.9620 242.9460 648.0000 ;
    END
  END t_s[666]
  PIN t_s[667]
    DIRECTION OUTPUT ;
    USE SIGNAL ;
    PORT
      LAYER M5 ;
        RECT 243.2160 647.9160 243.2400 648.0000 ;
    END
  END t_s[667]
  PIN t_s[668]
    DIRECTION OUTPUT ;
    USE SIGNAL ;
    PORT
      LAYER M3 ;
        RECT 243.5040 647.9620 243.5220 648.0000 ;
    END
  END t_s[668]
  PIN t_s[669]
    DIRECTION OUTPUT ;
    USE SIGNAL ;
    PORT
      LAYER M5 ;
        RECT 243.7920 647.9160 243.8160 648.0000 ;
    END
  END t_s[669]
  PIN t_s[66]
    DIRECTION OUTPUT ;
    USE SIGNAL ;
    PORT
      LAYER M3 ;
        RECT 63.1080 647.9620 63.1260 648.0000 ;
    END
  END t_s[66]
  PIN t_s[670]
    DIRECTION OUTPUT ;
    USE SIGNAL ;
    PORT
      LAYER M3 ;
        RECT 244.1160 647.9620 244.1340 648.0000 ;
    END
  END t_s[670]
  PIN t_s[671]
    DIRECTION OUTPUT ;
    USE SIGNAL ;
    PORT
      LAYER M5 ;
        RECT 244.4160 647.9160 244.4400 648.0000 ;
    END
  END t_s[671]
  PIN t_s[672]
    DIRECTION OUTPUT ;
    USE SIGNAL ;
    PORT
      LAYER M3 ;
        RECT 244.6920 647.9620 244.7100 648.0000 ;
    END
  END t_s[672]
  PIN t_s[673]
    DIRECTION OUTPUT ;
    USE SIGNAL ;
    PORT
      LAYER M5 ;
        RECT 244.9920 647.9160 245.0160 648.0000 ;
    END
  END t_s[673]
  PIN t_s[674]
    DIRECTION OUTPUT ;
    USE SIGNAL ;
    PORT
      LAYER M3 ;
        RECT 245.3040 647.9620 245.3220 648.0000 ;
    END
  END t_s[674]
  PIN t_s[675]
    DIRECTION OUTPUT ;
    USE SIGNAL ;
    PORT
      LAYER M5 ;
        RECT 245.6160 647.9160 245.6400 648.0000 ;
    END
  END t_s[675]
  PIN t_s[676]
    DIRECTION OUTPUT ;
    USE SIGNAL ;
    PORT
      LAYER M3 ;
        RECT 245.9160 647.9620 245.9340 648.0000 ;
    END
  END t_s[676]
  PIN t_s[677]
    DIRECTION OUTPUT ;
    USE SIGNAL ;
    PORT
      LAYER M5 ;
        RECT 246.1920 647.9160 246.2160 648.0000 ;
    END
  END t_s[677]
  PIN t_s[678]
    DIRECTION OUTPUT ;
    USE SIGNAL ;
    PORT
      LAYER M3 ;
        RECT 246.4920 647.9620 246.5100 648.0000 ;
    END
  END t_s[678]
  PIN t_s[679]
    DIRECTION OUTPUT ;
    USE SIGNAL ;
    PORT
      LAYER M5 ;
        RECT 246.8160 647.9160 246.8400 648.0000 ;
    END
  END t_s[679]
  PIN t_s[67]
    DIRECTION OUTPUT ;
    USE SIGNAL ;
    PORT
      LAYER M5 ;
        RECT 63.4080 647.9160 63.4320 648.0000 ;
    END
  END t_s[67]
  PIN t_s[680]
    DIRECTION OUTPUT ;
    USE SIGNAL ;
    PORT
      LAYER M3 ;
        RECT 247.1040 647.9620 247.1220 648.0000 ;
    END
  END t_s[680]
  PIN t_s[681]
    DIRECTION OUTPUT ;
    USE SIGNAL ;
    PORT
      LAYER M5 ;
        RECT 247.3920 647.9160 247.4160 648.0000 ;
    END
  END t_s[681]
  PIN t_s[682]
    DIRECTION OUTPUT ;
    USE SIGNAL ;
    PORT
      LAYER M3 ;
        RECT 247.7160 647.9620 247.7340 648.0000 ;
    END
  END t_s[682]
  PIN t_s[683]
    DIRECTION OUTPUT ;
    USE SIGNAL ;
    PORT
      LAYER M5 ;
        RECT 248.0160 647.9160 248.0400 648.0000 ;
    END
  END t_s[683]
  PIN t_s[684]
    DIRECTION OUTPUT ;
    USE SIGNAL ;
    PORT
      LAYER M3 ;
        RECT 248.2920 647.9620 248.3100 648.0000 ;
    END
  END t_s[684]
  PIN t_s[685]
    DIRECTION OUTPUT ;
    USE SIGNAL ;
    PORT
      LAYER M5 ;
        RECT 248.5920 647.9160 248.6160 648.0000 ;
    END
  END t_s[685]
  PIN t_s[686]
    DIRECTION OUTPUT ;
    USE SIGNAL ;
    PORT
      LAYER M3 ;
        RECT 248.9040 647.9620 248.9220 648.0000 ;
    END
  END t_s[686]
  PIN t_s[687]
    DIRECTION OUTPUT ;
    USE SIGNAL ;
    PORT
      LAYER M5 ;
        RECT 249.2160 647.9160 249.2400 648.0000 ;
    END
  END t_s[687]
  PIN t_s[688]
    DIRECTION OUTPUT ;
    USE SIGNAL ;
    PORT
      LAYER M3 ;
        RECT 249.5160 647.9620 249.5340 648.0000 ;
    END
  END t_s[688]
  PIN t_s[689]
    DIRECTION OUTPUT ;
    USE SIGNAL ;
    PORT
      LAYER M5 ;
        RECT 249.7920 647.9160 249.8160 648.0000 ;
    END
  END t_s[689]
  PIN t_s[68]
    DIRECTION OUTPUT ;
    USE SIGNAL ;
    PORT
      LAYER M3 ;
        RECT 63.7200 647.9620 63.7380 648.0000 ;
    END
  END t_s[68]
  PIN t_s[690]
    DIRECTION OUTPUT ;
    USE SIGNAL ;
    PORT
      LAYER M3 ;
        RECT 250.0920 647.9620 250.1100 648.0000 ;
    END
  END t_s[690]
  PIN t_s[691]
    DIRECTION OUTPUT ;
    USE SIGNAL ;
    PORT
      LAYER M5 ;
        RECT 250.4160 647.9160 250.4400 648.0000 ;
    END
  END t_s[691]
  PIN t_s[692]
    DIRECTION OUTPUT ;
    USE SIGNAL ;
    PORT
      LAYER M3 ;
        RECT 250.7040 647.9620 250.7220 648.0000 ;
    END
  END t_s[692]
  PIN t_s[693]
    DIRECTION OUTPUT ;
    USE SIGNAL ;
    PORT
      LAYER M5 ;
        RECT 250.9920 647.9160 251.0160 648.0000 ;
    END
  END t_s[693]
  PIN t_s[694]
    DIRECTION OUTPUT ;
    USE SIGNAL ;
    PORT
      LAYER M3 ;
        RECT 251.3160 647.9620 251.3340 648.0000 ;
    END
  END t_s[694]
  PIN t_s[695]
    DIRECTION OUTPUT ;
    USE SIGNAL ;
    PORT
      LAYER M5 ;
        RECT 251.6160 647.9160 251.6400 648.0000 ;
    END
  END t_s[695]
  PIN t_s[696]
    DIRECTION OUTPUT ;
    USE SIGNAL ;
    PORT
      LAYER M3 ;
        RECT 251.8920 647.9620 251.9100 648.0000 ;
    END
  END t_s[696]
  PIN t_s[697]
    DIRECTION OUTPUT ;
    USE SIGNAL ;
    PORT
      LAYER M5 ;
        RECT 252.1920 647.9160 252.2160 648.0000 ;
    END
  END t_s[697]
  PIN t_s[698]
    DIRECTION OUTPUT ;
    USE SIGNAL ;
    PORT
      LAYER M3 ;
        RECT 252.5040 647.9620 252.5220 648.0000 ;
    END
  END t_s[698]
  PIN t_s[699]
    DIRECTION OUTPUT ;
    USE SIGNAL ;
    PORT
      LAYER M5 ;
        RECT 252.8160 647.9160 252.8400 648.0000 ;
    END
  END t_s[699]
  PIN t_s[69]
    DIRECTION OUTPUT ;
    USE SIGNAL ;
    PORT
      LAYER M5 ;
        RECT 64.0320 647.9160 64.0560 648.0000 ;
    END
  END t_s[69]
  PIN t_s[6]
    DIRECTION OUTPUT ;
    USE SIGNAL ;
    PORT
      LAYER M3 ;
        RECT 45.1440 647.9620 45.1620 648.0000 ;
    END
  END t_s[6]
  PIN t_s[700]
    DIRECTION OUTPUT ;
    USE SIGNAL ;
    PORT
      LAYER M3 ;
        RECT 253.1160 647.9620 253.1340 648.0000 ;
    END
  END t_s[700]
  PIN t_s[701]
    DIRECTION OUTPUT ;
    USE SIGNAL ;
    PORT
      LAYER M5 ;
        RECT 253.3920 647.9160 253.4160 648.0000 ;
    END
  END t_s[701]
  PIN t_s[702]
    DIRECTION OUTPUT ;
    USE SIGNAL ;
    PORT
      LAYER M3 ;
        RECT 253.6920 647.9620 253.7100 648.0000 ;
    END
  END t_s[702]
  PIN t_s[703]
    DIRECTION OUTPUT ;
    USE SIGNAL ;
    PORT
      LAYER M5 ;
        RECT 254.0160 647.9160 254.0400 648.0000 ;
    END
  END t_s[703]
  PIN t_s[704]
    DIRECTION OUTPUT ;
    USE SIGNAL ;
    PORT
      LAYER M3 ;
        RECT 254.3040 647.9620 254.3220 648.0000 ;
    END
  END t_s[704]
  PIN t_s[705]
    DIRECTION OUTPUT ;
    USE SIGNAL ;
    PORT
      LAYER M5 ;
        RECT 254.5920 647.9160 254.6160 648.0000 ;
    END
  END t_s[705]
  PIN t_s[706]
    DIRECTION OUTPUT ;
    USE SIGNAL ;
    PORT
      LAYER M3 ;
        RECT 254.8800 647.9620 254.8980 648.0000 ;
    END
  END t_s[706]
  PIN t_s[707]
    DIRECTION OUTPUT ;
    USE SIGNAL ;
    PORT
      LAYER M5 ;
        RECT 255.2160 647.9160 255.2400 648.0000 ;
    END
  END t_s[707]
  PIN t_s[708]
    DIRECTION OUTPUT ;
    USE SIGNAL ;
    PORT
      LAYER M3 ;
        RECT 255.4920 647.9620 255.5100 648.0000 ;
    END
  END t_s[708]
  PIN t_s[709]
    DIRECTION OUTPUT ;
    USE SIGNAL ;
    PORT
      LAYER M5 ;
        RECT 255.7920 647.9160 255.8160 648.0000 ;
    END
  END t_s[709]
  PIN t_s[70]
    DIRECTION OUTPUT ;
    USE SIGNAL ;
    PORT
      LAYER M3 ;
        RECT 64.3320 647.9620 64.3500 648.0000 ;
    END
  END t_s[70]
  PIN t_s[710]
    DIRECTION OUTPUT ;
    USE SIGNAL ;
    PORT
      LAYER M3 ;
        RECT 256.1040 647.9620 256.1220 648.0000 ;
    END
  END t_s[710]
  PIN t_s[711]
    DIRECTION OUTPUT ;
    USE SIGNAL ;
    PORT
      LAYER M5 ;
        RECT 256.3680 647.9160 256.3920 648.0000 ;
    END
  END t_s[711]
  PIN t_s[712]
    DIRECTION OUTPUT ;
    USE SIGNAL ;
    PORT
      LAYER M3 ;
        RECT 256.6800 647.9620 256.6980 648.0000 ;
    END
  END t_s[712]
  PIN t_s[713]
    DIRECTION OUTPUT ;
    USE SIGNAL ;
    PORT
      LAYER M5 ;
        RECT 256.9920 647.9160 257.0160 648.0000 ;
    END
  END t_s[713]
  PIN t_s[714]
    DIRECTION OUTPUT ;
    USE SIGNAL ;
    PORT
      LAYER M3 ;
        RECT 257.2920 647.9620 257.3100 648.0000 ;
    END
  END t_s[714]
  PIN t_s[715]
    DIRECTION OUTPUT ;
    USE SIGNAL ;
    PORT
      LAYER M5 ;
        RECT 257.5680 647.9160 257.5920 648.0000 ;
    END
  END t_s[715]
  PIN t_s[716]
    DIRECTION OUTPUT ;
    USE SIGNAL ;
    PORT
      LAYER M3 ;
        RECT 257.9040 647.9620 257.9220 648.0000 ;
    END
  END t_s[716]
  PIN t_s[717]
    DIRECTION OUTPUT ;
    USE SIGNAL ;
    PORT
      LAYER M5 ;
        RECT 258.1920 647.9160 258.2160 648.0000 ;
    END
  END t_s[717]
  PIN t_s[718]
    DIRECTION OUTPUT ;
    USE SIGNAL ;
    PORT
      LAYER M3 ;
        RECT 258.4800 647.9620 258.4980 648.0000 ;
    END
  END t_s[718]
  PIN t_s[719]
    DIRECTION OUTPUT ;
    USE SIGNAL ;
    PORT
      LAYER M5 ;
        RECT 258.7680 647.9160 258.7920 648.0000 ;
    END
  END t_s[719]
  PIN t_s[71]
    DIRECTION OUTPUT ;
    USE SIGNAL ;
    PORT
      LAYER M5 ;
        RECT 64.6080 647.9160 64.6320 648.0000 ;
    END
  END t_s[71]
  PIN t_s[720]
    DIRECTION OUTPUT ;
    USE SIGNAL ;
    PORT
      LAYER M3 ;
        RECT 259.0920 647.9620 259.1100 648.0000 ;
    END
  END t_s[720]
  PIN t_s[721]
    DIRECTION OUTPUT ;
    USE SIGNAL ;
    PORT
      LAYER M5 ;
        RECT 259.3920 647.9160 259.4160 648.0000 ;
    END
  END t_s[721]
  PIN t_s[722]
    DIRECTION OUTPUT ;
    USE SIGNAL ;
    PORT
      LAYER M3 ;
        RECT 259.7040 647.9620 259.7220 648.0000 ;
    END
  END t_s[722]
  PIN t_s[723]
    DIRECTION OUTPUT ;
    USE SIGNAL ;
    PORT
      LAYER M5 ;
        RECT 259.9680 647.9160 259.9920 648.0000 ;
    END
  END t_s[723]
  PIN t_s[724]
    DIRECTION OUTPUT ;
    USE SIGNAL ;
    PORT
      LAYER M3 ;
        RECT 260.2800 647.9620 260.2980 648.0000 ;
    END
  END t_s[724]
  PIN t_s[725]
    DIRECTION OUTPUT ;
    USE SIGNAL ;
    PORT
      LAYER M5 ;
        RECT 260.5920 647.9160 260.6160 648.0000 ;
    END
  END t_s[725]
  PIN t_s[726]
    DIRECTION OUTPUT ;
    USE SIGNAL ;
    PORT
      LAYER M3 ;
        RECT 260.8920 647.9620 260.9100 648.0000 ;
    END
  END t_s[726]
  PIN t_s[727]
    DIRECTION OUTPUT ;
    USE SIGNAL ;
    PORT
      LAYER M5 ;
        RECT 261.1680 647.9160 261.1920 648.0000 ;
    END
  END t_s[727]
  PIN t_s[728]
    DIRECTION OUTPUT ;
    USE SIGNAL ;
    PORT
      LAYER M3 ;
        RECT 261.5040 647.9620 261.5220 648.0000 ;
    END
  END t_s[728]
  PIN t_s[729]
    DIRECTION OUTPUT ;
    USE SIGNAL ;
    PORT
      LAYER M5 ;
        RECT 261.7920 647.9160 261.8160 648.0000 ;
    END
  END t_s[729]
  PIN t_s[72]
    DIRECTION OUTPUT ;
    USE SIGNAL ;
    PORT
      LAYER M3 ;
        RECT 64.9080 647.9620 64.9260 648.0000 ;
    END
  END t_s[72]
  PIN t_s[730]
    DIRECTION OUTPUT ;
    USE SIGNAL ;
    PORT
      LAYER M3 ;
        RECT 262.0800 647.9620 262.0980 648.0000 ;
    END
  END t_s[730]
  PIN t_s[731]
    DIRECTION OUTPUT ;
    USE SIGNAL ;
    PORT
      LAYER M5 ;
        RECT 262.3680 647.9160 262.3920 648.0000 ;
    END
  END t_s[731]
  PIN t_s[732]
    DIRECTION OUTPUT ;
    USE SIGNAL ;
    PORT
      LAYER M3 ;
        RECT 262.6920 647.9620 262.7100 648.0000 ;
    END
  END t_s[732]
  PIN t_s[733]
    DIRECTION OUTPUT ;
    USE SIGNAL ;
    PORT
      LAYER M5 ;
        RECT 262.9920 647.9160 263.0160 648.0000 ;
    END
  END t_s[733]
  PIN t_s[734]
    DIRECTION OUTPUT ;
    USE SIGNAL ;
    PORT
      LAYER M3 ;
        RECT 263.3040 647.9620 263.3220 648.0000 ;
    END
  END t_s[734]
  PIN t_s[735]
    DIRECTION OUTPUT ;
    USE SIGNAL ;
    PORT
      LAYER M5 ;
        RECT 263.5680 647.9160 263.5920 648.0000 ;
    END
  END t_s[735]
  PIN t_s[736]
    DIRECTION OUTPUT ;
    USE SIGNAL ;
    PORT
      LAYER M3 ;
        RECT 263.8800 647.9620 263.8980 648.0000 ;
    END
  END t_s[736]
  PIN t_s[737]
    DIRECTION OUTPUT ;
    USE SIGNAL ;
    PORT
      LAYER M5 ;
        RECT 264.1920 647.9160 264.2160 648.0000 ;
    END
  END t_s[737]
  PIN t_s[738]
    DIRECTION OUTPUT ;
    USE SIGNAL ;
    PORT
      LAYER M3 ;
        RECT 264.4920 647.9620 264.5100 648.0000 ;
    END
  END t_s[738]
  PIN t_s[739]
    DIRECTION OUTPUT ;
    USE SIGNAL ;
    PORT
      LAYER M5 ;
        RECT 264.7680 647.9160 264.7920 648.0000 ;
    END
  END t_s[739]
  PIN t_s[73]
    DIRECTION OUTPUT ;
    USE SIGNAL ;
    PORT
      LAYER M5 ;
        RECT 65.2320 647.9160 65.2560 648.0000 ;
    END
  END t_s[73]
  PIN t_s[740]
    DIRECTION OUTPUT ;
    USE SIGNAL ;
    PORT
      LAYER M3 ;
        RECT 265.0680 647.9620 265.0860 648.0000 ;
    END
  END t_s[740]
  PIN t_s[741]
    DIRECTION OUTPUT ;
    USE SIGNAL ;
    PORT
      LAYER M5 ;
        RECT 265.3920 647.9160 265.4160 648.0000 ;
    END
  END t_s[741]
  PIN t_s[742]
    DIRECTION OUTPUT ;
    USE SIGNAL ;
    PORT
      LAYER M3 ;
        RECT 265.6800 647.9620 265.6980 648.0000 ;
    END
  END t_s[742]
  PIN t_s[743]
    DIRECTION OUTPUT ;
    USE SIGNAL ;
    PORT
      LAYER M5 ;
        RECT 265.9680 647.9160 265.9920 648.0000 ;
    END
  END t_s[743]
  PIN t_s[744]
    DIRECTION OUTPUT ;
    USE SIGNAL ;
    PORT
      LAYER M3 ;
        RECT 266.2920 647.9620 266.3100 648.0000 ;
    END
  END t_s[744]
  PIN t_s[745]
    DIRECTION OUTPUT ;
    USE SIGNAL ;
    PORT
      LAYER M5 ;
        RECT 266.5920 647.9160 266.6160 648.0000 ;
    END
  END t_s[745]
  PIN t_s[746]
    DIRECTION OUTPUT ;
    USE SIGNAL ;
    PORT
      LAYER M3 ;
        RECT 266.8680 647.9620 266.8860 648.0000 ;
    END
  END t_s[746]
  PIN t_s[747]
    DIRECTION OUTPUT ;
    USE SIGNAL ;
    PORT
      LAYER M5 ;
        RECT 267.1680 647.9160 267.1920 648.0000 ;
    END
  END t_s[747]
  PIN t_s[748]
    DIRECTION OUTPUT ;
    USE SIGNAL ;
    PORT
      LAYER M3 ;
        RECT 267.4800 647.9620 267.4980 648.0000 ;
    END
  END t_s[748]
  PIN t_s[749]
    DIRECTION OUTPUT ;
    USE SIGNAL ;
    PORT
      LAYER M5 ;
        RECT 267.7920 647.9160 267.8160 648.0000 ;
    END
  END t_s[749]
  PIN t_s[74]
    DIRECTION OUTPUT ;
    USE SIGNAL ;
    PORT
      LAYER M3 ;
        RECT 65.5200 647.9620 65.5380 648.0000 ;
    END
  END t_s[74]
  PIN t_s[750]
    DIRECTION OUTPUT ;
    USE SIGNAL ;
    PORT
      LAYER M3 ;
        RECT 268.0920 647.9620 268.1100 648.0000 ;
    END
  END t_s[750]
  PIN t_s[751]
    DIRECTION OUTPUT ;
    USE SIGNAL ;
    PORT
      LAYER M5 ;
        RECT 268.3680 647.9160 268.3920 648.0000 ;
    END
  END t_s[751]
  PIN t_s[752]
    DIRECTION OUTPUT ;
    USE SIGNAL ;
    PORT
      LAYER M3 ;
        RECT 268.6680 647.9620 268.6860 648.0000 ;
    END
  END t_s[752]
  PIN t_s[753]
    DIRECTION OUTPUT ;
    USE SIGNAL ;
    PORT
      LAYER M5 ;
        RECT 268.9920 647.9160 269.0160 648.0000 ;
    END
  END t_s[753]
  PIN t_s[754]
    DIRECTION OUTPUT ;
    USE SIGNAL ;
    PORT
      LAYER M3 ;
        RECT 269.2800 647.9620 269.2980 648.0000 ;
    END
  END t_s[754]
  PIN t_s[755]
    DIRECTION OUTPUT ;
    USE SIGNAL ;
    PORT
      LAYER M5 ;
        RECT 269.5680 647.9160 269.5920 648.0000 ;
    END
  END t_s[755]
  PIN t_s[756]
    DIRECTION OUTPUT ;
    USE SIGNAL ;
    PORT
      LAYER M3 ;
        RECT 269.8920 647.9620 269.9100 648.0000 ;
    END
  END t_s[756]
  PIN t_s[757]
    DIRECTION OUTPUT ;
    USE SIGNAL ;
    PORT
      LAYER M5 ;
        RECT 270.1920 647.9160 270.2160 648.0000 ;
    END
  END t_s[757]
  PIN t_s[758]
    DIRECTION OUTPUT ;
    USE SIGNAL ;
    PORT
      LAYER M3 ;
        RECT 270.4680 647.9620 270.4860 648.0000 ;
    END
  END t_s[758]
  PIN t_s[759]
    DIRECTION OUTPUT ;
    USE SIGNAL ;
    PORT
      LAYER M5 ;
        RECT 270.7680 647.9160 270.7920 648.0000 ;
    END
  END t_s[759]
  PIN t_s[75]
    DIRECTION OUTPUT ;
    USE SIGNAL ;
    PORT
      LAYER M5 ;
        RECT 65.8080 647.9160 65.8320 648.0000 ;
    END
  END t_s[75]
  PIN t_s[760]
    DIRECTION OUTPUT ;
    USE SIGNAL ;
    PORT
      LAYER M3 ;
        RECT 271.0800 647.9620 271.0980 648.0000 ;
    END
  END t_s[760]
  PIN t_s[761]
    DIRECTION OUTPUT ;
    USE SIGNAL ;
    PORT
      LAYER M5 ;
        RECT 271.3920 647.9160 271.4160 648.0000 ;
    END
  END t_s[761]
  PIN t_s[762]
    DIRECTION OUTPUT ;
    USE SIGNAL ;
    PORT
      LAYER M3 ;
        RECT 271.6920 647.9620 271.7100 648.0000 ;
    END
  END t_s[762]
  PIN t_s[763]
    DIRECTION OUTPUT ;
    USE SIGNAL ;
    PORT
      LAYER M5 ;
        RECT 271.9680 647.9160 271.9920 648.0000 ;
    END
  END t_s[763]
  PIN t_s[764]
    DIRECTION OUTPUT ;
    USE SIGNAL ;
    PORT
      LAYER M3 ;
        RECT 272.2680 647.9620 272.2860 648.0000 ;
    END
  END t_s[764]
  PIN t_s[765]
    DIRECTION OUTPUT ;
    USE SIGNAL ;
    PORT
      LAYER M5 ;
        RECT 272.5920 647.9160 272.6160 648.0000 ;
    END
  END t_s[765]
  PIN t_s[766]
    DIRECTION OUTPUT ;
    USE SIGNAL ;
    PORT
      LAYER M3 ;
        RECT 272.8800 647.9620 272.8980 648.0000 ;
    END
  END t_s[766]
  PIN t_s[767]
    DIRECTION OUTPUT ;
    USE SIGNAL ;
    PORT
      LAYER M5 ;
        RECT 273.1680 647.9160 273.1920 648.0000 ;
    END
  END t_s[767]
  PIN t_s[768]
    DIRECTION OUTPUT ;
    USE SIGNAL ;
    PORT
      LAYER M3 ;
        RECT 273.4920 647.9620 273.5100 648.0000 ;
    END
  END t_s[768]
  PIN t_s[769]
    DIRECTION OUTPUT ;
    USE SIGNAL ;
    PORT
      LAYER M5 ;
        RECT 273.7920 647.9160 273.8160 648.0000 ;
    END
  END t_s[769]
  PIN t_s[76]
    DIRECTION OUTPUT ;
    USE SIGNAL ;
    PORT
      LAYER M3 ;
        RECT 66.1320 647.9620 66.1500 648.0000 ;
    END
  END t_s[76]
  PIN t_s[770]
    DIRECTION OUTPUT ;
    USE SIGNAL ;
    PORT
      LAYER M3 ;
        RECT 274.0680 647.9620 274.0860 648.0000 ;
    END
  END t_s[770]
  PIN t_s[771]
    DIRECTION OUTPUT ;
    USE SIGNAL ;
    PORT
      LAYER M5 ;
        RECT 274.3680 647.9160 274.3920 648.0000 ;
    END
  END t_s[771]
  PIN t_s[772]
    DIRECTION OUTPUT ;
    USE SIGNAL ;
    PORT
      LAYER M3 ;
        RECT 274.6800 647.9620 274.6980 648.0000 ;
    END
  END t_s[772]
  PIN t_s[773]
    DIRECTION OUTPUT ;
    USE SIGNAL ;
    PORT
      LAYER M5 ;
        RECT 274.9920 647.9160 275.0160 648.0000 ;
    END
  END t_s[773]
  PIN t_s[774]
    DIRECTION OUTPUT ;
    USE SIGNAL ;
    PORT
      LAYER M3 ;
        RECT 275.2560 647.9620 275.2740 648.0000 ;
    END
  END t_s[774]
  PIN t_s[775]
    DIRECTION OUTPUT ;
    USE SIGNAL ;
    PORT
      LAYER M5 ;
        RECT 275.5680 647.9160 275.5920 648.0000 ;
    END
  END t_s[775]
  PIN t_s[776]
    DIRECTION OUTPUT ;
    USE SIGNAL ;
    PORT
      LAYER M3 ;
        RECT 275.8680 647.9620 275.8860 648.0000 ;
    END
  END t_s[776]
  PIN t_s[777]
    DIRECTION OUTPUT ;
    USE SIGNAL ;
    PORT
      LAYER M5 ;
        RECT 276.1920 647.9160 276.2160 648.0000 ;
    END
  END t_s[777]
  PIN t_s[778]
    DIRECTION OUTPUT ;
    USE SIGNAL ;
    PORT
      LAYER M3 ;
        RECT 276.4800 647.9620 276.4980 648.0000 ;
    END
  END t_s[778]
  PIN t_s[779]
    DIRECTION OUTPUT ;
    USE SIGNAL ;
    PORT
      LAYER M5 ;
        RECT 276.7680 647.9160 276.7920 648.0000 ;
    END
  END t_s[779]
  PIN t_s[77]
    DIRECTION OUTPUT ;
    USE SIGNAL ;
    PORT
      LAYER M5 ;
        RECT 66.4320 647.9160 66.4560 648.0000 ;
    END
  END t_s[77]
  PIN t_s[780]
    DIRECTION OUTPUT ;
    USE SIGNAL ;
    PORT
      LAYER M3 ;
        RECT 277.0560 647.9620 277.0740 648.0000 ;
    END
  END t_s[780]
  PIN t_s[781]
    DIRECTION OUTPUT ;
    USE SIGNAL ;
    PORT
      LAYER M5 ;
        RECT 277.3440 647.9160 277.3680 648.0000 ;
    END
  END t_s[781]
  PIN t_s[782]
    DIRECTION OUTPUT ;
    USE SIGNAL ;
    PORT
      LAYER M3 ;
        RECT 277.6680 647.9620 277.6860 648.0000 ;
    END
  END t_s[782]
  PIN t_s[783]
    DIRECTION OUTPUT ;
    USE SIGNAL ;
    PORT
      LAYER M5 ;
        RECT 277.9680 647.9160 277.9920 648.0000 ;
    END
  END t_s[783]
  PIN t_s[784]
    DIRECTION OUTPUT ;
    USE SIGNAL ;
    PORT
      LAYER M3 ;
        RECT 278.2800 647.9620 278.2980 648.0000 ;
    END
  END t_s[784]
  PIN t_s[785]
    DIRECTION OUTPUT ;
    USE SIGNAL ;
    PORT
      LAYER M5 ;
        RECT 278.5440 647.9160 278.5680 648.0000 ;
    END
  END t_s[785]
  PIN t_s[786]
    DIRECTION OUTPUT ;
    USE SIGNAL ;
    PORT
      LAYER M3 ;
        RECT 278.8560 647.9620 278.8740 648.0000 ;
    END
  END t_s[786]
  PIN t_s[787]
    DIRECTION OUTPUT ;
    USE SIGNAL ;
    PORT
      LAYER M5 ;
        RECT 279.1680 647.9160 279.1920 648.0000 ;
    END
  END t_s[787]
  PIN t_s[788]
    DIRECTION OUTPUT ;
    USE SIGNAL ;
    PORT
      LAYER M3 ;
        RECT 279.4680 647.9620 279.4860 648.0000 ;
    END
  END t_s[788]
  PIN t_s[789]
    DIRECTION OUTPUT ;
    USE SIGNAL ;
    PORT
      LAYER M5 ;
        RECT 279.7440 647.9160 279.7680 648.0000 ;
    END
  END t_s[789]
  PIN t_s[78]
    DIRECTION OUTPUT ;
    USE SIGNAL ;
    PORT
      LAYER M3 ;
        RECT 66.7080 647.9620 66.7260 648.0000 ;
    END
  END t_s[78]
  PIN t_s[790]
    DIRECTION OUTPUT ;
    USE SIGNAL ;
    PORT
      LAYER M3 ;
        RECT 280.0800 647.9620 280.0980 648.0000 ;
    END
  END t_s[790]
  PIN t_s[791]
    DIRECTION OUTPUT ;
    USE SIGNAL ;
    PORT
      LAYER M5 ;
        RECT 280.3680 647.9160 280.3920 648.0000 ;
    END
  END t_s[791]
  PIN t_s[792]
    DIRECTION OUTPUT ;
    USE SIGNAL ;
    PORT
      LAYER M3 ;
        RECT 280.6560 647.9620 280.6740 648.0000 ;
    END
  END t_s[792]
  PIN t_s[793]
    DIRECTION OUTPUT ;
    USE SIGNAL ;
    PORT
      LAYER M5 ;
        RECT 280.9440 647.9160 280.9680 648.0000 ;
    END
  END t_s[793]
  PIN t_s[794]
    DIRECTION OUTPUT ;
    USE SIGNAL ;
    PORT
      LAYER M3 ;
        RECT 281.2680 647.9620 281.2860 648.0000 ;
    END
  END t_s[794]
  PIN t_s[795]
    DIRECTION OUTPUT ;
    USE SIGNAL ;
    PORT
      LAYER M5 ;
        RECT 281.5680 647.9160 281.5920 648.0000 ;
    END
  END t_s[795]
  PIN t_s[796]
    DIRECTION OUTPUT ;
    USE SIGNAL ;
    PORT
      LAYER M3 ;
        RECT 281.8800 647.9620 281.8980 648.0000 ;
    END
  END t_s[796]
  PIN t_s[797]
    DIRECTION OUTPUT ;
    USE SIGNAL ;
    PORT
      LAYER M5 ;
        RECT 282.1440 647.9160 282.1680 648.0000 ;
    END
  END t_s[797]
  PIN t_s[798]
    DIRECTION OUTPUT ;
    USE SIGNAL ;
    PORT
      LAYER M3 ;
        RECT 282.4560 647.9620 282.4740 648.0000 ;
    END
  END t_s[798]
  PIN t_s[799]
    DIRECTION OUTPUT ;
    USE SIGNAL ;
    PORT
      LAYER M5 ;
        RECT 282.7680 647.9160 282.7920 648.0000 ;
    END
  END t_s[799]
  PIN t_s[79]
    DIRECTION OUTPUT ;
    USE SIGNAL ;
    PORT
      LAYER M5 ;
        RECT 67.0080 647.9160 67.0320 648.0000 ;
    END
  END t_s[79]
  PIN t_s[7]
    DIRECTION OUTPUT ;
    USE SIGNAL ;
    PORT
      LAYER M5 ;
        RECT 45.4560 647.9160 45.4800 648.0000 ;
    END
  END t_s[7]
  PIN t_s[800]
    DIRECTION OUTPUT ;
    USE SIGNAL ;
    PORT
      LAYER M3 ;
        RECT 283.0680 647.9620 283.0860 648.0000 ;
    END
  END t_s[800]
  PIN t_s[801]
    DIRECTION OUTPUT ;
    USE SIGNAL ;
    PORT
      LAYER M5 ;
        RECT 283.3440 647.9160 283.3680 648.0000 ;
    END
  END t_s[801]
  PIN t_s[802]
    DIRECTION OUTPUT ;
    USE SIGNAL ;
    PORT
      LAYER M3 ;
        RECT 283.6800 647.9620 283.6980 648.0000 ;
    END
  END t_s[802]
  PIN t_s[803]
    DIRECTION OUTPUT ;
    USE SIGNAL ;
    PORT
      LAYER M5 ;
        RECT 283.9680 647.9160 283.9920 648.0000 ;
    END
  END t_s[803]
  PIN t_s[804]
    DIRECTION OUTPUT ;
    USE SIGNAL ;
    PORT
      LAYER M3 ;
        RECT 284.2560 647.9620 284.2740 648.0000 ;
    END
  END t_s[804]
  PIN t_s[805]
    DIRECTION OUTPUT ;
    USE SIGNAL ;
    PORT
      LAYER M5 ;
        RECT 284.5440 647.9160 284.5680 648.0000 ;
    END
  END t_s[805]
  PIN t_s[806]
    DIRECTION OUTPUT ;
    USE SIGNAL ;
    PORT
      LAYER M3 ;
        RECT 284.8680 647.9620 284.8860 648.0000 ;
    END
  END t_s[806]
  PIN t_s[807]
    DIRECTION OUTPUT ;
    USE SIGNAL ;
    PORT
      LAYER M5 ;
        RECT 285.1680 647.9160 285.1920 648.0000 ;
    END
  END t_s[807]
  PIN t_s[808]
    DIRECTION OUTPUT ;
    USE SIGNAL ;
    PORT
      LAYER M3 ;
        RECT 285.4440 647.9620 285.4620 648.0000 ;
    END
  END t_s[808]
  PIN t_s[809]
    DIRECTION OUTPUT ;
    USE SIGNAL ;
    PORT
      LAYER M5 ;
        RECT 285.7440 647.9160 285.7680 648.0000 ;
    END
  END t_s[809]
  PIN t_s[80]
    DIRECTION OUTPUT ;
    USE SIGNAL ;
    PORT
      LAYER M3 ;
        RECT 67.3200 647.9620 67.3380 648.0000 ;
    END
  END t_s[80]
  PIN t_s[810]
    DIRECTION OUTPUT ;
    USE SIGNAL ;
    PORT
      LAYER M3 ;
        RECT 286.0560 647.9620 286.0740 648.0000 ;
    END
  END t_s[810]
  PIN t_s[811]
    DIRECTION OUTPUT ;
    USE SIGNAL ;
    PORT
      LAYER M5 ;
        RECT 286.3680 647.9160 286.3920 648.0000 ;
    END
  END t_s[811]
  PIN t_s[812]
    DIRECTION OUTPUT ;
    USE SIGNAL ;
    PORT
      LAYER M3 ;
        RECT 286.6680 647.9620 286.6860 648.0000 ;
    END
  END t_s[812]
  PIN t_s[813]
    DIRECTION OUTPUT ;
    USE SIGNAL ;
    PORT
      LAYER M5 ;
        RECT 286.9440 647.9160 286.9680 648.0000 ;
    END
  END t_s[813]
  PIN t_s[814]
    DIRECTION OUTPUT ;
    USE SIGNAL ;
    PORT
      LAYER M3 ;
        RECT 287.2440 647.9620 287.2620 648.0000 ;
    END
  END t_s[814]
  PIN t_s[815]
    DIRECTION OUTPUT ;
    USE SIGNAL ;
    PORT
      LAYER M5 ;
        RECT 287.5680 647.9160 287.5920 648.0000 ;
    END
  END t_s[815]
  PIN t_s[816]
    DIRECTION OUTPUT ;
    USE SIGNAL ;
    PORT
      LAYER M3 ;
        RECT 287.8560 647.9620 287.8740 648.0000 ;
    END
  END t_s[816]
  PIN t_s[817]
    DIRECTION OUTPUT ;
    USE SIGNAL ;
    PORT
      LAYER M5 ;
        RECT 288.1440 647.9160 288.1680 648.0000 ;
    END
  END t_s[817]
  PIN t_s[818]
    DIRECTION OUTPUT ;
    USE SIGNAL ;
    PORT
      LAYER M3 ;
        RECT 288.4680 647.9620 288.4860 648.0000 ;
    END
  END t_s[818]
  PIN t_s[819]
    DIRECTION OUTPUT ;
    USE SIGNAL ;
    PORT
      LAYER M5 ;
        RECT 288.7680 647.9160 288.7920 648.0000 ;
    END
  END t_s[819]
  PIN t_s[81]
    DIRECTION OUTPUT ;
    USE SIGNAL ;
    PORT
      LAYER M5 ;
        RECT 67.6320 647.9160 67.6560 648.0000 ;
    END
  END t_s[81]
  PIN t_s[820]
    DIRECTION OUTPUT ;
    USE SIGNAL ;
    PORT
      LAYER M3 ;
        RECT 289.0440 647.9620 289.0620 648.0000 ;
    END
  END t_s[820]
  PIN t_s[821]
    DIRECTION OUTPUT ;
    USE SIGNAL ;
    PORT
      LAYER M5 ;
        RECT 289.3440 647.9160 289.3680 648.0000 ;
    END
  END t_s[821]
  PIN t_s[822]
    DIRECTION OUTPUT ;
    USE SIGNAL ;
    PORT
      LAYER M3 ;
        RECT 289.6560 647.9620 289.6740 648.0000 ;
    END
  END t_s[822]
  PIN t_s[823]
    DIRECTION OUTPUT ;
    USE SIGNAL ;
    PORT
      LAYER M5 ;
        RECT 289.9680 647.9160 289.9920 648.0000 ;
    END
  END t_s[823]
  PIN t_s[824]
    DIRECTION OUTPUT ;
    USE SIGNAL ;
    PORT
      LAYER M3 ;
        RECT 290.2680 647.9620 290.2860 648.0000 ;
    END
  END t_s[824]
  PIN t_s[825]
    DIRECTION OUTPUT ;
    USE SIGNAL ;
    PORT
      LAYER M5 ;
        RECT 290.5440 647.9160 290.5680 648.0000 ;
    END
  END t_s[825]
  PIN t_s[826]
    DIRECTION OUTPUT ;
    USE SIGNAL ;
    PORT
      LAYER M3 ;
        RECT 290.8440 647.9620 290.8620 648.0000 ;
    END
  END t_s[826]
  PIN t_s[827]
    DIRECTION OUTPUT ;
    USE SIGNAL ;
    PORT
      LAYER M5 ;
        RECT 291.1680 647.9160 291.1920 648.0000 ;
    END
  END t_s[827]
  PIN t_s[828]
    DIRECTION OUTPUT ;
    USE SIGNAL ;
    PORT
      LAYER M3 ;
        RECT 291.4560 647.9620 291.4740 648.0000 ;
    END
  END t_s[828]
  PIN t_s[829]
    DIRECTION OUTPUT ;
    USE SIGNAL ;
    PORT
      LAYER M5 ;
        RECT 291.7440 647.9160 291.7680 648.0000 ;
    END
  END t_s[829]
  PIN t_s[82]
    DIRECTION OUTPUT ;
    USE SIGNAL ;
    PORT
      LAYER M3 ;
        RECT 67.8960 647.9620 67.9140 648.0000 ;
    END
  END t_s[82]
  PIN t_s[830]
    DIRECTION OUTPUT ;
    USE SIGNAL ;
    PORT
      LAYER M3 ;
        RECT 292.0680 647.9620 292.0860 648.0000 ;
    END
  END t_s[830]
  PIN t_s[831]
    DIRECTION OUTPUT ;
    USE SIGNAL ;
    PORT
      LAYER M5 ;
        RECT 292.3680 647.9160 292.3920 648.0000 ;
    END
  END t_s[831]
  PIN t_s[832]
    DIRECTION OUTPUT ;
    USE SIGNAL ;
    PORT
      LAYER M3 ;
        RECT 292.6440 647.9620 292.6620 648.0000 ;
    END
  END t_s[832]
  PIN t_s[833]
    DIRECTION OUTPUT ;
    USE SIGNAL ;
    PORT
      LAYER M5 ;
        RECT 292.9440 647.9160 292.9680 648.0000 ;
    END
  END t_s[833]
  PIN t_s[834]
    DIRECTION OUTPUT ;
    USE SIGNAL ;
    PORT
      LAYER M3 ;
        RECT 293.2560 647.9620 293.2740 648.0000 ;
    END
  END t_s[834]
  PIN t_s[835]
    DIRECTION OUTPUT ;
    USE SIGNAL ;
    PORT
      LAYER M5 ;
        RECT 293.5680 647.9160 293.5920 648.0000 ;
    END
  END t_s[835]
  PIN t_s[836]
    DIRECTION OUTPUT ;
    USE SIGNAL ;
    PORT
      LAYER M3 ;
        RECT 293.8680 647.9620 293.8860 648.0000 ;
    END
  END t_s[836]
  PIN t_s[837]
    DIRECTION OUTPUT ;
    USE SIGNAL ;
    PORT
      LAYER M5 ;
        RECT 294.1440 647.9160 294.1680 648.0000 ;
    END
  END t_s[837]
  PIN t_s[838]
    DIRECTION OUTPUT ;
    USE SIGNAL ;
    PORT
      LAYER M3 ;
        RECT 294.4440 647.9620 294.4620 648.0000 ;
    END
  END t_s[838]
  PIN t_s[839]
    DIRECTION OUTPUT ;
    USE SIGNAL ;
    PORT
      LAYER M5 ;
        RECT 294.7680 647.9160 294.7920 648.0000 ;
    END
  END t_s[839]
  PIN t_s[83]
    DIRECTION OUTPUT ;
    USE SIGNAL ;
    PORT
      LAYER M5 ;
        RECT 68.2080 647.9160 68.2320 648.0000 ;
    END
  END t_s[83]
  PIN t_s[840]
    DIRECTION OUTPUT ;
    USE SIGNAL ;
    PORT
      LAYER M3 ;
        RECT 295.0560 647.9620 295.0740 648.0000 ;
    END
  END t_s[840]
  PIN t_s[841]
    DIRECTION OUTPUT ;
    USE SIGNAL ;
    PORT
      LAYER M5 ;
        RECT 295.3440 647.9160 295.3680 648.0000 ;
    END
  END t_s[841]
  PIN t_s[842]
    DIRECTION OUTPUT ;
    USE SIGNAL ;
    PORT
      LAYER M3 ;
        RECT 295.6320 647.9620 295.6500 648.0000 ;
    END
  END t_s[842]
  PIN t_s[843]
    DIRECTION OUTPUT ;
    USE SIGNAL ;
    PORT
      LAYER M5 ;
        RECT 295.9680 647.9160 295.9920 648.0000 ;
    END
  END t_s[843]
  PIN t_s[844]
    DIRECTION OUTPUT ;
    USE SIGNAL ;
    PORT
      LAYER M3 ;
        RECT 296.2440 647.9620 296.2620 648.0000 ;
    END
  END t_s[844]
  PIN t_s[845]
    DIRECTION OUTPUT ;
    USE SIGNAL ;
    PORT
      LAYER M5 ;
        RECT 296.5440 647.9160 296.5680 648.0000 ;
    END
  END t_s[845]
  PIN t_s[846]
    DIRECTION OUTPUT ;
    USE SIGNAL ;
    PORT
      LAYER M3 ;
        RECT 296.8560 647.9620 296.8740 648.0000 ;
    END
  END t_s[846]
  PIN t_s[847]
    DIRECTION OUTPUT ;
    USE SIGNAL ;
    PORT
      LAYER M5 ;
        RECT 297.1680 647.9160 297.1920 648.0000 ;
    END
  END t_s[847]
  PIN t_s[848]
    DIRECTION OUTPUT ;
    USE SIGNAL ;
    PORT
      LAYER M3 ;
        RECT 297.4320 647.9620 297.4500 648.0000 ;
    END
  END t_s[848]
  PIN t_s[849]
    DIRECTION OUTPUT ;
    USE SIGNAL ;
    PORT
      LAYER M5 ;
        RECT 297.7440 647.9160 297.7680 648.0000 ;
    END
  END t_s[849]
  PIN t_s[84]
    DIRECTION OUTPUT ;
    USE SIGNAL ;
    PORT
      LAYER M3 ;
        RECT 68.5080 647.9620 68.5260 648.0000 ;
    END
  END t_s[84]
  PIN t_s[850]
    DIRECTION OUTPUT ;
    USE SIGNAL ;
    PORT
      LAYER M3 ;
        RECT 298.0440 647.9620 298.0620 648.0000 ;
    END
  END t_s[850]
  PIN t_s[851]
    DIRECTION OUTPUT ;
    USE SIGNAL ;
    PORT
      LAYER M5 ;
        RECT 298.3200 647.9160 298.3440 648.0000 ;
    END
  END t_s[851]
  PIN t_s[852]
    DIRECTION OUTPUT ;
    USE SIGNAL ;
    PORT
      LAYER M3 ;
        RECT 298.6560 647.9620 298.6740 648.0000 ;
    END
  END t_s[852]
  PIN t_s[853]
    DIRECTION OUTPUT ;
    USE SIGNAL ;
    PORT
      LAYER M5 ;
        RECT 298.9440 647.9160 298.9680 648.0000 ;
    END
  END t_s[853]
  PIN t_s[854]
    DIRECTION OUTPUT ;
    USE SIGNAL ;
    PORT
      LAYER M3 ;
        RECT 299.2320 647.9620 299.2500 648.0000 ;
    END
  END t_s[854]
  PIN t_s[855]
    DIRECTION OUTPUT ;
    USE SIGNAL ;
    PORT
      LAYER M5 ;
        RECT 299.5200 647.9160 299.5440 648.0000 ;
    END
  END t_s[855]
  PIN t_s[856]
    DIRECTION OUTPUT ;
    USE SIGNAL ;
    PORT
      LAYER M3 ;
        RECT 299.8440 647.9620 299.8620 648.0000 ;
    END
  END t_s[856]
  PIN t_s[857]
    DIRECTION OUTPUT ;
    USE SIGNAL ;
    PORT
      LAYER M5 ;
        RECT 300.1440 647.9160 300.1680 648.0000 ;
    END
  END t_s[857]
  PIN t_s[858]
    DIRECTION OUTPUT ;
    USE SIGNAL ;
    PORT
      LAYER M3 ;
        RECT 300.4560 647.9620 300.4740 648.0000 ;
    END
  END t_s[858]
  PIN t_s[859]
    DIRECTION OUTPUT ;
    USE SIGNAL ;
    PORT
      LAYER M5 ;
        RECT 300.7200 647.9160 300.7440 648.0000 ;
    END
  END t_s[859]
  PIN t_s[85]
    DIRECTION OUTPUT ;
    USE SIGNAL ;
    PORT
      LAYER M5 ;
        RECT 68.8320 647.9160 68.8560 648.0000 ;
    END
  END t_s[85]
  PIN t_s[860]
    DIRECTION OUTPUT ;
    USE SIGNAL ;
    PORT
      LAYER M3 ;
        RECT 301.0320 647.9620 301.0500 648.0000 ;
    END
  END t_s[860]
  PIN t_s[861]
    DIRECTION OUTPUT ;
    USE SIGNAL ;
    PORT
      LAYER M5 ;
        RECT 301.3440 647.9160 301.3680 648.0000 ;
    END
  END t_s[861]
  PIN t_s[862]
    DIRECTION OUTPUT ;
    USE SIGNAL ;
    PORT
      LAYER M3 ;
        RECT 301.6440 647.9620 301.6620 648.0000 ;
    END
  END t_s[862]
  PIN t_s[863]
    DIRECTION OUTPUT ;
    USE SIGNAL ;
    PORT
      LAYER M5 ;
        RECT 301.9200 647.9160 301.9440 648.0000 ;
    END
  END t_s[863]
  PIN t_s[864]
    DIRECTION OUTPUT ;
    USE SIGNAL ;
    PORT
      LAYER M3 ;
        RECT 302.2560 647.9620 302.2740 648.0000 ;
    END
  END t_s[864]
  PIN t_s[86]
    DIRECTION OUTPUT ;
    USE SIGNAL ;
    PORT
      LAYER M3 ;
        RECT 69.1200 647.9620 69.1380 648.0000 ;
    END
  END t_s[86]
  PIN t_s[87]
    DIRECTION OUTPUT ;
    USE SIGNAL ;
    PORT
      LAYER M5 ;
        RECT 69.4080 647.9160 69.4320 648.0000 ;
    END
  END t_s[87]
  PIN t_s[88]
    DIRECTION OUTPUT ;
    USE SIGNAL ;
    PORT
      LAYER M3 ;
        RECT 69.6960 647.9620 69.7140 648.0000 ;
    END
  END t_s[88]
  PIN t_s[89]
    DIRECTION OUTPUT ;
    USE SIGNAL ;
    PORT
      LAYER M5 ;
        RECT 69.9840 647.9160 70.0080 648.0000 ;
    END
  END t_s[89]
  PIN t_s[8]
    DIRECTION OUTPUT ;
    USE SIGNAL ;
    PORT
      LAYER M3 ;
        RECT 45.7560 647.9620 45.7740 648.0000 ;
    END
  END t_s[8]
  PIN t_s[90]
    DIRECTION OUTPUT ;
    USE SIGNAL ;
    PORT
      LAYER M3 ;
        RECT 70.3080 647.9620 70.3260 648.0000 ;
    END
  END t_s[90]
  PIN t_s[91]
    DIRECTION OUTPUT ;
    USE SIGNAL ;
    PORT
      LAYER M5 ;
        RECT 70.6080 647.9160 70.6320 648.0000 ;
    END
  END t_s[91]
  PIN t_s[92]
    DIRECTION OUTPUT ;
    USE SIGNAL ;
    PORT
      LAYER M3 ;
        RECT 70.9200 647.9620 70.9380 648.0000 ;
    END
  END t_s[92]
  PIN t_s[93]
    DIRECTION OUTPUT ;
    USE SIGNAL ;
    PORT
      LAYER M5 ;
        RECT 71.1840 647.9160 71.2080 648.0000 ;
    END
  END t_s[93]
  PIN t_s[94]
    DIRECTION OUTPUT ;
    USE SIGNAL ;
    PORT
      LAYER M3 ;
        RECT 71.4960 647.9620 71.5140 648.0000 ;
    END
  END t_s[94]
  PIN t_s[95]
    DIRECTION OUTPUT ;
    USE SIGNAL ;
    PORT
      LAYER M5 ;
        RECT 71.8080 647.9160 71.8320 648.0000 ;
    END
  END t_s[95]
  PIN t_s[96]
    DIRECTION OUTPUT ;
    USE SIGNAL ;
    PORT
      LAYER M3 ;
        RECT 72.1080 647.9620 72.1260 648.0000 ;
    END
  END t_s[96]
  PIN t_s[97]
    DIRECTION OUTPUT ;
    USE SIGNAL ;
    PORT
      LAYER M5 ;
        RECT 72.3840 647.9160 72.4080 648.0000 ;
    END
  END t_s[97]
  PIN t_s[98]
    DIRECTION OUTPUT ;
    USE SIGNAL ;
    PORT
      LAYER M3 ;
        RECT 72.7200 647.9620 72.7380 648.0000 ;
    END
  END t_s[98]
  PIN t_s[99]
    DIRECTION OUTPUT ;
    USE SIGNAL ;
    PORT
      LAYER M5 ;
        RECT 73.0080 647.9160 73.0320 648.0000 ;
    END
  END t_s[99]
  PIN t_s[9]
    DIRECTION OUTPUT ;
    USE SIGNAL ;
    PORT
      LAYER M5 ;
        RECT 46.0320 647.9160 46.0560 648.0000 ;
    END
  END t_s[9]
END dsdv_bksel_q
END LIBRARY
